VERSION 5.8 ;
BUSBITCHARS "[]" ;
DIVIDERCHAR "/" ;
UNITS
    DATABASE MICRONS 1000 ;
END UNITS

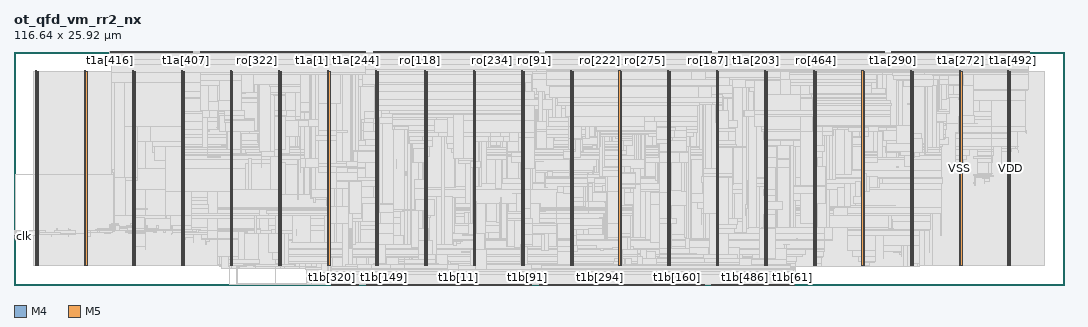
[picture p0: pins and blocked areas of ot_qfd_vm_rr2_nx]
MACRO ot_qfd_vm_rr2_nx
  FOREIGN ot_qfd_vm_rr2_nx 0 0 ;
  CLASS BLOCK ;
  SIZE 116.64 BY 25.92 ;
  PIN clk
    DIRECTION INPUT ;
    USE SIGNAL ;
    PORT
      LAYER M4 ;
        RECT  0 5.424 0.084 5.448 ;
    END
  END clk
  PIN ro[0]
    DIRECTION OUTPUT ;
    USE SIGNAL ;
    PORT
      LAYER M5 ;
        RECT  46.032 25.836 46.056 25.92 ;
    END
  END ro[0]
  PIN ro[100]
    DIRECTION OUTPUT ;
    USE SIGNAL ;
    PORT
      LAYER M5 ;
        RECT  43.344 25.836 43.368 25.92 ;
    END
  END ro[100]
  PIN ro[101]
    DIRECTION OUTPUT ;
    USE SIGNAL ;
    PORT
      LAYER M5 ;
        RECT  43.44 25.836 43.464 25.92 ;
    END
  END ro[101]
  PIN ro[102]
    DIRECTION OUTPUT ;
    USE SIGNAL ;
    PORT
      LAYER M5 ;
        RECT  43.536 25.836 43.56 25.92 ;
    END
  END ro[102]
  PIN ro[103]
    DIRECTION OUTPUT ;
    USE SIGNAL ;
    PORT
      LAYER M5 ;
        RECT  43.632 25.836 43.656 25.92 ;
    END
  END ro[103]
  PIN ro[104]
    DIRECTION OUTPUT ;
    USE SIGNAL ;
    PORT
      LAYER M5 ;
        RECT  43.728 25.836 43.752 25.92 ;
    END
  END ro[104]
  PIN ro[105]
    DIRECTION OUTPUT ;
    USE SIGNAL ;
    PORT
      LAYER M5 ;
        RECT  43.824 25.836 43.848 25.92 ;
    END
  END ro[105]
  PIN ro[106]
    DIRECTION OUTPUT ;
    USE SIGNAL ;
    PORT
      LAYER M5 ;
        RECT  43.92 25.836 43.944 25.92 ;
    END
  END ro[106]
  PIN ro[107]
    DIRECTION OUTPUT ;
    USE SIGNAL ;
    PORT
      LAYER M5 ;
        RECT  44.016 25.836 44.04 25.92 ;
    END
  END ro[107]
  PIN ro[108]
    DIRECTION OUTPUT ;
    USE SIGNAL ;
    PORT
      LAYER M5 ;
        RECT  44.112 25.836 44.136 25.92 ;
    END
  END ro[108]
  PIN ro[109]
    DIRECTION OUTPUT ;
    USE SIGNAL ;
    PORT
      LAYER M5 ;
        RECT  44.208 25.836 44.232 25.92 ;
    END
  END ro[109]
  PIN ro[10]
    DIRECTION OUTPUT ;
    USE SIGNAL ;
    PORT
      LAYER M5 ;
        RECT  46.992 25.836 47.016 25.92 ;
    END
  END ro[10]
  PIN ro[110]
    DIRECTION OUTPUT ;
    USE SIGNAL ;
    PORT
      LAYER M5 ;
        RECT  44.304 25.836 44.328 25.92 ;
    END
  END ro[110]
  PIN ro[111]
    DIRECTION OUTPUT ;
    USE SIGNAL ;
    PORT
      LAYER M5 ;
        RECT  44.4 25.836 44.424 25.92 ;
    END
  END ro[111]
  PIN ro[112]
    DIRECTION OUTPUT ;
    USE SIGNAL ;
    PORT
      LAYER M5 ;
        RECT  44.496 25.836 44.52 25.92 ;
    END
  END ro[112]
  PIN ro[113]
    DIRECTION OUTPUT ;
    USE SIGNAL ;
    PORT
      LAYER M5 ;
        RECT  44.592 25.836 44.616 25.92 ;
    END
  END ro[113]
  PIN ro[114]
    DIRECTION OUTPUT ;
    USE SIGNAL ;
    PORT
      LAYER M5 ;
        RECT  44.688 25.836 44.712 25.92 ;
    END
  END ro[114]
  PIN ro[115]
    DIRECTION OUTPUT ;
    USE SIGNAL ;
    PORT
      LAYER M5 ;
        RECT  44.784 25.836 44.808 25.92 ;
    END
  END ro[115]
  PIN ro[116]
    DIRECTION OUTPUT ;
    USE SIGNAL ;
    PORT
      LAYER M5 ;
        RECT  44.88 25.836 44.904 25.92 ;
    END
  END ro[116]
  PIN ro[117]
    DIRECTION OUTPUT ;
    USE SIGNAL ;
    PORT
      LAYER M5 ;
        RECT  44.976 25.836 45 25.92 ;
    END
  END ro[117]
  PIN ro[118]
    DIRECTION OUTPUT ;
    USE SIGNAL ;
    PORT
      LAYER M5 ;
        RECT  45.072 25.836 45.096 25.92 ;
    END
  END ro[118]
  PIN ro[119]
    DIRECTION OUTPUT ;
    USE SIGNAL ;
    PORT
      LAYER M5 ;
        RECT  45.168 25.836 45.192 25.92 ;
    END
  END ro[119]
  PIN ro[11]
    DIRECTION OUTPUT ;
    USE SIGNAL ;
    PORT
      LAYER M5 ;
        RECT  47.088 25.836 47.112 25.92 ;
    END
  END ro[11]
  PIN ro[120]
    DIRECTION OUTPUT ;
    USE SIGNAL ;
    PORT
      LAYER M5 ;
        RECT  45.264 25.836 45.288 25.92 ;
    END
  END ro[120]
  PIN ro[121]
    DIRECTION OUTPUT ;
    USE SIGNAL ;
    PORT
      LAYER M5 ;
        RECT  45.36 25.836 45.384 25.92 ;
    END
  END ro[121]
  PIN ro[122]
    DIRECTION OUTPUT ;
    USE SIGNAL ;
    PORT
      LAYER M5 ;
        RECT  45.456 25.836 45.48 25.92 ;
    END
  END ro[122]
  PIN ro[123]
    DIRECTION OUTPUT ;
    USE SIGNAL ;
    PORT
      LAYER M5 ;
        RECT  45.552 25.836 45.576 25.92 ;
    END
  END ro[123]
  PIN ro[124]
    DIRECTION OUTPUT ;
    USE SIGNAL ;
    PORT
      LAYER M5 ;
        RECT  45.648 25.836 45.672 25.92 ;
    END
  END ro[124]
  PIN ro[125]
    DIRECTION OUTPUT ;
    USE SIGNAL ;
    PORT
      LAYER M5 ;
        RECT  45.744 25.836 45.768 25.92 ;
    END
  END ro[125]
  PIN ro[126]
    DIRECTION OUTPUT ;
    USE SIGNAL ;
    PORT
      LAYER M5 ;
        RECT  45.84 25.836 45.864 25.92 ;
    END
  END ro[126]
  PIN ro[127]
    DIRECTION OUTPUT ;
    USE SIGNAL ;
    PORT
      LAYER M5 ;
        RECT  45.936 25.836 45.96 25.92 ;
    END
  END ro[127]
  PIN ro[128]
    DIRECTION OUTPUT ;
    USE SIGNAL ;
    PORT
      LAYER M5 ;
        RECT  39.888 25.836 39.912 25.92 ;
    END
  END ro[128]
  PIN ro[129]
    DIRECTION OUTPUT ;
    USE SIGNAL ;
    PORT
      LAYER M5 ;
        RECT  39.984 25.836 40.008 25.92 ;
    END
  END ro[129]
  PIN ro[12]
    DIRECTION OUTPUT ;
    USE SIGNAL ;
    PORT
      LAYER M5 ;
        RECT  47.184 25.836 47.208 25.92 ;
    END
  END ro[12]
  PIN ro[130]
    DIRECTION OUTPUT ;
    USE SIGNAL ;
    PORT
      LAYER M5 ;
        RECT  40.08 25.836 40.104 25.92 ;
    END
  END ro[130]
  PIN ro[131]
    DIRECTION OUTPUT ;
    USE SIGNAL ;
    PORT
      LAYER M5 ;
        RECT  40.176 25.836 40.2 25.92 ;
    END
  END ro[131]
  PIN ro[132]
    DIRECTION OUTPUT ;
    USE SIGNAL ;
    PORT
      LAYER M5 ;
        RECT  40.272 25.836 40.296 25.92 ;
    END
  END ro[132]
  PIN ro[133]
    DIRECTION OUTPUT ;
    USE SIGNAL ;
    PORT
      LAYER M5 ;
        RECT  40.368 25.836 40.392 25.92 ;
    END
  END ro[133]
  PIN ro[134]
    DIRECTION OUTPUT ;
    USE SIGNAL ;
    PORT
      LAYER M5 ;
        RECT  40.464 25.836 40.488 25.92 ;
    END
  END ro[134]
  PIN ro[135]
    DIRECTION OUTPUT ;
    USE SIGNAL ;
    PORT
      LAYER M5 ;
        RECT  40.56 25.836 40.584 25.92 ;
    END
  END ro[135]
  PIN ro[136]
    DIRECTION OUTPUT ;
    USE SIGNAL ;
    PORT
      LAYER M5 ;
        RECT  40.656 25.836 40.68 25.92 ;
    END
  END ro[136]
  PIN ro[137]
    DIRECTION OUTPUT ;
    USE SIGNAL ;
    PORT
      LAYER M5 ;
        RECT  40.752 25.836 40.776 25.92 ;
    END
  END ro[137]
  PIN ro[138]
    DIRECTION OUTPUT ;
    USE SIGNAL ;
    PORT
      LAYER M5 ;
        RECT  40.848 25.836 40.872 25.92 ;
    END
  END ro[138]
  PIN ro[139]
    DIRECTION OUTPUT ;
    USE SIGNAL ;
    PORT
      LAYER M5 ;
        RECT  40.944 25.836 40.968 25.92 ;
    END
  END ro[139]
  PIN ro[13]
    DIRECTION OUTPUT ;
    USE SIGNAL ;
    PORT
      LAYER M5 ;
        RECT  47.28 25.836 47.304 25.92 ;
    END
  END ro[13]
  PIN ro[140]
    DIRECTION OUTPUT ;
    USE SIGNAL ;
    PORT
      LAYER M5 ;
        RECT  41.04 25.836 41.064 25.92 ;
    END
  END ro[140]
  PIN ro[141]
    DIRECTION OUTPUT ;
    USE SIGNAL ;
    PORT
      LAYER M5 ;
        RECT  41.136 25.836 41.16 25.92 ;
    END
  END ro[141]
  PIN ro[142]
    DIRECTION OUTPUT ;
    USE SIGNAL ;
    PORT
      LAYER M5 ;
        RECT  41.232 25.836 41.256 25.92 ;
    END
  END ro[142]
  PIN ro[143]
    DIRECTION OUTPUT ;
    USE SIGNAL ;
    PORT
      LAYER M5 ;
        RECT  41.328 25.836 41.352 25.92 ;
    END
  END ro[143]
  PIN ro[144]
    DIRECTION OUTPUT ;
    USE SIGNAL ;
    PORT
      LAYER M5 ;
        RECT  41.424 25.836 41.448 25.92 ;
    END
  END ro[144]
  PIN ro[145]
    DIRECTION OUTPUT ;
    USE SIGNAL ;
    PORT
      LAYER M5 ;
        RECT  41.52 25.836 41.544 25.92 ;
    END
  END ro[145]
  PIN ro[146]
    DIRECTION OUTPUT ;
    USE SIGNAL ;
    PORT
      LAYER M5 ;
        RECT  41.616 25.836 41.64 25.92 ;
    END
  END ro[146]
  PIN ro[147]
    DIRECTION OUTPUT ;
    USE SIGNAL ;
    PORT
      LAYER M5 ;
        RECT  41.712 25.836 41.736 25.92 ;
    END
  END ro[147]
  PIN ro[148]
    DIRECTION OUTPUT ;
    USE SIGNAL ;
    PORT
      LAYER M5 ;
        RECT  41.808 25.836 41.832 25.92 ;
    END
  END ro[148]
  PIN ro[149]
    DIRECTION OUTPUT ;
    USE SIGNAL ;
    PORT
      LAYER M5 ;
        RECT  41.904 25.836 41.928 25.92 ;
    END
  END ro[149]
  PIN ro[14]
    DIRECTION OUTPUT ;
    USE SIGNAL ;
    PORT
      LAYER M5 ;
        RECT  47.376 25.836 47.4 25.92 ;
    END
  END ro[14]
  PIN ro[150]
    DIRECTION OUTPUT ;
    USE SIGNAL ;
    PORT
      LAYER M5 ;
        RECT  42 25.836 42.024 25.92 ;
    END
  END ro[150]
  PIN ro[151]
    DIRECTION OUTPUT ;
    USE SIGNAL ;
    PORT
      LAYER M5 ;
        RECT  42.096 25.836 42.12 25.92 ;
    END
  END ro[151]
  PIN ro[152]
    DIRECTION OUTPUT ;
    USE SIGNAL ;
    PORT
      LAYER M5 ;
        RECT  42.192 25.836 42.216 25.92 ;
    END
  END ro[152]
  PIN ro[153]
    DIRECTION OUTPUT ;
    USE SIGNAL ;
    PORT
      LAYER M5 ;
        RECT  42.288 25.836 42.312 25.92 ;
    END
  END ro[153]
  PIN ro[154]
    DIRECTION OUTPUT ;
    USE SIGNAL ;
    PORT
      LAYER M5 ;
        RECT  42.384 25.836 42.408 25.92 ;
    END
  END ro[154]
  PIN ro[155]
    DIRECTION OUTPUT ;
    USE SIGNAL ;
    PORT
      LAYER M5 ;
        RECT  42.48 25.836 42.504 25.92 ;
    END
  END ro[155]
  PIN ro[156]
    DIRECTION OUTPUT ;
    USE SIGNAL ;
    PORT
      LAYER M5 ;
        RECT  42.576 25.836 42.6 25.92 ;
    END
  END ro[156]
  PIN ro[157]
    DIRECTION OUTPUT ;
    USE SIGNAL ;
    PORT
      LAYER M5 ;
        RECT  42.672 25.836 42.696 25.92 ;
    END
  END ro[157]
  PIN ro[158]
    DIRECTION OUTPUT ;
    USE SIGNAL ;
    PORT
      LAYER M5 ;
        RECT  42.768 25.836 42.792 25.92 ;
    END
  END ro[158]
  PIN ro[159]
    DIRECTION OUTPUT ;
    USE SIGNAL ;
    PORT
      LAYER M5 ;
        RECT  42.864 25.836 42.888 25.92 ;
    END
  END ro[159]
  PIN ro[15]
    DIRECTION OUTPUT ;
    USE SIGNAL ;
    PORT
      LAYER M5 ;
        RECT  47.472 25.836 47.496 25.92 ;
    END
  END ro[15]
  PIN ro[160]
    DIRECTION OUTPUT ;
    USE SIGNAL ;
    PORT
      LAYER M5 ;
        RECT  74.448 25.836 74.472 25.92 ;
    END
  END ro[160]
  PIN ro[161]
    DIRECTION OUTPUT ;
    USE SIGNAL ;
    PORT
      LAYER M5 ;
        RECT  74.544 25.836 74.568 25.92 ;
    END
  END ro[161]
  PIN ro[162]
    DIRECTION OUTPUT ;
    USE SIGNAL ;
    PORT
      LAYER M5 ;
        RECT  74.64 25.836 74.664 25.92 ;
    END
  END ro[162]
  PIN ro[163]
    DIRECTION OUTPUT ;
    USE SIGNAL ;
    PORT
      LAYER M5 ;
        RECT  74.736 25.836 74.76 25.92 ;
    END
  END ro[163]
  PIN ro[164]
    DIRECTION OUTPUT ;
    USE SIGNAL ;
    PORT
      LAYER M5 ;
        RECT  74.832 25.836 74.856 25.92 ;
    END
  END ro[164]
  PIN ro[165]
    DIRECTION OUTPUT ;
    USE SIGNAL ;
    PORT
      LAYER M5 ;
        RECT  74.928 25.836 74.952 25.92 ;
    END
  END ro[165]
  PIN ro[166]
    DIRECTION OUTPUT ;
    USE SIGNAL ;
    PORT
      LAYER M5 ;
        RECT  75.024 25.836 75.048 25.92 ;
    END
  END ro[166]
  PIN ro[167]
    DIRECTION OUTPUT ;
    USE SIGNAL ;
    PORT
      LAYER M5 ;
        RECT  75.12 25.836 75.144 25.92 ;
    END
  END ro[167]
  PIN ro[168]
    DIRECTION OUTPUT ;
    USE SIGNAL ;
    PORT
      LAYER M5 ;
        RECT  75.216 25.836 75.24 25.92 ;
    END
  END ro[168]
  PIN ro[169]
    DIRECTION OUTPUT ;
    USE SIGNAL ;
    PORT
      LAYER M5 ;
        RECT  75.312 25.836 75.336 25.92 ;
    END
  END ro[169]
  PIN ro[16]
    DIRECTION OUTPUT ;
    USE SIGNAL ;
    PORT
      LAYER M5 ;
        RECT  47.568 25.836 47.592 25.92 ;
    END
  END ro[16]
  PIN ro[170]
    DIRECTION OUTPUT ;
    USE SIGNAL ;
    PORT
      LAYER M5 ;
        RECT  75.408 25.836 75.432 25.92 ;
    END
  END ro[170]
  PIN ro[171]
    DIRECTION OUTPUT ;
    USE SIGNAL ;
    PORT
      LAYER M5 ;
        RECT  75.504 25.836 75.528 25.92 ;
    END
  END ro[171]
  PIN ro[172]
    DIRECTION OUTPUT ;
    USE SIGNAL ;
    PORT
      LAYER M5 ;
        RECT  75.6 25.836 75.624 25.92 ;
    END
  END ro[172]
  PIN ro[173]
    DIRECTION OUTPUT ;
    USE SIGNAL ;
    PORT
      LAYER M5 ;
        RECT  75.696 25.836 75.72 25.92 ;
    END
  END ro[173]
  PIN ro[174]
    DIRECTION OUTPUT ;
    USE SIGNAL ;
    PORT
      LAYER M5 ;
        RECT  75.792 25.836 75.816 25.92 ;
    END
  END ro[174]
  PIN ro[175]
    DIRECTION OUTPUT ;
    USE SIGNAL ;
    PORT
      LAYER M5 ;
        RECT  75.888 25.836 75.912 25.92 ;
    END
  END ro[175]
  PIN ro[176]
    DIRECTION OUTPUT ;
    USE SIGNAL ;
    PORT
      LAYER M5 ;
        RECT  75.984 25.836 76.008 25.92 ;
    END
  END ro[176]
  PIN ro[177]
    DIRECTION OUTPUT ;
    USE SIGNAL ;
    PORT
      LAYER M5 ;
        RECT  76.08 25.836 76.104 25.92 ;
    END
  END ro[177]
  PIN ro[178]
    DIRECTION OUTPUT ;
    USE SIGNAL ;
    PORT
      LAYER M5 ;
        RECT  76.176 25.836 76.2 25.92 ;
    END
  END ro[178]
  PIN ro[179]
    DIRECTION OUTPUT ;
    USE SIGNAL ;
    PORT
      LAYER M5 ;
        RECT  76.272 25.836 76.296 25.92 ;
    END
  END ro[179]
  PIN ro[17]
    DIRECTION OUTPUT ;
    USE SIGNAL ;
    PORT
      LAYER M5 ;
        RECT  47.664 25.836 47.688 25.92 ;
    END
  END ro[17]
  PIN ro[180]
    DIRECTION OUTPUT ;
    USE SIGNAL ;
    PORT
      LAYER M5 ;
        RECT  76.368 25.836 76.392 25.92 ;
    END
  END ro[180]
  PIN ro[181]
    DIRECTION OUTPUT ;
    USE SIGNAL ;
    PORT
      LAYER M5 ;
        RECT  76.464 25.836 76.488 25.92 ;
    END
  END ro[181]
  PIN ro[182]
    DIRECTION OUTPUT ;
    USE SIGNAL ;
    PORT
      LAYER M5 ;
        RECT  76.56 25.836 76.584 25.92 ;
    END
  END ro[182]
  PIN ro[183]
    DIRECTION OUTPUT ;
    USE SIGNAL ;
    PORT
      LAYER M5 ;
        RECT  76.656 25.836 76.68 25.92 ;
    END
  END ro[183]
  PIN ro[184]
    DIRECTION OUTPUT ;
    USE SIGNAL ;
    PORT
      LAYER M5 ;
        RECT  76.752 25.836 76.776 25.92 ;
    END
  END ro[184]
  PIN ro[185]
    DIRECTION OUTPUT ;
    USE SIGNAL ;
    PORT
      LAYER M5 ;
        RECT  76.848 25.836 76.872 25.92 ;
    END
  END ro[185]
  PIN ro[186]
    DIRECTION OUTPUT ;
    USE SIGNAL ;
    PORT
      LAYER M5 ;
        RECT  76.944 25.836 76.968 25.92 ;
    END
  END ro[186]
  PIN ro[187]
    DIRECTION OUTPUT ;
    USE SIGNAL ;
    PORT
      LAYER M5 ;
        RECT  77.04 25.836 77.064 25.92 ;
    END
  END ro[187]
  PIN ro[188]
    DIRECTION OUTPUT ;
    USE SIGNAL ;
    PORT
      LAYER M5 ;
        RECT  77.136 25.836 77.16 25.92 ;
    END
  END ro[188]
  PIN ro[189]
    DIRECTION OUTPUT ;
    USE SIGNAL ;
    PORT
      LAYER M5 ;
        RECT  77.232 25.836 77.256 25.92 ;
    END
  END ro[189]
  PIN ro[18]
    DIRECTION OUTPUT ;
    USE SIGNAL ;
    PORT
      LAYER M5 ;
        RECT  47.76 25.836 47.784 25.92 ;
    END
  END ro[18]
  PIN ro[190]
    DIRECTION OUTPUT ;
    USE SIGNAL ;
    PORT
      LAYER M5 ;
        RECT  77.328 25.836 77.352 25.92 ;
    END
  END ro[190]
  PIN ro[191]
    DIRECTION OUTPUT ;
    USE SIGNAL ;
    PORT
      LAYER M5 ;
        RECT  77.424 25.836 77.448 25.92 ;
    END
  END ro[191]
  PIN ro[192]
    DIRECTION OUTPUT ;
    USE SIGNAL ;
    PORT
      LAYER M5 ;
        RECT  62.16 25.836 62.184 25.92 ;
    END
  END ro[192]
  PIN ro[193]
    DIRECTION OUTPUT ;
    USE SIGNAL ;
    PORT
      LAYER M5 ;
        RECT  62.256 25.836 62.28 25.92 ;
    END
  END ro[193]
  PIN ro[194]
    DIRECTION OUTPUT ;
    USE SIGNAL ;
    PORT
      LAYER M5 ;
        RECT  62.352 25.836 62.376 25.92 ;
    END
  END ro[194]
  PIN ro[195]
    DIRECTION OUTPUT ;
    USE SIGNAL ;
    PORT
      LAYER M5 ;
        RECT  62.448 25.836 62.472 25.92 ;
    END
  END ro[195]
  PIN ro[196]
    DIRECTION OUTPUT ;
    USE SIGNAL ;
    PORT
      LAYER M5 ;
        RECT  62.544 25.836 62.568 25.92 ;
    END
  END ro[196]
  PIN ro[197]
    DIRECTION OUTPUT ;
    USE SIGNAL ;
    PORT
      LAYER M5 ;
        RECT  62.64 25.836 62.664 25.92 ;
    END
  END ro[197]
  PIN ro[198]
    DIRECTION OUTPUT ;
    USE SIGNAL ;
    PORT
      LAYER M5 ;
        RECT  62.736 25.836 62.76 25.92 ;
    END
  END ro[198]
  PIN ro[199]
    DIRECTION OUTPUT ;
    USE SIGNAL ;
    PORT
      LAYER M5 ;
        RECT  62.832 25.836 62.856 25.92 ;
    END
  END ro[199]
  PIN ro[19]
    DIRECTION OUTPUT ;
    USE SIGNAL ;
    PORT
      LAYER M5 ;
        RECT  47.856 25.836 47.88 25.92 ;
    END
  END ro[19]
  PIN ro[1]
    DIRECTION OUTPUT ;
    USE SIGNAL ;
    PORT
      LAYER M5 ;
        RECT  46.128 25.836 46.152 25.92 ;
    END
  END ro[1]
  PIN ro[200]
    DIRECTION OUTPUT ;
    USE SIGNAL ;
    PORT
      LAYER M5 ;
        RECT  62.928 25.836 62.952 25.92 ;
    END
  END ro[200]
  PIN ro[201]
    DIRECTION OUTPUT ;
    USE SIGNAL ;
    PORT
      LAYER M5 ;
        RECT  63.024 25.836 63.048 25.92 ;
    END
  END ro[201]
  PIN ro[202]
    DIRECTION OUTPUT ;
    USE SIGNAL ;
    PORT
      LAYER M5 ;
        RECT  63.12 25.836 63.144 25.92 ;
    END
  END ro[202]
  PIN ro[203]
    DIRECTION OUTPUT ;
    USE SIGNAL ;
    PORT
      LAYER M5 ;
        RECT  63.216 25.836 63.24 25.92 ;
    END
  END ro[203]
  PIN ro[204]
    DIRECTION OUTPUT ;
    USE SIGNAL ;
    PORT
      LAYER M5 ;
        RECT  63.312 25.836 63.336 25.92 ;
    END
  END ro[204]
  PIN ro[205]
    DIRECTION OUTPUT ;
    USE SIGNAL ;
    PORT
      LAYER M5 ;
        RECT  63.408 25.836 63.432 25.92 ;
    END
  END ro[205]
  PIN ro[206]
    DIRECTION OUTPUT ;
    USE SIGNAL ;
    PORT
      LAYER M5 ;
        RECT  63.504 25.836 63.528 25.92 ;
    END
  END ro[206]
  PIN ro[207]
    DIRECTION OUTPUT ;
    USE SIGNAL ;
    PORT
      LAYER M5 ;
        RECT  63.6 25.836 63.624 25.92 ;
    END
  END ro[207]
  PIN ro[208]
    DIRECTION OUTPUT ;
    USE SIGNAL ;
    PORT
      LAYER M5 ;
        RECT  63.696 25.836 63.72 25.92 ;
    END
  END ro[208]
  PIN ro[209]
    DIRECTION OUTPUT ;
    USE SIGNAL ;
    PORT
      LAYER M5 ;
        RECT  63.792 25.836 63.816 25.92 ;
    END
  END ro[209]
  PIN ro[20]
    DIRECTION OUTPUT ;
    USE SIGNAL ;
    PORT
      LAYER M5 ;
        RECT  47.952 25.836 47.976 25.92 ;
    END
  END ro[20]
  PIN ro[210]
    DIRECTION OUTPUT ;
    USE SIGNAL ;
    PORT
      LAYER M5 ;
        RECT  63.888 25.836 63.912 25.92 ;
    END
  END ro[210]
  PIN ro[211]
    DIRECTION OUTPUT ;
    USE SIGNAL ;
    PORT
      LAYER M5 ;
        RECT  63.984 25.836 64.008 25.92 ;
    END
  END ro[211]
  PIN ro[212]
    DIRECTION OUTPUT ;
    USE SIGNAL ;
    PORT
      LAYER M5 ;
        RECT  64.08 25.836 64.104 25.92 ;
    END
  END ro[212]
  PIN ro[213]
    DIRECTION OUTPUT ;
    USE SIGNAL ;
    PORT
      LAYER M5 ;
        RECT  64.176 25.836 64.2 25.92 ;
    END
  END ro[213]
  PIN ro[214]
    DIRECTION OUTPUT ;
    USE SIGNAL ;
    PORT
      LAYER M5 ;
        RECT  64.272 25.836 64.296 25.92 ;
    END
  END ro[214]
  PIN ro[215]
    DIRECTION OUTPUT ;
    USE SIGNAL ;
    PORT
      LAYER M5 ;
        RECT  64.368 25.836 64.392 25.92 ;
    END
  END ro[215]
  PIN ro[216]
    DIRECTION OUTPUT ;
    USE SIGNAL ;
    PORT
      LAYER M5 ;
        RECT  64.464 25.836 64.488 25.92 ;
    END
  END ro[216]
  PIN ro[217]
    DIRECTION OUTPUT ;
    USE SIGNAL ;
    PORT
      LAYER M5 ;
        RECT  64.56 25.836 64.584 25.92 ;
    END
  END ro[217]
  PIN ro[218]
    DIRECTION OUTPUT ;
    USE SIGNAL ;
    PORT
      LAYER M5 ;
        RECT  64.656 25.836 64.68 25.92 ;
    END
  END ro[218]
  PIN ro[219]
    DIRECTION OUTPUT ;
    USE SIGNAL ;
    PORT
      LAYER M5 ;
        RECT  64.752 25.836 64.776 25.92 ;
    END
  END ro[219]
  PIN ro[21]
    DIRECTION OUTPUT ;
    USE SIGNAL ;
    PORT
      LAYER M5 ;
        RECT  48.048 25.836 48.072 25.92 ;
    END
  END ro[21]
  PIN ro[220]
    DIRECTION OUTPUT ;
    USE SIGNAL ;
    PORT
      LAYER M5 ;
        RECT  64.848 25.836 64.872 25.92 ;
    END
  END ro[220]
  PIN ro[221]
    DIRECTION OUTPUT ;
    USE SIGNAL ;
    PORT
      LAYER M5 ;
        RECT  64.944 25.836 64.968 25.92 ;
    END
  END ro[221]
  PIN ro[222]
    DIRECTION OUTPUT ;
    USE SIGNAL ;
    PORT
      LAYER M5 ;
        RECT  65.04 25.836 65.064 25.92 ;
    END
  END ro[222]
  PIN ro[223]
    DIRECTION OUTPUT ;
    USE SIGNAL ;
    PORT
      LAYER M5 ;
        RECT  65.136 25.836 65.16 25.92 ;
    END
  END ro[223]
  PIN ro[224]
    DIRECTION OUTPUT ;
    USE SIGNAL ;
    PORT
      LAYER M5 ;
        RECT  52.176 25.836 52.2 25.92 ;
    END
  END ro[224]
  PIN ro[225]
    DIRECTION OUTPUT ;
    USE SIGNAL ;
    PORT
      LAYER M5 ;
        RECT  52.272 25.836 52.296 25.92 ;
    END
  END ro[225]
  PIN ro[226]
    DIRECTION OUTPUT ;
    USE SIGNAL ;
    PORT
      LAYER M5 ;
        RECT  52.368 25.836 52.392 25.92 ;
    END
  END ro[226]
  PIN ro[227]
    DIRECTION OUTPUT ;
    USE SIGNAL ;
    PORT
      LAYER M5 ;
        RECT  52.464 25.836 52.488 25.92 ;
    END
  END ro[227]
  PIN ro[228]
    DIRECTION OUTPUT ;
    USE SIGNAL ;
    PORT
      LAYER M5 ;
        RECT  52.56 25.836 52.584 25.92 ;
    END
  END ro[228]
  PIN ro[229]
    DIRECTION OUTPUT ;
    USE SIGNAL ;
    PORT
      LAYER M5 ;
        RECT  52.656 25.836 52.68 25.92 ;
    END
  END ro[229]
  PIN ro[22]
    DIRECTION OUTPUT ;
    USE SIGNAL ;
    PORT
      LAYER M5 ;
        RECT  48.144 25.836 48.168 25.92 ;
    END
  END ro[22]
  PIN ro[230]
    DIRECTION OUTPUT ;
    USE SIGNAL ;
    PORT
      LAYER M5 ;
        RECT  52.752 25.836 52.776 25.92 ;
    END
  END ro[230]
  PIN ro[231]
    DIRECTION OUTPUT ;
    USE SIGNAL ;
    PORT
      LAYER M5 ;
        RECT  52.848 25.836 52.872 25.92 ;
    END
  END ro[231]
  PIN ro[232]
    DIRECTION OUTPUT ;
    USE SIGNAL ;
    PORT
      LAYER M5 ;
        RECT  52.944 25.836 52.968 25.92 ;
    END
  END ro[232]
  PIN ro[233]
    DIRECTION OUTPUT ;
    USE SIGNAL ;
    PORT
      LAYER M5 ;
        RECT  53.04 25.836 53.064 25.92 ;
    END
  END ro[233]
  PIN ro[234]
    DIRECTION OUTPUT ;
    USE SIGNAL ;
    PORT
      LAYER M5 ;
        RECT  53.136 25.836 53.16 25.92 ;
    END
  END ro[234]
  PIN ro[235]
    DIRECTION OUTPUT ;
    USE SIGNAL ;
    PORT
      LAYER M5 ;
        RECT  53.232 25.836 53.256 25.92 ;
    END
  END ro[235]
  PIN ro[236]
    DIRECTION OUTPUT ;
    USE SIGNAL ;
    PORT
      LAYER M5 ;
        RECT  53.328 25.836 53.352 25.92 ;
    END
  END ro[236]
  PIN ro[237]
    DIRECTION OUTPUT ;
    USE SIGNAL ;
    PORT
      LAYER M5 ;
        RECT  53.424 25.836 53.448 25.92 ;
    END
  END ro[237]
  PIN ro[238]
    DIRECTION OUTPUT ;
    USE SIGNAL ;
    PORT
      LAYER M5 ;
        RECT  53.52 25.836 53.544 25.92 ;
    END
  END ro[238]
  PIN ro[239]
    DIRECTION OUTPUT ;
    USE SIGNAL ;
    PORT
      LAYER M5 ;
        RECT  53.616 25.836 53.64 25.92 ;
    END
  END ro[239]
  PIN ro[23]
    DIRECTION OUTPUT ;
    USE SIGNAL ;
    PORT
      LAYER M5 ;
        RECT  48.24 25.836 48.264 25.92 ;
    END
  END ro[23]
  PIN ro[240]
    DIRECTION OUTPUT ;
    USE SIGNAL ;
    PORT
      LAYER M5 ;
        RECT  53.712 25.836 53.736 25.92 ;
    END
  END ro[240]
  PIN ro[241]
    DIRECTION OUTPUT ;
    USE SIGNAL ;
    PORT
      LAYER M5 ;
        RECT  53.808 25.836 53.832 25.92 ;
    END
  END ro[241]
  PIN ro[242]
    DIRECTION OUTPUT ;
    USE SIGNAL ;
    PORT
      LAYER M5 ;
        RECT  53.904 25.836 53.928 25.92 ;
    END
  END ro[242]
  PIN ro[243]
    DIRECTION OUTPUT ;
    USE SIGNAL ;
    PORT
      LAYER M5 ;
        RECT  54 25.836 54.024 25.92 ;
    END
  END ro[243]
  PIN ro[244]
    DIRECTION OUTPUT ;
    USE SIGNAL ;
    PORT
      LAYER M5 ;
        RECT  54.096 25.836 54.12 25.92 ;
    END
  END ro[244]
  PIN ro[245]
    DIRECTION OUTPUT ;
    USE SIGNAL ;
    PORT
      LAYER M5 ;
        RECT  54.192 25.836 54.216 25.92 ;
    END
  END ro[245]
  PIN ro[246]
    DIRECTION OUTPUT ;
    USE SIGNAL ;
    PORT
      LAYER M5 ;
        RECT  54.288 25.836 54.312 25.92 ;
    END
  END ro[246]
  PIN ro[247]
    DIRECTION OUTPUT ;
    USE SIGNAL ;
    PORT
      LAYER M5 ;
        RECT  54.384 25.836 54.408 25.92 ;
    END
  END ro[247]
  PIN ro[248]
    DIRECTION OUTPUT ;
    USE SIGNAL ;
    PORT
      LAYER M5 ;
        RECT  54.48 25.836 54.504 25.92 ;
    END
  END ro[248]
  PIN ro[249]
    DIRECTION OUTPUT ;
    USE SIGNAL ;
    PORT
      LAYER M5 ;
        RECT  54.576 25.836 54.6 25.92 ;
    END
  END ro[249]
  PIN ro[24]
    DIRECTION OUTPUT ;
    USE SIGNAL ;
    PORT
      LAYER M5 ;
        RECT  48.336 25.836 48.36 25.92 ;
    END
  END ro[24]
  PIN ro[250]
    DIRECTION OUTPUT ;
    USE SIGNAL ;
    PORT
      LAYER M5 ;
        RECT  54.672 25.836 54.696 25.92 ;
    END
  END ro[250]
  PIN ro[251]
    DIRECTION OUTPUT ;
    USE SIGNAL ;
    PORT
      LAYER M5 ;
        RECT  54.768 25.836 54.792 25.92 ;
    END
  END ro[251]
  PIN ro[252]
    DIRECTION OUTPUT ;
    USE SIGNAL ;
    PORT
      LAYER M5 ;
        RECT  54.864 25.836 54.888 25.92 ;
    END
  END ro[252]
  PIN ro[253]
    DIRECTION OUTPUT ;
    USE SIGNAL ;
    PORT
      LAYER M5 ;
        RECT  54.96 25.836 54.984 25.92 ;
    END
  END ro[253]
  PIN ro[254]
    DIRECTION OUTPUT ;
    USE SIGNAL ;
    PORT
      LAYER M5 ;
        RECT  55.056 25.836 55.08 25.92 ;
    END
  END ro[254]
  PIN ro[255]
    DIRECTION OUTPUT ;
    USE SIGNAL ;
    PORT
      LAYER M5 ;
        RECT  55.152 25.836 55.176 25.92 ;
    END
  END ro[255]
  PIN ro[256]
    DIRECTION OUTPUT ;
    USE SIGNAL ;
    PORT
      LAYER M5 ;
        RECT  68.304 25.836 68.328 25.92 ;
    END
  END ro[256]
  PIN ro[257]
    DIRECTION OUTPUT ;
    USE SIGNAL ;
    PORT
      LAYER M5 ;
        RECT  68.4 25.836 68.424 25.92 ;
    END
  END ro[257]
  PIN ro[258]
    DIRECTION OUTPUT ;
    USE SIGNAL ;
    PORT
      LAYER M5 ;
        RECT  68.496 25.836 68.52 25.92 ;
    END
  END ro[258]
  PIN ro[259]
    DIRECTION OUTPUT ;
    USE SIGNAL ;
    PORT
      LAYER M5 ;
        RECT  68.592 25.836 68.616 25.92 ;
    END
  END ro[259]
  PIN ro[25]
    DIRECTION OUTPUT ;
    USE SIGNAL ;
    PORT
      LAYER M5 ;
        RECT  48.432 25.836 48.456 25.92 ;
    END
  END ro[25]
  PIN ro[260]
    DIRECTION OUTPUT ;
    USE SIGNAL ;
    PORT
      LAYER M5 ;
        RECT  68.688 25.836 68.712 25.92 ;
    END
  END ro[260]
  PIN ro[261]
    DIRECTION OUTPUT ;
    USE SIGNAL ;
    PORT
      LAYER M5 ;
        RECT  68.784 25.836 68.808 25.92 ;
    END
  END ro[261]
  PIN ro[262]
    DIRECTION OUTPUT ;
    USE SIGNAL ;
    PORT
      LAYER M5 ;
        RECT  68.88 25.836 68.904 25.92 ;
    END
  END ro[262]
  PIN ro[263]
    DIRECTION OUTPUT ;
    USE SIGNAL ;
    PORT
      LAYER M5 ;
        RECT  68.976 25.836 69 25.92 ;
    END
  END ro[263]
  PIN ro[264]
    DIRECTION OUTPUT ;
    USE SIGNAL ;
    PORT
      LAYER M5 ;
        RECT  69.072 25.836 69.096 25.92 ;
    END
  END ro[264]
  PIN ro[265]
    DIRECTION OUTPUT ;
    USE SIGNAL ;
    PORT
      LAYER M5 ;
        RECT  69.168 25.836 69.192 25.92 ;
    END
  END ro[265]
  PIN ro[266]
    DIRECTION OUTPUT ;
    USE SIGNAL ;
    PORT
      LAYER M5 ;
        RECT  69.264 25.836 69.288 25.92 ;
    END
  END ro[266]
  PIN ro[267]
    DIRECTION OUTPUT ;
    USE SIGNAL ;
    PORT
      LAYER M5 ;
        RECT  69.36 25.836 69.384 25.92 ;
    END
  END ro[267]
  PIN ro[268]
    DIRECTION OUTPUT ;
    USE SIGNAL ;
    PORT
      LAYER M5 ;
        RECT  69.456 25.836 69.48 25.92 ;
    END
  END ro[268]
  PIN ro[269]
    DIRECTION OUTPUT ;
    USE SIGNAL ;
    PORT
      LAYER M5 ;
        RECT  69.552 25.836 69.576 25.92 ;
    END
  END ro[269]
  PIN ro[26]
    DIRECTION OUTPUT ;
    USE SIGNAL ;
    PORT
      LAYER M5 ;
        RECT  48.528 25.836 48.552 25.92 ;
    END
  END ro[26]
  PIN ro[270]
    DIRECTION OUTPUT ;
    USE SIGNAL ;
    PORT
      LAYER M5 ;
        RECT  69.648 25.836 69.672 25.92 ;
    END
  END ro[270]
  PIN ro[271]
    DIRECTION OUTPUT ;
    USE SIGNAL ;
    PORT
      LAYER M5 ;
        RECT  69.744 25.836 69.768 25.92 ;
    END
  END ro[271]
  PIN ro[272]
    DIRECTION OUTPUT ;
    USE SIGNAL ;
    PORT
      LAYER M5 ;
        RECT  69.84 25.836 69.864 25.92 ;
    END
  END ro[272]
  PIN ro[273]
    DIRECTION OUTPUT ;
    USE SIGNAL ;
    PORT
      LAYER M5 ;
        RECT  69.936 25.836 69.96 25.92 ;
    END
  END ro[273]
  PIN ro[274]
    DIRECTION OUTPUT ;
    USE SIGNAL ;
    PORT
      LAYER M5 ;
        RECT  70.032 25.836 70.056 25.92 ;
    END
  END ro[274]
  PIN ro[275]
    DIRECTION OUTPUT ;
    USE SIGNAL ;
    PORT
      LAYER M5 ;
        RECT  70.128 25.836 70.152 25.92 ;
    END
  END ro[275]
  PIN ro[276]
    DIRECTION OUTPUT ;
    USE SIGNAL ;
    PORT
      LAYER M5 ;
        RECT  70.224 25.836 70.248 25.92 ;
    END
  END ro[276]
  PIN ro[277]
    DIRECTION OUTPUT ;
    USE SIGNAL ;
    PORT
      LAYER M5 ;
        RECT  70.32 25.836 70.344 25.92 ;
    END
  END ro[277]
  PIN ro[278]
    DIRECTION OUTPUT ;
    USE SIGNAL ;
    PORT
      LAYER M5 ;
        RECT  70.416 25.836 70.44 25.92 ;
    END
  END ro[278]
  PIN ro[279]
    DIRECTION OUTPUT ;
    USE SIGNAL ;
    PORT
      LAYER M5 ;
        RECT  70.512 25.836 70.536 25.92 ;
    END
  END ro[279]
  PIN ro[27]
    DIRECTION OUTPUT ;
    USE SIGNAL ;
    PORT
      LAYER M5 ;
        RECT  48.624 25.836 48.648 25.92 ;
    END
  END ro[27]
  PIN ro[280]
    DIRECTION OUTPUT ;
    USE SIGNAL ;
    PORT
      LAYER M5 ;
        RECT  70.608 25.836 70.632 25.92 ;
    END
  END ro[280]
  PIN ro[281]
    DIRECTION OUTPUT ;
    USE SIGNAL ;
    PORT
      LAYER M5 ;
        RECT  70.704 25.836 70.728 25.92 ;
    END
  END ro[281]
  PIN ro[282]
    DIRECTION OUTPUT ;
    USE SIGNAL ;
    PORT
      LAYER M5 ;
        RECT  70.8 25.836 70.824 25.92 ;
    END
  END ro[282]
  PIN ro[283]
    DIRECTION OUTPUT ;
    USE SIGNAL ;
    PORT
      LAYER M5 ;
        RECT  70.896 25.836 70.92 25.92 ;
    END
  END ro[283]
  PIN ro[284]
    DIRECTION OUTPUT ;
    USE SIGNAL ;
    PORT
      LAYER M5 ;
        RECT  70.992 25.836 71.016 25.92 ;
    END
  END ro[284]
  PIN ro[285]
    DIRECTION OUTPUT ;
    USE SIGNAL ;
    PORT
      LAYER M5 ;
        RECT  71.088 25.836 71.112 25.92 ;
    END
  END ro[285]
  PIN ro[286]
    DIRECTION OUTPUT ;
    USE SIGNAL ;
    PORT
      LAYER M5 ;
        RECT  71.184 25.836 71.208 25.92 ;
    END
  END ro[286]
  PIN ro[287]
    DIRECTION OUTPUT ;
    USE SIGNAL ;
    PORT
      LAYER M5 ;
        RECT  71.28 25.836 71.304 25.92 ;
    END
  END ro[287]
  PIN ro[288]
    DIRECTION OUTPUT ;
    USE SIGNAL ;
    PORT
      LAYER M5 ;
        RECT  65.232 25.836 65.256 25.92 ;
    END
  END ro[288]
  PIN ro[289]
    DIRECTION OUTPUT ;
    USE SIGNAL ;
    PORT
      LAYER M5 ;
        RECT  65.328 25.836 65.352 25.92 ;
    END
  END ro[289]
  PIN ro[28]
    DIRECTION OUTPUT ;
    USE SIGNAL ;
    PORT
      LAYER M5 ;
        RECT  48.72 25.836 48.744 25.92 ;
    END
  END ro[28]
  PIN ro[290]
    DIRECTION OUTPUT ;
    USE SIGNAL ;
    PORT
      LAYER M5 ;
        RECT  65.424 25.836 65.448 25.92 ;
    END
  END ro[290]
  PIN ro[291]
    DIRECTION OUTPUT ;
    USE SIGNAL ;
    PORT
      LAYER M5 ;
        RECT  65.52 25.836 65.544 25.92 ;
    END
  END ro[291]
  PIN ro[292]
    DIRECTION OUTPUT ;
    USE SIGNAL ;
    PORT
      LAYER M5 ;
        RECT  65.616 25.836 65.64 25.92 ;
    END
  END ro[292]
  PIN ro[293]
    DIRECTION OUTPUT ;
    USE SIGNAL ;
    PORT
      LAYER M5 ;
        RECT  65.712 25.836 65.736 25.92 ;
    END
  END ro[293]
  PIN ro[294]
    DIRECTION OUTPUT ;
    USE SIGNAL ;
    PORT
      LAYER M5 ;
        RECT  65.808 25.836 65.832 25.92 ;
    END
  END ro[294]
  PIN ro[295]
    DIRECTION OUTPUT ;
    USE SIGNAL ;
    PORT
      LAYER M5 ;
        RECT  65.904 25.836 65.928 25.92 ;
    END
  END ro[295]
  PIN ro[296]
    DIRECTION OUTPUT ;
    USE SIGNAL ;
    PORT
      LAYER M5 ;
        RECT  66 25.836 66.024 25.92 ;
    END
  END ro[296]
  PIN ro[297]
    DIRECTION OUTPUT ;
    USE SIGNAL ;
    PORT
      LAYER M5 ;
        RECT  66.096 25.836 66.12 25.92 ;
    END
  END ro[297]
  PIN ro[298]
    DIRECTION OUTPUT ;
    USE SIGNAL ;
    PORT
      LAYER M5 ;
        RECT  66.192 25.836 66.216 25.92 ;
    END
  END ro[298]
  PIN ro[299]
    DIRECTION OUTPUT ;
    USE SIGNAL ;
    PORT
      LAYER M5 ;
        RECT  66.288 25.836 66.312 25.92 ;
    END
  END ro[299]
  PIN ro[29]
    DIRECTION OUTPUT ;
    USE SIGNAL ;
    PORT
      LAYER M5 ;
        RECT  48.816 25.836 48.84 25.92 ;
    END
  END ro[29]
  PIN ro[2]
    DIRECTION OUTPUT ;
    USE SIGNAL ;
    PORT
      LAYER M5 ;
        RECT  46.224 25.836 46.248 25.92 ;
    END
  END ro[2]
  PIN ro[300]
    DIRECTION OUTPUT ;
    USE SIGNAL ;
    PORT
      LAYER M5 ;
        RECT  66.384 25.836 66.408 25.92 ;
    END
  END ro[300]
  PIN ro[301]
    DIRECTION OUTPUT ;
    USE SIGNAL ;
    PORT
      LAYER M5 ;
        RECT  66.48 25.836 66.504 25.92 ;
    END
  END ro[301]
  PIN ro[302]
    DIRECTION OUTPUT ;
    USE SIGNAL ;
    PORT
      LAYER M5 ;
        RECT  66.576 25.836 66.6 25.92 ;
    END
  END ro[302]
  PIN ro[303]
    DIRECTION OUTPUT ;
    USE SIGNAL ;
    PORT
      LAYER M5 ;
        RECT  66.672 25.836 66.696 25.92 ;
    END
  END ro[303]
  PIN ro[304]
    DIRECTION OUTPUT ;
    USE SIGNAL ;
    PORT
      LAYER M5 ;
        RECT  66.768 25.836 66.792 25.92 ;
    END
  END ro[304]
  PIN ro[305]
    DIRECTION OUTPUT ;
    USE SIGNAL ;
    PORT
      LAYER M5 ;
        RECT  66.864 25.836 66.888 25.92 ;
    END
  END ro[305]
  PIN ro[306]
    DIRECTION OUTPUT ;
    USE SIGNAL ;
    PORT
      LAYER M5 ;
        RECT  66.96 25.836 66.984 25.92 ;
    END
  END ro[306]
  PIN ro[307]
    DIRECTION OUTPUT ;
    USE SIGNAL ;
    PORT
      LAYER M5 ;
        RECT  67.056 25.836 67.08 25.92 ;
    END
  END ro[307]
  PIN ro[308]
    DIRECTION OUTPUT ;
    USE SIGNAL ;
    PORT
      LAYER M5 ;
        RECT  67.152 25.836 67.176 25.92 ;
    END
  END ro[308]
  PIN ro[309]
    DIRECTION OUTPUT ;
    USE SIGNAL ;
    PORT
      LAYER M5 ;
        RECT  67.248 25.836 67.272 25.92 ;
    END
  END ro[309]
  PIN ro[30]
    DIRECTION OUTPUT ;
    USE SIGNAL ;
    PORT
      LAYER M5 ;
        RECT  48.912 25.836 48.936 25.92 ;
    END
  END ro[30]
  PIN ro[310]
    DIRECTION OUTPUT ;
    USE SIGNAL ;
    PORT
      LAYER M5 ;
        RECT  67.344 25.836 67.368 25.92 ;
    END
  END ro[310]
  PIN ro[311]
    DIRECTION OUTPUT ;
    USE SIGNAL ;
    PORT
      LAYER M5 ;
        RECT  67.44 25.836 67.464 25.92 ;
    END
  END ro[311]
  PIN ro[312]
    DIRECTION OUTPUT ;
    USE SIGNAL ;
    PORT
      LAYER M5 ;
        RECT  67.536 25.836 67.56 25.92 ;
    END
  END ro[312]
  PIN ro[313]
    DIRECTION OUTPUT ;
    USE SIGNAL ;
    PORT
      LAYER M5 ;
        RECT  67.632 25.836 67.656 25.92 ;
    END
  END ro[313]
  PIN ro[314]
    DIRECTION OUTPUT ;
    USE SIGNAL ;
    PORT
      LAYER M5 ;
        RECT  67.728 25.836 67.752 25.92 ;
    END
  END ro[314]
  PIN ro[315]
    DIRECTION OUTPUT ;
    USE SIGNAL ;
    PORT
      LAYER M5 ;
        RECT  67.824 25.836 67.848 25.92 ;
    END
  END ro[315]
  PIN ro[316]
    DIRECTION OUTPUT ;
    USE SIGNAL ;
    PORT
      LAYER M5 ;
        RECT  67.92 25.836 67.944 25.92 ;
    END
  END ro[316]
  PIN ro[317]
    DIRECTION OUTPUT ;
    USE SIGNAL ;
    PORT
      LAYER M5 ;
        RECT  68.016 25.836 68.04 25.92 ;
    END
  END ro[317]
  PIN ro[318]
    DIRECTION OUTPUT ;
    USE SIGNAL ;
    PORT
      LAYER M5 ;
        RECT  68.112 25.836 68.136 25.92 ;
    END
  END ro[318]
  PIN ro[319]
    DIRECTION OUTPUT ;
    USE SIGNAL ;
    PORT
      LAYER M5 ;
        RECT  68.208 25.836 68.232 25.92 ;
    END
  END ro[319]
  PIN ro[31]
    DIRECTION OUTPUT ;
    USE SIGNAL ;
    PORT
      LAYER M5 ;
        RECT  49.008 25.836 49.032 25.92 ;
    END
  END ro[31]
  PIN ro[320]
    DIRECTION OUTPUT ;
    USE SIGNAL ;
    PORT
      LAYER M5 ;
        RECT  26.832 25.836 26.856 25.92 ;
    END
  END ro[320]
  PIN ro[321]
    DIRECTION OUTPUT ;
    USE SIGNAL ;
    PORT
      LAYER M5 ;
        RECT  26.928 25.836 26.952 25.92 ;
    END
  END ro[321]
  PIN ro[322]
    DIRECTION OUTPUT ;
    USE SIGNAL ;
    PORT
      LAYER M5 ;
        RECT  27.024 25.836 27.048 25.92 ;
    END
  END ro[322]
  PIN ro[323]
    DIRECTION OUTPUT ;
    USE SIGNAL ;
    PORT
      LAYER M5 ;
        RECT  27.12 25.836 27.144 25.92 ;
    END
  END ro[323]
  PIN ro[324]
    DIRECTION OUTPUT ;
    USE SIGNAL ;
    PORT
      LAYER M5 ;
        RECT  27.216 25.836 27.24 25.92 ;
    END
  END ro[324]
  PIN ro[325]
    DIRECTION OUTPUT ;
    USE SIGNAL ;
    PORT
      LAYER M5 ;
        RECT  27.312 25.836 27.336 25.92 ;
    END
  END ro[325]
  PIN ro[326]
    DIRECTION OUTPUT ;
    USE SIGNAL ;
    PORT
      LAYER M5 ;
        RECT  27.408 25.836 27.432 25.92 ;
    END
  END ro[326]
  PIN ro[327]
    DIRECTION OUTPUT ;
    USE SIGNAL ;
    PORT
      LAYER M5 ;
        RECT  27.504 25.836 27.528 25.92 ;
    END
  END ro[327]
  PIN ro[328]
    DIRECTION OUTPUT ;
    USE SIGNAL ;
    PORT
      LAYER M5 ;
        RECT  27.6 25.836 27.624 25.92 ;
    END
  END ro[328]
  PIN ro[329]
    DIRECTION OUTPUT ;
    USE SIGNAL ;
    PORT
      LAYER M5 ;
        RECT  27.696 25.836 27.72 25.92 ;
    END
  END ro[329]
  PIN ro[32]
    DIRECTION OUTPUT ;
    USE SIGNAL ;
    PORT
      LAYER M5 ;
        RECT  90.576 25.836 90.6 25.92 ;
    END
  END ro[32]
  PIN ro[330]
    DIRECTION OUTPUT ;
    USE SIGNAL ;
    PORT
      LAYER M5 ;
        RECT  27.792 25.836 27.816 25.92 ;
    END
  END ro[330]
  PIN ro[331]
    DIRECTION OUTPUT ;
    USE SIGNAL ;
    PORT
      LAYER M5 ;
        RECT  27.888 25.836 27.912 25.92 ;
    END
  END ro[331]
  PIN ro[332]
    DIRECTION OUTPUT ;
    USE SIGNAL ;
    PORT
      LAYER M5 ;
        RECT  27.984 25.836 28.008 25.92 ;
    END
  END ro[332]
  PIN ro[333]
    DIRECTION OUTPUT ;
    USE SIGNAL ;
    PORT
      LAYER M5 ;
        RECT  28.08 25.836 28.104 25.92 ;
    END
  END ro[333]
  PIN ro[334]
    DIRECTION OUTPUT ;
    USE SIGNAL ;
    PORT
      LAYER M5 ;
        RECT  28.176 25.836 28.2 25.92 ;
    END
  END ro[334]
  PIN ro[335]
    DIRECTION OUTPUT ;
    USE SIGNAL ;
    PORT
      LAYER M5 ;
        RECT  28.272 25.836 28.296 25.92 ;
    END
  END ro[335]
  PIN ro[336]
    DIRECTION OUTPUT ;
    USE SIGNAL ;
    PORT
      LAYER M5 ;
        RECT  28.368 25.836 28.392 25.92 ;
    END
  END ro[336]
  PIN ro[337]
    DIRECTION OUTPUT ;
    USE SIGNAL ;
    PORT
      LAYER M5 ;
        RECT  28.464 25.836 28.488 25.92 ;
    END
  END ro[337]
  PIN ro[338]
    DIRECTION OUTPUT ;
    USE SIGNAL ;
    PORT
      LAYER M5 ;
        RECT  28.56 25.836 28.584 25.92 ;
    END
  END ro[338]
  PIN ro[339]
    DIRECTION OUTPUT ;
    USE SIGNAL ;
    PORT
      LAYER M5 ;
        RECT  28.656 25.836 28.68 25.92 ;
    END
  END ro[339]
  PIN ro[33]
    DIRECTION OUTPUT ;
    USE SIGNAL ;
    PORT
      LAYER M5 ;
        RECT  90.672 25.836 90.696 25.92 ;
    END
  END ro[33]
  PIN ro[340]
    DIRECTION OUTPUT ;
    USE SIGNAL ;
    PORT
      LAYER M5 ;
        RECT  28.752 25.836 28.776 25.92 ;
    END
  END ro[340]
  PIN ro[341]
    DIRECTION OUTPUT ;
    USE SIGNAL ;
    PORT
      LAYER M5 ;
        RECT  28.848 25.836 28.872 25.92 ;
    END
  END ro[341]
  PIN ro[342]
    DIRECTION OUTPUT ;
    USE SIGNAL ;
    PORT
      LAYER M5 ;
        RECT  28.944 25.836 28.968 25.92 ;
    END
  END ro[342]
  PIN ro[343]
    DIRECTION OUTPUT ;
    USE SIGNAL ;
    PORT
      LAYER M5 ;
        RECT  29.04 25.836 29.064 25.92 ;
    END
  END ro[343]
  PIN ro[344]
    DIRECTION OUTPUT ;
    USE SIGNAL ;
    PORT
      LAYER M5 ;
        RECT  29.136 25.836 29.16 25.92 ;
    END
  END ro[344]
  PIN ro[345]
    DIRECTION OUTPUT ;
    USE SIGNAL ;
    PORT
      LAYER M5 ;
        RECT  29.232 25.836 29.256 25.92 ;
    END
  END ro[345]
  PIN ro[346]
    DIRECTION OUTPUT ;
    USE SIGNAL ;
    PORT
      LAYER M5 ;
        RECT  29.328 25.836 29.352 25.92 ;
    END
  END ro[346]
  PIN ro[347]
    DIRECTION OUTPUT ;
    USE SIGNAL ;
    PORT
      LAYER M5 ;
        RECT  29.424 25.836 29.448 25.92 ;
    END
  END ro[347]
  PIN ro[348]
    DIRECTION OUTPUT ;
    USE SIGNAL ;
    PORT
      LAYER M5 ;
        RECT  29.52 25.836 29.544 25.92 ;
    END
  END ro[348]
  PIN ro[349]
    DIRECTION OUTPUT ;
    USE SIGNAL ;
    PORT
      LAYER M5 ;
        RECT  29.616 25.836 29.64 25.92 ;
    END
  END ro[349]
  PIN ro[34]
    DIRECTION OUTPUT ;
    USE SIGNAL ;
    PORT
      LAYER M5 ;
        RECT  90.768 25.836 90.792 25.92 ;
    END
  END ro[34]
  PIN ro[350]
    DIRECTION OUTPUT ;
    USE SIGNAL ;
    PORT
      LAYER M5 ;
        RECT  29.712 25.836 29.736 25.92 ;
    END
  END ro[350]
  PIN ro[351]
    DIRECTION OUTPUT ;
    USE SIGNAL ;
    PORT
      LAYER M5 ;
        RECT  29.808 25.836 29.832 25.92 ;
    END
  END ro[351]
  PIN ro[352]
    DIRECTION OUTPUT ;
    USE SIGNAL ;
    PORT
      LAYER M5 ;
        RECT  71.376 25.836 71.4 25.92 ;
    END
  END ro[352]
  PIN ro[353]
    DIRECTION OUTPUT ;
    USE SIGNAL ;
    PORT
      LAYER M5 ;
        RECT  71.472 25.836 71.496 25.92 ;
    END
  END ro[353]
  PIN ro[354]
    DIRECTION OUTPUT ;
    USE SIGNAL ;
    PORT
      LAYER M5 ;
        RECT  71.568 25.836 71.592 25.92 ;
    END
  END ro[354]
  PIN ro[355]
    DIRECTION OUTPUT ;
    USE SIGNAL ;
    PORT
      LAYER M5 ;
        RECT  71.664 25.836 71.688 25.92 ;
    END
  END ro[355]
  PIN ro[356]
    DIRECTION OUTPUT ;
    USE SIGNAL ;
    PORT
      LAYER M5 ;
        RECT  71.76 25.836 71.784 25.92 ;
    END
  END ro[356]
  PIN ro[357]
    DIRECTION OUTPUT ;
    USE SIGNAL ;
    PORT
      LAYER M5 ;
        RECT  71.856 25.836 71.88 25.92 ;
    END
  END ro[357]
  PIN ro[358]
    DIRECTION OUTPUT ;
    USE SIGNAL ;
    PORT
      LAYER M5 ;
        RECT  71.952 25.836 71.976 25.92 ;
    END
  END ro[358]
  PIN ro[359]
    DIRECTION OUTPUT ;
    USE SIGNAL ;
    PORT
      LAYER M5 ;
        RECT  72.048 25.836 72.072 25.92 ;
    END
  END ro[359]
  PIN ro[35]
    DIRECTION OUTPUT ;
    USE SIGNAL ;
    PORT
      LAYER M5 ;
        RECT  90.864 25.836 90.888 25.92 ;
    END
  END ro[35]
  PIN ro[360]
    DIRECTION OUTPUT ;
    USE SIGNAL ;
    PORT
      LAYER M5 ;
        RECT  72.144 25.836 72.168 25.92 ;
    END
  END ro[360]
  PIN ro[361]
    DIRECTION OUTPUT ;
    USE SIGNAL ;
    PORT
      LAYER M5 ;
        RECT  72.24 25.836 72.264 25.92 ;
    END
  END ro[361]
  PIN ro[362]
    DIRECTION OUTPUT ;
    USE SIGNAL ;
    PORT
      LAYER M5 ;
        RECT  72.336 25.836 72.36 25.92 ;
    END
  END ro[362]
  PIN ro[363]
    DIRECTION OUTPUT ;
    USE SIGNAL ;
    PORT
      LAYER M5 ;
        RECT  72.432 25.836 72.456 25.92 ;
    END
  END ro[363]
  PIN ro[364]
    DIRECTION OUTPUT ;
    USE SIGNAL ;
    PORT
      LAYER M5 ;
        RECT  72.528 25.836 72.552 25.92 ;
    END
  END ro[364]
  PIN ro[365]
    DIRECTION OUTPUT ;
    USE SIGNAL ;
    PORT
      LAYER M5 ;
        RECT  72.624 25.836 72.648 25.92 ;
    END
  END ro[365]
  PIN ro[366]
    DIRECTION OUTPUT ;
    USE SIGNAL ;
    PORT
      LAYER M5 ;
        RECT  72.72 25.836 72.744 25.92 ;
    END
  END ro[366]
  PIN ro[367]
    DIRECTION OUTPUT ;
    USE SIGNAL ;
    PORT
      LAYER M5 ;
        RECT  72.816 25.836 72.84 25.92 ;
    END
  END ro[367]
  PIN ro[368]
    DIRECTION OUTPUT ;
    USE SIGNAL ;
    PORT
      LAYER M5 ;
        RECT  72.912 25.836 72.936 25.92 ;
    END
  END ro[368]
  PIN ro[369]
    DIRECTION OUTPUT ;
    USE SIGNAL ;
    PORT
      LAYER M5 ;
        RECT  73.008 25.836 73.032 25.92 ;
    END
  END ro[369]
  PIN ro[36]
    DIRECTION OUTPUT ;
    USE SIGNAL ;
    PORT
      LAYER M5 ;
        RECT  90.96 25.836 90.984 25.92 ;
    END
  END ro[36]
  PIN ro[370]
    DIRECTION OUTPUT ;
    USE SIGNAL ;
    PORT
      LAYER M5 ;
        RECT  73.104 25.836 73.128 25.92 ;
    END
  END ro[370]
  PIN ro[371]
    DIRECTION OUTPUT ;
    USE SIGNAL ;
    PORT
      LAYER M5 ;
        RECT  73.2 25.836 73.224 25.92 ;
    END
  END ro[371]
  PIN ro[372]
    DIRECTION OUTPUT ;
    USE SIGNAL ;
    PORT
      LAYER M5 ;
        RECT  73.296 25.836 73.32 25.92 ;
    END
  END ro[372]
  PIN ro[373]
    DIRECTION OUTPUT ;
    USE SIGNAL ;
    PORT
      LAYER M5 ;
        RECT  73.392 25.836 73.416 25.92 ;
    END
  END ro[373]
  PIN ro[374]
    DIRECTION OUTPUT ;
    USE SIGNAL ;
    PORT
      LAYER M5 ;
        RECT  73.488 25.836 73.512 25.92 ;
    END
  END ro[374]
  PIN ro[375]
    DIRECTION OUTPUT ;
    USE SIGNAL ;
    PORT
      LAYER M5 ;
        RECT  73.584 25.836 73.608 25.92 ;
    END
  END ro[375]
  PIN ro[376]
    DIRECTION OUTPUT ;
    USE SIGNAL ;
    PORT
      LAYER M5 ;
        RECT  73.68 25.836 73.704 25.92 ;
    END
  END ro[376]
  PIN ro[377]
    DIRECTION OUTPUT ;
    USE SIGNAL ;
    PORT
      LAYER M5 ;
        RECT  73.776 25.836 73.8 25.92 ;
    END
  END ro[377]
  PIN ro[378]
    DIRECTION OUTPUT ;
    USE SIGNAL ;
    PORT
      LAYER M5 ;
        RECT  73.872 25.836 73.896 25.92 ;
    END
  END ro[378]
  PIN ro[379]
    DIRECTION OUTPUT ;
    USE SIGNAL ;
    PORT
      LAYER M5 ;
        RECT  73.968 25.836 73.992 25.92 ;
    END
  END ro[379]
  PIN ro[37]
    DIRECTION OUTPUT ;
    USE SIGNAL ;
    PORT
      LAYER M5 ;
        RECT  91.056 25.836 91.08 25.92 ;
    END
  END ro[37]
  PIN ro[380]
    DIRECTION OUTPUT ;
    USE SIGNAL ;
    PORT
      LAYER M5 ;
        RECT  74.064 25.836 74.088 25.92 ;
    END
  END ro[380]
  PIN ro[381]
    DIRECTION OUTPUT ;
    USE SIGNAL ;
    PORT
      LAYER M5 ;
        RECT  74.16 25.836 74.184 25.92 ;
    END
  END ro[381]
  PIN ro[382]
    DIRECTION OUTPUT ;
    USE SIGNAL ;
    PORT
      LAYER M5 ;
        RECT  74.256 25.836 74.28 25.92 ;
    END
  END ro[382]
  PIN ro[383]
    DIRECTION OUTPUT ;
    USE SIGNAL ;
    PORT
      LAYER M5 ;
        RECT  74.352 25.836 74.376 25.92 ;
    END
  END ro[383]
  PIN ro[384]
    DIRECTION OUTPUT ;
    USE SIGNAL ;
    PORT
      LAYER M5 ;
        RECT  49.104 25.836 49.128 25.92 ;
    END
  END ro[384]
  PIN ro[385]
    DIRECTION OUTPUT ;
    USE SIGNAL ;
    PORT
      LAYER M5 ;
        RECT  49.2 25.836 49.224 25.92 ;
    END
  END ro[385]
  PIN ro[386]
    DIRECTION OUTPUT ;
    USE SIGNAL ;
    PORT
      LAYER M5 ;
        RECT  49.296 25.836 49.32 25.92 ;
    END
  END ro[386]
  PIN ro[387]
    DIRECTION OUTPUT ;
    USE SIGNAL ;
    PORT
      LAYER M5 ;
        RECT  49.392 25.836 49.416 25.92 ;
    END
  END ro[387]
  PIN ro[388]
    DIRECTION OUTPUT ;
    USE SIGNAL ;
    PORT
      LAYER M5 ;
        RECT  49.488 25.836 49.512 25.92 ;
    END
  END ro[388]
  PIN ro[389]
    DIRECTION OUTPUT ;
    USE SIGNAL ;
    PORT
      LAYER M5 ;
        RECT  49.584 25.836 49.608 25.92 ;
    END
  END ro[389]
  PIN ro[38]
    DIRECTION OUTPUT ;
    USE SIGNAL ;
    PORT
      LAYER M5 ;
        RECT  91.152 25.836 91.176 25.92 ;
    END
  END ro[38]
  PIN ro[390]
    DIRECTION OUTPUT ;
    USE SIGNAL ;
    PORT
      LAYER M5 ;
        RECT  49.68 25.836 49.704 25.92 ;
    END
  END ro[390]
  PIN ro[391]
    DIRECTION OUTPUT ;
    USE SIGNAL ;
    PORT
      LAYER M5 ;
        RECT  49.776 25.836 49.8 25.92 ;
    END
  END ro[391]
  PIN ro[392]
    DIRECTION OUTPUT ;
    USE SIGNAL ;
    PORT
      LAYER M5 ;
        RECT  49.872 25.836 49.896 25.92 ;
    END
  END ro[392]
  PIN ro[393]
    DIRECTION OUTPUT ;
    USE SIGNAL ;
    PORT
      LAYER M5 ;
        RECT  49.968 25.836 49.992 25.92 ;
    END
  END ro[393]
  PIN ro[394]
    DIRECTION OUTPUT ;
    USE SIGNAL ;
    PORT
      LAYER M5 ;
        RECT  50.064 25.836 50.088 25.92 ;
    END
  END ro[394]
  PIN ro[395]
    DIRECTION OUTPUT ;
    USE SIGNAL ;
    PORT
      LAYER M5 ;
        RECT  50.16 25.836 50.184 25.92 ;
    END
  END ro[395]
  PIN ro[396]
    DIRECTION OUTPUT ;
    USE SIGNAL ;
    PORT
      LAYER M5 ;
        RECT  50.256 25.836 50.28 25.92 ;
    END
  END ro[396]
  PIN ro[397]
    DIRECTION OUTPUT ;
    USE SIGNAL ;
    PORT
      LAYER M5 ;
        RECT  50.352 25.836 50.376 25.92 ;
    END
  END ro[397]
  PIN ro[398]
    DIRECTION OUTPUT ;
    USE SIGNAL ;
    PORT
      LAYER M5 ;
        RECT  50.448 25.836 50.472 25.92 ;
    END
  END ro[398]
  PIN ro[399]
    DIRECTION OUTPUT ;
    USE SIGNAL ;
    PORT
      LAYER M5 ;
        RECT  50.544 25.836 50.568 25.92 ;
    END
  END ro[399]
  PIN ro[39]
    DIRECTION OUTPUT ;
    USE SIGNAL ;
    PORT
      LAYER M5 ;
        RECT  91.248 25.836 91.272 25.92 ;
    END
  END ro[39]
  PIN ro[3]
    DIRECTION OUTPUT ;
    USE SIGNAL ;
    PORT
      LAYER M5 ;
        RECT  46.32 25.836 46.344 25.92 ;
    END
  END ro[3]
  PIN ro[400]
    DIRECTION OUTPUT ;
    USE SIGNAL ;
    PORT
      LAYER M5 ;
        RECT  50.64 25.836 50.664 25.92 ;
    END
  END ro[400]
  PIN ro[401]
    DIRECTION OUTPUT ;
    USE SIGNAL ;
    PORT
      LAYER M5 ;
        RECT  50.736 25.836 50.76 25.92 ;
    END
  END ro[401]
  PIN ro[402]
    DIRECTION OUTPUT ;
    USE SIGNAL ;
    PORT
      LAYER M5 ;
        RECT  50.832 25.836 50.856 25.92 ;
    END
  END ro[402]
  PIN ro[403]
    DIRECTION OUTPUT ;
    USE SIGNAL ;
    PORT
      LAYER M5 ;
        RECT  50.928 25.836 50.952 25.92 ;
    END
  END ro[403]
  PIN ro[404]
    DIRECTION OUTPUT ;
    USE SIGNAL ;
    PORT
      LAYER M5 ;
        RECT  51.024 25.836 51.048 25.92 ;
    END
  END ro[404]
  PIN ro[405]
    DIRECTION OUTPUT ;
    USE SIGNAL ;
    PORT
      LAYER M5 ;
        RECT  51.12 25.836 51.144 25.92 ;
    END
  END ro[405]
  PIN ro[406]
    DIRECTION OUTPUT ;
    USE SIGNAL ;
    PORT
      LAYER M5 ;
        RECT  51.216 25.836 51.24 25.92 ;
    END
  END ro[406]
  PIN ro[407]
    DIRECTION OUTPUT ;
    USE SIGNAL ;
    PORT
      LAYER M5 ;
        RECT  51.312 25.836 51.336 25.92 ;
    END
  END ro[407]
  PIN ro[408]
    DIRECTION OUTPUT ;
    USE SIGNAL ;
    PORT
      LAYER M5 ;
        RECT  51.408 25.836 51.432 25.92 ;
    END
  END ro[408]
  PIN ro[409]
    DIRECTION OUTPUT ;
    USE SIGNAL ;
    PORT
      LAYER M5 ;
        RECT  51.504 25.836 51.528 25.92 ;
    END
  END ro[409]
  PIN ro[40]
    DIRECTION OUTPUT ;
    USE SIGNAL ;
    PORT
      LAYER M5 ;
        RECT  91.344 25.836 91.368 25.92 ;
    END
  END ro[40]
  PIN ro[410]
    DIRECTION OUTPUT ;
    USE SIGNAL ;
    PORT
      LAYER M5 ;
        RECT  51.6 25.836 51.624 25.92 ;
    END
  END ro[410]
  PIN ro[411]
    DIRECTION OUTPUT ;
    USE SIGNAL ;
    PORT
      LAYER M5 ;
        RECT  51.696 25.836 51.72 25.92 ;
    END
  END ro[411]
  PIN ro[412]
    DIRECTION OUTPUT ;
    USE SIGNAL ;
    PORT
      LAYER M5 ;
        RECT  51.792 25.836 51.816 25.92 ;
    END
  END ro[412]
  PIN ro[413]
    DIRECTION OUTPUT ;
    USE SIGNAL ;
    PORT
      LAYER M5 ;
        RECT  51.888 25.836 51.912 25.92 ;
    END
  END ro[413]
  PIN ro[414]
    DIRECTION OUTPUT ;
    USE SIGNAL ;
    PORT
      LAYER M5 ;
        RECT  51.984 25.836 52.008 25.92 ;
    END
  END ro[414]
  PIN ro[415]
    DIRECTION OUTPUT ;
    USE SIGNAL ;
    PORT
      LAYER M5 ;
        RECT  52.08 25.836 52.104 25.92 ;
    END
  END ro[415]
  PIN ro[416]
    DIRECTION OUTPUT ;
    USE SIGNAL ;
    PORT
      LAYER M5 ;
        RECT  59.088 25.836 59.112 25.92 ;
    END
  END ro[416]
  PIN ro[417]
    DIRECTION OUTPUT ;
    USE SIGNAL ;
    PORT
      LAYER M5 ;
        RECT  59.184 25.836 59.208 25.92 ;
    END
  END ro[417]
  PIN ro[418]
    DIRECTION OUTPUT ;
    USE SIGNAL ;
    PORT
      LAYER M5 ;
        RECT  59.28 25.836 59.304 25.92 ;
    END
  END ro[418]
  PIN ro[419]
    DIRECTION OUTPUT ;
    USE SIGNAL ;
    PORT
      LAYER M5 ;
        RECT  59.376 25.836 59.4 25.92 ;
    END
  END ro[419]
  PIN ro[41]
    DIRECTION OUTPUT ;
    USE SIGNAL ;
    PORT
      LAYER M5 ;
        RECT  91.44 25.836 91.464 25.92 ;
    END
  END ro[41]
  PIN ro[420]
    DIRECTION OUTPUT ;
    USE SIGNAL ;
    PORT
      LAYER M5 ;
        RECT  59.472 25.836 59.496 25.92 ;
    END
  END ro[420]
  PIN ro[421]
    DIRECTION OUTPUT ;
    USE SIGNAL ;
    PORT
      LAYER M5 ;
        RECT  59.568 25.836 59.592 25.92 ;
    END
  END ro[421]
  PIN ro[422]
    DIRECTION OUTPUT ;
    USE SIGNAL ;
    PORT
      LAYER M5 ;
        RECT  59.664 25.836 59.688 25.92 ;
    END
  END ro[422]
  PIN ro[423]
    DIRECTION OUTPUT ;
    USE SIGNAL ;
    PORT
      LAYER M5 ;
        RECT  59.76 25.836 59.784 25.92 ;
    END
  END ro[423]
  PIN ro[424]
    DIRECTION OUTPUT ;
    USE SIGNAL ;
    PORT
      LAYER M5 ;
        RECT  59.856 25.836 59.88 25.92 ;
    END
  END ro[424]
  PIN ro[425]
    DIRECTION OUTPUT ;
    USE SIGNAL ;
    PORT
      LAYER M5 ;
        RECT  59.952 25.836 59.976 25.92 ;
    END
  END ro[425]
  PIN ro[426]
    DIRECTION OUTPUT ;
    USE SIGNAL ;
    PORT
      LAYER M5 ;
        RECT  60.048 25.836 60.072 25.92 ;
    END
  END ro[426]
  PIN ro[427]
    DIRECTION OUTPUT ;
    USE SIGNAL ;
    PORT
      LAYER M5 ;
        RECT  60.144 25.836 60.168 25.92 ;
    END
  END ro[427]
  PIN ro[428]
    DIRECTION OUTPUT ;
    USE SIGNAL ;
    PORT
      LAYER M5 ;
        RECT  60.24 25.836 60.264 25.92 ;
    END
  END ro[428]
  PIN ro[429]
    DIRECTION OUTPUT ;
    USE SIGNAL ;
    PORT
      LAYER M5 ;
        RECT  60.336 25.836 60.36 25.92 ;
    END
  END ro[429]
  PIN ro[42]
    DIRECTION OUTPUT ;
    USE SIGNAL ;
    PORT
      LAYER M5 ;
        RECT  91.536 25.836 91.56 25.92 ;
    END
  END ro[42]
  PIN ro[430]
    DIRECTION OUTPUT ;
    USE SIGNAL ;
    PORT
      LAYER M5 ;
        RECT  60.432 25.836 60.456 25.92 ;
    END
  END ro[430]
  PIN ro[431]
    DIRECTION OUTPUT ;
    USE SIGNAL ;
    PORT
      LAYER M5 ;
        RECT  60.528 25.836 60.552 25.92 ;
    END
  END ro[431]
  PIN ro[432]
    DIRECTION OUTPUT ;
    USE SIGNAL ;
    PORT
      LAYER M5 ;
        RECT  60.624 25.836 60.648 25.92 ;
    END
  END ro[432]
  PIN ro[433]
    DIRECTION OUTPUT ;
    USE SIGNAL ;
    PORT
      LAYER M5 ;
        RECT  60.72 25.836 60.744 25.92 ;
    END
  END ro[433]
  PIN ro[434]
    DIRECTION OUTPUT ;
    USE SIGNAL ;
    PORT
      LAYER M5 ;
        RECT  60.816 25.836 60.84 25.92 ;
    END
  END ro[434]
  PIN ro[435]
    DIRECTION OUTPUT ;
    USE SIGNAL ;
    PORT
      LAYER M5 ;
        RECT  60.912 25.836 60.936 25.92 ;
    END
  END ro[435]
  PIN ro[436]
    DIRECTION OUTPUT ;
    USE SIGNAL ;
    PORT
      LAYER M5 ;
        RECT  61.008 25.836 61.032 25.92 ;
    END
  END ro[436]
  PIN ro[437]
    DIRECTION OUTPUT ;
    USE SIGNAL ;
    PORT
      LAYER M5 ;
        RECT  61.104 25.836 61.128 25.92 ;
    END
  END ro[437]
  PIN ro[438]
    DIRECTION OUTPUT ;
    USE SIGNAL ;
    PORT
      LAYER M5 ;
        RECT  61.2 25.836 61.224 25.92 ;
    END
  END ro[438]
  PIN ro[439]
    DIRECTION OUTPUT ;
    USE SIGNAL ;
    PORT
      LAYER M5 ;
        RECT  61.296 25.836 61.32 25.92 ;
    END
  END ro[439]
  PIN ro[43]
    DIRECTION OUTPUT ;
    USE SIGNAL ;
    PORT
      LAYER M5 ;
        RECT  91.632 25.836 91.656 25.92 ;
    END
  END ro[43]
  PIN ro[440]
    DIRECTION OUTPUT ;
    USE SIGNAL ;
    PORT
      LAYER M5 ;
        RECT  61.392 25.836 61.416 25.92 ;
    END
  END ro[440]
  PIN ro[441]
    DIRECTION OUTPUT ;
    USE SIGNAL ;
    PORT
      LAYER M5 ;
        RECT  61.488 25.836 61.512 25.92 ;
    END
  END ro[441]
  PIN ro[442]
    DIRECTION OUTPUT ;
    USE SIGNAL ;
    PORT
      LAYER M5 ;
        RECT  61.584 25.836 61.608 25.92 ;
    END
  END ro[442]
  PIN ro[443]
    DIRECTION OUTPUT ;
    USE SIGNAL ;
    PORT
      LAYER M5 ;
        RECT  61.68 25.836 61.704 25.92 ;
    END
  END ro[443]
  PIN ro[444]
    DIRECTION OUTPUT ;
    USE SIGNAL ;
    PORT
      LAYER M5 ;
        RECT  61.776 25.836 61.8 25.92 ;
    END
  END ro[444]
  PIN ro[445]
    DIRECTION OUTPUT ;
    USE SIGNAL ;
    PORT
      LAYER M5 ;
        RECT  61.872 25.836 61.896 25.92 ;
    END
  END ro[445]
  PIN ro[446]
    DIRECTION OUTPUT ;
    USE SIGNAL ;
    PORT
      LAYER M5 ;
        RECT  61.968 25.836 61.992 25.92 ;
    END
  END ro[446]
  PIN ro[447]
    DIRECTION OUTPUT ;
    USE SIGNAL ;
    PORT
      LAYER M5 ;
        RECT  62.064 25.836 62.088 25.92 ;
    END
  END ro[447]
  PIN ro[448]
    DIRECTION OUTPUT ;
    USE SIGNAL ;
    PORT
      LAYER M5 ;
        RECT  87.504 25.836 87.528 25.92 ;
    END
  END ro[448]
  PIN ro[449]
    DIRECTION OUTPUT ;
    USE SIGNAL ;
    PORT
      LAYER M5 ;
        RECT  87.6 25.836 87.624 25.92 ;
    END
  END ro[449]
  PIN ro[44]
    DIRECTION OUTPUT ;
    USE SIGNAL ;
    PORT
      LAYER M5 ;
        RECT  91.728 25.836 91.752 25.92 ;
    END
  END ro[44]
  PIN ro[450]
    DIRECTION OUTPUT ;
    USE SIGNAL ;
    PORT
      LAYER M5 ;
        RECT  87.696 25.836 87.72 25.92 ;
    END
  END ro[450]
  PIN ro[451]
    DIRECTION OUTPUT ;
    USE SIGNAL ;
    PORT
      LAYER M5 ;
        RECT  87.792 25.836 87.816 25.92 ;
    END
  END ro[451]
  PIN ro[452]
    DIRECTION OUTPUT ;
    USE SIGNAL ;
    PORT
      LAYER M5 ;
        RECT  87.888 25.836 87.912 25.92 ;
    END
  END ro[452]
  PIN ro[453]
    DIRECTION OUTPUT ;
    USE SIGNAL ;
    PORT
      LAYER M5 ;
        RECT  87.984 25.836 88.008 25.92 ;
    END
  END ro[453]
  PIN ro[454]
    DIRECTION OUTPUT ;
    USE SIGNAL ;
    PORT
      LAYER M5 ;
        RECT  88.08 25.836 88.104 25.92 ;
    END
  END ro[454]
  PIN ro[455]
    DIRECTION OUTPUT ;
    USE SIGNAL ;
    PORT
      LAYER M5 ;
        RECT  88.176 25.836 88.2 25.92 ;
    END
  END ro[455]
  PIN ro[456]
    DIRECTION OUTPUT ;
    USE SIGNAL ;
    PORT
      LAYER M5 ;
        RECT  88.272 25.836 88.296 25.92 ;
    END
  END ro[456]
  PIN ro[457]
    DIRECTION OUTPUT ;
    USE SIGNAL ;
    PORT
      LAYER M5 ;
        RECT  88.368 25.836 88.392 25.92 ;
    END
  END ro[457]
  PIN ro[458]
    DIRECTION OUTPUT ;
    USE SIGNAL ;
    PORT
      LAYER M5 ;
        RECT  88.464 25.836 88.488 25.92 ;
    END
  END ro[458]
  PIN ro[459]
    DIRECTION OUTPUT ;
    USE SIGNAL ;
    PORT
      LAYER M5 ;
        RECT  88.56 25.836 88.584 25.92 ;
    END
  END ro[459]
  PIN ro[45]
    DIRECTION OUTPUT ;
    USE SIGNAL ;
    PORT
      LAYER M5 ;
        RECT  91.824 25.836 91.848 25.92 ;
    END
  END ro[45]
  PIN ro[460]
    DIRECTION OUTPUT ;
    USE SIGNAL ;
    PORT
      LAYER M5 ;
        RECT  88.656 25.836 88.68 25.92 ;
    END
  END ro[460]
  PIN ro[461]
    DIRECTION OUTPUT ;
    USE SIGNAL ;
    PORT
      LAYER M5 ;
        RECT  88.752 25.836 88.776 25.92 ;
    END
  END ro[461]
  PIN ro[462]
    DIRECTION OUTPUT ;
    USE SIGNAL ;
    PORT
      LAYER M5 ;
        RECT  88.848 25.836 88.872 25.92 ;
    END
  END ro[462]
  PIN ro[463]
    DIRECTION OUTPUT ;
    USE SIGNAL ;
    PORT
      LAYER M5 ;
        RECT  88.944 25.836 88.968 25.92 ;
    END
  END ro[463]
  PIN ro[464]
    DIRECTION OUTPUT ;
    USE SIGNAL ;
    PORT
      LAYER M5 ;
        RECT  89.04 25.836 89.064 25.92 ;
    END
  END ro[464]
  PIN ro[465]
    DIRECTION OUTPUT ;
    USE SIGNAL ;
    PORT
      LAYER M5 ;
        RECT  89.136 25.836 89.16 25.92 ;
    END
  END ro[465]
  PIN ro[466]
    DIRECTION OUTPUT ;
    USE SIGNAL ;
    PORT
      LAYER M5 ;
        RECT  89.232 25.836 89.256 25.92 ;
    END
  END ro[466]
  PIN ro[467]
    DIRECTION OUTPUT ;
    USE SIGNAL ;
    PORT
      LAYER M5 ;
        RECT  89.328 25.836 89.352 25.92 ;
    END
  END ro[467]
  PIN ro[468]
    DIRECTION OUTPUT ;
    USE SIGNAL ;
    PORT
      LAYER M5 ;
        RECT  89.424 25.836 89.448 25.92 ;
    END
  END ro[468]
  PIN ro[469]
    DIRECTION OUTPUT ;
    USE SIGNAL ;
    PORT
      LAYER M5 ;
        RECT  89.52 25.836 89.544 25.92 ;
    END
  END ro[469]
  PIN ro[46]
    DIRECTION OUTPUT ;
    USE SIGNAL ;
    PORT
      LAYER M5 ;
        RECT  91.92 25.836 91.944 25.92 ;
    END
  END ro[46]
  PIN ro[470]
    DIRECTION OUTPUT ;
    USE SIGNAL ;
    PORT
      LAYER M5 ;
        RECT  89.616 25.836 89.64 25.92 ;
    END
  END ro[470]
  PIN ro[471]
    DIRECTION OUTPUT ;
    USE SIGNAL ;
    PORT
      LAYER M5 ;
        RECT  89.712 25.836 89.736 25.92 ;
    END
  END ro[471]
  PIN ro[472]
    DIRECTION OUTPUT ;
    USE SIGNAL ;
    PORT
      LAYER M5 ;
        RECT  89.808 25.836 89.832 25.92 ;
    END
  END ro[472]
  PIN ro[473]
    DIRECTION OUTPUT ;
    USE SIGNAL ;
    PORT
      LAYER M5 ;
        RECT  89.904 25.836 89.928 25.92 ;
    END
  END ro[473]
  PIN ro[474]
    DIRECTION OUTPUT ;
    USE SIGNAL ;
    PORT
      LAYER M5 ;
        RECT  90 25.836 90.024 25.92 ;
    END
  END ro[474]
  PIN ro[475]
    DIRECTION OUTPUT ;
    USE SIGNAL ;
    PORT
      LAYER M5 ;
        RECT  90.096 25.836 90.12 25.92 ;
    END
  END ro[475]
  PIN ro[476]
    DIRECTION OUTPUT ;
    USE SIGNAL ;
    PORT
      LAYER M5 ;
        RECT  90.192 25.836 90.216 25.92 ;
    END
  END ro[476]
  PIN ro[477]
    DIRECTION OUTPUT ;
    USE SIGNAL ;
    PORT
      LAYER M5 ;
        RECT  90.288 25.836 90.312 25.92 ;
    END
  END ro[477]
  PIN ro[478]
    DIRECTION OUTPUT ;
    USE SIGNAL ;
    PORT
      LAYER M5 ;
        RECT  90.384 25.836 90.408 25.92 ;
    END
  END ro[478]
  PIN ro[479]
    DIRECTION OUTPUT ;
    USE SIGNAL ;
    PORT
      LAYER M5 ;
        RECT  90.48 25.836 90.504 25.92 ;
    END
  END ro[479]
  PIN ro[47]
    DIRECTION OUTPUT ;
    USE SIGNAL ;
    PORT
      LAYER M5 ;
        RECT  92.016 25.836 92.04 25.92 ;
    END
  END ro[47]
  PIN ro[480]
    DIRECTION OUTPUT ;
    USE SIGNAL ;
    PORT
      LAYER M5 ;
        RECT  93.648 25.836 93.672 25.92 ;
    END
  END ro[480]
  PIN ro[481]
    DIRECTION OUTPUT ;
    USE SIGNAL ;
    PORT
      LAYER M5 ;
        RECT  93.744 25.836 93.768 25.92 ;
    END
  END ro[481]
  PIN ro[482]
    DIRECTION OUTPUT ;
    USE SIGNAL ;
    PORT
      LAYER M5 ;
        RECT  93.84 25.836 93.864 25.92 ;
    END
  END ro[482]
  PIN ro[483]
    DIRECTION OUTPUT ;
    USE SIGNAL ;
    PORT
      LAYER M5 ;
        RECT  93.936 25.836 93.96 25.92 ;
    END
  END ro[483]
  PIN ro[484]
    DIRECTION OUTPUT ;
    USE SIGNAL ;
    PORT
      LAYER M5 ;
        RECT  94.032 25.836 94.056 25.92 ;
    END
  END ro[484]
  PIN ro[485]
    DIRECTION OUTPUT ;
    USE SIGNAL ;
    PORT
      LAYER M5 ;
        RECT  94.128 25.836 94.152 25.92 ;
    END
  END ro[485]
  PIN ro[486]
    DIRECTION OUTPUT ;
    USE SIGNAL ;
    PORT
      LAYER M5 ;
        RECT  94.224 25.836 94.248 25.92 ;
    END
  END ro[486]
  PIN ro[487]
    DIRECTION OUTPUT ;
    USE SIGNAL ;
    PORT
      LAYER M5 ;
        RECT  94.32 25.836 94.344 25.92 ;
    END
  END ro[487]
  PIN ro[488]
    DIRECTION OUTPUT ;
    USE SIGNAL ;
    PORT
      LAYER M5 ;
        RECT  94.416 25.836 94.44 25.92 ;
    END
  END ro[488]
  PIN ro[489]
    DIRECTION OUTPUT ;
    USE SIGNAL ;
    PORT
      LAYER M5 ;
        RECT  94.512 25.836 94.536 25.92 ;
    END
  END ro[489]
  PIN ro[48]
    DIRECTION OUTPUT ;
    USE SIGNAL ;
    PORT
      LAYER M5 ;
        RECT  92.112 25.836 92.136 25.92 ;
    END
  END ro[48]
  PIN ro[490]
    DIRECTION OUTPUT ;
    USE SIGNAL ;
    PORT
      LAYER M5 ;
        RECT  94.608 25.836 94.632 25.92 ;
    END
  END ro[490]
  PIN ro[491]
    DIRECTION OUTPUT ;
    USE SIGNAL ;
    PORT
      LAYER M5 ;
        RECT  94.704 25.836 94.728 25.92 ;
    END
  END ro[491]
  PIN ro[492]
    DIRECTION OUTPUT ;
    USE SIGNAL ;
    PORT
      LAYER M5 ;
        RECT  94.8 25.836 94.824 25.92 ;
    END
  END ro[492]
  PIN ro[493]
    DIRECTION OUTPUT ;
    USE SIGNAL ;
    PORT
      LAYER M5 ;
        RECT  94.896 25.836 94.92 25.92 ;
    END
  END ro[493]
  PIN ro[494]
    DIRECTION OUTPUT ;
    USE SIGNAL ;
    PORT
      LAYER M5 ;
        RECT  94.992 25.836 95.016 25.92 ;
    END
  END ro[494]
  PIN ro[495]
    DIRECTION OUTPUT ;
    USE SIGNAL ;
    PORT
      LAYER M5 ;
        RECT  95.088 25.836 95.112 25.92 ;
    END
  END ro[495]
  PIN ro[496]
    DIRECTION OUTPUT ;
    USE SIGNAL ;
    PORT
      LAYER M5 ;
        RECT  95.184 25.836 95.208 25.92 ;
    END
  END ro[496]
  PIN ro[497]
    DIRECTION OUTPUT ;
    USE SIGNAL ;
    PORT
      LAYER M5 ;
        RECT  95.28 25.836 95.304 25.92 ;
    END
  END ro[497]
  PIN ro[498]
    DIRECTION OUTPUT ;
    USE SIGNAL ;
    PORT
      LAYER M5 ;
        RECT  95.376 25.836 95.4 25.92 ;
    END
  END ro[498]
  PIN ro[499]
    DIRECTION OUTPUT ;
    USE SIGNAL ;
    PORT
      LAYER M5 ;
        RECT  95.472 25.836 95.496 25.92 ;
    END
  END ro[499]
  PIN ro[49]
    DIRECTION OUTPUT ;
    USE SIGNAL ;
    PORT
      LAYER M5 ;
        RECT  92.208 25.836 92.232 25.92 ;
    END
  END ro[49]
  PIN ro[4]
    DIRECTION OUTPUT ;
    USE SIGNAL ;
    PORT
      LAYER M5 ;
        RECT  46.416 25.836 46.44 25.92 ;
    END
  END ro[4]
  PIN ro[500]
    DIRECTION OUTPUT ;
    USE SIGNAL ;
    PORT
      LAYER M5 ;
        RECT  95.568 25.836 95.592 25.92 ;
    END
  END ro[500]
  PIN ro[501]
    DIRECTION OUTPUT ;
    USE SIGNAL ;
    PORT
      LAYER M5 ;
        RECT  95.664 25.836 95.688 25.92 ;
    END
  END ro[501]
  PIN ro[502]
    DIRECTION OUTPUT ;
    USE SIGNAL ;
    PORT
      LAYER M5 ;
        RECT  95.76 25.836 95.784 25.92 ;
    END
  END ro[502]
  PIN ro[503]
    DIRECTION OUTPUT ;
    USE SIGNAL ;
    PORT
      LAYER M5 ;
        RECT  95.856 25.836 95.88 25.92 ;
    END
  END ro[503]
  PIN ro[504]
    DIRECTION OUTPUT ;
    USE SIGNAL ;
    PORT
      LAYER M5 ;
        RECT  95.952 25.836 95.976 25.92 ;
    END
  END ro[504]
  PIN ro[505]
    DIRECTION OUTPUT ;
    USE SIGNAL ;
    PORT
      LAYER M5 ;
        RECT  96.048 25.836 96.072 25.92 ;
    END
  END ro[505]
  PIN ro[506]
    DIRECTION OUTPUT ;
    USE SIGNAL ;
    PORT
      LAYER M5 ;
        RECT  96.144 25.836 96.168 25.92 ;
    END
  END ro[506]
  PIN ro[507]
    DIRECTION OUTPUT ;
    USE SIGNAL ;
    PORT
      LAYER M5 ;
        RECT  96.24 25.836 96.264 25.92 ;
    END
  END ro[507]
  PIN ro[508]
    DIRECTION OUTPUT ;
    USE SIGNAL ;
    PORT
      LAYER M5 ;
        RECT  96.336 25.836 96.36 25.92 ;
    END
  END ro[508]
  PIN ro[509]
    DIRECTION OUTPUT ;
    USE SIGNAL ;
    PORT
      LAYER M5 ;
        RECT  96.432 25.836 96.456 25.92 ;
    END
  END ro[509]
  PIN ro[50]
    DIRECTION OUTPUT ;
    USE SIGNAL ;
    PORT
      LAYER M5 ;
        RECT  92.304 25.836 92.328 25.92 ;
    END
  END ro[50]
  PIN ro[510]
    DIRECTION OUTPUT ;
    USE SIGNAL ;
    PORT
      LAYER M5 ;
        RECT  96.528 25.836 96.552 25.92 ;
    END
  END ro[510]
  PIN ro[511]
    DIRECTION OUTPUT ;
    USE SIGNAL ;
    PORT
      LAYER M5 ;
        RECT  96.624 25.836 96.648 25.92 ;
    END
  END ro[511]
  PIN ro[51]
    DIRECTION OUTPUT ;
    USE SIGNAL ;
    PORT
      LAYER M5 ;
        RECT  92.4 25.836 92.424 25.92 ;
    END
  END ro[51]
  PIN ro[52]
    DIRECTION OUTPUT ;
    USE SIGNAL ;
    PORT
      LAYER M5 ;
        RECT  92.496 25.836 92.52 25.92 ;
    END
  END ro[52]
  PIN ro[53]
    DIRECTION OUTPUT ;
    USE SIGNAL ;
    PORT
      LAYER M5 ;
        RECT  92.592 25.836 92.616 25.92 ;
    END
  END ro[53]
  PIN ro[54]
    DIRECTION OUTPUT ;
    USE SIGNAL ;
    PORT
      LAYER M5 ;
        RECT  92.688 25.836 92.712 25.92 ;
    END
  END ro[54]
  PIN ro[55]
    DIRECTION OUTPUT ;
    USE SIGNAL ;
    PORT
      LAYER M5 ;
        RECT  92.784 25.836 92.808 25.92 ;
    END
  END ro[55]
  PIN ro[56]
    DIRECTION OUTPUT ;
    USE SIGNAL ;
    PORT
      LAYER M5 ;
        RECT  92.88 25.836 92.904 25.92 ;
    END
  END ro[56]
  PIN ro[57]
    DIRECTION OUTPUT ;
    USE SIGNAL ;
    PORT
      LAYER M5 ;
        RECT  92.976 25.836 93 25.92 ;
    END
  END ro[57]
  PIN ro[58]
    DIRECTION OUTPUT ;
    USE SIGNAL ;
    PORT
      LAYER M5 ;
        RECT  93.072 25.836 93.096 25.92 ;
    END
  END ro[58]
  PIN ro[59]
    DIRECTION OUTPUT ;
    USE SIGNAL ;
    PORT
      LAYER M5 ;
        RECT  93.168 25.836 93.192 25.92 ;
    END
  END ro[59]
  PIN ro[5]
    DIRECTION OUTPUT ;
    USE SIGNAL ;
    PORT
      LAYER M5 ;
        RECT  46.512 25.836 46.536 25.92 ;
    END
  END ro[5]
  PIN ro[60]
    DIRECTION OUTPUT ;
    USE SIGNAL ;
    PORT
      LAYER M5 ;
        RECT  93.264 25.836 93.288 25.92 ;
    END
  END ro[60]
  PIN ro[61]
    DIRECTION OUTPUT ;
    USE SIGNAL ;
    PORT
      LAYER M5 ;
        RECT  93.36 25.836 93.384 25.92 ;
    END
  END ro[61]
  PIN ro[62]
    DIRECTION OUTPUT ;
    USE SIGNAL ;
    PORT
      LAYER M5 ;
        RECT  93.456 25.836 93.48 25.92 ;
    END
  END ro[62]
  PIN ro[63]
    DIRECTION OUTPUT ;
    USE SIGNAL ;
    PORT
      LAYER M5 ;
        RECT  93.552 25.836 93.576 25.92 ;
    END
  END ro[63]
  PIN ro[64]
    DIRECTION OUTPUT ;
    USE SIGNAL ;
    PORT
      LAYER M5 ;
        RECT  55.248 25.836 55.272 25.92 ;
    END
  END ro[64]
  PIN ro[65]
    DIRECTION OUTPUT ;
    USE SIGNAL ;
    PORT
      LAYER M5 ;
        RECT  55.344 25.836 55.368 25.92 ;
    END
  END ro[65]
  PIN ro[66]
    DIRECTION OUTPUT ;
    USE SIGNAL ;
    PORT
      LAYER M5 ;
        RECT  55.44 25.836 55.464 25.92 ;
    END
  END ro[66]
  PIN ro[67]
    DIRECTION OUTPUT ;
    USE SIGNAL ;
    PORT
      LAYER M5 ;
        RECT  55.536 25.836 55.56 25.92 ;
    END
  END ro[67]
  PIN ro[68]
    DIRECTION OUTPUT ;
    USE SIGNAL ;
    PORT
      LAYER M5 ;
        RECT  55.632 25.836 55.656 25.92 ;
    END
  END ro[68]
  PIN ro[69]
    DIRECTION OUTPUT ;
    USE SIGNAL ;
    PORT
      LAYER M5 ;
        RECT  55.728 25.836 55.752 25.92 ;
    END
  END ro[69]
  PIN ro[6]
    DIRECTION OUTPUT ;
    USE SIGNAL ;
    PORT
      LAYER M5 ;
        RECT  46.608 25.836 46.632 25.92 ;
    END
  END ro[6]
  PIN ro[70]
    DIRECTION OUTPUT ;
    USE SIGNAL ;
    PORT
      LAYER M5 ;
        RECT  55.824 25.836 55.848 25.92 ;
    END
  END ro[70]
  PIN ro[71]
    DIRECTION OUTPUT ;
    USE SIGNAL ;
    PORT
      LAYER M5 ;
        RECT  55.92 25.836 55.944 25.92 ;
    END
  END ro[71]
  PIN ro[72]
    DIRECTION OUTPUT ;
    USE SIGNAL ;
    PORT
      LAYER M5 ;
        RECT  56.016 25.836 56.04 25.92 ;
    END
  END ro[72]
  PIN ro[73]
    DIRECTION OUTPUT ;
    USE SIGNAL ;
    PORT
      LAYER M5 ;
        RECT  56.112 25.836 56.136 25.92 ;
    END
  END ro[73]
  PIN ro[74]
    DIRECTION OUTPUT ;
    USE SIGNAL ;
    PORT
      LAYER M5 ;
        RECT  56.208 25.836 56.232 25.92 ;
    END
  END ro[74]
  PIN ro[75]
    DIRECTION OUTPUT ;
    USE SIGNAL ;
    PORT
      LAYER M5 ;
        RECT  56.304 25.836 56.328 25.92 ;
    END
  END ro[75]
  PIN ro[76]
    DIRECTION OUTPUT ;
    USE SIGNAL ;
    PORT
      LAYER M5 ;
        RECT  56.4 25.836 56.424 25.92 ;
    END
  END ro[76]
  PIN ro[77]
    DIRECTION OUTPUT ;
    USE SIGNAL ;
    PORT
      LAYER M5 ;
        RECT  56.496 25.836 56.52 25.92 ;
    END
  END ro[77]
  PIN ro[78]
    DIRECTION OUTPUT ;
    USE SIGNAL ;
    PORT
      LAYER M5 ;
        RECT  56.592 25.836 56.616 25.92 ;
    END
  END ro[78]
  PIN ro[79]
    DIRECTION OUTPUT ;
    USE SIGNAL ;
    PORT
      LAYER M5 ;
        RECT  56.688 25.836 56.712 25.92 ;
    END
  END ro[79]
  PIN ro[7]
    DIRECTION OUTPUT ;
    USE SIGNAL ;
    PORT
      LAYER M5 ;
        RECT  46.704 25.836 46.728 25.92 ;
    END
  END ro[7]
  PIN ro[80]
    DIRECTION OUTPUT ;
    USE SIGNAL ;
    PORT
      LAYER M5 ;
        RECT  56.784 25.836 56.808 25.92 ;
    END
  END ro[80]
  PIN ro[81]
    DIRECTION OUTPUT ;
    USE SIGNAL ;
    PORT
      LAYER M5 ;
        RECT  56.88 25.836 56.904 25.92 ;
    END
  END ro[81]
  PIN ro[82]
    DIRECTION OUTPUT ;
    USE SIGNAL ;
    PORT
      LAYER M5 ;
        RECT  56.976 25.836 57 25.92 ;
    END
  END ro[82]
  PIN ro[83]
    DIRECTION OUTPUT ;
    USE SIGNAL ;
    PORT
      LAYER M5 ;
        RECT  57.072 25.836 57.096 25.92 ;
    END
  END ro[83]
  PIN ro[84]
    DIRECTION OUTPUT ;
    USE SIGNAL ;
    PORT
      LAYER M5 ;
        RECT  57.168 25.836 57.192 25.92 ;
    END
  END ro[84]
  PIN ro[85]
    DIRECTION OUTPUT ;
    USE SIGNAL ;
    PORT
      LAYER M5 ;
        RECT  57.264 25.836 57.288 25.92 ;
    END
  END ro[85]
  PIN ro[86]
    DIRECTION OUTPUT ;
    USE SIGNAL ;
    PORT
      LAYER M5 ;
        RECT  57.36 25.836 57.384 25.92 ;
    END
  END ro[86]
  PIN ro[87]
    DIRECTION OUTPUT ;
    USE SIGNAL ;
    PORT
      LAYER M5 ;
        RECT  57.456 25.836 57.48 25.92 ;
    END
  END ro[87]
  PIN ro[88]
    DIRECTION OUTPUT ;
    USE SIGNAL ;
    PORT
      LAYER M5 ;
        RECT  57.552 25.836 57.576 25.92 ;
    END
  END ro[88]
  PIN ro[89]
    DIRECTION OUTPUT ;
    USE SIGNAL ;
    PORT
      LAYER M5 ;
        RECT  57.648 25.836 57.672 25.92 ;
    END
  END ro[89]
  PIN ro[8]
    DIRECTION OUTPUT ;
    USE SIGNAL ;
    PORT
      LAYER M5 ;
        RECT  46.8 25.836 46.824 25.92 ;
    END
  END ro[8]
  PIN ro[90]
    DIRECTION OUTPUT ;
    USE SIGNAL ;
    PORT
      LAYER M5 ;
        RECT  57.744 25.836 57.768 25.92 ;
    END
  END ro[90]
  PIN ro[91]
    DIRECTION OUTPUT ;
    USE SIGNAL ;
    PORT
      LAYER M5 ;
        RECT  57.84 25.836 57.864 25.92 ;
    END
  END ro[91]
  PIN ro[92]
    DIRECTION OUTPUT ;
    USE SIGNAL ;
    PORT
      LAYER M5 ;
        RECT  57.936 25.836 57.96 25.92 ;
    END
  END ro[92]
  PIN ro[93]
    DIRECTION OUTPUT ;
    USE SIGNAL ;
    PORT
      LAYER M5 ;
        RECT  58.032 25.836 58.056 25.92 ;
    END
  END ro[93]
  PIN ro[94]
    DIRECTION OUTPUT ;
    USE SIGNAL ;
    PORT
      LAYER M5 ;
        RECT  58.128 25.836 58.152 25.92 ;
    END
  END ro[94]
  PIN ro[95]
    DIRECTION OUTPUT ;
    USE SIGNAL ;
    PORT
      LAYER M5 ;
        RECT  58.224 25.836 58.248 25.92 ;
    END
  END ro[95]
  PIN ro[96]
    DIRECTION OUTPUT ;
    USE SIGNAL ;
    PORT
      LAYER M5 ;
        RECT  42.96 25.836 42.984 25.92 ;
    END
  END ro[96]
  PIN ro[97]
    DIRECTION OUTPUT ;
    USE SIGNAL ;
    PORT
      LAYER M5 ;
        RECT  43.056 25.836 43.08 25.92 ;
    END
  END ro[97]
  PIN ro[98]
    DIRECTION OUTPUT ;
    USE SIGNAL ;
    PORT
      LAYER M5 ;
        RECT  43.152 25.836 43.176 25.92 ;
    END
  END ro[98]
  PIN ro[99]
    DIRECTION OUTPUT ;
    USE SIGNAL ;
    PORT
      LAYER M5 ;
        RECT  43.248 25.836 43.272 25.92 ;
    END
  END ro[99]
  PIN ro[9]
    DIRECTION OUTPUT ;
    USE SIGNAL ;
    PORT
      LAYER M5 ;
        RECT  46.896 25.836 46.92 25.92 ;
    END
  END ro[9]
  PIN rq
    DIRECTION INPUT ;
    USE SIGNAL ;
    PORT
      LAYER M4 ;
        RECT  0 5.52 0.084 5.544 ;
    END
  END rq
  PIN rqb[0]
    DIRECTION INPUT ;
    USE SIGNAL ;
    PORT
      LAYER M4 ;
        RECT  0 5.616 0.084 5.64 ;
    END
  END rqb[0]
  PIN rqb[1]
    DIRECTION INPUT ;
    USE SIGNAL ;
    PORT
      LAYER M4 ;
        RECT  0 5.712 0.084 5.736 ;
    END
  END rqb[1]
  PIN rqb[2]
    DIRECTION INPUT ;
    USE SIGNAL ;
    PORT
      LAYER M4 ;
        RECT  0 5.808 0.084 5.832 ;
    END
  END rqb[2]
  PIN rst_n
    DIRECTION INPUT ;
    USE SIGNAL ;
    PORT
      LAYER M4 ;
        RECT  0 5.904 0.084 5.928 ;
    END
  END rst_n
  PIN t1a[0]
    DIRECTION INPUT ;
    USE SIGNAL ;
    PORT
      LAYER M5 ;
        RECT  32.976 25.836 33 25.92 ;
    END
  END t1a[0]
  PIN t1a[100]
    DIRECTION INPUT ;
    USE SIGNAL ;
    PORT
      LAYER M5 ;
        RECT  21.072 25.836 21.096 25.92 ;
    END
  END t1a[100]
  PIN t1a[101]
    DIRECTION INPUT ;
    USE SIGNAL ;
    PORT
      LAYER M5 ;
        RECT  21.168 25.836 21.192 25.92 ;
    END
  END t1a[101]
  PIN t1a[102]
    DIRECTION INPUT ;
    USE SIGNAL ;
    PORT
      LAYER M5 ;
        RECT  21.264 25.836 21.288 25.92 ;
    END
  END t1a[102]
  PIN t1a[103]
    DIRECTION INPUT ;
    USE SIGNAL ;
    PORT
      LAYER M5 ;
        RECT  21.36 25.836 21.384 25.92 ;
    END
  END t1a[103]
  PIN t1a[104]
    DIRECTION INPUT ;
    USE SIGNAL ;
    PORT
      LAYER M5 ;
        RECT  21.456 25.836 21.48 25.92 ;
    END
  END t1a[104]
  PIN t1a[105]
    DIRECTION INPUT ;
    USE SIGNAL ;
    PORT
      LAYER M5 ;
        RECT  21.552 25.836 21.576 25.92 ;
    END
  END t1a[105]
  PIN t1a[106]
    DIRECTION INPUT ;
    USE SIGNAL ;
    PORT
      LAYER M5 ;
        RECT  21.648 25.836 21.672 25.92 ;
    END
  END t1a[106]
  PIN t1a[107]
    DIRECTION INPUT ;
    USE SIGNAL ;
    PORT
      LAYER M5 ;
        RECT  21.744 25.836 21.768 25.92 ;
    END
  END t1a[107]
  PIN t1a[108]
    DIRECTION INPUT ;
    USE SIGNAL ;
    PORT
      LAYER M5 ;
        RECT  21.84 25.836 21.864 25.92 ;
    END
  END t1a[108]
  PIN t1a[109]
    DIRECTION INPUT ;
    USE SIGNAL ;
    PORT
      LAYER M5 ;
        RECT  21.936 25.836 21.96 25.92 ;
    END
  END t1a[109]
  PIN t1a[10]
    DIRECTION INPUT ;
    USE SIGNAL ;
    PORT
      LAYER M5 ;
        RECT  33.936 25.836 33.96 25.92 ;
    END
  END t1a[10]
  PIN t1a[110]
    DIRECTION INPUT ;
    USE SIGNAL ;
    PORT
      LAYER M5 ;
        RECT  22.032 25.836 22.056 25.92 ;
    END
  END t1a[110]
  PIN t1a[111]
    DIRECTION INPUT ;
    USE SIGNAL ;
    PORT
      LAYER M5 ;
        RECT  22.128 25.836 22.152 25.92 ;
    END
  END t1a[111]
  PIN t1a[112]
    DIRECTION INPUT ;
    USE SIGNAL ;
    PORT
      LAYER M5 ;
        RECT  22.224 25.836 22.248 25.92 ;
    END
  END t1a[112]
  PIN t1a[113]
    DIRECTION INPUT ;
    USE SIGNAL ;
    PORT
      LAYER M5 ;
        RECT  22.32 25.836 22.344 25.92 ;
    END
  END t1a[113]
  PIN t1a[114]
    DIRECTION INPUT ;
    USE SIGNAL ;
    PORT
      LAYER M5 ;
        RECT  22.416 25.836 22.44 25.92 ;
    END
  END t1a[114]
  PIN t1a[115]
    DIRECTION INPUT ;
    USE SIGNAL ;
    PORT
      LAYER M5 ;
        RECT  22.512 25.836 22.536 25.92 ;
    END
  END t1a[115]
  PIN t1a[116]
    DIRECTION INPUT ;
    USE SIGNAL ;
    PORT
      LAYER M5 ;
        RECT  22.608 25.836 22.632 25.92 ;
    END
  END t1a[116]
  PIN t1a[117]
    DIRECTION INPUT ;
    USE SIGNAL ;
    PORT
      LAYER M5 ;
        RECT  22.704 25.836 22.728 25.92 ;
    END
  END t1a[117]
  PIN t1a[118]
    DIRECTION INPUT ;
    USE SIGNAL ;
    PORT
      LAYER M5 ;
        RECT  22.8 25.836 22.824 25.92 ;
    END
  END t1a[118]
  PIN t1a[119]
    DIRECTION INPUT ;
    USE SIGNAL ;
    PORT
      LAYER M5 ;
        RECT  22.896 25.836 22.92 25.92 ;
    END
  END t1a[119]
  PIN t1a[11]
    DIRECTION INPUT ;
    USE SIGNAL ;
    PORT
      LAYER M5 ;
        RECT  34.032 25.836 34.056 25.92 ;
    END
  END t1a[11]
  PIN t1a[120]
    DIRECTION INPUT ;
    USE SIGNAL ;
    PORT
      LAYER M5 ;
        RECT  22.992 25.836 23.016 25.92 ;
    END
  END t1a[120]
  PIN t1a[121]
    DIRECTION INPUT ;
    USE SIGNAL ;
    PORT
      LAYER M5 ;
        RECT  23.088 25.836 23.112 25.92 ;
    END
  END t1a[121]
  PIN t1a[122]
    DIRECTION INPUT ;
    USE SIGNAL ;
    PORT
      LAYER M5 ;
        RECT  23.184 25.836 23.208 25.92 ;
    END
  END t1a[122]
  PIN t1a[123]
    DIRECTION INPUT ;
    USE SIGNAL ;
    PORT
      LAYER M5 ;
        RECT  23.28 25.836 23.304 25.92 ;
    END
  END t1a[123]
  PIN t1a[124]
    DIRECTION INPUT ;
    USE SIGNAL ;
    PORT
      LAYER M5 ;
        RECT  23.376 25.836 23.4 25.92 ;
    END
  END t1a[124]
  PIN t1a[125]
    DIRECTION INPUT ;
    USE SIGNAL ;
    PORT
      LAYER M5 ;
        RECT  23.472 25.836 23.496 25.92 ;
    END
  END t1a[125]
  PIN t1a[126]
    DIRECTION INPUT ;
    USE SIGNAL ;
    PORT
      LAYER M5 ;
        RECT  23.568 25.836 23.592 25.92 ;
    END
  END t1a[126]
  PIN t1a[127]
    DIRECTION INPUT ;
    USE SIGNAL ;
    PORT
      LAYER M5 ;
        RECT  23.664 25.836 23.688 25.92 ;
    END
  END t1a[127]
  PIN t1a[128]
    DIRECTION INPUT ;
    USE SIGNAL ;
    PORT
      LAYER M5 ;
        RECT  29.904 25.836 29.928 25.92 ;
    END
  END t1a[128]
  PIN t1a[129]
    DIRECTION INPUT ;
    USE SIGNAL ;
    PORT
      LAYER M5 ;
        RECT  30 25.836 30.024 25.92 ;
    END
  END t1a[129]
  PIN t1a[12]
    DIRECTION INPUT ;
    USE SIGNAL ;
    PORT
      LAYER M5 ;
        RECT  34.128 25.836 34.152 25.92 ;
    END
  END t1a[12]
  PIN t1a[130]
    DIRECTION INPUT ;
    USE SIGNAL ;
    PORT
      LAYER M5 ;
        RECT  30.096 25.836 30.12 25.92 ;
    END
  END t1a[130]
  PIN t1a[131]
    DIRECTION INPUT ;
    USE SIGNAL ;
    PORT
      LAYER M5 ;
        RECT  30.192 25.836 30.216 25.92 ;
    END
  END t1a[131]
  PIN t1a[132]
    DIRECTION INPUT ;
    USE SIGNAL ;
    PORT
      LAYER M5 ;
        RECT  30.288 25.836 30.312 25.92 ;
    END
  END t1a[132]
  PIN t1a[133]
    DIRECTION INPUT ;
    USE SIGNAL ;
    PORT
      LAYER M5 ;
        RECT  30.384 25.836 30.408 25.92 ;
    END
  END t1a[133]
  PIN t1a[134]
    DIRECTION INPUT ;
    USE SIGNAL ;
    PORT
      LAYER M5 ;
        RECT  30.48 25.836 30.504 25.92 ;
    END
  END t1a[134]
  PIN t1a[135]
    DIRECTION INPUT ;
    USE SIGNAL ;
    PORT
      LAYER M5 ;
        RECT  30.576 25.836 30.6 25.92 ;
    END
  END t1a[135]
  PIN t1a[136]
    DIRECTION INPUT ;
    USE SIGNAL ;
    PORT
      LAYER M5 ;
        RECT  30.672 25.836 30.696 25.92 ;
    END
  END t1a[136]
  PIN t1a[137]
    DIRECTION INPUT ;
    USE SIGNAL ;
    PORT
      LAYER M5 ;
        RECT  30.768 25.836 30.792 25.92 ;
    END
  END t1a[137]
  PIN t1a[138]
    DIRECTION INPUT ;
    USE SIGNAL ;
    PORT
      LAYER M5 ;
        RECT  30.864 25.836 30.888 25.92 ;
    END
  END t1a[138]
  PIN t1a[139]
    DIRECTION INPUT ;
    USE SIGNAL ;
    PORT
      LAYER M5 ;
        RECT  30.96 25.836 30.984 25.92 ;
    END
  END t1a[139]
  PIN t1a[13]
    DIRECTION INPUT ;
    USE SIGNAL ;
    PORT
      LAYER M5 ;
        RECT  34.224 25.836 34.248 25.92 ;
    END
  END t1a[13]
  PIN t1a[140]
    DIRECTION INPUT ;
    USE SIGNAL ;
    PORT
      LAYER M5 ;
        RECT  31.056 25.836 31.08 25.92 ;
    END
  END t1a[140]
  PIN t1a[141]
    DIRECTION INPUT ;
    USE SIGNAL ;
    PORT
      LAYER M5 ;
        RECT  31.152 25.836 31.176 25.92 ;
    END
  END t1a[141]
  PIN t1a[142]
    DIRECTION INPUT ;
    USE SIGNAL ;
    PORT
      LAYER M5 ;
        RECT  31.248 25.836 31.272 25.92 ;
    END
  END t1a[142]
  PIN t1a[143]
    DIRECTION INPUT ;
    USE SIGNAL ;
    PORT
      LAYER M5 ;
        RECT  31.344 25.836 31.368 25.92 ;
    END
  END t1a[143]
  PIN t1a[144]
    DIRECTION INPUT ;
    USE SIGNAL ;
    PORT
      LAYER M5 ;
        RECT  31.44 25.836 31.464 25.92 ;
    END
  END t1a[144]
  PIN t1a[145]
    DIRECTION INPUT ;
    USE SIGNAL ;
    PORT
      LAYER M5 ;
        RECT  31.536 25.836 31.56 25.92 ;
    END
  END t1a[145]
  PIN t1a[146]
    DIRECTION INPUT ;
    USE SIGNAL ;
    PORT
      LAYER M5 ;
        RECT  31.632 25.836 31.656 25.92 ;
    END
  END t1a[146]
  PIN t1a[147]
    DIRECTION INPUT ;
    USE SIGNAL ;
    PORT
      LAYER M5 ;
        RECT  31.728 25.836 31.752 25.92 ;
    END
  END t1a[147]
  PIN t1a[148]
    DIRECTION INPUT ;
    USE SIGNAL ;
    PORT
      LAYER M5 ;
        RECT  31.824 25.836 31.848 25.92 ;
    END
  END t1a[148]
  PIN t1a[149]
    DIRECTION INPUT ;
    USE SIGNAL ;
    PORT
      LAYER M5 ;
        RECT  31.92 25.836 31.944 25.92 ;
    END
  END t1a[149]
  PIN t1a[14]
    DIRECTION INPUT ;
    USE SIGNAL ;
    PORT
      LAYER M5 ;
        RECT  34.32 25.836 34.344 25.92 ;
    END
  END t1a[14]
  PIN t1a[150]
    DIRECTION INPUT ;
    USE SIGNAL ;
    PORT
      LAYER M5 ;
        RECT  32.016 25.836 32.04 25.92 ;
    END
  END t1a[150]
  PIN t1a[151]
    DIRECTION INPUT ;
    USE SIGNAL ;
    PORT
      LAYER M5 ;
        RECT  32.112 25.836 32.136 25.92 ;
    END
  END t1a[151]
  PIN t1a[152]
    DIRECTION INPUT ;
    USE SIGNAL ;
    PORT
      LAYER M5 ;
        RECT  32.208 25.836 32.232 25.92 ;
    END
  END t1a[152]
  PIN t1a[153]
    DIRECTION INPUT ;
    USE SIGNAL ;
    PORT
      LAYER M5 ;
        RECT  32.304 25.836 32.328 25.92 ;
    END
  END t1a[153]
  PIN t1a[154]
    DIRECTION INPUT ;
    USE SIGNAL ;
    PORT
      LAYER M5 ;
        RECT  32.4 25.836 32.424 25.92 ;
    END
  END t1a[154]
  PIN t1a[155]
    DIRECTION INPUT ;
    USE SIGNAL ;
    PORT
      LAYER M5 ;
        RECT  32.496 25.836 32.52 25.92 ;
    END
  END t1a[155]
  PIN t1a[156]
    DIRECTION INPUT ;
    USE SIGNAL ;
    PORT
      LAYER M5 ;
        RECT  32.592 25.836 32.616 25.92 ;
    END
  END t1a[156]
  PIN t1a[157]
    DIRECTION INPUT ;
    USE SIGNAL ;
    PORT
      LAYER M5 ;
        RECT  32.688 25.836 32.712 25.92 ;
    END
  END t1a[157]
  PIN t1a[158]
    DIRECTION INPUT ;
    USE SIGNAL ;
    PORT
      LAYER M5 ;
        RECT  32.784 25.836 32.808 25.92 ;
    END
  END t1a[158]
  PIN t1a[159]
    DIRECTION INPUT ;
    USE SIGNAL ;
    PORT
      LAYER M5 ;
        RECT  32.88 25.836 32.904 25.92 ;
    END
  END t1a[159]
  PIN t1a[15]
    DIRECTION INPUT ;
    USE SIGNAL ;
    PORT
      LAYER M5 ;
        RECT  34.416 25.836 34.44 25.92 ;
    END
  END t1a[15]
  PIN t1a[160]
    DIRECTION INPUT ;
    USE SIGNAL ;
    PORT
      LAYER M5 ;
        RECT  84.432 25.836 84.456 25.92 ;
    END
  END t1a[160]
  PIN t1a[161]
    DIRECTION INPUT ;
    USE SIGNAL ;
    PORT
      LAYER M5 ;
        RECT  84.528 25.836 84.552 25.92 ;
    END
  END t1a[161]
  PIN t1a[162]
    DIRECTION INPUT ;
    USE SIGNAL ;
    PORT
      LAYER M5 ;
        RECT  84.624 25.836 84.648 25.92 ;
    END
  END t1a[162]
  PIN t1a[163]
    DIRECTION INPUT ;
    USE SIGNAL ;
    PORT
      LAYER M5 ;
        RECT  84.72 25.836 84.744 25.92 ;
    END
  END t1a[163]
  PIN t1a[164]
    DIRECTION INPUT ;
    USE SIGNAL ;
    PORT
      LAYER M5 ;
        RECT  84.816 25.836 84.84 25.92 ;
    END
  END t1a[164]
  PIN t1a[165]
    DIRECTION INPUT ;
    USE SIGNAL ;
    PORT
      LAYER M5 ;
        RECT  84.912 25.836 84.936 25.92 ;
    END
  END t1a[165]
  PIN t1a[166]
    DIRECTION INPUT ;
    USE SIGNAL ;
    PORT
      LAYER M5 ;
        RECT  85.008 25.836 85.032 25.92 ;
    END
  END t1a[166]
  PIN t1a[167]
    DIRECTION INPUT ;
    USE SIGNAL ;
    PORT
      LAYER M5 ;
        RECT  85.104 25.836 85.128 25.92 ;
    END
  END t1a[167]
  PIN t1a[168]
    DIRECTION INPUT ;
    USE SIGNAL ;
    PORT
      LAYER M5 ;
        RECT  85.2 25.836 85.224 25.92 ;
    END
  END t1a[168]
  PIN t1a[169]
    DIRECTION INPUT ;
    USE SIGNAL ;
    PORT
      LAYER M5 ;
        RECT  85.296 25.836 85.32 25.92 ;
    END
  END t1a[169]
  PIN t1a[16]
    DIRECTION INPUT ;
    USE SIGNAL ;
    PORT
      LAYER M5 ;
        RECT  34.512 25.836 34.536 25.92 ;
    END
  END t1a[16]
  PIN t1a[170]
    DIRECTION INPUT ;
    USE SIGNAL ;
    PORT
      LAYER M5 ;
        RECT  85.392 25.836 85.416 25.92 ;
    END
  END t1a[170]
  PIN t1a[171]
    DIRECTION INPUT ;
    USE SIGNAL ;
    PORT
      LAYER M5 ;
        RECT  85.488 25.836 85.512 25.92 ;
    END
  END t1a[171]
  PIN t1a[172]
    DIRECTION INPUT ;
    USE SIGNAL ;
    PORT
      LAYER M5 ;
        RECT  85.584 25.836 85.608 25.92 ;
    END
  END t1a[172]
  PIN t1a[173]
    DIRECTION INPUT ;
    USE SIGNAL ;
    PORT
      LAYER M5 ;
        RECT  85.68 25.836 85.704 25.92 ;
    END
  END t1a[173]
  PIN t1a[174]
    DIRECTION INPUT ;
    USE SIGNAL ;
    PORT
      LAYER M5 ;
        RECT  85.776 25.836 85.8 25.92 ;
    END
  END t1a[174]
  PIN t1a[175]
    DIRECTION INPUT ;
    USE SIGNAL ;
    PORT
      LAYER M5 ;
        RECT  85.872 25.836 85.896 25.92 ;
    END
  END t1a[175]
  PIN t1a[176]
    DIRECTION INPUT ;
    USE SIGNAL ;
    PORT
      LAYER M5 ;
        RECT  85.968 25.836 85.992 25.92 ;
    END
  END t1a[176]
  PIN t1a[177]
    DIRECTION INPUT ;
    USE SIGNAL ;
    PORT
      LAYER M5 ;
        RECT  86.064 25.836 86.088 25.92 ;
    END
  END t1a[177]
  PIN t1a[178]
    DIRECTION INPUT ;
    USE SIGNAL ;
    PORT
      LAYER M5 ;
        RECT  86.16 25.836 86.184 25.92 ;
    END
  END t1a[178]
  PIN t1a[179]
    DIRECTION INPUT ;
    USE SIGNAL ;
    PORT
      LAYER M5 ;
        RECT  86.256 25.836 86.28 25.92 ;
    END
  END t1a[179]
  PIN t1a[17]
    DIRECTION INPUT ;
    USE SIGNAL ;
    PORT
      LAYER M5 ;
        RECT  34.608 25.836 34.632 25.92 ;
    END
  END t1a[17]
  PIN t1a[180]
    DIRECTION INPUT ;
    USE SIGNAL ;
    PORT
      LAYER M5 ;
        RECT  86.352 25.836 86.376 25.92 ;
    END
  END t1a[180]
  PIN t1a[181]
    DIRECTION INPUT ;
    USE SIGNAL ;
    PORT
      LAYER M5 ;
        RECT  86.448 25.836 86.472 25.92 ;
    END
  END t1a[181]
  PIN t1a[182]
    DIRECTION INPUT ;
    USE SIGNAL ;
    PORT
      LAYER M5 ;
        RECT  86.544 25.836 86.568 25.92 ;
    END
  END t1a[182]
  PIN t1a[183]
    DIRECTION INPUT ;
    USE SIGNAL ;
    PORT
      LAYER M5 ;
        RECT  86.64 25.836 86.664 25.92 ;
    END
  END t1a[183]
  PIN t1a[184]
    DIRECTION INPUT ;
    USE SIGNAL ;
    PORT
      LAYER M5 ;
        RECT  86.736 25.836 86.76 25.92 ;
    END
  END t1a[184]
  PIN t1a[185]
    DIRECTION INPUT ;
    USE SIGNAL ;
    PORT
      LAYER M5 ;
        RECT  86.832 25.836 86.856 25.92 ;
    END
  END t1a[185]
  PIN t1a[186]
    DIRECTION INPUT ;
    USE SIGNAL ;
    PORT
      LAYER M5 ;
        RECT  86.928 25.836 86.952 25.92 ;
    END
  END t1a[186]
  PIN t1a[187]
    DIRECTION INPUT ;
    USE SIGNAL ;
    PORT
      LAYER M5 ;
        RECT  87.024 25.836 87.048 25.92 ;
    END
  END t1a[187]
  PIN t1a[188]
    DIRECTION INPUT ;
    USE SIGNAL ;
    PORT
      LAYER M5 ;
        RECT  87.12 25.836 87.144 25.92 ;
    END
  END t1a[188]
  PIN t1a[189]
    DIRECTION INPUT ;
    USE SIGNAL ;
    PORT
      LAYER M5 ;
        RECT  87.216 25.836 87.24 25.92 ;
    END
  END t1a[189]
  PIN t1a[18]
    DIRECTION INPUT ;
    USE SIGNAL ;
    PORT
      LAYER M5 ;
        RECT  34.704 25.836 34.728 25.92 ;
    END
  END t1a[18]
  PIN t1a[190]
    DIRECTION INPUT ;
    USE SIGNAL ;
    PORT
      LAYER M5 ;
        RECT  87.312 25.836 87.336 25.92 ;
    END
  END t1a[190]
  PIN t1a[191]
    DIRECTION INPUT ;
    USE SIGNAL ;
    PORT
      LAYER M5 ;
        RECT  87.408 25.836 87.432 25.92 ;
    END
  END t1a[191]
  PIN t1a[192]
    DIRECTION INPUT ;
    USE SIGNAL ;
    PORT
      LAYER M5 ;
        RECT  81.36 25.836 81.384 25.92 ;
    END
  END t1a[192]
  PIN t1a[193]
    DIRECTION INPUT ;
    USE SIGNAL ;
    PORT
      LAYER M5 ;
        RECT  81.456 25.836 81.48 25.92 ;
    END
  END t1a[193]
  PIN t1a[194]
    DIRECTION INPUT ;
    USE SIGNAL ;
    PORT
      LAYER M5 ;
        RECT  81.552 25.836 81.576 25.92 ;
    END
  END t1a[194]
  PIN t1a[195]
    DIRECTION INPUT ;
    USE SIGNAL ;
    PORT
      LAYER M5 ;
        RECT  81.648 25.836 81.672 25.92 ;
    END
  END t1a[195]
  PIN t1a[196]
    DIRECTION INPUT ;
    USE SIGNAL ;
    PORT
      LAYER M5 ;
        RECT  81.744 25.836 81.768 25.92 ;
    END
  END t1a[196]
  PIN t1a[197]
    DIRECTION INPUT ;
    USE SIGNAL ;
    PORT
      LAYER M5 ;
        RECT  81.84 25.836 81.864 25.92 ;
    END
  END t1a[197]
  PIN t1a[198]
    DIRECTION INPUT ;
    USE SIGNAL ;
    PORT
      LAYER M5 ;
        RECT  81.936 25.836 81.96 25.92 ;
    END
  END t1a[198]
  PIN t1a[199]
    DIRECTION INPUT ;
    USE SIGNAL ;
    PORT
      LAYER M5 ;
        RECT  82.032 25.836 82.056 25.92 ;
    END
  END t1a[199]
  PIN t1a[19]
    DIRECTION INPUT ;
    USE SIGNAL ;
    PORT
      LAYER M5 ;
        RECT  34.8 25.836 34.824 25.92 ;
    END
  END t1a[19]
  PIN t1a[1]
    DIRECTION INPUT ;
    USE SIGNAL ;
    PORT
      LAYER M5 ;
        RECT  33.072 25.836 33.096 25.92 ;
    END
  END t1a[1]
  PIN t1a[200]
    DIRECTION INPUT ;
    USE SIGNAL ;
    PORT
      LAYER M5 ;
        RECT  82.128 25.836 82.152 25.92 ;
    END
  END t1a[200]
  PIN t1a[201]
    DIRECTION INPUT ;
    USE SIGNAL ;
    PORT
      LAYER M5 ;
        RECT  82.224 25.836 82.248 25.92 ;
    END
  END t1a[201]
  PIN t1a[202]
    DIRECTION INPUT ;
    USE SIGNAL ;
    PORT
      LAYER M5 ;
        RECT  82.32 25.836 82.344 25.92 ;
    END
  END t1a[202]
  PIN t1a[203]
    DIRECTION INPUT ;
    USE SIGNAL ;
    PORT
      LAYER M5 ;
        RECT  82.416 25.836 82.44 25.92 ;
    END
  END t1a[203]
  PIN t1a[204]
    DIRECTION INPUT ;
    USE SIGNAL ;
    PORT
      LAYER M5 ;
        RECT  82.512 25.836 82.536 25.92 ;
    END
  END t1a[204]
  PIN t1a[205]
    DIRECTION INPUT ;
    USE SIGNAL ;
    PORT
      LAYER M5 ;
        RECT  82.608 25.836 82.632 25.92 ;
    END
  END t1a[205]
  PIN t1a[206]
    DIRECTION INPUT ;
    USE SIGNAL ;
    PORT
      LAYER M5 ;
        RECT  82.704 25.836 82.728 25.92 ;
    END
  END t1a[206]
  PIN t1a[207]
    DIRECTION INPUT ;
    USE SIGNAL ;
    PORT
      LAYER M5 ;
        RECT  82.8 25.836 82.824 25.92 ;
    END
  END t1a[207]
  PIN t1a[208]
    DIRECTION INPUT ;
    USE SIGNAL ;
    PORT
      LAYER M5 ;
        RECT  82.896 25.836 82.92 25.92 ;
    END
  END t1a[208]
  PIN t1a[209]
    DIRECTION INPUT ;
    USE SIGNAL ;
    PORT
      LAYER M5 ;
        RECT  82.992 25.836 83.016 25.92 ;
    END
  END t1a[209]
  PIN t1a[20]
    DIRECTION INPUT ;
    USE SIGNAL ;
    PORT
      LAYER M5 ;
        RECT  34.896 25.836 34.92 25.92 ;
    END
  END t1a[20]
  PIN t1a[210]
    DIRECTION INPUT ;
    USE SIGNAL ;
    PORT
      LAYER M5 ;
        RECT  83.088 25.836 83.112 25.92 ;
    END
  END t1a[210]
  PIN t1a[211]
    DIRECTION INPUT ;
    USE SIGNAL ;
    PORT
      LAYER M5 ;
        RECT  83.184 25.836 83.208 25.92 ;
    END
  END t1a[211]
  PIN t1a[212]
    DIRECTION INPUT ;
    USE SIGNAL ;
    PORT
      LAYER M5 ;
        RECT  83.28 25.836 83.304 25.92 ;
    END
  END t1a[212]
  PIN t1a[213]
    DIRECTION INPUT ;
    USE SIGNAL ;
    PORT
      LAYER M5 ;
        RECT  83.376 25.836 83.4 25.92 ;
    END
  END t1a[213]
  PIN t1a[214]
    DIRECTION INPUT ;
    USE SIGNAL ;
    PORT
      LAYER M5 ;
        RECT  83.472 25.836 83.496 25.92 ;
    END
  END t1a[214]
  PIN t1a[215]
    DIRECTION INPUT ;
    USE SIGNAL ;
    PORT
      LAYER M5 ;
        RECT  83.568 25.836 83.592 25.92 ;
    END
  END t1a[215]
  PIN t1a[216]
    DIRECTION INPUT ;
    USE SIGNAL ;
    PORT
      LAYER M5 ;
        RECT  83.664 25.836 83.688 25.92 ;
    END
  END t1a[216]
  PIN t1a[217]
    DIRECTION INPUT ;
    USE SIGNAL ;
    PORT
      LAYER M5 ;
        RECT  83.76 25.836 83.784 25.92 ;
    END
  END t1a[217]
  PIN t1a[218]
    DIRECTION INPUT ;
    USE SIGNAL ;
    PORT
      LAYER M5 ;
        RECT  83.856 25.836 83.88 25.92 ;
    END
  END t1a[218]
  PIN t1a[219]
    DIRECTION INPUT ;
    USE SIGNAL ;
    PORT
      LAYER M5 ;
        RECT  83.952 25.836 83.976 25.92 ;
    END
  END t1a[219]
  PIN t1a[21]
    DIRECTION INPUT ;
    USE SIGNAL ;
    PORT
      LAYER M5 ;
        RECT  34.992 25.836 35.016 25.92 ;
    END
  END t1a[21]
  PIN t1a[220]
    DIRECTION INPUT ;
    USE SIGNAL ;
    PORT
      LAYER M5 ;
        RECT  84.048 25.836 84.072 25.92 ;
    END
  END t1a[220]
  PIN t1a[221]
    DIRECTION INPUT ;
    USE SIGNAL ;
    PORT
      LAYER M5 ;
        RECT  84.144 25.836 84.168 25.92 ;
    END
  END t1a[221]
  PIN t1a[222]
    DIRECTION INPUT ;
    USE SIGNAL ;
    PORT
      LAYER M5 ;
        RECT  84.24 25.836 84.264 25.92 ;
    END
  END t1a[222]
  PIN t1a[223]
    DIRECTION INPUT ;
    USE SIGNAL ;
    PORT
      LAYER M5 ;
        RECT  84.336 25.836 84.36 25.92 ;
    END
  END t1a[223]
  PIN t1a[224]
    DIRECTION INPUT ;
    USE SIGNAL ;
    PORT
      LAYER M5 ;
        RECT  36.048 25.836 36.072 25.92 ;
    END
  END t1a[224]
  PIN t1a[225]
    DIRECTION INPUT ;
    USE SIGNAL ;
    PORT
      LAYER M5 ;
        RECT  36.144 25.836 36.168 25.92 ;
    END
  END t1a[225]
  PIN t1a[226]
    DIRECTION INPUT ;
    USE SIGNAL ;
    PORT
      LAYER M5 ;
        RECT  36.24 25.836 36.264 25.92 ;
    END
  END t1a[226]
  PIN t1a[227]
    DIRECTION INPUT ;
    USE SIGNAL ;
    PORT
      LAYER M5 ;
        RECT  36.336 25.836 36.36 25.92 ;
    END
  END t1a[227]
  PIN t1a[228]
    DIRECTION INPUT ;
    USE SIGNAL ;
    PORT
      LAYER M5 ;
        RECT  36.432 25.836 36.456 25.92 ;
    END
  END t1a[228]
  PIN t1a[229]
    DIRECTION INPUT ;
    USE SIGNAL ;
    PORT
      LAYER M5 ;
        RECT  36.528 25.836 36.552 25.92 ;
    END
  END t1a[229]
  PIN t1a[22]
    DIRECTION INPUT ;
    USE SIGNAL ;
    PORT
      LAYER M5 ;
        RECT  35.088 25.836 35.112 25.92 ;
    END
  END t1a[22]
  PIN t1a[230]
    DIRECTION INPUT ;
    USE SIGNAL ;
    PORT
      LAYER M5 ;
        RECT  36.624 25.836 36.648 25.92 ;
    END
  END t1a[230]
  PIN t1a[231]
    DIRECTION INPUT ;
    USE SIGNAL ;
    PORT
      LAYER M5 ;
        RECT  36.72 25.836 36.744 25.92 ;
    END
  END t1a[231]
  PIN t1a[232]
    DIRECTION INPUT ;
    USE SIGNAL ;
    PORT
      LAYER M5 ;
        RECT  36.816 25.836 36.84 25.92 ;
    END
  END t1a[232]
  PIN t1a[233]
    DIRECTION INPUT ;
    USE SIGNAL ;
    PORT
      LAYER M5 ;
        RECT  36.912 25.836 36.936 25.92 ;
    END
  END t1a[233]
  PIN t1a[234]
    DIRECTION INPUT ;
    USE SIGNAL ;
    PORT
      LAYER M5 ;
        RECT  37.008 25.836 37.032 25.92 ;
    END
  END t1a[234]
  PIN t1a[235]
    DIRECTION INPUT ;
    USE SIGNAL ;
    PORT
      LAYER M5 ;
        RECT  37.104 25.836 37.128 25.92 ;
    END
  END t1a[235]
  PIN t1a[236]
    DIRECTION INPUT ;
    USE SIGNAL ;
    PORT
      LAYER M5 ;
        RECT  37.2 25.836 37.224 25.92 ;
    END
  END t1a[236]
  PIN t1a[237]
    DIRECTION INPUT ;
    USE SIGNAL ;
    PORT
      LAYER M5 ;
        RECT  37.296 25.836 37.32 25.92 ;
    END
  END t1a[237]
  PIN t1a[238]
    DIRECTION INPUT ;
    USE SIGNAL ;
    PORT
      LAYER M5 ;
        RECT  37.392 25.836 37.416 25.92 ;
    END
  END t1a[238]
  PIN t1a[239]
    DIRECTION INPUT ;
    USE SIGNAL ;
    PORT
      LAYER M5 ;
        RECT  37.488 25.836 37.512 25.92 ;
    END
  END t1a[239]
  PIN t1a[23]
    DIRECTION INPUT ;
    USE SIGNAL ;
    PORT
      LAYER M5 ;
        RECT  35.184 25.836 35.208 25.92 ;
    END
  END t1a[23]
  PIN t1a[240]
    DIRECTION INPUT ;
    USE SIGNAL ;
    PORT
      LAYER M5 ;
        RECT  37.584 25.836 37.608 25.92 ;
    END
  END t1a[240]
  PIN t1a[241]
    DIRECTION INPUT ;
    USE SIGNAL ;
    PORT
      LAYER M5 ;
        RECT  37.68 25.836 37.704 25.92 ;
    END
  END t1a[241]
  PIN t1a[242]
    DIRECTION INPUT ;
    USE SIGNAL ;
    PORT
      LAYER M5 ;
        RECT  37.776 25.836 37.8 25.92 ;
    END
  END t1a[242]
  PIN t1a[243]
    DIRECTION INPUT ;
    USE SIGNAL ;
    PORT
      LAYER M5 ;
        RECT  37.872 25.836 37.896 25.92 ;
    END
  END t1a[243]
  PIN t1a[244]
    DIRECTION INPUT ;
    USE SIGNAL ;
    PORT
      LAYER M5 ;
        RECT  37.968 25.836 37.992 25.92 ;
    END
  END t1a[244]
  PIN t1a[245]
    DIRECTION INPUT ;
    USE SIGNAL ;
    PORT
      LAYER M5 ;
        RECT  38.064 25.836 38.088 25.92 ;
    END
  END t1a[245]
  PIN t1a[246]
    DIRECTION INPUT ;
    USE SIGNAL ;
    PORT
      LAYER M5 ;
        RECT  38.16 25.836 38.184 25.92 ;
    END
  END t1a[246]
  PIN t1a[247]
    DIRECTION INPUT ;
    USE SIGNAL ;
    PORT
      LAYER M5 ;
        RECT  38.256 25.836 38.28 25.92 ;
    END
  END t1a[247]
  PIN t1a[248]
    DIRECTION INPUT ;
    USE SIGNAL ;
    PORT
      LAYER M5 ;
        RECT  38.352 25.836 38.376 25.92 ;
    END
  END t1a[248]
  PIN t1a[249]
    DIRECTION INPUT ;
    USE SIGNAL ;
    PORT
      LAYER M5 ;
        RECT  38.448 25.836 38.472 25.92 ;
    END
  END t1a[249]
  PIN t1a[24]
    DIRECTION INPUT ;
    USE SIGNAL ;
    PORT
      LAYER M5 ;
        RECT  35.28 25.836 35.304 25.92 ;
    END
  END t1a[24]
  PIN t1a[250]
    DIRECTION INPUT ;
    USE SIGNAL ;
    PORT
      LAYER M5 ;
        RECT  38.544 25.836 38.568 25.92 ;
    END
  END t1a[250]
  PIN t1a[251]
    DIRECTION INPUT ;
    USE SIGNAL ;
    PORT
      LAYER M5 ;
        RECT  38.64 25.836 38.664 25.92 ;
    END
  END t1a[251]
  PIN t1a[252]
    DIRECTION INPUT ;
    USE SIGNAL ;
    PORT
      LAYER M5 ;
        RECT  38.736 25.836 38.76 25.92 ;
    END
  END t1a[252]
  PIN t1a[253]
    DIRECTION INPUT ;
    USE SIGNAL ;
    PORT
      LAYER M5 ;
        RECT  38.832 25.836 38.856 25.92 ;
    END
  END t1a[253]
  PIN t1a[254]
    DIRECTION INPUT ;
    USE SIGNAL ;
    PORT
      LAYER M5 ;
        RECT  38.928 25.836 38.952 25.92 ;
    END
  END t1a[254]
  PIN t1a[255]
    DIRECTION INPUT ;
    USE SIGNAL ;
    PORT
      LAYER M5 ;
        RECT  39.024 25.836 39.048 25.92 ;
    END
  END t1a[255]
  PIN t1a[256]
    DIRECTION INPUT ;
    USE SIGNAL ;
    PORT
      LAYER M5 ;
        RECT  103.632 25.836 103.656 25.92 ;
    END
  END t1a[256]
  PIN t1a[257]
    DIRECTION INPUT ;
    USE SIGNAL ;
    PORT
      LAYER M5 ;
        RECT  103.728 25.836 103.752 25.92 ;
    END
  END t1a[257]
  PIN t1a[258]
    DIRECTION INPUT ;
    USE SIGNAL ;
    PORT
      LAYER M5 ;
        RECT  103.824 25.836 103.848 25.92 ;
    END
  END t1a[258]
  PIN t1a[259]
    DIRECTION INPUT ;
    USE SIGNAL ;
    PORT
      LAYER M5 ;
        RECT  103.92 25.836 103.944 25.92 ;
    END
  END t1a[259]
  PIN t1a[25]
    DIRECTION INPUT ;
    USE SIGNAL ;
    PORT
      LAYER M5 ;
        RECT  35.376 25.836 35.4 25.92 ;
    END
  END t1a[25]
  PIN t1a[260]
    DIRECTION INPUT ;
    USE SIGNAL ;
    PORT
      LAYER M5 ;
        RECT  104.016 25.836 104.04 25.92 ;
    END
  END t1a[260]
  PIN t1a[261]
    DIRECTION INPUT ;
    USE SIGNAL ;
    PORT
      LAYER M5 ;
        RECT  104.112 25.836 104.136 25.92 ;
    END
  END t1a[261]
  PIN t1a[262]
    DIRECTION INPUT ;
    USE SIGNAL ;
    PORT
      LAYER M5 ;
        RECT  104.208 25.836 104.232 25.92 ;
    END
  END t1a[262]
  PIN t1a[263]
    DIRECTION INPUT ;
    USE SIGNAL ;
    PORT
      LAYER M5 ;
        RECT  104.304 25.836 104.328 25.92 ;
    END
  END t1a[263]
  PIN t1a[264]
    DIRECTION INPUT ;
    USE SIGNAL ;
    PORT
      LAYER M5 ;
        RECT  104.4 25.836 104.424 25.92 ;
    END
  END t1a[264]
  PIN t1a[265]
    DIRECTION INPUT ;
    USE SIGNAL ;
    PORT
      LAYER M5 ;
        RECT  104.496 25.836 104.52 25.92 ;
    END
  END t1a[265]
  PIN t1a[266]
    DIRECTION INPUT ;
    USE SIGNAL ;
    PORT
      LAYER M5 ;
        RECT  104.592 25.836 104.616 25.92 ;
    END
  END t1a[266]
  PIN t1a[267]
    DIRECTION INPUT ;
    USE SIGNAL ;
    PORT
      LAYER M5 ;
        RECT  104.688 25.836 104.712 25.92 ;
    END
  END t1a[267]
  PIN t1a[268]
    DIRECTION INPUT ;
    USE SIGNAL ;
    PORT
      LAYER M5 ;
        RECT  104.784 25.836 104.808 25.92 ;
    END
  END t1a[268]
  PIN t1a[269]
    DIRECTION INPUT ;
    USE SIGNAL ;
    PORT
      LAYER M5 ;
        RECT  104.88 25.836 104.904 25.92 ;
    END
  END t1a[269]
  PIN t1a[26]
    DIRECTION INPUT ;
    USE SIGNAL ;
    PORT
      LAYER M5 ;
        RECT  35.472 25.836 35.496 25.92 ;
    END
  END t1a[26]
  PIN t1a[270]
    DIRECTION INPUT ;
    USE SIGNAL ;
    PORT
      LAYER M5 ;
        RECT  104.976 25.836 105 25.92 ;
    END
  END t1a[270]
  PIN t1a[271]
    DIRECTION INPUT ;
    USE SIGNAL ;
    PORT
      LAYER M5 ;
        RECT  105.072 25.836 105.096 25.92 ;
    END
  END t1a[271]
  PIN t1a[272]
    DIRECTION INPUT ;
    USE SIGNAL ;
    PORT
      LAYER M5 ;
        RECT  105.168 25.836 105.192 25.92 ;
    END
  END t1a[272]
  PIN t1a[273]
    DIRECTION INPUT ;
    USE SIGNAL ;
    PORT
      LAYER M5 ;
        RECT  105.264 25.836 105.288 25.92 ;
    END
  END t1a[273]
  PIN t1a[274]
    DIRECTION INPUT ;
    USE SIGNAL ;
    PORT
      LAYER M5 ;
        RECT  105.36 25.836 105.384 25.92 ;
    END
  END t1a[274]
  PIN t1a[275]
    DIRECTION INPUT ;
    USE SIGNAL ;
    PORT
      LAYER M5 ;
        RECT  105.456 25.836 105.48 25.92 ;
    END
  END t1a[275]
  PIN t1a[276]
    DIRECTION INPUT ;
    USE SIGNAL ;
    PORT
      LAYER M5 ;
        RECT  105.552 25.836 105.576 25.92 ;
    END
  END t1a[276]
  PIN t1a[277]
    DIRECTION INPUT ;
    USE SIGNAL ;
    PORT
      LAYER M5 ;
        RECT  105.648 25.836 105.672 25.92 ;
    END
  END t1a[277]
  PIN t1a[278]
    DIRECTION INPUT ;
    USE SIGNAL ;
    PORT
      LAYER M5 ;
        RECT  105.744 25.836 105.768 25.92 ;
    END
  END t1a[278]
  PIN t1a[279]
    DIRECTION INPUT ;
    USE SIGNAL ;
    PORT
      LAYER M5 ;
        RECT  105.84 25.836 105.864 25.92 ;
    END
  END t1a[279]
  PIN t1a[27]
    DIRECTION INPUT ;
    USE SIGNAL ;
    PORT
      LAYER M5 ;
        RECT  35.568 25.836 35.592 25.92 ;
    END
  END t1a[27]
  PIN t1a[280]
    DIRECTION INPUT ;
    USE SIGNAL ;
    PORT
      LAYER M5 ;
        RECT  105.936 25.836 105.96 25.92 ;
    END
  END t1a[280]
  PIN t1a[281]
    DIRECTION INPUT ;
    USE SIGNAL ;
    PORT
      LAYER M5 ;
        RECT  106.032 25.836 106.056 25.92 ;
    END
  END t1a[281]
  PIN t1a[282]
    DIRECTION INPUT ;
    USE SIGNAL ;
    PORT
      LAYER M5 ;
        RECT  106.128 25.836 106.152 25.92 ;
    END
  END t1a[282]
  PIN t1a[283]
    DIRECTION INPUT ;
    USE SIGNAL ;
    PORT
      LAYER M5 ;
        RECT  106.224 25.836 106.248 25.92 ;
    END
  END t1a[283]
  PIN t1a[284]
    DIRECTION INPUT ;
    USE SIGNAL ;
    PORT
      LAYER M5 ;
        RECT  106.32 25.836 106.344 25.92 ;
    END
  END t1a[284]
  PIN t1a[285]
    DIRECTION INPUT ;
    USE SIGNAL ;
    PORT
      LAYER M5 ;
        RECT  106.416 25.836 106.44 25.92 ;
    END
  END t1a[285]
  PIN t1a[286]
    DIRECTION INPUT ;
    USE SIGNAL ;
    PORT
      LAYER M5 ;
        RECT  106.512 25.836 106.536 25.92 ;
    END
  END t1a[286]
  PIN t1a[287]
    DIRECTION INPUT ;
    USE SIGNAL ;
    PORT
      LAYER M5 ;
        RECT  106.608 25.836 106.632 25.92 ;
    END
  END t1a[287]
  PIN t1a[288]
    DIRECTION INPUT ;
    USE SIGNAL ;
    PORT
      LAYER M5 ;
        RECT  97.488 25.836 97.512 25.92 ;
    END
  END t1a[288]
  PIN t1a[289]
    DIRECTION INPUT ;
    USE SIGNAL ;
    PORT
      LAYER M5 ;
        RECT  97.584 25.836 97.608 25.92 ;
    END
  END t1a[289]
  PIN t1a[28]
    DIRECTION INPUT ;
    USE SIGNAL ;
    PORT
      LAYER M5 ;
        RECT  35.664 25.836 35.688 25.92 ;
    END
  END t1a[28]
  PIN t1a[290]
    DIRECTION INPUT ;
    USE SIGNAL ;
    PORT
      LAYER M5 ;
        RECT  97.68 25.836 97.704 25.92 ;
    END
  END t1a[290]
  PIN t1a[291]
    DIRECTION INPUT ;
    USE SIGNAL ;
    PORT
      LAYER M5 ;
        RECT  97.776 25.836 97.8 25.92 ;
    END
  END t1a[291]
  PIN t1a[292]
    DIRECTION INPUT ;
    USE SIGNAL ;
    PORT
      LAYER M5 ;
        RECT  97.872 25.836 97.896 25.92 ;
    END
  END t1a[292]
  PIN t1a[293]
    DIRECTION INPUT ;
    USE SIGNAL ;
    PORT
      LAYER M5 ;
        RECT  97.968 25.836 97.992 25.92 ;
    END
  END t1a[293]
  PIN t1a[294]
    DIRECTION INPUT ;
    USE SIGNAL ;
    PORT
      LAYER M5 ;
        RECT  98.064 25.836 98.088 25.92 ;
    END
  END t1a[294]
  PIN t1a[295]
    DIRECTION INPUT ;
    USE SIGNAL ;
    PORT
      LAYER M5 ;
        RECT  98.16 25.836 98.184 25.92 ;
    END
  END t1a[295]
  PIN t1a[296]
    DIRECTION INPUT ;
    USE SIGNAL ;
    PORT
      LAYER M5 ;
        RECT  98.256 25.836 98.28 25.92 ;
    END
  END t1a[296]
  PIN t1a[297]
    DIRECTION INPUT ;
    USE SIGNAL ;
    PORT
      LAYER M5 ;
        RECT  98.352 25.836 98.376 25.92 ;
    END
  END t1a[297]
  PIN t1a[298]
    DIRECTION INPUT ;
    USE SIGNAL ;
    PORT
      LAYER M5 ;
        RECT  98.448 25.836 98.472 25.92 ;
    END
  END t1a[298]
  PIN t1a[299]
    DIRECTION INPUT ;
    USE SIGNAL ;
    PORT
      LAYER M5 ;
        RECT  98.544 25.836 98.568 25.92 ;
    END
  END t1a[299]
  PIN t1a[29]
    DIRECTION INPUT ;
    USE SIGNAL ;
    PORT
      LAYER M5 ;
        RECT  35.76 25.836 35.784 25.92 ;
    END
  END t1a[29]
  PIN t1a[2]
    DIRECTION INPUT ;
    USE SIGNAL ;
    PORT
      LAYER M5 ;
        RECT  33.168 25.836 33.192 25.92 ;
    END
  END t1a[2]
  PIN t1a[300]
    DIRECTION INPUT ;
    USE SIGNAL ;
    PORT
      LAYER M5 ;
        RECT  98.64 25.836 98.664 25.92 ;
    END
  END t1a[300]
  PIN t1a[301]
    DIRECTION INPUT ;
    USE SIGNAL ;
    PORT
      LAYER M5 ;
        RECT  98.736 25.836 98.76 25.92 ;
    END
  END t1a[301]
  PIN t1a[302]
    DIRECTION INPUT ;
    USE SIGNAL ;
    PORT
      LAYER M5 ;
        RECT  98.832 25.836 98.856 25.92 ;
    END
  END t1a[302]
  PIN t1a[303]
    DIRECTION INPUT ;
    USE SIGNAL ;
    PORT
      LAYER M5 ;
        RECT  98.928 25.836 98.952 25.92 ;
    END
  END t1a[303]
  PIN t1a[304]
    DIRECTION INPUT ;
    USE SIGNAL ;
    PORT
      LAYER M5 ;
        RECT  99.024 25.836 99.048 25.92 ;
    END
  END t1a[304]
  PIN t1a[305]
    DIRECTION INPUT ;
    USE SIGNAL ;
    PORT
      LAYER M5 ;
        RECT  99.12 25.836 99.144 25.92 ;
    END
  END t1a[305]
  PIN t1a[306]
    DIRECTION INPUT ;
    USE SIGNAL ;
    PORT
      LAYER M5 ;
        RECT  99.216 25.836 99.24 25.92 ;
    END
  END t1a[306]
  PIN t1a[307]
    DIRECTION INPUT ;
    USE SIGNAL ;
    PORT
      LAYER M5 ;
        RECT  99.312 25.836 99.336 25.92 ;
    END
  END t1a[307]
  PIN t1a[308]
    DIRECTION INPUT ;
    USE SIGNAL ;
    PORT
      LAYER M5 ;
        RECT  99.408 25.836 99.432 25.92 ;
    END
  END t1a[308]
  PIN t1a[309]
    DIRECTION INPUT ;
    USE SIGNAL ;
    PORT
      LAYER M5 ;
        RECT  99.504 25.836 99.528 25.92 ;
    END
  END t1a[309]
  PIN t1a[30]
    DIRECTION INPUT ;
    USE SIGNAL ;
    PORT
      LAYER M5 ;
        RECT  35.856 25.836 35.88 25.92 ;
    END
  END t1a[30]
  PIN t1a[310]
    DIRECTION INPUT ;
    USE SIGNAL ;
    PORT
      LAYER M5 ;
        RECT  99.6 25.836 99.624 25.92 ;
    END
  END t1a[310]
  PIN t1a[311]
    DIRECTION INPUT ;
    USE SIGNAL ;
    PORT
      LAYER M5 ;
        RECT  99.696 25.836 99.72 25.92 ;
    END
  END t1a[311]
  PIN t1a[312]
    DIRECTION INPUT ;
    USE SIGNAL ;
    PORT
      LAYER M5 ;
        RECT  99.792 25.836 99.816 25.92 ;
    END
  END t1a[312]
  PIN t1a[313]
    DIRECTION INPUT ;
    USE SIGNAL ;
    PORT
      LAYER M5 ;
        RECT  99.888 25.836 99.912 25.92 ;
    END
  END t1a[313]
  PIN t1a[314]
    DIRECTION INPUT ;
    USE SIGNAL ;
    PORT
      LAYER M5 ;
        RECT  99.984 25.836 100.008 25.92 ;
    END
  END t1a[314]
  PIN t1a[315]
    DIRECTION INPUT ;
    USE SIGNAL ;
    PORT
      LAYER M5 ;
        RECT  100.08 25.836 100.104 25.92 ;
    END
  END t1a[315]
  PIN t1a[316]
    DIRECTION INPUT ;
    USE SIGNAL ;
    PORT
      LAYER M5 ;
        RECT  100.176 25.836 100.2 25.92 ;
    END
  END t1a[316]
  PIN t1a[317]
    DIRECTION INPUT ;
    USE SIGNAL ;
    PORT
      LAYER M5 ;
        RECT  100.272 25.836 100.296 25.92 ;
    END
  END t1a[317]
  PIN t1a[318]
    DIRECTION INPUT ;
    USE SIGNAL ;
    PORT
      LAYER M5 ;
        RECT  100.368 25.836 100.392 25.92 ;
    END
  END t1a[318]
  PIN t1a[319]
    DIRECTION INPUT ;
    USE SIGNAL ;
    PORT
      LAYER M5 ;
        RECT  100.464 25.836 100.488 25.92 ;
    END
  END t1a[319]
  PIN t1a[31]
    DIRECTION INPUT ;
    USE SIGNAL ;
    PORT
      LAYER M5 ;
        RECT  35.952 25.836 35.976 25.92 ;
    END
  END t1a[31]
  PIN t1a[320]
    DIRECTION INPUT ;
    USE SIGNAL ;
    PORT
      LAYER M5 ;
        RECT  13.776 25.836 13.8 25.92 ;
    END
  END t1a[320]
  PIN t1a[321]
    DIRECTION INPUT ;
    USE SIGNAL ;
    PORT
      LAYER M5 ;
        RECT  13.872 25.836 13.896 25.92 ;
    END
  END t1a[321]
  PIN t1a[322]
    DIRECTION INPUT ;
    USE SIGNAL ;
    PORT
      LAYER M5 ;
        RECT  13.968 25.836 13.992 25.92 ;
    END
  END t1a[322]
  PIN t1a[323]
    DIRECTION INPUT ;
    USE SIGNAL ;
    PORT
      LAYER M5 ;
        RECT  14.064 25.836 14.088 25.92 ;
    END
  END t1a[323]
  PIN t1a[324]
    DIRECTION INPUT ;
    USE SIGNAL ;
    PORT
      LAYER M5 ;
        RECT  14.16 25.836 14.184 25.92 ;
    END
  END t1a[324]
  PIN t1a[325]
    DIRECTION INPUT ;
    USE SIGNAL ;
    PORT
      LAYER M5 ;
        RECT  14.256 25.836 14.28 25.92 ;
    END
  END t1a[325]
  PIN t1a[326]
    DIRECTION INPUT ;
    USE SIGNAL ;
    PORT
      LAYER M5 ;
        RECT  14.352 25.836 14.376 25.92 ;
    END
  END t1a[326]
  PIN t1a[327]
    DIRECTION INPUT ;
    USE SIGNAL ;
    PORT
      LAYER M5 ;
        RECT  14.448 25.836 14.472 25.92 ;
    END
  END t1a[327]
  PIN t1a[328]
    DIRECTION INPUT ;
    USE SIGNAL ;
    PORT
      LAYER M5 ;
        RECT  14.544 25.836 14.568 25.92 ;
    END
  END t1a[328]
  PIN t1a[329]
    DIRECTION INPUT ;
    USE SIGNAL ;
    PORT
      LAYER M5 ;
        RECT  14.64 25.836 14.664 25.92 ;
    END
  END t1a[329]
  PIN t1a[32]
    DIRECTION INPUT ;
    USE SIGNAL ;
    PORT
      LAYER M5 ;
        RECT  78.288 25.836 78.312 25.92 ;
    END
  END t1a[32]
  PIN t1a[330]
    DIRECTION INPUT ;
    USE SIGNAL ;
    PORT
      LAYER M5 ;
        RECT  14.736 25.836 14.76 25.92 ;
    END
  END t1a[330]
  PIN t1a[331]
    DIRECTION INPUT ;
    USE SIGNAL ;
    PORT
      LAYER M5 ;
        RECT  14.832 25.836 14.856 25.92 ;
    END
  END t1a[331]
  PIN t1a[332]
    DIRECTION INPUT ;
    USE SIGNAL ;
    PORT
      LAYER M5 ;
        RECT  14.928 25.836 14.952 25.92 ;
    END
  END t1a[332]
  PIN t1a[333]
    DIRECTION INPUT ;
    USE SIGNAL ;
    PORT
      LAYER M5 ;
        RECT  15.024 25.836 15.048 25.92 ;
    END
  END t1a[333]
  PIN t1a[334]
    DIRECTION INPUT ;
    USE SIGNAL ;
    PORT
      LAYER M5 ;
        RECT  15.12 25.836 15.144 25.92 ;
    END
  END t1a[334]
  PIN t1a[335]
    DIRECTION INPUT ;
    USE SIGNAL ;
    PORT
      LAYER M5 ;
        RECT  15.216 25.836 15.24 25.92 ;
    END
  END t1a[335]
  PIN t1a[336]
    DIRECTION INPUT ;
    USE SIGNAL ;
    PORT
      LAYER M5 ;
        RECT  15.312 25.836 15.336 25.92 ;
    END
  END t1a[336]
  PIN t1a[337]
    DIRECTION INPUT ;
    USE SIGNAL ;
    PORT
      LAYER M5 ;
        RECT  15.408 25.836 15.432 25.92 ;
    END
  END t1a[337]
  PIN t1a[338]
    DIRECTION INPUT ;
    USE SIGNAL ;
    PORT
      LAYER M5 ;
        RECT  15.504 25.836 15.528 25.92 ;
    END
  END t1a[338]
  PIN t1a[339]
    DIRECTION INPUT ;
    USE SIGNAL ;
    PORT
      LAYER M5 ;
        RECT  15.6 25.836 15.624 25.92 ;
    END
  END t1a[339]
  PIN t1a[33]
    DIRECTION INPUT ;
    USE SIGNAL ;
    PORT
      LAYER M5 ;
        RECT  78.384 25.836 78.408 25.92 ;
    END
  END t1a[33]
  PIN t1a[340]
    DIRECTION INPUT ;
    USE SIGNAL ;
    PORT
      LAYER M5 ;
        RECT  15.696 25.836 15.72 25.92 ;
    END
  END t1a[340]
  PIN t1a[341]
    DIRECTION INPUT ;
    USE SIGNAL ;
    PORT
      LAYER M5 ;
        RECT  15.792 25.836 15.816 25.92 ;
    END
  END t1a[341]
  PIN t1a[342]
    DIRECTION INPUT ;
    USE SIGNAL ;
    PORT
      LAYER M5 ;
        RECT  15.888 25.836 15.912 25.92 ;
    END
  END t1a[342]
  PIN t1a[343]
    DIRECTION INPUT ;
    USE SIGNAL ;
    PORT
      LAYER M5 ;
        RECT  15.984 25.836 16.008 25.92 ;
    END
  END t1a[343]
  PIN t1a[344]
    DIRECTION INPUT ;
    USE SIGNAL ;
    PORT
      LAYER M5 ;
        RECT  16.08 25.836 16.104 25.92 ;
    END
  END t1a[344]
  PIN t1a[345]
    DIRECTION INPUT ;
    USE SIGNAL ;
    PORT
      LAYER M5 ;
        RECT  16.176 25.836 16.2 25.92 ;
    END
  END t1a[345]
  PIN t1a[346]
    DIRECTION INPUT ;
    USE SIGNAL ;
    PORT
      LAYER M5 ;
        RECT  16.272 25.836 16.296 25.92 ;
    END
  END t1a[346]
  PIN t1a[347]
    DIRECTION INPUT ;
    USE SIGNAL ;
    PORT
      LAYER M5 ;
        RECT  16.368 25.836 16.392 25.92 ;
    END
  END t1a[347]
  PIN t1a[348]
    DIRECTION INPUT ;
    USE SIGNAL ;
    PORT
      LAYER M5 ;
        RECT  16.464 25.836 16.488 25.92 ;
    END
  END t1a[348]
  PIN t1a[349]
    DIRECTION INPUT ;
    USE SIGNAL ;
    PORT
      LAYER M5 ;
        RECT  16.56 25.836 16.584 25.92 ;
    END
  END t1a[349]
  PIN t1a[34]
    DIRECTION INPUT ;
    USE SIGNAL ;
    PORT
      LAYER M5 ;
        RECT  78.48 25.836 78.504 25.92 ;
    END
  END t1a[34]
  PIN t1a[350]
    DIRECTION INPUT ;
    USE SIGNAL ;
    PORT
      LAYER M5 ;
        RECT  16.656 25.836 16.68 25.92 ;
    END
  END t1a[350]
  PIN t1a[351]
    DIRECTION INPUT ;
    USE SIGNAL ;
    PORT
      LAYER M5 ;
        RECT  16.752 25.836 16.776 25.92 ;
    END
  END t1a[351]
  PIN t1a[352]
    DIRECTION INPUT ;
    USE SIGNAL ;
    PORT
      LAYER M5 ;
        RECT  100.56 25.836 100.584 25.92 ;
    END
  END t1a[352]
  PIN t1a[353]
    DIRECTION INPUT ;
    USE SIGNAL ;
    PORT
      LAYER M5 ;
        RECT  100.656 25.836 100.68 25.92 ;
    END
  END t1a[353]
  PIN t1a[354]
    DIRECTION INPUT ;
    USE SIGNAL ;
    PORT
      LAYER M5 ;
        RECT  100.752 25.836 100.776 25.92 ;
    END
  END t1a[354]
  PIN t1a[355]
    DIRECTION INPUT ;
    USE SIGNAL ;
    PORT
      LAYER M5 ;
        RECT  100.848 25.836 100.872 25.92 ;
    END
  END t1a[355]
  PIN t1a[356]
    DIRECTION INPUT ;
    USE SIGNAL ;
    PORT
      LAYER M5 ;
        RECT  100.944 25.836 100.968 25.92 ;
    END
  END t1a[356]
  PIN t1a[357]
    DIRECTION INPUT ;
    USE SIGNAL ;
    PORT
      LAYER M5 ;
        RECT  101.04 25.836 101.064 25.92 ;
    END
  END t1a[357]
  PIN t1a[358]
    DIRECTION INPUT ;
    USE SIGNAL ;
    PORT
      LAYER M5 ;
        RECT  101.136 25.836 101.16 25.92 ;
    END
  END t1a[358]
  PIN t1a[359]
    DIRECTION INPUT ;
    USE SIGNAL ;
    PORT
      LAYER M5 ;
        RECT  101.232 25.836 101.256 25.92 ;
    END
  END t1a[359]
  PIN t1a[35]
    DIRECTION INPUT ;
    USE SIGNAL ;
    PORT
      LAYER M5 ;
        RECT  78.576 25.836 78.6 25.92 ;
    END
  END t1a[35]
  PIN t1a[360]
    DIRECTION INPUT ;
    USE SIGNAL ;
    PORT
      LAYER M5 ;
        RECT  101.328 25.836 101.352 25.92 ;
    END
  END t1a[360]
  PIN t1a[361]
    DIRECTION INPUT ;
    USE SIGNAL ;
    PORT
      LAYER M5 ;
        RECT  101.424 25.836 101.448 25.92 ;
    END
  END t1a[361]
  PIN t1a[362]
    DIRECTION INPUT ;
    USE SIGNAL ;
    PORT
      LAYER M5 ;
        RECT  101.52 25.836 101.544 25.92 ;
    END
  END t1a[362]
  PIN t1a[363]
    DIRECTION INPUT ;
    USE SIGNAL ;
    PORT
      LAYER M5 ;
        RECT  101.616 25.836 101.64 25.92 ;
    END
  END t1a[363]
  PIN t1a[364]
    DIRECTION INPUT ;
    USE SIGNAL ;
    PORT
      LAYER M5 ;
        RECT  101.712 25.836 101.736 25.92 ;
    END
  END t1a[364]
  PIN t1a[365]
    DIRECTION INPUT ;
    USE SIGNAL ;
    PORT
      LAYER M5 ;
        RECT  101.808 25.836 101.832 25.92 ;
    END
  END t1a[365]
  PIN t1a[366]
    DIRECTION INPUT ;
    USE SIGNAL ;
    PORT
      LAYER M5 ;
        RECT  101.904 25.836 101.928 25.92 ;
    END
  END t1a[366]
  PIN t1a[367]
    DIRECTION INPUT ;
    USE SIGNAL ;
    PORT
      LAYER M5 ;
        RECT  102 25.836 102.024 25.92 ;
    END
  END t1a[367]
  PIN t1a[368]
    DIRECTION INPUT ;
    USE SIGNAL ;
    PORT
      LAYER M5 ;
        RECT  102.096 25.836 102.12 25.92 ;
    END
  END t1a[368]
  PIN t1a[369]
    DIRECTION INPUT ;
    USE SIGNAL ;
    PORT
      LAYER M5 ;
        RECT  102.192 25.836 102.216 25.92 ;
    END
  END t1a[369]
  PIN t1a[36]
    DIRECTION INPUT ;
    USE SIGNAL ;
    PORT
      LAYER M5 ;
        RECT  78.672 25.836 78.696 25.92 ;
    END
  END t1a[36]
  PIN t1a[370]
    DIRECTION INPUT ;
    USE SIGNAL ;
    PORT
      LAYER M5 ;
        RECT  102.288 25.836 102.312 25.92 ;
    END
  END t1a[370]
  PIN t1a[371]
    DIRECTION INPUT ;
    USE SIGNAL ;
    PORT
      LAYER M5 ;
        RECT  102.384 25.836 102.408 25.92 ;
    END
  END t1a[371]
  PIN t1a[372]
    DIRECTION INPUT ;
    USE SIGNAL ;
    PORT
      LAYER M5 ;
        RECT  102.48 25.836 102.504 25.92 ;
    END
  END t1a[372]
  PIN t1a[373]
    DIRECTION INPUT ;
    USE SIGNAL ;
    PORT
      LAYER M5 ;
        RECT  102.576 25.836 102.6 25.92 ;
    END
  END t1a[373]
  PIN t1a[374]
    DIRECTION INPUT ;
    USE SIGNAL ;
    PORT
      LAYER M5 ;
        RECT  102.672 25.836 102.696 25.92 ;
    END
  END t1a[374]
  PIN t1a[375]
    DIRECTION INPUT ;
    USE SIGNAL ;
    PORT
      LAYER M5 ;
        RECT  102.768 25.836 102.792 25.92 ;
    END
  END t1a[375]
  PIN t1a[376]
    DIRECTION INPUT ;
    USE SIGNAL ;
    PORT
      LAYER M5 ;
        RECT  102.864 25.836 102.888 25.92 ;
    END
  END t1a[376]
  PIN t1a[377]
    DIRECTION INPUT ;
    USE SIGNAL ;
    PORT
      LAYER M5 ;
        RECT  102.96 25.836 102.984 25.92 ;
    END
  END t1a[377]
  PIN t1a[378]
    DIRECTION INPUT ;
    USE SIGNAL ;
    PORT
      LAYER M5 ;
        RECT  103.056 25.836 103.08 25.92 ;
    END
  END t1a[378]
  PIN t1a[379]
    DIRECTION INPUT ;
    USE SIGNAL ;
    PORT
      LAYER M5 ;
        RECT  103.152 25.836 103.176 25.92 ;
    END
  END t1a[379]
  PIN t1a[37]
    DIRECTION INPUT ;
    USE SIGNAL ;
    PORT
      LAYER M5 ;
        RECT  78.768 25.836 78.792 25.92 ;
    END
  END t1a[37]
  PIN t1a[380]
    DIRECTION INPUT ;
    USE SIGNAL ;
    PORT
      LAYER M5 ;
        RECT  103.248 25.836 103.272 25.92 ;
    END
  END t1a[380]
  PIN t1a[381]
    DIRECTION INPUT ;
    USE SIGNAL ;
    PORT
      LAYER M5 ;
        RECT  103.344 25.836 103.368 25.92 ;
    END
  END t1a[381]
  PIN t1a[382]
    DIRECTION INPUT ;
    USE SIGNAL ;
    PORT
      LAYER M5 ;
        RECT  103.44 25.836 103.464 25.92 ;
    END
  END t1a[382]
  PIN t1a[383]
    DIRECTION INPUT ;
    USE SIGNAL ;
    PORT
      LAYER M5 ;
        RECT  103.536 25.836 103.56 25.92 ;
    END
  END t1a[383]
  PIN t1a[384]
    DIRECTION INPUT ;
    USE SIGNAL ;
    PORT
      LAYER M5 ;
        RECT  16.848 25.836 16.872 25.92 ;
    END
  END t1a[384]
  PIN t1a[385]
    DIRECTION INPUT ;
    USE SIGNAL ;
    PORT
      LAYER M5 ;
        RECT  16.944 25.836 16.968 25.92 ;
    END
  END t1a[385]
  PIN t1a[386]
    DIRECTION INPUT ;
    USE SIGNAL ;
    PORT
      LAYER M5 ;
        RECT  17.04 25.836 17.064 25.92 ;
    END
  END t1a[386]
  PIN t1a[387]
    DIRECTION INPUT ;
    USE SIGNAL ;
    PORT
      LAYER M5 ;
        RECT  17.136 25.836 17.16 25.92 ;
    END
  END t1a[387]
  PIN t1a[388]
    DIRECTION INPUT ;
    USE SIGNAL ;
    PORT
      LAYER M5 ;
        RECT  17.232 25.836 17.256 25.92 ;
    END
  END t1a[388]
  PIN t1a[389]
    DIRECTION INPUT ;
    USE SIGNAL ;
    PORT
      LAYER M5 ;
        RECT  17.328 25.836 17.352 25.92 ;
    END
  END t1a[389]
  PIN t1a[38]
    DIRECTION INPUT ;
    USE SIGNAL ;
    PORT
      LAYER M5 ;
        RECT  78.864 25.836 78.888 25.92 ;
    END
  END t1a[38]
  PIN t1a[390]
    DIRECTION INPUT ;
    USE SIGNAL ;
    PORT
      LAYER M5 ;
        RECT  17.424 25.836 17.448 25.92 ;
    END
  END t1a[390]
  PIN t1a[391]
    DIRECTION INPUT ;
    USE SIGNAL ;
    PORT
      LAYER M5 ;
        RECT  17.52 25.836 17.544 25.92 ;
    END
  END t1a[391]
  PIN t1a[392]
    DIRECTION INPUT ;
    USE SIGNAL ;
    PORT
      LAYER M5 ;
        RECT  17.616 25.836 17.64 25.92 ;
    END
  END t1a[392]
  PIN t1a[393]
    DIRECTION INPUT ;
    USE SIGNAL ;
    PORT
      LAYER M5 ;
        RECT  17.712 25.836 17.736 25.92 ;
    END
  END t1a[393]
  PIN t1a[394]
    DIRECTION INPUT ;
    USE SIGNAL ;
    PORT
      LAYER M5 ;
        RECT  17.808 25.836 17.832 25.92 ;
    END
  END t1a[394]
  PIN t1a[395]
    DIRECTION INPUT ;
    USE SIGNAL ;
    PORT
      LAYER M5 ;
        RECT  17.904 25.836 17.928 25.92 ;
    END
  END t1a[395]
  PIN t1a[396]
    DIRECTION INPUT ;
    USE SIGNAL ;
    PORT
      LAYER M5 ;
        RECT  18 25.836 18.024 25.92 ;
    END
  END t1a[396]
  PIN t1a[397]
    DIRECTION INPUT ;
    USE SIGNAL ;
    PORT
      LAYER M5 ;
        RECT  18.096 25.836 18.12 25.92 ;
    END
  END t1a[397]
  PIN t1a[398]
    DIRECTION INPUT ;
    USE SIGNAL ;
    PORT
      LAYER M5 ;
        RECT  18.192 25.836 18.216 25.92 ;
    END
  END t1a[398]
  PIN t1a[399]
    DIRECTION INPUT ;
    USE SIGNAL ;
    PORT
      LAYER M5 ;
        RECT  18.288 25.836 18.312 25.92 ;
    END
  END t1a[399]
  PIN t1a[39]
    DIRECTION INPUT ;
    USE SIGNAL ;
    PORT
      LAYER M5 ;
        RECT  78.96 25.836 78.984 25.92 ;
    END
  END t1a[39]
  PIN t1a[3]
    DIRECTION INPUT ;
    USE SIGNAL ;
    PORT
      LAYER M5 ;
        RECT  33.264 25.836 33.288 25.92 ;
    END
  END t1a[3]
  PIN t1a[400]
    DIRECTION INPUT ;
    USE SIGNAL ;
    PORT
      LAYER M5 ;
        RECT  18.384 25.836 18.408 25.92 ;
    END
  END t1a[400]
  PIN t1a[401]
    DIRECTION INPUT ;
    USE SIGNAL ;
    PORT
      LAYER M5 ;
        RECT  18.48 25.836 18.504 25.92 ;
    END
  END t1a[401]
  PIN t1a[402]
    DIRECTION INPUT ;
    USE SIGNAL ;
    PORT
      LAYER M5 ;
        RECT  18.576 25.836 18.6 25.92 ;
    END
  END t1a[402]
  PIN t1a[403]
    DIRECTION INPUT ;
    USE SIGNAL ;
    PORT
      LAYER M5 ;
        RECT  18.672 25.836 18.696 25.92 ;
    END
  END t1a[403]
  PIN t1a[404]
    DIRECTION INPUT ;
    USE SIGNAL ;
    PORT
      LAYER M5 ;
        RECT  18.768 25.836 18.792 25.92 ;
    END
  END t1a[404]
  PIN t1a[405]
    DIRECTION INPUT ;
    USE SIGNAL ;
    PORT
      LAYER M5 ;
        RECT  18.864 25.836 18.888 25.92 ;
    END
  END t1a[405]
  PIN t1a[406]
    DIRECTION INPUT ;
    USE SIGNAL ;
    PORT
      LAYER M5 ;
        RECT  18.96 25.836 18.984 25.92 ;
    END
  END t1a[406]
  PIN t1a[407]
    DIRECTION INPUT ;
    USE SIGNAL ;
    PORT
      LAYER M5 ;
        RECT  19.056 25.836 19.08 25.92 ;
    END
  END t1a[407]
  PIN t1a[408]
    DIRECTION INPUT ;
    USE SIGNAL ;
    PORT
      LAYER M5 ;
        RECT  19.152 25.836 19.176 25.92 ;
    END
  END t1a[408]
  PIN t1a[409]
    DIRECTION INPUT ;
    USE SIGNAL ;
    PORT
      LAYER M5 ;
        RECT  19.248 25.836 19.272 25.92 ;
    END
  END t1a[409]
  PIN t1a[40]
    DIRECTION INPUT ;
    USE SIGNAL ;
    PORT
      LAYER M5 ;
        RECT  79.056 25.836 79.08 25.92 ;
    END
  END t1a[40]
  PIN t1a[410]
    DIRECTION INPUT ;
    USE SIGNAL ;
    PORT
      LAYER M5 ;
        RECT  19.344 25.836 19.368 25.92 ;
    END
  END t1a[410]
  PIN t1a[411]
    DIRECTION INPUT ;
    USE SIGNAL ;
    PORT
      LAYER M5 ;
        RECT  19.44 25.836 19.464 25.92 ;
    END
  END t1a[411]
  PIN t1a[412]
    DIRECTION INPUT ;
    USE SIGNAL ;
    PORT
      LAYER M5 ;
        RECT  19.536 25.836 19.56 25.92 ;
    END
  END t1a[412]
  PIN t1a[413]
    DIRECTION INPUT ;
    USE SIGNAL ;
    PORT
      LAYER M5 ;
        RECT  19.632 25.836 19.656 25.92 ;
    END
  END t1a[413]
  PIN t1a[414]
    DIRECTION INPUT ;
    USE SIGNAL ;
    PORT
      LAYER M5 ;
        RECT  19.728 25.836 19.752 25.92 ;
    END
  END t1a[414]
  PIN t1a[415]
    DIRECTION INPUT ;
    USE SIGNAL ;
    PORT
      LAYER M5 ;
        RECT  19.824 25.836 19.848 25.92 ;
    END
  END t1a[415]
  PIN t1a[416]
    DIRECTION INPUT ;
    USE SIGNAL ;
    PORT
      LAYER M5 ;
        RECT  10.704 25.836 10.728 25.92 ;
    END
  END t1a[416]
  PIN t1a[417]
    DIRECTION INPUT ;
    USE SIGNAL ;
    PORT
      LAYER M5 ;
        RECT  10.8 25.836 10.824 25.92 ;
    END
  END t1a[417]
  PIN t1a[418]
    DIRECTION INPUT ;
    USE SIGNAL ;
    PORT
      LAYER M5 ;
        RECT  10.896 25.836 10.92 25.92 ;
    END
  END t1a[418]
  PIN t1a[419]
    DIRECTION INPUT ;
    USE SIGNAL ;
    PORT
      LAYER M5 ;
        RECT  10.992 25.836 11.016 25.92 ;
    END
  END t1a[419]
  PIN t1a[41]
    DIRECTION INPUT ;
    USE SIGNAL ;
    PORT
      LAYER M5 ;
        RECT  79.152 25.836 79.176 25.92 ;
    END
  END t1a[41]
  PIN t1a[420]
    DIRECTION INPUT ;
    USE SIGNAL ;
    PORT
      LAYER M5 ;
        RECT  11.088 25.836 11.112 25.92 ;
    END
  END t1a[420]
  PIN t1a[421]
    DIRECTION INPUT ;
    USE SIGNAL ;
    PORT
      LAYER M5 ;
        RECT  11.184 25.836 11.208 25.92 ;
    END
  END t1a[421]
  PIN t1a[422]
    DIRECTION INPUT ;
    USE SIGNAL ;
    PORT
      LAYER M5 ;
        RECT  11.28 25.836 11.304 25.92 ;
    END
  END t1a[422]
  PIN t1a[423]
    DIRECTION INPUT ;
    USE SIGNAL ;
    PORT
      LAYER M5 ;
        RECT  11.376 25.836 11.4 25.92 ;
    END
  END t1a[423]
  PIN t1a[424]
    DIRECTION INPUT ;
    USE SIGNAL ;
    PORT
      LAYER M5 ;
        RECT  11.472 25.836 11.496 25.92 ;
    END
  END t1a[424]
  PIN t1a[425]
    DIRECTION INPUT ;
    USE SIGNAL ;
    PORT
      LAYER M5 ;
        RECT  11.568 25.836 11.592 25.92 ;
    END
  END t1a[425]
  PIN t1a[426]
    DIRECTION INPUT ;
    USE SIGNAL ;
    PORT
      LAYER M5 ;
        RECT  11.664 25.836 11.688 25.92 ;
    END
  END t1a[426]
  PIN t1a[427]
    DIRECTION INPUT ;
    USE SIGNAL ;
    PORT
      LAYER M5 ;
        RECT  11.76 25.836 11.784 25.92 ;
    END
  END t1a[427]
  PIN t1a[428]
    DIRECTION INPUT ;
    USE SIGNAL ;
    PORT
      LAYER M5 ;
        RECT  11.856 25.836 11.88 25.92 ;
    END
  END t1a[428]
  PIN t1a[429]
    DIRECTION INPUT ;
    USE SIGNAL ;
    PORT
      LAYER M5 ;
        RECT  11.952 25.836 11.976 25.92 ;
    END
  END t1a[429]
  PIN t1a[42]
    DIRECTION INPUT ;
    USE SIGNAL ;
    PORT
      LAYER M5 ;
        RECT  79.248 25.836 79.272 25.92 ;
    END
  END t1a[42]
  PIN t1a[430]
    DIRECTION INPUT ;
    USE SIGNAL ;
    PORT
      LAYER M5 ;
        RECT  12.048 25.836 12.072 25.92 ;
    END
  END t1a[430]
  PIN t1a[431]
    DIRECTION INPUT ;
    USE SIGNAL ;
    PORT
      LAYER M5 ;
        RECT  12.144 25.836 12.168 25.92 ;
    END
  END t1a[431]
  PIN t1a[432]
    DIRECTION INPUT ;
    USE SIGNAL ;
    PORT
      LAYER M5 ;
        RECT  12.24 25.836 12.264 25.92 ;
    END
  END t1a[432]
  PIN t1a[433]
    DIRECTION INPUT ;
    USE SIGNAL ;
    PORT
      LAYER M5 ;
        RECT  12.336 25.836 12.36 25.92 ;
    END
  END t1a[433]
  PIN t1a[434]
    DIRECTION INPUT ;
    USE SIGNAL ;
    PORT
      LAYER M5 ;
        RECT  12.432 25.836 12.456 25.92 ;
    END
  END t1a[434]
  PIN t1a[435]
    DIRECTION INPUT ;
    USE SIGNAL ;
    PORT
      LAYER M5 ;
        RECT  12.528 25.836 12.552 25.92 ;
    END
  END t1a[435]
  PIN t1a[436]
    DIRECTION INPUT ;
    USE SIGNAL ;
    PORT
      LAYER M5 ;
        RECT  12.624 25.836 12.648 25.92 ;
    END
  END t1a[436]
  PIN t1a[437]
    DIRECTION INPUT ;
    USE SIGNAL ;
    PORT
      LAYER M5 ;
        RECT  12.72 25.836 12.744 25.92 ;
    END
  END t1a[437]
  PIN t1a[438]
    DIRECTION INPUT ;
    USE SIGNAL ;
    PORT
      LAYER M5 ;
        RECT  12.816 25.836 12.84 25.92 ;
    END
  END t1a[438]
  PIN t1a[439]
    DIRECTION INPUT ;
    USE SIGNAL ;
    PORT
      LAYER M5 ;
        RECT  12.912 25.836 12.936 25.92 ;
    END
  END t1a[439]
  PIN t1a[43]
    DIRECTION INPUT ;
    USE SIGNAL ;
    PORT
      LAYER M5 ;
        RECT  79.344 25.836 79.368 25.92 ;
    END
  END t1a[43]
  PIN t1a[440]
    DIRECTION INPUT ;
    USE SIGNAL ;
    PORT
      LAYER M5 ;
        RECT  13.008 25.836 13.032 25.92 ;
    END
  END t1a[440]
  PIN t1a[441]
    DIRECTION INPUT ;
    USE SIGNAL ;
    PORT
      LAYER M5 ;
        RECT  13.104 25.836 13.128 25.92 ;
    END
  END t1a[441]
  PIN t1a[442]
    DIRECTION INPUT ;
    USE SIGNAL ;
    PORT
      LAYER M5 ;
        RECT  13.2 25.836 13.224 25.92 ;
    END
  END t1a[442]
  PIN t1a[443]
    DIRECTION INPUT ;
    USE SIGNAL ;
    PORT
      LAYER M5 ;
        RECT  13.296 25.836 13.32 25.92 ;
    END
  END t1a[443]
  PIN t1a[444]
    DIRECTION INPUT ;
    USE SIGNAL ;
    PORT
      LAYER M5 ;
        RECT  13.392 25.836 13.416 25.92 ;
    END
  END t1a[444]
  PIN t1a[445]
    DIRECTION INPUT ;
    USE SIGNAL ;
    PORT
      LAYER M5 ;
        RECT  13.488 25.836 13.512 25.92 ;
    END
  END t1a[445]
  PIN t1a[446]
    DIRECTION INPUT ;
    USE SIGNAL ;
    PORT
      LAYER M5 ;
        RECT  13.584 25.836 13.608 25.92 ;
    END
  END t1a[446]
  PIN t1a[447]
    DIRECTION INPUT ;
    USE SIGNAL ;
    PORT
      LAYER M5 ;
        RECT  13.68 25.836 13.704 25.92 ;
    END
  END t1a[447]
  PIN t1a[448]
    DIRECTION INPUT ;
    USE SIGNAL ;
    PORT
      LAYER M5 ;
        RECT  106.704 25.836 106.728 25.92 ;
    END
  END t1a[448]
  PIN t1a[449]
    DIRECTION INPUT ;
    USE SIGNAL ;
    PORT
      LAYER M5 ;
        RECT  106.8 25.836 106.824 25.92 ;
    END
  END t1a[449]
  PIN t1a[44]
    DIRECTION INPUT ;
    USE SIGNAL ;
    PORT
      LAYER M5 ;
        RECT  79.44 25.836 79.464 25.92 ;
    END
  END t1a[44]
  PIN t1a[450]
    DIRECTION INPUT ;
    USE SIGNAL ;
    PORT
      LAYER M5 ;
        RECT  106.896 25.836 106.92 25.92 ;
    END
  END t1a[450]
  PIN t1a[451]
    DIRECTION INPUT ;
    USE SIGNAL ;
    PORT
      LAYER M5 ;
        RECT  106.992 25.836 107.016 25.92 ;
    END
  END t1a[451]
  PIN t1a[452]
    DIRECTION INPUT ;
    USE SIGNAL ;
    PORT
      LAYER M5 ;
        RECT  107.088 25.836 107.112 25.92 ;
    END
  END t1a[452]
  PIN t1a[453]
    DIRECTION INPUT ;
    USE SIGNAL ;
    PORT
      LAYER M5 ;
        RECT  107.184 25.836 107.208 25.92 ;
    END
  END t1a[453]
  PIN t1a[454]
    DIRECTION INPUT ;
    USE SIGNAL ;
    PORT
      LAYER M5 ;
        RECT  107.28 25.836 107.304 25.92 ;
    END
  END t1a[454]
  PIN t1a[455]
    DIRECTION INPUT ;
    USE SIGNAL ;
    PORT
      LAYER M5 ;
        RECT  107.376 25.836 107.4 25.92 ;
    END
  END t1a[455]
  PIN t1a[456]
    DIRECTION INPUT ;
    USE SIGNAL ;
    PORT
      LAYER M5 ;
        RECT  107.472 25.836 107.496 25.92 ;
    END
  END t1a[456]
  PIN t1a[457]
    DIRECTION INPUT ;
    USE SIGNAL ;
    PORT
      LAYER M5 ;
        RECT  107.568 25.836 107.592 25.92 ;
    END
  END t1a[457]
  PIN t1a[458]
    DIRECTION INPUT ;
    USE SIGNAL ;
    PORT
      LAYER M5 ;
        RECT  107.664 25.836 107.688 25.92 ;
    END
  END t1a[458]
  PIN t1a[459]
    DIRECTION INPUT ;
    USE SIGNAL ;
    PORT
      LAYER M5 ;
        RECT  107.76 25.836 107.784 25.92 ;
    END
  END t1a[459]
  PIN t1a[45]
    DIRECTION INPUT ;
    USE SIGNAL ;
    PORT
      LAYER M5 ;
        RECT  79.536 25.836 79.56 25.92 ;
    END
  END t1a[45]
  PIN t1a[460]
    DIRECTION INPUT ;
    USE SIGNAL ;
    PORT
      LAYER M5 ;
        RECT  107.856 25.836 107.88 25.92 ;
    END
  END t1a[460]
  PIN t1a[461]
    DIRECTION INPUT ;
    USE SIGNAL ;
    PORT
      LAYER M5 ;
        RECT  107.952 25.836 107.976 25.92 ;
    END
  END t1a[461]
  PIN t1a[462]
    DIRECTION INPUT ;
    USE SIGNAL ;
    PORT
      LAYER M5 ;
        RECT  108.048 25.836 108.072 25.92 ;
    END
  END t1a[462]
  PIN t1a[463]
    DIRECTION INPUT ;
    USE SIGNAL ;
    PORT
      LAYER M5 ;
        RECT  108.144 25.836 108.168 25.92 ;
    END
  END t1a[463]
  PIN t1a[464]
    DIRECTION INPUT ;
    USE SIGNAL ;
    PORT
      LAYER M5 ;
        RECT  108.24 25.836 108.264 25.92 ;
    END
  END t1a[464]
  PIN t1a[465]
    DIRECTION INPUT ;
    USE SIGNAL ;
    PORT
      LAYER M5 ;
        RECT  108.336 25.836 108.36 25.92 ;
    END
  END t1a[465]
  PIN t1a[466]
    DIRECTION INPUT ;
    USE SIGNAL ;
    PORT
      LAYER M5 ;
        RECT  108.432 25.836 108.456 25.92 ;
    END
  END t1a[466]
  PIN t1a[467]
    DIRECTION INPUT ;
    USE SIGNAL ;
    PORT
      LAYER M5 ;
        RECT  108.528 25.836 108.552 25.92 ;
    END
  END t1a[467]
  PIN t1a[468]
    DIRECTION INPUT ;
    USE SIGNAL ;
    PORT
      LAYER M5 ;
        RECT  108.624 25.836 108.648 25.92 ;
    END
  END t1a[468]
  PIN t1a[469]
    DIRECTION INPUT ;
    USE SIGNAL ;
    PORT
      LAYER M5 ;
        RECT  108.72 25.836 108.744 25.92 ;
    END
  END t1a[469]
  PIN t1a[46]
    DIRECTION INPUT ;
    USE SIGNAL ;
    PORT
      LAYER M5 ;
        RECT  79.632 25.836 79.656 25.92 ;
    END
  END t1a[46]
  PIN t1a[470]
    DIRECTION INPUT ;
    USE SIGNAL ;
    PORT
      LAYER M5 ;
        RECT  108.816 25.836 108.84 25.92 ;
    END
  END t1a[470]
  PIN t1a[471]
    DIRECTION INPUT ;
    USE SIGNAL ;
    PORT
      LAYER M5 ;
        RECT  108.912 25.836 108.936 25.92 ;
    END
  END t1a[471]
  PIN t1a[472]
    DIRECTION INPUT ;
    USE SIGNAL ;
    PORT
      LAYER M5 ;
        RECT  109.008 25.836 109.032 25.92 ;
    END
  END t1a[472]
  PIN t1a[473]
    DIRECTION INPUT ;
    USE SIGNAL ;
    PORT
      LAYER M5 ;
        RECT  109.104 25.836 109.128 25.92 ;
    END
  END t1a[473]
  PIN t1a[474]
    DIRECTION INPUT ;
    USE SIGNAL ;
    PORT
      LAYER M5 ;
        RECT  109.2 25.836 109.224 25.92 ;
    END
  END t1a[474]
  PIN t1a[475]
    DIRECTION INPUT ;
    USE SIGNAL ;
    PORT
      LAYER M5 ;
        RECT  109.296 25.836 109.32 25.92 ;
    END
  END t1a[475]
  PIN t1a[476]
    DIRECTION INPUT ;
    USE SIGNAL ;
    PORT
      LAYER M5 ;
        RECT  109.392 25.836 109.416 25.92 ;
    END
  END t1a[476]
  PIN t1a[477]
    DIRECTION INPUT ;
    USE SIGNAL ;
    PORT
      LAYER M5 ;
        RECT  109.488 25.836 109.512 25.92 ;
    END
  END t1a[477]
  PIN t1a[478]
    DIRECTION INPUT ;
    USE SIGNAL ;
    PORT
      LAYER M5 ;
        RECT  109.584 25.836 109.608 25.92 ;
    END
  END t1a[478]
  PIN t1a[479]
    DIRECTION INPUT ;
    USE SIGNAL ;
    PORT
      LAYER M5 ;
        RECT  109.68 25.836 109.704 25.92 ;
    END
  END t1a[479]
  PIN t1a[47]
    DIRECTION INPUT ;
    USE SIGNAL ;
    PORT
      LAYER M5 ;
        RECT  79.728 25.836 79.752 25.92 ;
    END
  END t1a[47]
  PIN t1a[480]
    DIRECTION INPUT ;
    USE SIGNAL ;
    PORT
      LAYER M5 ;
        RECT  109.776 25.836 109.8 25.92 ;
    END
  END t1a[480]
  PIN t1a[481]
    DIRECTION INPUT ;
    USE SIGNAL ;
    PORT
      LAYER M5 ;
        RECT  109.872 25.836 109.896 25.92 ;
    END
  END t1a[481]
  PIN t1a[482]
    DIRECTION INPUT ;
    USE SIGNAL ;
    PORT
      LAYER M5 ;
        RECT  109.968 25.836 109.992 25.92 ;
    END
  END t1a[482]
  PIN t1a[483]
    DIRECTION INPUT ;
    USE SIGNAL ;
    PORT
      LAYER M5 ;
        RECT  110.064 25.836 110.088 25.92 ;
    END
  END t1a[483]
  PIN t1a[484]
    DIRECTION INPUT ;
    USE SIGNAL ;
    PORT
      LAYER M5 ;
        RECT  110.16 25.836 110.184 25.92 ;
    END
  END t1a[484]
  PIN t1a[485]
    DIRECTION INPUT ;
    USE SIGNAL ;
    PORT
      LAYER M5 ;
        RECT  110.256 25.836 110.28 25.92 ;
    END
  END t1a[485]
  PIN t1a[486]
    DIRECTION INPUT ;
    USE SIGNAL ;
    PORT
      LAYER M5 ;
        RECT  110.352 25.836 110.376 25.92 ;
    END
  END t1a[486]
  PIN t1a[487]
    DIRECTION INPUT ;
    USE SIGNAL ;
    PORT
      LAYER M5 ;
        RECT  110.448 25.836 110.472 25.92 ;
    END
  END t1a[487]
  PIN t1a[488]
    DIRECTION INPUT ;
    USE SIGNAL ;
    PORT
      LAYER M5 ;
        RECT  110.544 25.836 110.568 25.92 ;
    END
  END t1a[488]
  PIN t1a[489]
    DIRECTION INPUT ;
    USE SIGNAL ;
    PORT
      LAYER M5 ;
        RECT  110.64 25.836 110.664 25.92 ;
    END
  END t1a[489]
  PIN t1a[48]
    DIRECTION INPUT ;
    USE SIGNAL ;
    PORT
      LAYER M5 ;
        RECT  79.824 25.836 79.848 25.92 ;
    END
  END t1a[48]
  PIN t1a[490]
    DIRECTION INPUT ;
    USE SIGNAL ;
    PORT
      LAYER M5 ;
        RECT  110.736 25.836 110.76 25.92 ;
    END
  END t1a[490]
  PIN t1a[491]
    DIRECTION INPUT ;
    USE SIGNAL ;
    PORT
      LAYER M5 ;
        RECT  110.832 25.836 110.856 25.92 ;
    END
  END t1a[491]
  PIN t1a[492]
    DIRECTION INPUT ;
    USE SIGNAL ;
    PORT
      LAYER M5 ;
        RECT  110.928 25.836 110.952 25.92 ;
    END
  END t1a[492]
  PIN t1a[493]
    DIRECTION INPUT ;
    USE SIGNAL ;
    PORT
      LAYER M5 ;
        RECT  111.024 25.836 111.048 25.92 ;
    END
  END t1a[493]
  PIN t1a[494]
    DIRECTION INPUT ;
    USE SIGNAL ;
    PORT
      LAYER M5 ;
        RECT  111.12 25.836 111.144 25.92 ;
    END
  END t1a[494]
  PIN t1a[495]
    DIRECTION INPUT ;
    USE SIGNAL ;
    PORT
      LAYER M5 ;
        RECT  111.216 25.836 111.24 25.92 ;
    END
  END t1a[495]
  PIN t1a[496]
    DIRECTION INPUT ;
    USE SIGNAL ;
    PORT
      LAYER M5 ;
        RECT  111.312 25.836 111.336 25.92 ;
    END
  END t1a[496]
  PIN t1a[497]
    DIRECTION INPUT ;
    USE SIGNAL ;
    PORT
      LAYER M5 ;
        RECT  111.408 25.836 111.432 25.92 ;
    END
  END t1a[497]
  PIN t1a[498]
    DIRECTION INPUT ;
    USE SIGNAL ;
    PORT
      LAYER M5 ;
        RECT  111.504 25.836 111.528 25.92 ;
    END
  END t1a[498]
  PIN t1a[499]
    DIRECTION INPUT ;
    USE SIGNAL ;
    PORT
      LAYER M5 ;
        RECT  111.6 25.836 111.624 25.92 ;
    END
  END t1a[499]
  PIN t1a[49]
    DIRECTION INPUT ;
    USE SIGNAL ;
    PORT
      LAYER M5 ;
        RECT  79.92 25.836 79.944 25.92 ;
    END
  END t1a[49]
  PIN t1a[4]
    DIRECTION INPUT ;
    USE SIGNAL ;
    PORT
      LAYER M5 ;
        RECT  33.36 25.836 33.384 25.92 ;
    END
  END t1a[4]
  PIN t1a[500]
    DIRECTION INPUT ;
    USE SIGNAL ;
    PORT
      LAYER M5 ;
        RECT  111.696 25.836 111.72 25.92 ;
    END
  END t1a[500]
  PIN t1a[501]
    DIRECTION INPUT ;
    USE SIGNAL ;
    PORT
      LAYER M5 ;
        RECT  111.792 25.836 111.816 25.92 ;
    END
  END t1a[501]
  PIN t1a[502]
    DIRECTION INPUT ;
    USE SIGNAL ;
    PORT
      LAYER M5 ;
        RECT  111.888 25.836 111.912 25.92 ;
    END
  END t1a[502]
  PIN t1a[503]
    DIRECTION INPUT ;
    USE SIGNAL ;
    PORT
      LAYER M5 ;
        RECT  111.984 25.836 112.008 25.92 ;
    END
  END t1a[503]
  PIN t1a[504]
    DIRECTION INPUT ;
    USE SIGNAL ;
    PORT
      LAYER M5 ;
        RECT  112.08 25.836 112.104 25.92 ;
    END
  END t1a[504]
  PIN t1a[505]
    DIRECTION INPUT ;
    USE SIGNAL ;
    PORT
      LAYER M5 ;
        RECT  112.176 25.836 112.2 25.92 ;
    END
  END t1a[505]
  PIN t1a[506]
    DIRECTION INPUT ;
    USE SIGNAL ;
    PORT
      LAYER M5 ;
        RECT  112.272 25.836 112.296 25.92 ;
    END
  END t1a[506]
  PIN t1a[507]
    DIRECTION INPUT ;
    USE SIGNAL ;
    PORT
      LAYER M5 ;
        RECT  112.368 25.836 112.392 25.92 ;
    END
  END t1a[507]
  PIN t1a[508]
    DIRECTION INPUT ;
    USE SIGNAL ;
    PORT
      LAYER M5 ;
        RECT  112.464 25.836 112.488 25.92 ;
    END
  END t1a[508]
  PIN t1a[509]
    DIRECTION INPUT ;
    USE SIGNAL ;
    PORT
      LAYER M5 ;
        RECT  112.56 25.836 112.584 25.92 ;
    END
  END t1a[509]
  PIN t1a[50]
    DIRECTION INPUT ;
    USE SIGNAL ;
    PORT
      LAYER M5 ;
        RECT  80.016 25.836 80.04 25.92 ;
    END
  END t1a[50]
  PIN t1a[510]
    DIRECTION INPUT ;
    USE SIGNAL ;
    PORT
      LAYER M5 ;
        RECT  112.656 25.836 112.68 25.92 ;
    END
  END t1a[510]
  PIN t1a[511]
    DIRECTION INPUT ;
    USE SIGNAL ;
    PORT
      LAYER M5 ;
        RECT  112.752 25.836 112.776 25.92 ;
    END
  END t1a[511]
  PIN t1a[51]
    DIRECTION INPUT ;
    USE SIGNAL ;
    PORT
      LAYER M5 ;
        RECT  80.112 25.836 80.136 25.92 ;
    END
  END t1a[51]
  PIN t1a[52]
    DIRECTION INPUT ;
    USE SIGNAL ;
    PORT
      LAYER M5 ;
        RECT  80.208 25.836 80.232 25.92 ;
    END
  END t1a[52]
  PIN t1a[53]
    DIRECTION INPUT ;
    USE SIGNAL ;
    PORT
      LAYER M5 ;
        RECT  80.304 25.836 80.328 25.92 ;
    END
  END t1a[53]
  PIN t1a[54]
    DIRECTION INPUT ;
    USE SIGNAL ;
    PORT
      LAYER M5 ;
        RECT  80.4 25.836 80.424 25.92 ;
    END
  END t1a[54]
  PIN t1a[55]
    DIRECTION INPUT ;
    USE SIGNAL ;
    PORT
      LAYER M5 ;
        RECT  80.496 25.836 80.52 25.92 ;
    END
  END t1a[55]
  PIN t1a[56]
    DIRECTION INPUT ;
    USE SIGNAL ;
    PORT
      LAYER M5 ;
        RECT  80.592 25.836 80.616 25.92 ;
    END
  END t1a[56]
  PIN t1a[57]
    DIRECTION INPUT ;
    USE SIGNAL ;
    PORT
      LAYER M5 ;
        RECT  80.688 25.836 80.712 25.92 ;
    END
  END t1a[57]
  PIN t1a[58]
    DIRECTION INPUT ;
    USE SIGNAL ;
    PORT
      LAYER M5 ;
        RECT  80.784 25.836 80.808 25.92 ;
    END
  END t1a[58]
  PIN t1a[59]
    DIRECTION INPUT ;
    USE SIGNAL ;
    PORT
      LAYER M5 ;
        RECT  80.88 25.836 80.904 25.92 ;
    END
  END t1a[59]
  PIN t1a[5]
    DIRECTION INPUT ;
    USE SIGNAL ;
    PORT
      LAYER M5 ;
        RECT  33.456 25.836 33.48 25.92 ;
    END
  END t1a[5]
  PIN t1a[60]
    DIRECTION INPUT ;
    USE SIGNAL ;
    PORT
      LAYER M5 ;
        RECT  80.976 25.836 81 25.92 ;
    END
  END t1a[60]
  PIN t1a[61]
    DIRECTION INPUT ;
    USE SIGNAL ;
    PORT
      LAYER M5 ;
        RECT  81.072 25.836 81.096 25.92 ;
    END
  END t1a[61]
  PIN t1a[62]
    DIRECTION INPUT ;
    USE SIGNAL ;
    PORT
      LAYER M5 ;
        RECT  81.168 25.836 81.192 25.92 ;
    END
  END t1a[62]
  PIN t1a[63]
    DIRECTION INPUT ;
    USE SIGNAL ;
    PORT
      LAYER M5 ;
        RECT  81.264 25.836 81.288 25.92 ;
    END
  END t1a[63]
  PIN t1a[64]
    DIRECTION INPUT ;
    USE SIGNAL ;
    PORT
      LAYER M5 ;
        RECT  23.76 25.836 23.784 25.92 ;
    END
  END t1a[64]
  PIN t1a[65]
    DIRECTION INPUT ;
    USE SIGNAL ;
    PORT
      LAYER M5 ;
        RECT  23.856 25.836 23.88 25.92 ;
    END
  END t1a[65]
  PIN t1a[66]
    DIRECTION INPUT ;
    USE SIGNAL ;
    PORT
      LAYER M5 ;
        RECT  23.952 25.836 23.976 25.92 ;
    END
  END t1a[66]
  PIN t1a[67]
    DIRECTION INPUT ;
    USE SIGNAL ;
    PORT
      LAYER M5 ;
        RECT  24.048 25.836 24.072 25.92 ;
    END
  END t1a[67]
  PIN t1a[68]
    DIRECTION INPUT ;
    USE SIGNAL ;
    PORT
      LAYER M5 ;
        RECT  24.144 25.836 24.168 25.92 ;
    END
  END t1a[68]
  PIN t1a[69]
    DIRECTION INPUT ;
    USE SIGNAL ;
    PORT
      LAYER M5 ;
        RECT  24.24 25.836 24.264 25.92 ;
    END
  END t1a[69]
  PIN t1a[6]
    DIRECTION INPUT ;
    USE SIGNAL ;
    PORT
      LAYER M5 ;
        RECT  33.552 25.836 33.576 25.92 ;
    END
  END t1a[6]
  PIN t1a[70]
    DIRECTION INPUT ;
    USE SIGNAL ;
    PORT
      LAYER M5 ;
        RECT  24.336 25.836 24.36 25.92 ;
    END
  END t1a[70]
  PIN t1a[71]
    DIRECTION INPUT ;
    USE SIGNAL ;
    PORT
      LAYER M5 ;
        RECT  24.432 25.836 24.456 25.92 ;
    END
  END t1a[71]
  PIN t1a[72]
    DIRECTION INPUT ;
    USE SIGNAL ;
    PORT
      LAYER M5 ;
        RECT  24.528 25.836 24.552 25.92 ;
    END
  END t1a[72]
  PIN t1a[73]
    DIRECTION INPUT ;
    USE SIGNAL ;
    PORT
      LAYER M5 ;
        RECT  24.624 25.836 24.648 25.92 ;
    END
  END t1a[73]
  PIN t1a[74]
    DIRECTION INPUT ;
    USE SIGNAL ;
    PORT
      LAYER M5 ;
        RECT  24.72 25.836 24.744 25.92 ;
    END
  END t1a[74]
  PIN t1a[75]
    DIRECTION INPUT ;
    USE SIGNAL ;
    PORT
      LAYER M5 ;
        RECT  24.816 25.836 24.84 25.92 ;
    END
  END t1a[75]
  PIN t1a[76]
    DIRECTION INPUT ;
    USE SIGNAL ;
    PORT
      LAYER M5 ;
        RECT  24.912 25.836 24.936 25.92 ;
    END
  END t1a[76]
  PIN t1a[77]
    DIRECTION INPUT ;
    USE SIGNAL ;
    PORT
      LAYER M5 ;
        RECT  25.008 25.836 25.032 25.92 ;
    END
  END t1a[77]
  PIN t1a[78]
    DIRECTION INPUT ;
    USE SIGNAL ;
    PORT
      LAYER M5 ;
        RECT  25.104 25.836 25.128 25.92 ;
    END
  END t1a[78]
  PIN t1a[79]
    DIRECTION INPUT ;
    USE SIGNAL ;
    PORT
      LAYER M5 ;
        RECT  25.2 25.836 25.224 25.92 ;
    END
  END t1a[79]
  PIN t1a[7]
    DIRECTION INPUT ;
    USE SIGNAL ;
    PORT
      LAYER M5 ;
        RECT  33.648 25.836 33.672 25.92 ;
    END
  END t1a[7]
  PIN t1a[80]
    DIRECTION INPUT ;
    USE SIGNAL ;
    PORT
      LAYER M5 ;
        RECT  25.296 25.836 25.32 25.92 ;
    END
  END t1a[80]
  PIN t1a[81]
    DIRECTION INPUT ;
    USE SIGNAL ;
    PORT
      LAYER M5 ;
        RECT  25.392 25.836 25.416 25.92 ;
    END
  END t1a[81]
  PIN t1a[82]
    DIRECTION INPUT ;
    USE SIGNAL ;
    PORT
      LAYER M5 ;
        RECT  25.488 25.836 25.512 25.92 ;
    END
  END t1a[82]
  PIN t1a[83]
    DIRECTION INPUT ;
    USE SIGNAL ;
    PORT
      LAYER M5 ;
        RECT  25.584 25.836 25.608 25.92 ;
    END
  END t1a[83]
  PIN t1a[84]
    DIRECTION INPUT ;
    USE SIGNAL ;
    PORT
      LAYER M5 ;
        RECT  25.68 25.836 25.704 25.92 ;
    END
  END t1a[84]
  PIN t1a[85]
    DIRECTION INPUT ;
    USE SIGNAL ;
    PORT
      LAYER M5 ;
        RECT  25.776 25.836 25.8 25.92 ;
    END
  END t1a[85]
  PIN t1a[86]
    DIRECTION INPUT ;
    USE SIGNAL ;
    PORT
      LAYER M5 ;
        RECT  25.872 25.836 25.896 25.92 ;
    END
  END t1a[86]
  PIN t1a[87]
    DIRECTION INPUT ;
    USE SIGNAL ;
    PORT
      LAYER M5 ;
        RECT  25.968 25.836 25.992 25.92 ;
    END
  END t1a[87]
  PIN t1a[88]
    DIRECTION INPUT ;
    USE SIGNAL ;
    PORT
      LAYER M5 ;
        RECT  26.064 25.836 26.088 25.92 ;
    END
  END t1a[88]
  PIN t1a[89]
    DIRECTION INPUT ;
    USE SIGNAL ;
    PORT
      LAYER M5 ;
        RECT  26.16 25.836 26.184 25.92 ;
    END
  END t1a[89]
  PIN t1a[8]
    DIRECTION INPUT ;
    USE SIGNAL ;
    PORT
      LAYER M5 ;
        RECT  33.744 25.836 33.768 25.92 ;
    END
  END t1a[8]
  PIN t1a[90]
    DIRECTION INPUT ;
    USE SIGNAL ;
    PORT
      LAYER M5 ;
        RECT  26.256 25.836 26.28 25.92 ;
    END
  END t1a[90]
  PIN t1a[91]
    DIRECTION INPUT ;
    USE SIGNAL ;
    PORT
      LAYER M5 ;
        RECT  26.352 25.836 26.376 25.92 ;
    END
  END t1a[91]
  PIN t1a[92]
    DIRECTION INPUT ;
    USE SIGNAL ;
    PORT
      LAYER M5 ;
        RECT  26.448 25.836 26.472 25.92 ;
    END
  END t1a[92]
  PIN t1a[93]
    DIRECTION INPUT ;
    USE SIGNAL ;
    PORT
      LAYER M5 ;
        RECT  26.544 25.836 26.568 25.92 ;
    END
  END t1a[93]
  PIN t1a[94]
    DIRECTION INPUT ;
    USE SIGNAL ;
    PORT
      LAYER M5 ;
        RECT  26.64 25.836 26.664 25.92 ;
    END
  END t1a[94]
  PIN t1a[95]
    DIRECTION INPUT ;
    USE SIGNAL ;
    PORT
      LAYER M5 ;
        RECT  26.736 25.836 26.76 25.92 ;
    END
  END t1a[95]
  PIN t1a[96]
    DIRECTION INPUT ;
    USE SIGNAL ;
    PORT
      LAYER M5 ;
        RECT  20.688 25.836 20.712 25.92 ;
    END
  END t1a[96]
  PIN t1a[97]
    DIRECTION INPUT ;
    USE SIGNAL ;
    PORT
      LAYER M5 ;
        RECT  20.784 25.836 20.808 25.92 ;
    END
  END t1a[97]
  PIN t1a[98]
    DIRECTION INPUT ;
    USE SIGNAL ;
    PORT
      LAYER M5 ;
        RECT  20.88 25.836 20.904 25.92 ;
    END
  END t1a[98]
  PIN t1a[99]
    DIRECTION INPUT ;
    USE SIGNAL ;
    PORT
      LAYER M5 ;
        RECT  20.976 25.836 21 25.92 ;
    END
  END t1a[99]
  PIN t1a[9]
    DIRECTION INPUT ;
    USE SIGNAL ;
    PORT
      LAYER M5 ;
        RECT  33.84 25.836 33.864 25.92 ;
    END
  END t1a[9]
  PIN t1b[0]
    DIRECTION INPUT ;
    USE SIGNAL ;
    PORT
      LAYER M5 ;
        RECT  48.336 0 48.36 0.084 ;
    END
  END t1b[0]
  PIN t1b[100]
    DIRECTION INPUT ;
    USE SIGNAL ;
    PORT
      LAYER M5 ;
        RECT  42.576 0 42.6 0.084 ;
    END
  END t1b[100]
  PIN t1b[101]
    DIRECTION INPUT ;
    USE SIGNAL ;
    PORT
      LAYER M5 ;
        RECT  42.672 0 42.696 0.084 ;
    END
  END t1b[101]
  PIN t1b[102]
    DIRECTION INPUT ;
    USE SIGNAL ;
    PORT
      LAYER M5 ;
        RECT  42.768 0 42.792 0.084 ;
    END
  END t1b[102]
  PIN t1b[103]
    DIRECTION INPUT ;
    USE SIGNAL ;
    PORT
      LAYER M5 ;
        RECT  42.864 0 42.888 0.084 ;
    END
  END t1b[103]
  PIN t1b[104]
    DIRECTION INPUT ;
    USE SIGNAL ;
    PORT
      LAYER M5 ;
        RECT  42.96 0 42.984 0.084 ;
    END
  END t1b[104]
  PIN t1b[105]
    DIRECTION INPUT ;
    USE SIGNAL ;
    PORT
      LAYER M5 ;
        RECT  43.056 0 43.08 0.084 ;
    END
  END t1b[105]
  PIN t1b[106]
    DIRECTION INPUT ;
    USE SIGNAL ;
    PORT
      LAYER M5 ;
        RECT  43.152 0 43.176 0.084 ;
    END
  END t1b[106]
  PIN t1b[107]
    DIRECTION INPUT ;
    USE SIGNAL ;
    PORT
      LAYER M5 ;
        RECT  43.248 0 43.272 0.084 ;
    END
  END t1b[107]
  PIN t1b[108]
    DIRECTION INPUT ;
    USE SIGNAL ;
    PORT
      LAYER M5 ;
        RECT  43.344 0 43.368 0.084 ;
    END
  END t1b[108]
  PIN t1b[109]
    DIRECTION INPUT ;
    USE SIGNAL ;
    PORT
      LAYER M5 ;
        RECT  43.44 0 43.464 0.084 ;
    END
  END t1b[109]
  PIN t1b[10]
    DIRECTION INPUT ;
    USE SIGNAL ;
    PORT
      LAYER M5 ;
        RECT  49.296 0 49.32 0.084 ;
    END
  END t1b[10]
  PIN t1b[110]
    DIRECTION INPUT ;
    USE SIGNAL ;
    PORT
      LAYER M5 ;
        RECT  43.536 0 43.56 0.084 ;
    END
  END t1b[110]
  PIN t1b[111]
    DIRECTION INPUT ;
    USE SIGNAL ;
    PORT
      LAYER M5 ;
        RECT  43.632 0 43.656 0.084 ;
    END
  END t1b[111]
  PIN t1b[112]
    DIRECTION INPUT ;
    USE SIGNAL ;
    PORT
      LAYER M5 ;
        RECT  43.728 0 43.752 0.084 ;
    END
  END t1b[112]
  PIN t1b[113]
    DIRECTION INPUT ;
    USE SIGNAL ;
    PORT
      LAYER M5 ;
        RECT  43.824 0 43.848 0.084 ;
    END
  END t1b[113]
  PIN t1b[114]
    DIRECTION INPUT ;
    USE SIGNAL ;
    PORT
      LAYER M5 ;
        RECT  43.92 0 43.944 0.084 ;
    END
  END t1b[114]
  PIN t1b[115]
    DIRECTION INPUT ;
    USE SIGNAL ;
    PORT
      LAYER M5 ;
        RECT  44.016 0 44.04 0.084 ;
    END
  END t1b[115]
  PIN t1b[116]
    DIRECTION INPUT ;
    USE SIGNAL ;
    PORT
      LAYER M5 ;
        RECT  44.112 0 44.136 0.084 ;
    END
  END t1b[116]
  PIN t1b[117]
    DIRECTION INPUT ;
    USE SIGNAL ;
    PORT
      LAYER M5 ;
        RECT  44.208 0 44.232 0.084 ;
    END
  END t1b[117]
  PIN t1b[118]
    DIRECTION INPUT ;
    USE SIGNAL ;
    PORT
      LAYER M5 ;
        RECT  44.304 0 44.328 0.084 ;
    END
  END t1b[118]
  PIN t1b[119]
    DIRECTION INPUT ;
    USE SIGNAL ;
    PORT
      LAYER M5 ;
        RECT  44.4 0 44.424 0.084 ;
    END
  END t1b[119]
  PIN t1b[11]
    DIRECTION INPUT ;
    USE SIGNAL ;
    PORT
      LAYER M5 ;
        RECT  49.392 0 49.416 0.084 ;
    END
  END t1b[11]
  PIN t1b[120]
    DIRECTION INPUT ;
    USE SIGNAL ;
    PORT
      LAYER M5 ;
        RECT  44.496 0 44.52 0.084 ;
    END
  END t1b[120]
  PIN t1b[121]
    DIRECTION INPUT ;
    USE SIGNAL ;
    PORT
      LAYER M5 ;
        RECT  44.592 0 44.616 0.084 ;
    END
  END t1b[121]
  PIN t1b[122]
    DIRECTION INPUT ;
    USE SIGNAL ;
    PORT
      LAYER M5 ;
        RECT  44.688 0 44.712 0.084 ;
    END
  END t1b[122]
  PIN t1b[123]
    DIRECTION INPUT ;
    USE SIGNAL ;
    PORT
      LAYER M5 ;
        RECT  44.784 0 44.808 0.084 ;
    END
  END t1b[123]
  PIN t1b[124]
    DIRECTION INPUT ;
    USE SIGNAL ;
    PORT
      LAYER M5 ;
        RECT  44.88 0 44.904 0.084 ;
    END
  END t1b[124]
  PIN t1b[125]
    DIRECTION INPUT ;
    USE SIGNAL ;
    PORT
      LAYER M5 ;
        RECT  44.976 0 45 0.084 ;
    END
  END t1b[125]
  PIN t1b[126]
    DIRECTION INPUT ;
    USE SIGNAL ;
    PORT
      LAYER M5 ;
        RECT  45.072 0 45.096 0.084 ;
    END
  END t1b[126]
  PIN t1b[127]
    DIRECTION INPUT ;
    USE SIGNAL ;
    PORT
      LAYER M5 ;
        RECT  45.168 0 45.192 0.084 ;
    END
  END t1b[127]
  PIN t1b[128]
    DIRECTION INPUT ;
    USE SIGNAL ;
    PORT
      LAYER M5 ;
        RECT  39.12 0 39.144 0.084 ;
    END
  END t1b[128]
  PIN t1b[129]
    DIRECTION INPUT ;
    USE SIGNAL ;
    PORT
      LAYER M5 ;
        RECT  39.216 0 39.24 0.084 ;
    END
  END t1b[129]
  PIN t1b[12]
    DIRECTION INPUT ;
    USE SIGNAL ;
    PORT
      LAYER M5 ;
        RECT  49.488 0 49.512 0.084 ;
    END
  END t1b[12]
  PIN t1b[130]
    DIRECTION INPUT ;
    USE SIGNAL ;
    PORT
      LAYER M5 ;
        RECT  39.312 0 39.336 0.084 ;
    END
  END t1b[130]
  PIN t1b[131]
    DIRECTION INPUT ;
    USE SIGNAL ;
    PORT
      LAYER M5 ;
        RECT  39.408 0 39.432 0.084 ;
    END
  END t1b[131]
  PIN t1b[132]
    DIRECTION INPUT ;
    USE SIGNAL ;
    PORT
      LAYER M5 ;
        RECT  39.504 0 39.528 0.084 ;
    END
  END t1b[132]
  PIN t1b[133]
    DIRECTION INPUT ;
    USE SIGNAL ;
    PORT
      LAYER M5 ;
        RECT  39.6 0 39.624 0.084 ;
    END
  END t1b[133]
  PIN t1b[134]
    DIRECTION INPUT ;
    USE SIGNAL ;
    PORT
      LAYER M5 ;
        RECT  39.696 0 39.72 0.084 ;
    END
  END t1b[134]
  PIN t1b[135]
    DIRECTION INPUT ;
    USE SIGNAL ;
    PORT
      LAYER M5 ;
        RECT  39.792 0 39.816 0.084 ;
    END
  END t1b[135]
  PIN t1b[136]
    DIRECTION INPUT ;
    USE SIGNAL ;
    PORT
      LAYER M5 ;
        RECT  39.888 0 39.912 0.084 ;
    END
  END t1b[136]
  PIN t1b[137]
    DIRECTION INPUT ;
    USE SIGNAL ;
    PORT
      LAYER M5 ;
        RECT  39.984 0 40.008 0.084 ;
    END
  END t1b[137]
  PIN t1b[138]
    DIRECTION INPUT ;
    USE SIGNAL ;
    PORT
      LAYER M5 ;
        RECT  40.08 0 40.104 0.084 ;
    END
  END t1b[138]
  PIN t1b[139]
    DIRECTION INPUT ;
    USE SIGNAL ;
    PORT
      LAYER M5 ;
        RECT  40.176 0 40.2 0.084 ;
    END
  END t1b[139]
  PIN t1b[13]
    DIRECTION INPUT ;
    USE SIGNAL ;
    PORT
      LAYER M5 ;
        RECT  49.584 0 49.608 0.084 ;
    END
  END t1b[13]
  PIN t1b[140]
    DIRECTION INPUT ;
    USE SIGNAL ;
    PORT
      LAYER M5 ;
        RECT  40.272 0 40.296 0.084 ;
    END
  END t1b[140]
  PIN t1b[141]
    DIRECTION INPUT ;
    USE SIGNAL ;
    PORT
      LAYER M5 ;
        RECT  40.368 0 40.392 0.084 ;
    END
  END t1b[141]
  PIN t1b[142]
    DIRECTION INPUT ;
    USE SIGNAL ;
    PORT
      LAYER M5 ;
        RECT  40.464 0 40.488 0.084 ;
    END
  END t1b[142]
  PIN t1b[143]
    DIRECTION INPUT ;
    USE SIGNAL ;
    PORT
      LAYER M5 ;
        RECT  40.56 0 40.584 0.084 ;
    END
  END t1b[143]
  PIN t1b[144]
    DIRECTION INPUT ;
    USE SIGNAL ;
    PORT
      LAYER M5 ;
        RECT  40.656 0 40.68 0.084 ;
    END
  END t1b[144]
  PIN t1b[145]
    DIRECTION INPUT ;
    USE SIGNAL ;
    PORT
      LAYER M5 ;
        RECT  40.752 0 40.776 0.084 ;
    END
  END t1b[145]
  PIN t1b[146]
    DIRECTION INPUT ;
    USE SIGNAL ;
    PORT
      LAYER M5 ;
        RECT  40.848 0 40.872 0.084 ;
    END
  END t1b[146]
  PIN t1b[147]
    DIRECTION INPUT ;
    USE SIGNAL ;
    PORT
      LAYER M5 ;
        RECT  40.944 0 40.968 0.084 ;
    END
  END t1b[147]
  PIN t1b[148]
    DIRECTION INPUT ;
    USE SIGNAL ;
    PORT
      LAYER M5 ;
        RECT  41.04 0 41.064 0.084 ;
    END
  END t1b[148]
  PIN t1b[149]
    DIRECTION INPUT ;
    USE SIGNAL ;
    PORT
      LAYER M5 ;
        RECT  41.136 0 41.16 0.084 ;
    END
  END t1b[149]
  PIN t1b[14]
    DIRECTION INPUT ;
    USE SIGNAL ;
    PORT
      LAYER M5 ;
        RECT  49.68 0 49.704 0.084 ;
    END
  END t1b[14]
  PIN t1b[150]
    DIRECTION INPUT ;
    USE SIGNAL ;
    PORT
      LAYER M5 ;
        RECT  41.232 0 41.256 0.084 ;
    END
  END t1b[150]
  PIN t1b[151]
    DIRECTION INPUT ;
    USE SIGNAL ;
    PORT
      LAYER M5 ;
        RECT  41.328 0 41.352 0.084 ;
    END
  END t1b[151]
  PIN t1b[152]
    DIRECTION INPUT ;
    USE SIGNAL ;
    PORT
      LAYER M5 ;
        RECT  41.424 0 41.448 0.084 ;
    END
  END t1b[152]
  PIN t1b[153]
    DIRECTION INPUT ;
    USE SIGNAL ;
    PORT
      LAYER M5 ;
        RECT  41.52 0 41.544 0.084 ;
    END
  END t1b[153]
  PIN t1b[154]
    DIRECTION INPUT ;
    USE SIGNAL ;
    PORT
      LAYER M5 ;
        RECT  41.616 0 41.64 0.084 ;
    END
  END t1b[154]
  PIN t1b[155]
    DIRECTION INPUT ;
    USE SIGNAL ;
    PORT
      LAYER M5 ;
        RECT  41.712 0 41.736 0.084 ;
    END
  END t1b[155]
  PIN t1b[156]
    DIRECTION INPUT ;
    USE SIGNAL ;
    PORT
      LAYER M5 ;
        RECT  41.808 0 41.832 0.084 ;
    END
  END t1b[156]
  PIN t1b[157]
    DIRECTION INPUT ;
    USE SIGNAL ;
    PORT
      LAYER M5 ;
        RECT  41.904 0 41.928 0.084 ;
    END
  END t1b[157]
  PIN t1b[158]
    DIRECTION INPUT ;
    USE SIGNAL ;
    PORT
      LAYER M5 ;
        RECT  42 0 42.024 0.084 ;
    END
  END t1b[158]
  PIN t1b[159]
    DIRECTION INPUT ;
    USE SIGNAL ;
    PORT
      LAYER M5 ;
        RECT  42.096 0 42.12 0.084 ;
    END
  END t1b[159]
  PIN t1b[15]
    DIRECTION INPUT ;
    USE SIGNAL ;
    PORT
      LAYER M5 ;
        RECT  49.776 0 49.8 0.084 ;
    END
  END t1b[15]
  PIN t1b[160]
    DIRECTION INPUT ;
    USE SIGNAL ;
    PORT
      LAYER M5 ;
        RECT  73.68 0 73.704 0.084 ;
    END
  END t1b[160]
  PIN t1b[161]
    DIRECTION INPUT ;
    USE SIGNAL ;
    PORT
      LAYER M5 ;
        RECT  73.776 0 73.8 0.084 ;
    END
  END t1b[161]
  PIN t1b[162]
    DIRECTION INPUT ;
    USE SIGNAL ;
    PORT
      LAYER M5 ;
        RECT  73.872 0 73.896 0.084 ;
    END
  END t1b[162]
  PIN t1b[163]
    DIRECTION INPUT ;
    USE SIGNAL ;
    PORT
      LAYER M5 ;
        RECT  73.968 0 73.992 0.084 ;
    END
  END t1b[163]
  PIN t1b[164]
    DIRECTION INPUT ;
    USE SIGNAL ;
    PORT
      LAYER M5 ;
        RECT  74.064 0 74.088 0.084 ;
    END
  END t1b[164]
  PIN t1b[165]
    DIRECTION INPUT ;
    USE SIGNAL ;
    PORT
      LAYER M5 ;
        RECT  74.16 0 74.184 0.084 ;
    END
  END t1b[165]
  PIN t1b[166]
    DIRECTION INPUT ;
    USE SIGNAL ;
    PORT
      LAYER M5 ;
        RECT  74.256 0 74.28 0.084 ;
    END
  END t1b[166]
  PIN t1b[167]
    DIRECTION INPUT ;
    USE SIGNAL ;
    PORT
      LAYER M5 ;
        RECT  74.352 0 74.376 0.084 ;
    END
  END t1b[167]
  PIN t1b[168]
    DIRECTION INPUT ;
    USE SIGNAL ;
    PORT
      LAYER M5 ;
        RECT  74.448 0 74.472 0.084 ;
    END
  END t1b[168]
  PIN t1b[169]
    DIRECTION INPUT ;
    USE SIGNAL ;
    PORT
      LAYER M5 ;
        RECT  74.544 0 74.568 0.084 ;
    END
  END t1b[169]
  PIN t1b[16]
    DIRECTION INPUT ;
    USE SIGNAL ;
    PORT
      LAYER M5 ;
        RECT  49.872 0 49.896 0.084 ;
    END
  END t1b[16]
  PIN t1b[170]
    DIRECTION INPUT ;
    USE SIGNAL ;
    PORT
      LAYER M5 ;
        RECT  74.64 0 74.664 0.084 ;
    END
  END t1b[170]
  PIN t1b[171]
    DIRECTION INPUT ;
    USE SIGNAL ;
    PORT
      LAYER M5 ;
        RECT  74.736 0 74.76 0.084 ;
    END
  END t1b[171]
  PIN t1b[172]
    DIRECTION INPUT ;
    USE SIGNAL ;
    PORT
      LAYER M5 ;
        RECT  74.832 0 74.856 0.084 ;
    END
  END t1b[172]
  PIN t1b[173]
    DIRECTION INPUT ;
    USE SIGNAL ;
    PORT
      LAYER M5 ;
        RECT  74.928 0 74.952 0.084 ;
    END
  END t1b[173]
  PIN t1b[174]
    DIRECTION INPUT ;
    USE SIGNAL ;
    PORT
      LAYER M5 ;
        RECT  75.024 0 75.048 0.084 ;
    END
  END t1b[174]
  PIN t1b[175]
    DIRECTION INPUT ;
    USE SIGNAL ;
    PORT
      LAYER M5 ;
        RECT  75.12 0 75.144 0.084 ;
    END
  END t1b[175]
  PIN t1b[176]
    DIRECTION INPUT ;
    USE SIGNAL ;
    PORT
      LAYER M5 ;
        RECT  75.216 0 75.24 0.084 ;
    END
  END t1b[176]
  PIN t1b[177]
    DIRECTION INPUT ;
    USE SIGNAL ;
    PORT
      LAYER M5 ;
        RECT  75.312 0 75.336 0.084 ;
    END
  END t1b[177]
  PIN t1b[178]
    DIRECTION INPUT ;
    USE SIGNAL ;
    PORT
      LAYER M5 ;
        RECT  75.408 0 75.432 0.084 ;
    END
  END t1b[178]
  PIN t1b[179]
    DIRECTION INPUT ;
    USE SIGNAL ;
    PORT
      LAYER M5 ;
        RECT  75.504 0 75.528 0.084 ;
    END
  END t1b[179]
  PIN t1b[17]
    DIRECTION INPUT ;
    USE SIGNAL ;
    PORT
      LAYER M5 ;
        RECT  49.968 0 49.992 0.084 ;
    END
  END t1b[17]
  PIN t1b[180]
    DIRECTION INPUT ;
    USE SIGNAL ;
    PORT
      LAYER M5 ;
        RECT  75.6 0 75.624 0.084 ;
    END
  END t1b[180]
  PIN t1b[181]
    DIRECTION INPUT ;
    USE SIGNAL ;
    PORT
      LAYER M5 ;
        RECT  75.696 0 75.72 0.084 ;
    END
  END t1b[181]
  PIN t1b[182]
    DIRECTION INPUT ;
    USE SIGNAL ;
    PORT
      LAYER M5 ;
        RECT  75.792 0 75.816 0.084 ;
    END
  END t1b[182]
  PIN t1b[183]
    DIRECTION INPUT ;
    USE SIGNAL ;
    PORT
      LAYER M5 ;
        RECT  75.888 0 75.912 0.084 ;
    END
  END t1b[183]
  PIN t1b[184]
    DIRECTION INPUT ;
    USE SIGNAL ;
    PORT
      LAYER M5 ;
        RECT  75.984 0 76.008 0.084 ;
    END
  END t1b[184]
  PIN t1b[185]
    DIRECTION INPUT ;
    USE SIGNAL ;
    PORT
      LAYER M5 ;
        RECT  76.08 0 76.104 0.084 ;
    END
  END t1b[185]
  PIN t1b[186]
    DIRECTION INPUT ;
    USE SIGNAL ;
    PORT
      LAYER M5 ;
        RECT  76.176 0 76.2 0.084 ;
    END
  END t1b[186]
  PIN t1b[187]
    DIRECTION INPUT ;
    USE SIGNAL ;
    PORT
      LAYER M5 ;
        RECT  76.272 0 76.296 0.084 ;
    END
  END t1b[187]
  PIN t1b[188]
    DIRECTION INPUT ;
    USE SIGNAL ;
    PORT
      LAYER M5 ;
        RECT  76.368 0 76.392 0.084 ;
    END
  END t1b[188]
  PIN t1b[189]
    DIRECTION INPUT ;
    USE SIGNAL ;
    PORT
      LAYER M5 ;
        RECT  76.464 0 76.488 0.084 ;
    END
  END t1b[189]
  PIN t1b[18]
    DIRECTION INPUT ;
    USE SIGNAL ;
    PORT
      LAYER M5 ;
        RECT  50.064 0 50.088 0.084 ;
    END
  END t1b[18]
  PIN t1b[190]
    DIRECTION INPUT ;
    USE SIGNAL ;
    PORT
      LAYER M5 ;
        RECT  76.56 0 76.584 0.084 ;
    END
  END t1b[190]
  PIN t1b[191]
    DIRECTION INPUT ;
    USE SIGNAL ;
    PORT
      LAYER M5 ;
        RECT  76.656 0 76.68 0.084 ;
    END
  END t1b[191]
  PIN t1b[192]
    DIRECTION INPUT ;
    USE SIGNAL ;
    PORT
      LAYER M5 ;
        RECT  61.392 0 61.416 0.084 ;
    END
  END t1b[192]
  PIN t1b[193]
    DIRECTION INPUT ;
    USE SIGNAL ;
    PORT
      LAYER M5 ;
        RECT  61.488 0 61.512 0.084 ;
    END
  END t1b[193]
  PIN t1b[194]
    DIRECTION INPUT ;
    USE SIGNAL ;
    PORT
      LAYER M5 ;
        RECT  61.584 0 61.608 0.084 ;
    END
  END t1b[194]
  PIN t1b[195]
    DIRECTION INPUT ;
    USE SIGNAL ;
    PORT
      LAYER M5 ;
        RECT  61.68 0 61.704 0.084 ;
    END
  END t1b[195]
  PIN t1b[196]
    DIRECTION INPUT ;
    USE SIGNAL ;
    PORT
      LAYER M5 ;
        RECT  61.776 0 61.8 0.084 ;
    END
  END t1b[196]
  PIN t1b[197]
    DIRECTION INPUT ;
    USE SIGNAL ;
    PORT
      LAYER M5 ;
        RECT  61.872 0 61.896 0.084 ;
    END
  END t1b[197]
  PIN t1b[198]
    DIRECTION INPUT ;
    USE SIGNAL ;
    PORT
      LAYER M5 ;
        RECT  61.968 0 61.992 0.084 ;
    END
  END t1b[198]
  PIN t1b[199]
    DIRECTION INPUT ;
    USE SIGNAL ;
    PORT
      LAYER M5 ;
        RECT  62.064 0 62.088 0.084 ;
    END
  END t1b[199]
  PIN t1b[19]
    DIRECTION INPUT ;
    USE SIGNAL ;
    PORT
      LAYER M5 ;
        RECT  50.16 0 50.184 0.084 ;
    END
  END t1b[19]
  PIN t1b[1]
    DIRECTION INPUT ;
    USE SIGNAL ;
    PORT
      LAYER M5 ;
        RECT  48.432 0 48.456 0.084 ;
    END
  END t1b[1]
  PIN t1b[200]
    DIRECTION INPUT ;
    USE SIGNAL ;
    PORT
      LAYER M5 ;
        RECT  62.16 0 62.184 0.084 ;
    END
  END t1b[200]
  PIN t1b[201]
    DIRECTION INPUT ;
    USE SIGNAL ;
    PORT
      LAYER M5 ;
        RECT  62.256 0 62.28 0.084 ;
    END
  END t1b[201]
  PIN t1b[202]
    DIRECTION INPUT ;
    USE SIGNAL ;
    PORT
      LAYER M5 ;
        RECT  62.352 0 62.376 0.084 ;
    END
  END t1b[202]
  PIN t1b[203]
    DIRECTION INPUT ;
    USE SIGNAL ;
    PORT
      LAYER M5 ;
        RECT  62.448 0 62.472 0.084 ;
    END
  END t1b[203]
  PIN t1b[204]
    DIRECTION INPUT ;
    USE SIGNAL ;
    PORT
      LAYER M5 ;
        RECT  62.544 0 62.568 0.084 ;
    END
  END t1b[204]
  PIN t1b[205]
    DIRECTION INPUT ;
    USE SIGNAL ;
    PORT
      LAYER M5 ;
        RECT  62.64 0 62.664 0.084 ;
    END
  END t1b[205]
  PIN t1b[206]
    DIRECTION INPUT ;
    USE SIGNAL ;
    PORT
      LAYER M5 ;
        RECT  62.736 0 62.76 0.084 ;
    END
  END t1b[206]
  PIN t1b[207]
    DIRECTION INPUT ;
    USE SIGNAL ;
    PORT
      LAYER M5 ;
        RECT  62.832 0 62.856 0.084 ;
    END
  END t1b[207]
  PIN t1b[208]
    DIRECTION INPUT ;
    USE SIGNAL ;
    PORT
      LAYER M5 ;
        RECT  62.928 0 62.952 0.084 ;
    END
  END t1b[208]
  PIN t1b[209]
    DIRECTION INPUT ;
    USE SIGNAL ;
    PORT
      LAYER M5 ;
        RECT  63.024 0 63.048 0.084 ;
    END
  END t1b[209]
  PIN t1b[20]
    DIRECTION INPUT ;
    USE SIGNAL ;
    PORT
      LAYER M5 ;
        RECT  50.256 0 50.28 0.084 ;
    END
  END t1b[20]
  PIN t1b[210]
    DIRECTION INPUT ;
    USE SIGNAL ;
    PORT
      LAYER M5 ;
        RECT  63.12 0 63.144 0.084 ;
    END
  END t1b[210]
  PIN t1b[211]
    DIRECTION INPUT ;
    USE SIGNAL ;
    PORT
      LAYER M5 ;
        RECT  63.216 0 63.24 0.084 ;
    END
  END t1b[211]
  PIN t1b[212]
    DIRECTION INPUT ;
    USE SIGNAL ;
    PORT
      LAYER M5 ;
        RECT  63.312 0 63.336 0.084 ;
    END
  END t1b[212]
  PIN t1b[213]
    DIRECTION INPUT ;
    USE SIGNAL ;
    PORT
      LAYER M5 ;
        RECT  63.408 0 63.432 0.084 ;
    END
  END t1b[213]
  PIN t1b[214]
    DIRECTION INPUT ;
    USE SIGNAL ;
    PORT
      LAYER M5 ;
        RECT  63.504 0 63.528 0.084 ;
    END
  END t1b[214]
  PIN t1b[215]
    DIRECTION INPUT ;
    USE SIGNAL ;
    PORT
      LAYER M5 ;
        RECT  63.6 0 63.624 0.084 ;
    END
  END t1b[215]
  PIN t1b[216]
    DIRECTION INPUT ;
    USE SIGNAL ;
    PORT
      LAYER M5 ;
        RECT  63.696 0 63.72 0.084 ;
    END
  END t1b[216]
  PIN t1b[217]
    DIRECTION INPUT ;
    USE SIGNAL ;
    PORT
      LAYER M5 ;
        RECT  63.792 0 63.816 0.084 ;
    END
  END t1b[217]
  PIN t1b[218]
    DIRECTION INPUT ;
    USE SIGNAL ;
    PORT
      LAYER M5 ;
        RECT  63.888 0 63.912 0.084 ;
    END
  END t1b[218]
  PIN t1b[219]
    DIRECTION INPUT ;
    USE SIGNAL ;
    PORT
      LAYER M5 ;
        RECT  63.984 0 64.008 0.084 ;
    END
  END t1b[219]
  PIN t1b[21]
    DIRECTION INPUT ;
    USE SIGNAL ;
    PORT
      LAYER M5 ;
        RECT  50.352 0 50.376 0.084 ;
    END
  END t1b[21]
  PIN t1b[220]
    DIRECTION INPUT ;
    USE SIGNAL ;
    PORT
      LAYER M5 ;
        RECT  64.08 0 64.104 0.084 ;
    END
  END t1b[220]
  PIN t1b[221]
    DIRECTION INPUT ;
    USE SIGNAL ;
    PORT
      LAYER M5 ;
        RECT  64.176 0 64.2 0.084 ;
    END
  END t1b[221]
  PIN t1b[222]
    DIRECTION INPUT ;
    USE SIGNAL ;
    PORT
      LAYER M5 ;
        RECT  64.272 0 64.296 0.084 ;
    END
  END t1b[222]
  PIN t1b[223]
    DIRECTION INPUT ;
    USE SIGNAL ;
    PORT
      LAYER M5 ;
        RECT  64.368 0 64.392 0.084 ;
    END
  END t1b[223]
  PIN t1b[224]
    DIRECTION INPUT ;
    USE SIGNAL ;
    PORT
      LAYER M5 ;
        RECT  51.408 0 51.432 0.084 ;
    END
  END t1b[224]
  PIN t1b[225]
    DIRECTION INPUT ;
    USE SIGNAL ;
    PORT
      LAYER M5 ;
        RECT  51.504 0 51.528 0.084 ;
    END
  END t1b[225]
  PIN t1b[226]
    DIRECTION INPUT ;
    USE SIGNAL ;
    PORT
      LAYER M5 ;
        RECT  51.6 0 51.624 0.084 ;
    END
  END t1b[226]
  PIN t1b[227]
    DIRECTION INPUT ;
    USE SIGNAL ;
    PORT
      LAYER M5 ;
        RECT  51.696 0 51.72 0.084 ;
    END
  END t1b[227]
  PIN t1b[228]
    DIRECTION INPUT ;
    USE SIGNAL ;
    PORT
      LAYER M5 ;
        RECT  51.792 0 51.816 0.084 ;
    END
  END t1b[228]
  PIN t1b[229]
    DIRECTION INPUT ;
    USE SIGNAL ;
    PORT
      LAYER M5 ;
        RECT  51.888 0 51.912 0.084 ;
    END
  END t1b[229]
  PIN t1b[22]
    DIRECTION INPUT ;
    USE SIGNAL ;
    PORT
      LAYER M5 ;
        RECT  50.448 0 50.472 0.084 ;
    END
  END t1b[22]
  PIN t1b[230]
    DIRECTION INPUT ;
    USE SIGNAL ;
    PORT
      LAYER M5 ;
        RECT  51.984 0 52.008 0.084 ;
    END
  END t1b[230]
  PIN t1b[231]
    DIRECTION INPUT ;
    USE SIGNAL ;
    PORT
      LAYER M5 ;
        RECT  52.08 0 52.104 0.084 ;
    END
  END t1b[231]
  PIN t1b[232]
    DIRECTION INPUT ;
    USE SIGNAL ;
    PORT
      LAYER M5 ;
        RECT  52.176 0 52.2 0.084 ;
    END
  END t1b[232]
  PIN t1b[233]
    DIRECTION INPUT ;
    USE SIGNAL ;
    PORT
      LAYER M5 ;
        RECT  52.272 0 52.296 0.084 ;
    END
  END t1b[233]
  PIN t1b[234]
    DIRECTION INPUT ;
    USE SIGNAL ;
    PORT
      LAYER M5 ;
        RECT  52.368 0 52.392 0.084 ;
    END
  END t1b[234]
  PIN t1b[235]
    DIRECTION INPUT ;
    USE SIGNAL ;
    PORT
      LAYER M5 ;
        RECT  52.464 0 52.488 0.084 ;
    END
  END t1b[235]
  PIN t1b[236]
    DIRECTION INPUT ;
    USE SIGNAL ;
    PORT
      LAYER M5 ;
        RECT  52.56 0 52.584 0.084 ;
    END
  END t1b[236]
  PIN t1b[237]
    DIRECTION INPUT ;
    USE SIGNAL ;
    PORT
      LAYER M5 ;
        RECT  52.656 0 52.68 0.084 ;
    END
  END t1b[237]
  PIN t1b[238]
    DIRECTION INPUT ;
    USE SIGNAL ;
    PORT
      LAYER M5 ;
        RECT  52.752 0 52.776 0.084 ;
    END
  END t1b[238]
  PIN t1b[239]
    DIRECTION INPUT ;
    USE SIGNAL ;
    PORT
      LAYER M5 ;
        RECT  52.848 0 52.872 0.084 ;
    END
  END t1b[239]
  PIN t1b[23]
    DIRECTION INPUT ;
    USE SIGNAL ;
    PORT
      LAYER M5 ;
        RECT  50.544 0 50.568 0.084 ;
    END
  END t1b[23]
  PIN t1b[240]
    DIRECTION INPUT ;
    USE SIGNAL ;
    PORT
      LAYER M5 ;
        RECT  52.944 0 52.968 0.084 ;
    END
  END t1b[240]
  PIN t1b[241]
    DIRECTION INPUT ;
    USE SIGNAL ;
    PORT
      LAYER M5 ;
        RECT  53.04 0 53.064 0.084 ;
    END
  END t1b[241]
  PIN t1b[242]
    DIRECTION INPUT ;
    USE SIGNAL ;
    PORT
      LAYER M5 ;
        RECT  53.136 0 53.16 0.084 ;
    END
  END t1b[242]
  PIN t1b[243]
    DIRECTION INPUT ;
    USE SIGNAL ;
    PORT
      LAYER M5 ;
        RECT  53.232 0 53.256 0.084 ;
    END
  END t1b[243]
  PIN t1b[244]
    DIRECTION INPUT ;
    USE SIGNAL ;
    PORT
      LAYER M5 ;
        RECT  53.328 0 53.352 0.084 ;
    END
  END t1b[244]
  PIN t1b[245]
    DIRECTION INPUT ;
    USE SIGNAL ;
    PORT
      LAYER M5 ;
        RECT  53.424 0 53.448 0.084 ;
    END
  END t1b[245]
  PIN t1b[246]
    DIRECTION INPUT ;
    USE SIGNAL ;
    PORT
      LAYER M5 ;
        RECT  53.52 0 53.544 0.084 ;
    END
  END t1b[246]
  PIN t1b[247]
    DIRECTION INPUT ;
    USE SIGNAL ;
    PORT
      LAYER M5 ;
        RECT  53.616 0 53.64 0.084 ;
    END
  END t1b[247]
  PIN t1b[248]
    DIRECTION INPUT ;
    USE SIGNAL ;
    PORT
      LAYER M5 ;
        RECT  53.712 0 53.736 0.084 ;
    END
  END t1b[248]
  PIN t1b[249]
    DIRECTION INPUT ;
    USE SIGNAL ;
    PORT
      LAYER M5 ;
        RECT  53.808 0 53.832 0.084 ;
    END
  END t1b[249]
  PIN t1b[24]
    DIRECTION INPUT ;
    USE SIGNAL ;
    PORT
      LAYER M5 ;
        RECT  50.64 0 50.664 0.084 ;
    END
  END t1b[24]
  PIN t1b[250]
    DIRECTION INPUT ;
    USE SIGNAL ;
    PORT
      LAYER M5 ;
        RECT  53.904 0 53.928 0.084 ;
    END
  END t1b[250]
  PIN t1b[251]
    DIRECTION INPUT ;
    USE SIGNAL ;
    PORT
      LAYER M5 ;
        RECT  54 0 54.024 0.084 ;
    END
  END t1b[251]
  PIN t1b[252]
    DIRECTION INPUT ;
    USE SIGNAL ;
    PORT
      LAYER M5 ;
        RECT  54.096 0 54.12 0.084 ;
    END
  END t1b[252]
  PIN t1b[253]
    DIRECTION INPUT ;
    USE SIGNAL ;
    PORT
      LAYER M5 ;
        RECT  54.192 0 54.216 0.084 ;
    END
  END t1b[253]
  PIN t1b[254]
    DIRECTION INPUT ;
    USE SIGNAL ;
    PORT
      LAYER M5 ;
        RECT  54.288 0 54.312 0.084 ;
    END
  END t1b[254]
  PIN t1b[255]
    DIRECTION INPUT ;
    USE SIGNAL ;
    PORT
      LAYER M5 ;
        RECT  54.384 0 54.408 0.084 ;
    END
  END t1b[255]
  PIN t1b[256]
    DIRECTION INPUT ;
    USE SIGNAL ;
    PORT
      LAYER M5 ;
        RECT  67.536 0 67.56 0.084 ;
    END
  END t1b[256]
  PIN t1b[257]
    DIRECTION INPUT ;
    USE SIGNAL ;
    PORT
      LAYER M5 ;
        RECT  67.632 0 67.656 0.084 ;
    END
  END t1b[257]
  PIN t1b[258]
    DIRECTION INPUT ;
    USE SIGNAL ;
    PORT
      LAYER M5 ;
        RECT  67.728 0 67.752 0.084 ;
    END
  END t1b[258]
  PIN t1b[259]
    DIRECTION INPUT ;
    USE SIGNAL ;
    PORT
      LAYER M5 ;
        RECT  67.824 0 67.848 0.084 ;
    END
  END t1b[259]
  PIN t1b[25]
    DIRECTION INPUT ;
    USE SIGNAL ;
    PORT
      LAYER M5 ;
        RECT  50.736 0 50.76 0.084 ;
    END
  END t1b[25]
  PIN t1b[260]
    DIRECTION INPUT ;
    USE SIGNAL ;
    PORT
      LAYER M5 ;
        RECT  67.92 0 67.944 0.084 ;
    END
  END t1b[260]
  PIN t1b[261]
    DIRECTION INPUT ;
    USE SIGNAL ;
    PORT
      LAYER M5 ;
        RECT  68.016 0 68.04 0.084 ;
    END
  END t1b[261]
  PIN t1b[262]
    DIRECTION INPUT ;
    USE SIGNAL ;
    PORT
      LAYER M5 ;
        RECT  68.112 0 68.136 0.084 ;
    END
  END t1b[262]
  PIN t1b[263]
    DIRECTION INPUT ;
    USE SIGNAL ;
    PORT
      LAYER M5 ;
        RECT  68.208 0 68.232 0.084 ;
    END
  END t1b[263]
  PIN t1b[264]
    DIRECTION INPUT ;
    USE SIGNAL ;
    PORT
      LAYER M5 ;
        RECT  68.304 0 68.328 0.084 ;
    END
  END t1b[264]
  PIN t1b[265]
    DIRECTION INPUT ;
    USE SIGNAL ;
    PORT
      LAYER M5 ;
        RECT  68.4 0 68.424 0.084 ;
    END
  END t1b[265]
  PIN t1b[266]
    DIRECTION INPUT ;
    USE SIGNAL ;
    PORT
      LAYER M5 ;
        RECT  68.496 0 68.52 0.084 ;
    END
  END t1b[266]
  PIN t1b[267]
    DIRECTION INPUT ;
    USE SIGNAL ;
    PORT
      LAYER M5 ;
        RECT  68.592 0 68.616 0.084 ;
    END
  END t1b[267]
  PIN t1b[268]
    DIRECTION INPUT ;
    USE SIGNAL ;
    PORT
      LAYER M5 ;
        RECT  68.688 0 68.712 0.084 ;
    END
  END t1b[268]
  PIN t1b[269]
    DIRECTION INPUT ;
    USE SIGNAL ;
    PORT
      LAYER M5 ;
        RECT  68.784 0 68.808 0.084 ;
    END
  END t1b[269]
  PIN t1b[26]
    DIRECTION INPUT ;
    USE SIGNAL ;
    PORT
      LAYER M5 ;
        RECT  50.832 0 50.856 0.084 ;
    END
  END t1b[26]
  PIN t1b[270]
    DIRECTION INPUT ;
    USE SIGNAL ;
    PORT
      LAYER M5 ;
        RECT  68.88 0 68.904 0.084 ;
    END
  END t1b[270]
  PIN t1b[271]
    DIRECTION INPUT ;
    USE SIGNAL ;
    PORT
      LAYER M5 ;
        RECT  68.976 0 69 0.084 ;
    END
  END t1b[271]
  PIN t1b[272]
    DIRECTION INPUT ;
    USE SIGNAL ;
    PORT
      LAYER M5 ;
        RECT  69.072 0 69.096 0.084 ;
    END
  END t1b[272]
  PIN t1b[273]
    DIRECTION INPUT ;
    USE SIGNAL ;
    PORT
      LAYER M5 ;
        RECT  69.168 0 69.192 0.084 ;
    END
  END t1b[273]
  PIN t1b[274]
    DIRECTION INPUT ;
    USE SIGNAL ;
    PORT
      LAYER M5 ;
        RECT  69.264 0 69.288 0.084 ;
    END
  END t1b[274]
  PIN t1b[275]
    DIRECTION INPUT ;
    USE SIGNAL ;
    PORT
      LAYER M5 ;
        RECT  69.36 0 69.384 0.084 ;
    END
  END t1b[275]
  PIN t1b[276]
    DIRECTION INPUT ;
    USE SIGNAL ;
    PORT
      LAYER M5 ;
        RECT  69.456 0 69.48 0.084 ;
    END
  END t1b[276]
  PIN t1b[277]
    DIRECTION INPUT ;
    USE SIGNAL ;
    PORT
      LAYER M5 ;
        RECT  69.552 0 69.576 0.084 ;
    END
  END t1b[277]
  PIN t1b[278]
    DIRECTION INPUT ;
    USE SIGNAL ;
    PORT
      LAYER M5 ;
        RECT  69.648 0 69.672 0.084 ;
    END
  END t1b[278]
  PIN t1b[279]
    DIRECTION INPUT ;
    USE SIGNAL ;
    PORT
      LAYER M5 ;
        RECT  69.744 0 69.768 0.084 ;
    END
  END t1b[279]
  PIN t1b[27]
    DIRECTION INPUT ;
    USE SIGNAL ;
    PORT
      LAYER M5 ;
        RECT  50.928 0 50.952 0.084 ;
    END
  END t1b[27]
  PIN t1b[280]
    DIRECTION INPUT ;
    USE SIGNAL ;
    PORT
      LAYER M5 ;
        RECT  69.84 0 69.864 0.084 ;
    END
  END t1b[280]
  PIN t1b[281]
    DIRECTION INPUT ;
    USE SIGNAL ;
    PORT
      LAYER M5 ;
        RECT  69.936 0 69.96 0.084 ;
    END
  END t1b[281]
  PIN t1b[282]
    DIRECTION INPUT ;
    USE SIGNAL ;
    PORT
      LAYER M5 ;
        RECT  70.032 0 70.056 0.084 ;
    END
  END t1b[282]
  PIN t1b[283]
    DIRECTION INPUT ;
    USE SIGNAL ;
    PORT
      LAYER M5 ;
        RECT  70.128 0 70.152 0.084 ;
    END
  END t1b[283]
  PIN t1b[284]
    DIRECTION INPUT ;
    USE SIGNAL ;
    PORT
      LAYER M5 ;
        RECT  70.224 0 70.248 0.084 ;
    END
  END t1b[284]
  PIN t1b[285]
    DIRECTION INPUT ;
    USE SIGNAL ;
    PORT
      LAYER M5 ;
        RECT  70.32 0 70.344 0.084 ;
    END
  END t1b[285]
  PIN t1b[286]
    DIRECTION INPUT ;
    USE SIGNAL ;
    PORT
      LAYER M5 ;
        RECT  70.416 0 70.44 0.084 ;
    END
  END t1b[286]
  PIN t1b[287]
    DIRECTION INPUT ;
    USE SIGNAL ;
    PORT
      LAYER M5 ;
        RECT  70.512 0 70.536 0.084 ;
    END
  END t1b[287]
  PIN t1b[288]
    DIRECTION INPUT ;
    USE SIGNAL ;
    PORT
      LAYER M5 ;
        RECT  64.464 0 64.488 0.084 ;
    END
  END t1b[288]
  PIN t1b[289]
    DIRECTION INPUT ;
    USE SIGNAL ;
    PORT
      LAYER M5 ;
        RECT  64.56 0 64.584 0.084 ;
    END
  END t1b[289]
  PIN t1b[28]
    DIRECTION INPUT ;
    USE SIGNAL ;
    PORT
      LAYER M5 ;
        RECT  51.024 0 51.048 0.084 ;
    END
  END t1b[28]
  PIN t1b[290]
    DIRECTION INPUT ;
    USE SIGNAL ;
    PORT
      LAYER M5 ;
        RECT  64.656 0 64.68 0.084 ;
    END
  END t1b[290]
  PIN t1b[291]
    DIRECTION INPUT ;
    USE SIGNAL ;
    PORT
      LAYER M5 ;
        RECT  64.752 0 64.776 0.084 ;
    END
  END t1b[291]
  PIN t1b[292]
    DIRECTION INPUT ;
    USE SIGNAL ;
    PORT
      LAYER M5 ;
        RECT  64.848 0 64.872 0.084 ;
    END
  END t1b[292]
  PIN t1b[293]
    DIRECTION INPUT ;
    USE SIGNAL ;
    PORT
      LAYER M5 ;
        RECT  64.944 0 64.968 0.084 ;
    END
  END t1b[293]
  PIN t1b[294]
    DIRECTION INPUT ;
    USE SIGNAL ;
    PORT
      LAYER M5 ;
        RECT  65.04 0 65.064 0.084 ;
    END
  END t1b[294]
  PIN t1b[295]
    DIRECTION INPUT ;
    USE SIGNAL ;
    PORT
      LAYER M5 ;
        RECT  65.136 0 65.16 0.084 ;
    END
  END t1b[295]
  PIN t1b[296]
    DIRECTION INPUT ;
    USE SIGNAL ;
    PORT
      LAYER M5 ;
        RECT  65.232 0 65.256 0.084 ;
    END
  END t1b[296]
  PIN t1b[297]
    DIRECTION INPUT ;
    USE SIGNAL ;
    PORT
      LAYER M5 ;
        RECT  65.328 0 65.352 0.084 ;
    END
  END t1b[297]
  PIN t1b[298]
    DIRECTION INPUT ;
    USE SIGNAL ;
    PORT
      LAYER M5 ;
        RECT  65.424 0 65.448 0.084 ;
    END
  END t1b[298]
  PIN t1b[299]
    DIRECTION INPUT ;
    USE SIGNAL ;
    PORT
      LAYER M5 ;
        RECT  65.52 0 65.544 0.084 ;
    END
  END t1b[299]
  PIN t1b[29]
    DIRECTION INPUT ;
    USE SIGNAL ;
    PORT
      LAYER M5 ;
        RECT  51.12 0 51.144 0.084 ;
    END
  END t1b[29]
  PIN t1b[2]
    DIRECTION INPUT ;
    USE SIGNAL ;
    PORT
      LAYER M5 ;
        RECT  48.528 0 48.552 0.084 ;
    END
  END t1b[2]
  PIN t1b[300]
    DIRECTION INPUT ;
    USE SIGNAL ;
    PORT
      LAYER M5 ;
        RECT  65.616 0 65.64 0.084 ;
    END
  END t1b[300]
  PIN t1b[301]
    DIRECTION INPUT ;
    USE SIGNAL ;
    PORT
      LAYER M5 ;
        RECT  65.712 0 65.736 0.084 ;
    END
  END t1b[301]
  PIN t1b[302]
    DIRECTION INPUT ;
    USE SIGNAL ;
    PORT
      LAYER M5 ;
        RECT  65.808 0 65.832 0.084 ;
    END
  END t1b[302]
  PIN t1b[303]
    DIRECTION INPUT ;
    USE SIGNAL ;
    PORT
      LAYER M5 ;
        RECT  65.904 0 65.928 0.084 ;
    END
  END t1b[303]
  PIN t1b[304]
    DIRECTION INPUT ;
    USE SIGNAL ;
    PORT
      LAYER M5 ;
        RECT  66 0 66.024 0.084 ;
    END
  END t1b[304]
  PIN t1b[305]
    DIRECTION INPUT ;
    USE SIGNAL ;
    PORT
      LAYER M5 ;
        RECT  66.096 0 66.12 0.084 ;
    END
  END t1b[305]
  PIN t1b[306]
    DIRECTION INPUT ;
    USE SIGNAL ;
    PORT
      LAYER M5 ;
        RECT  66.192 0 66.216 0.084 ;
    END
  END t1b[306]
  PIN t1b[307]
    DIRECTION INPUT ;
    USE SIGNAL ;
    PORT
      LAYER M5 ;
        RECT  66.288 0 66.312 0.084 ;
    END
  END t1b[307]
  PIN t1b[308]
    DIRECTION INPUT ;
    USE SIGNAL ;
    PORT
      LAYER M5 ;
        RECT  66.384 0 66.408 0.084 ;
    END
  END t1b[308]
  PIN t1b[309]
    DIRECTION INPUT ;
    USE SIGNAL ;
    PORT
      LAYER M5 ;
        RECT  66.48 0 66.504 0.084 ;
    END
  END t1b[309]
  PIN t1b[30]
    DIRECTION INPUT ;
    USE SIGNAL ;
    PORT
      LAYER M5 ;
        RECT  51.216 0 51.24 0.084 ;
    END
  END t1b[30]
  PIN t1b[310]
    DIRECTION INPUT ;
    USE SIGNAL ;
    PORT
      LAYER M5 ;
        RECT  66.576 0 66.6 0.084 ;
    END
  END t1b[310]
  PIN t1b[311]
    DIRECTION INPUT ;
    USE SIGNAL ;
    PORT
      LAYER M5 ;
        RECT  66.672 0 66.696 0.084 ;
    END
  END t1b[311]
  PIN t1b[312]
    DIRECTION INPUT ;
    USE SIGNAL ;
    PORT
      LAYER M5 ;
        RECT  66.768 0 66.792 0.084 ;
    END
  END t1b[312]
  PIN t1b[313]
    DIRECTION INPUT ;
    USE SIGNAL ;
    PORT
      LAYER M5 ;
        RECT  66.864 0 66.888 0.084 ;
    END
  END t1b[313]
  PIN t1b[314]
    DIRECTION INPUT ;
    USE SIGNAL ;
    PORT
      LAYER M5 ;
        RECT  66.96 0 66.984 0.084 ;
    END
  END t1b[314]
  PIN t1b[315]
    DIRECTION INPUT ;
    USE SIGNAL ;
    PORT
      LAYER M5 ;
        RECT  67.056 0 67.08 0.084 ;
    END
  END t1b[315]
  PIN t1b[316]
    DIRECTION INPUT ;
    USE SIGNAL ;
    PORT
      LAYER M5 ;
        RECT  67.152 0 67.176 0.084 ;
    END
  END t1b[316]
  PIN t1b[317]
    DIRECTION INPUT ;
    USE SIGNAL ;
    PORT
      LAYER M5 ;
        RECT  67.248 0 67.272 0.084 ;
    END
  END t1b[317]
  PIN t1b[318]
    DIRECTION INPUT ;
    USE SIGNAL ;
    PORT
      LAYER M5 ;
        RECT  67.344 0 67.368 0.084 ;
    END
  END t1b[318]
  PIN t1b[319]
    DIRECTION INPUT ;
    USE SIGNAL ;
    PORT
      LAYER M5 ;
        RECT  67.44 0 67.464 0.084 ;
    END
  END t1b[319]
  PIN t1b[31]
    DIRECTION INPUT ;
    USE SIGNAL ;
    PORT
      LAYER M5 ;
        RECT  51.312 0 51.336 0.084 ;
    END
  END t1b[31]
  PIN t1b[320]
    DIRECTION INPUT ;
    USE SIGNAL ;
    PORT
      LAYER M5 ;
        RECT  35.28 0 35.304 0.084 ;
    END
  END t1b[320]
  PIN t1b[321]
    DIRECTION INPUT ;
    USE SIGNAL ;
    PORT
      LAYER M5 ;
        RECT  35.376 0 35.4 0.084 ;
    END
  END t1b[321]
  PIN t1b[322]
    DIRECTION INPUT ;
    USE SIGNAL ;
    PORT
      LAYER M5 ;
        RECT  35.472 0 35.496 0.084 ;
    END
  END t1b[322]
  PIN t1b[323]
    DIRECTION INPUT ;
    USE SIGNAL ;
    PORT
      LAYER M5 ;
        RECT  35.568 0 35.592 0.084 ;
    END
  END t1b[323]
  PIN t1b[324]
    DIRECTION INPUT ;
    USE SIGNAL ;
    PORT
      LAYER M5 ;
        RECT  35.664 0 35.688 0.084 ;
    END
  END t1b[324]
  PIN t1b[325]
    DIRECTION INPUT ;
    USE SIGNAL ;
    PORT
      LAYER M5 ;
        RECT  35.76 0 35.784 0.084 ;
    END
  END t1b[325]
  PIN t1b[326]
    DIRECTION INPUT ;
    USE SIGNAL ;
    PORT
      LAYER M5 ;
        RECT  35.856 0 35.88 0.084 ;
    END
  END t1b[326]
  PIN t1b[327]
    DIRECTION INPUT ;
    USE SIGNAL ;
    PORT
      LAYER M5 ;
        RECT  35.952 0 35.976 0.084 ;
    END
  END t1b[327]
  PIN t1b[328]
    DIRECTION INPUT ;
    USE SIGNAL ;
    PORT
      LAYER M5 ;
        RECT  36.048 0 36.072 0.084 ;
    END
  END t1b[328]
  PIN t1b[329]
    DIRECTION INPUT ;
    USE SIGNAL ;
    PORT
      LAYER M5 ;
        RECT  36.144 0 36.168 0.084 ;
    END
  END t1b[329]
  PIN t1b[32]
    DIRECTION INPUT ;
    USE SIGNAL ;
    PORT
      LAYER M5 ;
        RECT  83.664 0 83.688 0.084 ;
    END
  END t1b[32]
  PIN t1b[330]
    DIRECTION INPUT ;
    USE SIGNAL ;
    PORT
      LAYER M5 ;
        RECT  36.24 0 36.264 0.084 ;
    END
  END t1b[330]
  PIN t1b[331]
    DIRECTION INPUT ;
    USE SIGNAL ;
    PORT
      LAYER M5 ;
        RECT  36.336 0 36.36 0.084 ;
    END
  END t1b[331]
  PIN t1b[332]
    DIRECTION INPUT ;
    USE SIGNAL ;
    PORT
      LAYER M5 ;
        RECT  36.432 0 36.456 0.084 ;
    END
  END t1b[332]
  PIN t1b[333]
    DIRECTION INPUT ;
    USE SIGNAL ;
    PORT
      LAYER M5 ;
        RECT  36.528 0 36.552 0.084 ;
    END
  END t1b[333]
  PIN t1b[334]
    DIRECTION INPUT ;
    USE SIGNAL ;
    PORT
      LAYER M5 ;
        RECT  36.624 0 36.648 0.084 ;
    END
  END t1b[334]
  PIN t1b[335]
    DIRECTION INPUT ;
    USE SIGNAL ;
    PORT
      LAYER M5 ;
        RECT  36.72 0 36.744 0.084 ;
    END
  END t1b[335]
  PIN t1b[336]
    DIRECTION INPUT ;
    USE SIGNAL ;
    PORT
      LAYER M5 ;
        RECT  36.816 0 36.84 0.084 ;
    END
  END t1b[336]
  PIN t1b[337]
    DIRECTION INPUT ;
    USE SIGNAL ;
    PORT
      LAYER M5 ;
        RECT  36.912 0 36.936 0.084 ;
    END
  END t1b[337]
  PIN t1b[338]
    DIRECTION INPUT ;
    USE SIGNAL ;
    PORT
      LAYER M5 ;
        RECT  37.008 0 37.032 0.084 ;
    END
  END t1b[338]
  PIN t1b[339]
    DIRECTION INPUT ;
    USE SIGNAL ;
    PORT
      LAYER M5 ;
        RECT  37.104 0 37.128 0.084 ;
    END
  END t1b[339]
  PIN t1b[33]
    DIRECTION INPUT ;
    USE SIGNAL ;
    PORT
      LAYER M5 ;
        RECT  83.76 0 83.784 0.084 ;
    END
  END t1b[33]
  PIN t1b[340]
    DIRECTION INPUT ;
    USE SIGNAL ;
    PORT
      LAYER M5 ;
        RECT  37.2 0 37.224 0.084 ;
    END
  END t1b[340]
  PIN t1b[341]
    DIRECTION INPUT ;
    USE SIGNAL ;
    PORT
      LAYER M5 ;
        RECT  37.296 0 37.32 0.084 ;
    END
  END t1b[341]
  PIN t1b[342]
    DIRECTION INPUT ;
    USE SIGNAL ;
    PORT
      LAYER M5 ;
        RECT  37.392 0 37.416 0.084 ;
    END
  END t1b[342]
  PIN t1b[343]
    DIRECTION INPUT ;
    USE SIGNAL ;
    PORT
      LAYER M5 ;
        RECT  37.488 0 37.512 0.084 ;
    END
  END t1b[343]
  PIN t1b[344]
    DIRECTION INPUT ;
    USE SIGNAL ;
    PORT
      LAYER M5 ;
        RECT  37.584 0 37.608 0.084 ;
    END
  END t1b[344]
  PIN t1b[345]
    DIRECTION INPUT ;
    USE SIGNAL ;
    PORT
      LAYER M5 ;
        RECT  37.68 0 37.704 0.084 ;
    END
  END t1b[345]
  PIN t1b[346]
    DIRECTION INPUT ;
    USE SIGNAL ;
    PORT
      LAYER M5 ;
        RECT  37.776 0 37.8 0.084 ;
    END
  END t1b[346]
  PIN t1b[347]
    DIRECTION INPUT ;
    USE SIGNAL ;
    PORT
      LAYER M5 ;
        RECT  37.872 0 37.896 0.084 ;
    END
  END t1b[347]
  PIN t1b[348]
    DIRECTION INPUT ;
    USE SIGNAL ;
    PORT
      LAYER M5 ;
        RECT  37.968 0 37.992 0.084 ;
    END
  END t1b[348]
  PIN t1b[349]
    DIRECTION INPUT ;
    USE SIGNAL ;
    PORT
      LAYER M5 ;
        RECT  38.064 0 38.088 0.084 ;
    END
  END t1b[349]
  PIN t1b[34]
    DIRECTION INPUT ;
    USE SIGNAL ;
    PORT
      LAYER M5 ;
        RECT  83.856 0 83.88 0.084 ;
    END
  END t1b[34]
  PIN t1b[350]
    DIRECTION INPUT ;
    USE SIGNAL ;
    PORT
      LAYER M5 ;
        RECT  38.16 0 38.184 0.084 ;
    END
  END t1b[350]
  PIN t1b[351]
    DIRECTION INPUT ;
    USE SIGNAL ;
    PORT
      LAYER M5 ;
        RECT  38.256 0 38.28 0.084 ;
    END
  END t1b[351]
  PIN t1b[352]
    DIRECTION INPUT ;
    USE SIGNAL ;
    PORT
      LAYER M5 ;
        RECT  70.608 0 70.632 0.084 ;
    END
  END t1b[352]
  PIN t1b[353]
    DIRECTION INPUT ;
    USE SIGNAL ;
    PORT
      LAYER M5 ;
        RECT  70.704 0 70.728 0.084 ;
    END
  END t1b[353]
  PIN t1b[354]
    DIRECTION INPUT ;
    USE SIGNAL ;
    PORT
      LAYER M5 ;
        RECT  70.8 0 70.824 0.084 ;
    END
  END t1b[354]
  PIN t1b[355]
    DIRECTION INPUT ;
    USE SIGNAL ;
    PORT
      LAYER M5 ;
        RECT  70.896 0 70.92 0.084 ;
    END
  END t1b[355]
  PIN t1b[356]
    DIRECTION INPUT ;
    USE SIGNAL ;
    PORT
      LAYER M5 ;
        RECT  70.992 0 71.016 0.084 ;
    END
  END t1b[356]
  PIN t1b[357]
    DIRECTION INPUT ;
    USE SIGNAL ;
    PORT
      LAYER M5 ;
        RECT  71.088 0 71.112 0.084 ;
    END
  END t1b[357]
  PIN t1b[358]
    DIRECTION INPUT ;
    USE SIGNAL ;
    PORT
      LAYER M5 ;
        RECT  71.184 0 71.208 0.084 ;
    END
  END t1b[358]
  PIN t1b[359]
    DIRECTION INPUT ;
    USE SIGNAL ;
    PORT
      LAYER M5 ;
        RECT  71.28 0 71.304 0.084 ;
    END
  END t1b[359]
  PIN t1b[35]
    DIRECTION INPUT ;
    USE SIGNAL ;
    PORT
      LAYER M5 ;
        RECT  83.952 0 83.976 0.084 ;
    END
  END t1b[35]
  PIN t1b[360]
    DIRECTION INPUT ;
    USE SIGNAL ;
    PORT
      LAYER M5 ;
        RECT  71.376 0 71.4 0.084 ;
    END
  END t1b[360]
  PIN t1b[361]
    DIRECTION INPUT ;
    USE SIGNAL ;
    PORT
      LAYER M5 ;
        RECT  71.472 0 71.496 0.084 ;
    END
  END t1b[361]
  PIN t1b[362]
    DIRECTION INPUT ;
    USE SIGNAL ;
    PORT
      LAYER M5 ;
        RECT  71.568 0 71.592 0.084 ;
    END
  END t1b[362]
  PIN t1b[363]
    DIRECTION INPUT ;
    USE SIGNAL ;
    PORT
      LAYER M5 ;
        RECT  71.664 0 71.688 0.084 ;
    END
  END t1b[363]
  PIN t1b[364]
    DIRECTION INPUT ;
    USE SIGNAL ;
    PORT
      LAYER M5 ;
        RECT  71.76 0 71.784 0.084 ;
    END
  END t1b[364]
  PIN t1b[365]
    DIRECTION INPUT ;
    USE SIGNAL ;
    PORT
      LAYER M5 ;
        RECT  71.856 0 71.88 0.084 ;
    END
  END t1b[365]
  PIN t1b[366]
    DIRECTION INPUT ;
    USE SIGNAL ;
    PORT
      LAYER M5 ;
        RECT  71.952 0 71.976 0.084 ;
    END
  END t1b[366]
  PIN t1b[367]
    DIRECTION INPUT ;
    USE SIGNAL ;
    PORT
      LAYER M5 ;
        RECT  72.048 0 72.072 0.084 ;
    END
  END t1b[367]
  PIN t1b[368]
    DIRECTION INPUT ;
    USE SIGNAL ;
    PORT
      LAYER M5 ;
        RECT  72.144 0 72.168 0.084 ;
    END
  END t1b[368]
  PIN t1b[369]
    DIRECTION INPUT ;
    USE SIGNAL ;
    PORT
      LAYER M5 ;
        RECT  72.24 0 72.264 0.084 ;
    END
  END t1b[369]
  PIN t1b[36]
    DIRECTION INPUT ;
    USE SIGNAL ;
    PORT
      LAYER M5 ;
        RECT  84.048 0 84.072 0.084 ;
    END
  END t1b[36]
  PIN t1b[370]
    DIRECTION INPUT ;
    USE SIGNAL ;
    PORT
      LAYER M5 ;
        RECT  72.336 0 72.36 0.084 ;
    END
  END t1b[370]
  PIN t1b[371]
    DIRECTION INPUT ;
    USE SIGNAL ;
    PORT
      LAYER M5 ;
        RECT  72.432 0 72.456 0.084 ;
    END
  END t1b[371]
  PIN t1b[372]
    DIRECTION INPUT ;
    USE SIGNAL ;
    PORT
      LAYER M5 ;
        RECT  72.528 0 72.552 0.084 ;
    END
  END t1b[372]
  PIN t1b[373]
    DIRECTION INPUT ;
    USE SIGNAL ;
    PORT
      LAYER M5 ;
        RECT  72.624 0 72.648 0.084 ;
    END
  END t1b[373]
  PIN t1b[374]
    DIRECTION INPUT ;
    USE SIGNAL ;
    PORT
      LAYER M5 ;
        RECT  72.72 0 72.744 0.084 ;
    END
  END t1b[374]
  PIN t1b[375]
    DIRECTION INPUT ;
    USE SIGNAL ;
    PORT
      LAYER M5 ;
        RECT  72.816 0 72.84 0.084 ;
    END
  END t1b[375]
  PIN t1b[376]
    DIRECTION INPUT ;
    USE SIGNAL ;
    PORT
      LAYER M5 ;
        RECT  72.912 0 72.936 0.084 ;
    END
  END t1b[376]
  PIN t1b[377]
    DIRECTION INPUT ;
    USE SIGNAL ;
    PORT
      LAYER M5 ;
        RECT  73.008 0 73.032 0.084 ;
    END
  END t1b[377]
  PIN t1b[378]
    DIRECTION INPUT ;
    USE SIGNAL ;
    PORT
      LAYER M5 ;
        RECT  73.104 0 73.128 0.084 ;
    END
  END t1b[378]
  PIN t1b[379]
    DIRECTION INPUT ;
    USE SIGNAL ;
    PORT
      LAYER M5 ;
        RECT  73.2 0 73.224 0.084 ;
    END
  END t1b[379]
  PIN t1b[37]
    DIRECTION INPUT ;
    USE SIGNAL ;
    PORT
      LAYER M5 ;
        RECT  84.144 0 84.168 0.084 ;
    END
  END t1b[37]
  PIN t1b[380]
    DIRECTION INPUT ;
    USE SIGNAL ;
    PORT
      LAYER M5 ;
        RECT  73.296 0 73.32 0.084 ;
    END
  END t1b[380]
  PIN t1b[381]
    DIRECTION INPUT ;
    USE SIGNAL ;
    PORT
      LAYER M5 ;
        RECT  73.392 0 73.416 0.084 ;
    END
  END t1b[381]
  PIN t1b[382]
    DIRECTION INPUT ;
    USE SIGNAL ;
    PORT
      LAYER M5 ;
        RECT  73.488 0 73.512 0.084 ;
    END
  END t1b[382]
  PIN t1b[383]
    DIRECTION INPUT ;
    USE SIGNAL ;
    PORT
      LAYER M5 ;
        RECT  73.584 0 73.608 0.084 ;
    END
  END t1b[383]
  PIN t1b[384]
    DIRECTION INPUT ;
    USE SIGNAL ;
    PORT
      LAYER M5 ;
        RECT  45.264 0 45.288 0.084 ;
    END
  END t1b[384]
  PIN t1b[385]
    DIRECTION INPUT ;
    USE SIGNAL ;
    PORT
      LAYER M5 ;
        RECT  45.36 0 45.384 0.084 ;
    END
  END t1b[385]
  PIN t1b[386]
    DIRECTION INPUT ;
    USE SIGNAL ;
    PORT
      LAYER M5 ;
        RECT  45.456 0 45.48 0.084 ;
    END
  END t1b[386]
  PIN t1b[387]
    DIRECTION INPUT ;
    USE SIGNAL ;
    PORT
      LAYER M5 ;
        RECT  45.552 0 45.576 0.084 ;
    END
  END t1b[387]
  PIN t1b[388]
    DIRECTION INPUT ;
    USE SIGNAL ;
    PORT
      LAYER M5 ;
        RECT  45.648 0 45.672 0.084 ;
    END
  END t1b[388]
  PIN t1b[389]
    DIRECTION INPUT ;
    USE SIGNAL ;
    PORT
      LAYER M5 ;
        RECT  45.744 0 45.768 0.084 ;
    END
  END t1b[389]
  PIN t1b[38]
    DIRECTION INPUT ;
    USE SIGNAL ;
    PORT
      LAYER M5 ;
        RECT  84.24 0 84.264 0.084 ;
    END
  END t1b[38]
  PIN t1b[390]
    DIRECTION INPUT ;
    USE SIGNAL ;
    PORT
      LAYER M5 ;
        RECT  45.84 0 45.864 0.084 ;
    END
  END t1b[390]
  PIN t1b[391]
    DIRECTION INPUT ;
    USE SIGNAL ;
    PORT
      LAYER M5 ;
        RECT  45.936 0 45.96 0.084 ;
    END
  END t1b[391]
  PIN t1b[392]
    DIRECTION INPUT ;
    USE SIGNAL ;
    PORT
      LAYER M5 ;
        RECT  46.032 0 46.056 0.084 ;
    END
  END t1b[392]
  PIN t1b[393]
    DIRECTION INPUT ;
    USE SIGNAL ;
    PORT
      LAYER M5 ;
        RECT  46.128 0 46.152 0.084 ;
    END
  END t1b[393]
  PIN t1b[394]
    DIRECTION INPUT ;
    USE SIGNAL ;
    PORT
      LAYER M5 ;
        RECT  46.224 0 46.248 0.084 ;
    END
  END t1b[394]
  PIN t1b[395]
    DIRECTION INPUT ;
    USE SIGNAL ;
    PORT
      LAYER M5 ;
        RECT  46.32 0 46.344 0.084 ;
    END
  END t1b[395]
  PIN t1b[396]
    DIRECTION INPUT ;
    USE SIGNAL ;
    PORT
      LAYER M5 ;
        RECT  46.416 0 46.44 0.084 ;
    END
  END t1b[396]
  PIN t1b[397]
    DIRECTION INPUT ;
    USE SIGNAL ;
    PORT
      LAYER M5 ;
        RECT  46.512 0 46.536 0.084 ;
    END
  END t1b[397]
  PIN t1b[398]
    DIRECTION INPUT ;
    USE SIGNAL ;
    PORT
      LAYER M5 ;
        RECT  46.608 0 46.632 0.084 ;
    END
  END t1b[398]
  PIN t1b[399]
    DIRECTION INPUT ;
    USE SIGNAL ;
    PORT
      LAYER M5 ;
        RECT  46.704 0 46.728 0.084 ;
    END
  END t1b[399]
  PIN t1b[39]
    DIRECTION INPUT ;
    USE SIGNAL ;
    PORT
      LAYER M5 ;
        RECT  84.336 0 84.36 0.084 ;
    END
  END t1b[39]
  PIN t1b[3]
    DIRECTION INPUT ;
    USE SIGNAL ;
    PORT
      LAYER M5 ;
        RECT  48.624 0 48.648 0.084 ;
    END
  END t1b[3]
  PIN t1b[400]
    DIRECTION INPUT ;
    USE SIGNAL ;
    PORT
      LAYER M5 ;
        RECT  46.8 0 46.824 0.084 ;
    END
  END t1b[400]
  PIN t1b[401]
    DIRECTION INPUT ;
    USE SIGNAL ;
    PORT
      LAYER M5 ;
        RECT  46.896 0 46.92 0.084 ;
    END
  END t1b[401]
  PIN t1b[402]
    DIRECTION INPUT ;
    USE SIGNAL ;
    PORT
      LAYER M5 ;
        RECT  46.992 0 47.016 0.084 ;
    END
  END t1b[402]
  PIN t1b[403]
    DIRECTION INPUT ;
    USE SIGNAL ;
    PORT
      LAYER M5 ;
        RECT  47.088 0 47.112 0.084 ;
    END
  END t1b[403]
  PIN t1b[404]
    DIRECTION INPUT ;
    USE SIGNAL ;
    PORT
      LAYER M5 ;
        RECT  47.184 0 47.208 0.084 ;
    END
  END t1b[404]
  PIN t1b[405]
    DIRECTION INPUT ;
    USE SIGNAL ;
    PORT
      LAYER M5 ;
        RECT  47.28 0 47.304 0.084 ;
    END
  END t1b[405]
  PIN t1b[406]
    DIRECTION INPUT ;
    USE SIGNAL ;
    PORT
      LAYER M5 ;
        RECT  47.376 0 47.4 0.084 ;
    END
  END t1b[406]
  PIN t1b[407]
    DIRECTION INPUT ;
    USE SIGNAL ;
    PORT
      LAYER M5 ;
        RECT  47.472 0 47.496 0.084 ;
    END
  END t1b[407]
  PIN t1b[408]
    DIRECTION INPUT ;
    USE SIGNAL ;
    PORT
      LAYER M5 ;
        RECT  47.568 0 47.592 0.084 ;
    END
  END t1b[408]
  PIN t1b[409]
    DIRECTION INPUT ;
    USE SIGNAL ;
    PORT
      LAYER M5 ;
        RECT  47.664 0 47.688 0.084 ;
    END
  END t1b[409]
  PIN t1b[40]
    DIRECTION INPUT ;
    USE SIGNAL ;
    PORT
      LAYER M5 ;
        RECT  84.432 0 84.456 0.084 ;
    END
  END t1b[40]
  PIN t1b[410]
    DIRECTION INPUT ;
    USE SIGNAL ;
    PORT
      LAYER M5 ;
        RECT  47.76 0 47.784 0.084 ;
    END
  END t1b[410]
  PIN t1b[411]
    DIRECTION INPUT ;
    USE SIGNAL ;
    PORT
      LAYER M5 ;
        RECT  47.856 0 47.88 0.084 ;
    END
  END t1b[411]
  PIN t1b[412]
    DIRECTION INPUT ;
    USE SIGNAL ;
    PORT
      LAYER M5 ;
        RECT  47.952 0 47.976 0.084 ;
    END
  END t1b[412]
  PIN t1b[413]
    DIRECTION INPUT ;
    USE SIGNAL ;
    PORT
      LAYER M5 ;
        RECT  48.048 0 48.072 0.084 ;
    END
  END t1b[413]
  PIN t1b[414]
    DIRECTION INPUT ;
    USE SIGNAL ;
    PORT
      LAYER M5 ;
        RECT  48.144 0 48.168 0.084 ;
    END
  END t1b[414]
  PIN t1b[415]
    DIRECTION INPUT ;
    USE SIGNAL ;
    PORT
      LAYER M5 ;
        RECT  48.24 0 48.264 0.084 ;
    END
  END t1b[415]
  PIN t1b[416]
    DIRECTION INPUT ;
    USE SIGNAL ;
    PORT
      LAYER M5 ;
        RECT  58.32 0 58.344 0.084 ;
    END
  END t1b[416]
  PIN t1b[417]
    DIRECTION INPUT ;
    USE SIGNAL ;
    PORT
      LAYER M5 ;
        RECT  58.416 0 58.44 0.084 ;
    END
  END t1b[417]
  PIN t1b[418]
    DIRECTION INPUT ;
    USE SIGNAL ;
    PORT
      LAYER M5 ;
        RECT  58.512 0 58.536 0.084 ;
    END
  END t1b[418]
  PIN t1b[419]
    DIRECTION INPUT ;
    USE SIGNAL ;
    PORT
      LAYER M5 ;
        RECT  58.608 0 58.632 0.084 ;
    END
  END t1b[419]
  PIN t1b[41]
    DIRECTION INPUT ;
    USE SIGNAL ;
    PORT
      LAYER M5 ;
        RECT  84.528 0 84.552 0.084 ;
    END
  END t1b[41]
  PIN t1b[420]
    DIRECTION INPUT ;
    USE SIGNAL ;
    PORT
      LAYER M5 ;
        RECT  58.704 0 58.728 0.084 ;
    END
  END t1b[420]
  PIN t1b[421]
    DIRECTION INPUT ;
    USE SIGNAL ;
    PORT
      LAYER M5 ;
        RECT  58.8 0 58.824 0.084 ;
    END
  END t1b[421]
  PIN t1b[422]
    DIRECTION INPUT ;
    USE SIGNAL ;
    PORT
      LAYER M5 ;
        RECT  58.896 0 58.92 0.084 ;
    END
  END t1b[422]
  PIN t1b[423]
    DIRECTION INPUT ;
    USE SIGNAL ;
    PORT
      LAYER M5 ;
        RECT  58.992 0 59.016 0.084 ;
    END
  END t1b[423]
  PIN t1b[424]
    DIRECTION INPUT ;
    USE SIGNAL ;
    PORT
      LAYER M5 ;
        RECT  59.088 0 59.112 0.084 ;
    END
  END t1b[424]
  PIN t1b[425]
    DIRECTION INPUT ;
    USE SIGNAL ;
    PORT
      LAYER M5 ;
        RECT  59.184 0 59.208 0.084 ;
    END
  END t1b[425]
  PIN t1b[426]
    DIRECTION INPUT ;
    USE SIGNAL ;
    PORT
      LAYER M5 ;
        RECT  59.28 0 59.304 0.084 ;
    END
  END t1b[426]
  PIN t1b[427]
    DIRECTION INPUT ;
    USE SIGNAL ;
    PORT
      LAYER M5 ;
        RECT  59.376 0 59.4 0.084 ;
    END
  END t1b[427]
  PIN t1b[428]
    DIRECTION INPUT ;
    USE SIGNAL ;
    PORT
      LAYER M5 ;
        RECT  59.472 0 59.496 0.084 ;
    END
  END t1b[428]
  PIN t1b[429]
    DIRECTION INPUT ;
    USE SIGNAL ;
    PORT
      LAYER M5 ;
        RECT  59.568 0 59.592 0.084 ;
    END
  END t1b[429]
  PIN t1b[42]
    DIRECTION INPUT ;
    USE SIGNAL ;
    PORT
      LAYER M5 ;
        RECT  84.624 0 84.648 0.084 ;
    END
  END t1b[42]
  PIN t1b[430]
    DIRECTION INPUT ;
    USE SIGNAL ;
    PORT
      LAYER M5 ;
        RECT  59.664 0 59.688 0.084 ;
    END
  END t1b[430]
  PIN t1b[431]
    DIRECTION INPUT ;
    USE SIGNAL ;
    PORT
      LAYER M5 ;
        RECT  59.76 0 59.784 0.084 ;
    END
  END t1b[431]
  PIN t1b[432]
    DIRECTION INPUT ;
    USE SIGNAL ;
    PORT
      LAYER M5 ;
        RECT  59.856 0 59.88 0.084 ;
    END
  END t1b[432]
  PIN t1b[433]
    DIRECTION INPUT ;
    USE SIGNAL ;
    PORT
      LAYER M5 ;
        RECT  59.952 0 59.976 0.084 ;
    END
  END t1b[433]
  PIN t1b[434]
    DIRECTION INPUT ;
    USE SIGNAL ;
    PORT
      LAYER M5 ;
        RECT  60.048 0 60.072 0.084 ;
    END
  END t1b[434]
  PIN t1b[435]
    DIRECTION INPUT ;
    USE SIGNAL ;
    PORT
      LAYER M5 ;
        RECT  60.144 0 60.168 0.084 ;
    END
  END t1b[435]
  PIN t1b[436]
    DIRECTION INPUT ;
    USE SIGNAL ;
    PORT
      LAYER M5 ;
        RECT  60.24 0 60.264 0.084 ;
    END
  END t1b[436]
  PIN t1b[437]
    DIRECTION INPUT ;
    USE SIGNAL ;
    PORT
      LAYER M5 ;
        RECT  60.336 0 60.36 0.084 ;
    END
  END t1b[437]
  PIN t1b[438]
    DIRECTION INPUT ;
    USE SIGNAL ;
    PORT
      LAYER M5 ;
        RECT  60.432 0 60.456 0.084 ;
    END
  END t1b[438]
  PIN t1b[439]
    DIRECTION INPUT ;
    USE SIGNAL ;
    PORT
      LAYER M5 ;
        RECT  60.528 0 60.552 0.084 ;
    END
  END t1b[439]
  PIN t1b[43]
    DIRECTION INPUT ;
    USE SIGNAL ;
    PORT
      LAYER M5 ;
        RECT  84.72 0 84.744 0.084 ;
    END
  END t1b[43]
  PIN t1b[440]
    DIRECTION INPUT ;
    USE SIGNAL ;
    PORT
      LAYER M5 ;
        RECT  60.624 0 60.648 0.084 ;
    END
  END t1b[440]
  PIN t1b[441]
    DIRECTION INPUT ;
    USE SIGNAL ;
    PORT
      LAYER M5 ;
        RECT  60.72 0 60.744 0.084 ;
    END
  END t1b[441]
  PIN t1b[442]
    DIRECTION INPUT ;
    USE SIGNAL ;
    PORT
      LAYER M5 ;
        RECT  60.816 0 60.84 0.084 ;
    END
  END t1b[442]
  PIN t1b[443]
    DIRECTION INPUT ;
    USE SIGNAL ;
    PORT
      LAYER M5 ;
        RECT  60.912 0 60.936 0.084 ;
    END
  END t1b[443]
  PIN t1b[444]
    DIRECTION INPUT ;
    USE SIGNAL ;
    PORT
      LAYER M5 ;
        RECT  61.008 0 61.032 0.084 ;
    END
  END t1b[444]
  PIN t1b[445]
    DIRECTION INPUT ;
    USE SIGNAL ;
    PORT
      LAYER M5 ;
        RECT  61.104 0 61.128 0.084 ;
    END
  END t1b[445]
  PIN t1b[446]
    DIRECTION INPUT ;
    USE SIGNAL ;
    PORT
      LAYER M5 ;
        RECT  61.2 0 61.224 0.084 ;
    END
  END t1b[446]
  PIN t1b[447]
    DIRECTION INPUT ;
    USE SIGNAL ;
    PORT
      LAYER M5 ;
        RECT  61.296 0 61.32 0.084 ;
    END
  END t1b[447]
  PIN t1b[448]
    DIRECTION INPUT ;
    USE SIGNAL ;
    PORT
      LAYER M5 ;
        RECT  77.52 0 77.544 0.084 ;
    END
  END t1b[448]
  PIN t1b[449]
    DIRECTION INPUT ;
    USE SIGNAL ;
    PORT
      LAYER M5 ;
        RECT  77.616 0 77.64 0.084 ;
    END
  END t1b[449]
  PIN t1b[44]
    DIRECTION INPUT ;
    USE SIGNAL ;
    PORT
      LAYER M5 ;
        RECT  84.816 0 84.84 0.084 ;
    END
  END t1b[44]
  PIN t1b[450]
    DIRECTION INPUT ;
    USE SIGNAL ;
    PORT
      LAYER M5 ;
        RECT  77.712 0 77.736 0.084 ;
    END
  END t1b[450]
  PIN t1b[451]
    DIRECTION INPUT ;
    USE SIGNAL ;
    PORT
      LAYER M5 ;
        RECT  77.808 0 77.832 0.084 ;
    END
  END t1b[451]
  PIN t1b[452]
    DIRECTION INPUT ;
    USE SIGNAL ;
    PORT
      LAYER M5 ;
        RECT  77.904 0 77.928 0.084 ;
    END
  END t1b[452]
  PIN t1b[453]
    DIRECTION INPUT ;
    USE SIGNAL ;
    PORT
      LAYER M5 ;
        RECT  78 0 78.024 0.084 ;
    END
  END t1b[453]
  PIN t1b[454]
    DIRECTION INPUT ;
    USE SIGNAL ;
    PORT
      LAYER M5 ;
        RECT  78.096 0 78.12 0.084 ;
    END
  END t1b[454]
  PIN t1b[455]
    DIRECTION INPUT ;
    USE SIGNAL ;
    PORT
      LAYER M5 ;
        RECT  78.192 0 78.216 0.084 ;
    END
  END t1b[455]
  PIN t1b[456]
    DIRECTION INPUT ;
    USE SIGNAL ;
    PORT
      LAYER M5 ;
        RECT  78.288 0 78.312 0.084 ;
    END
  END t1b[456]
  PIN t1b[457]
    DIRECTION INPUT ;
    USE SIGNAL ;
    PORT
      LAYER M5 ;
        RECT  78.384 0 78.408 0.084 ;
    END
  END t1b[457]
  PIN t1b[458]
    DIRECTION INPUT ;
    USE SIGNAL ;
    PORT
      LAYER M5 ;
        RECT  78.48 0 78.504 0.084 ;
    END
  END t1b[458]
  PIN t1b[459]
    DIRECTION INPUT ;
    USE SIGNAL ;
    PORT
      LAYER M5 ;
        RECT  78.576 0 78.6 0.084 ;
    END
  END t1b[459]
  PIN t1b[45]
    DIRECTION INPUT ;
    USE SIGNAL ;
    PORT
      LAYER M5 ;
        RECT  84.912 0 84.936 0.084 ;
    END
  END t1b[45]
  PIN t1b[460]
    DIRECTION INPUT ;
    USE SIGNAL ;
    PORT
      LAYER M5 ;
        RECT  78.672 0 78.696 0.084 ;
    END
  END t1b[460]
  PIN t1b[461]
    DIRECTION INPUT ;
    USE SIGNAL ;
    PORT
      LAYER M5 ;
        RECT  78.768 0 78.792 0.084 ;
    END
  END t1b[461]
  PIN t1b[462]
    DIRECTION INPUT ;
    USE SIGNAL ;
    PORT
      LAYER M5 ;
        RECT  78.864 0 78.888 0.084 ;
    END
  END t1b[462]
  PIN t1b[463]
    DIRECTION INPUT ;
    USE SIGNAL ;
    PORT
      LAYER M5 ;
        RECT  78.96 0 78.984 0.084 ;
    END
  END t1b[463]
  PIN t1b[464]
    DIRECTION INPUT ;
    USE SIGNAL ;
    PORT
      LAYER M5 ;
        RECT  79.056 0 79.08 0.084 ;
    END
  END t1b[464]
  PIN t1b[465]
    DIRECTION INPUT ;
    USE SIGNAL ;
    PORT
      LAYER M5 ;
        RECT  79.152 0 79.176 0.084 ;
    END
  END t1b[465]
  PIN t1b[466]
    DIRECTION INPUT ;
    USE SIGNAL ;
    PORT
      LAYER M5 ;
        RECT  79.248 0 79.272 0.084 ;
    END
  END t1b[466]
  PIN t1b[467]
    DIRECTION INPUT ;
    USE SIGNAL ;
    PORT
      LAYER M5 ;
        RECT  79.344 0 79.368 0.084 ;
    END
  END t1b[467]
  PIN t1b[468]
    DIRECTION INPUT ;
    USE SIGNAL ;
    PORT
      LAYER M5 ;
        RECT  79.44 0 79.464 0.084 ;
    END
  END t1b[468]
  PIN t1b[469]
    DIRECTION INPUT ;
    USE SIGNAL ;
    PORT
      LAYER M5 ;
        RECT  79.536 0 79.56 0.084 ;
    END
  END t1b[469]
  PIN t1b[46]
    DIRECTION INPUT ;
    USE SIGNAL ;
    PORT
      LAYER M5 ;
        RECT  85.008 0 85.032 0.084 ;
    END
  END t1b[46]
  PIN t1b[470]
    DIRECTION INPUT ;
    USE SIGNAL ;
    PORT
      LAYER M5 ;
        RECT  79.632 0 79.656 0.084 ;
    END
  END t1b[470]
  PIN t1b[471]
    DIRECTION INPUT ;
    USE SIGNAL ;
    PORT
      LAYER M5 ;
        RECT  79.728 0 79.752 0.084 ;
    END
  END t1b[471]
  PIN t1b[472]
    DIRECTION INPUT ;
    USE SIGNAL ;
    PORT
      LAYER M5 ;
        RECT  79.824 0 79.848 0.084 ;
    END
  END t1b[472]
  PIN t1b[473]
    DIRECTION INPUT ;
    USE SIGNAL ;
    PORT
      LAYER M5 ;
        RECT  79.92 0 79.944 0.084 ;
    END
  END t1b[473]
  PIN t1b[474]
    DIRECTION INPUT ;
    USE SIGNAL ;
    PORT
      LAYER M5 ;
        RECT  80.016 0 80.04 0.084 ;
    END
  END t1b[474]
  PIN t1b[475]
    DIRECTION INPUT ;
    USE SIGNAL ;
    PORT
      LAYER M5 ;
        RECT  80.112 0 80.136 0.084 ;
    END
  END t1b[475]
  PIN t1b[476]
    DIRECTION INPUT ;
    USE SIGNAL ;
    PORT
      LAYER M5 ;
        RECT  80.208 0 80.232 0.084 ;
    END
  END t1b[476]
  PIN t1b[477]
    DIRECTION INPUT ;
    USE SIGNAL ;
    PORT
      LAYER M5 ;
        RECT  80.304 0 80.328 0.084 ;
    END
  END t1b[477]
  PIN t1b[478]
    DIRECTION INPUT ;
    USE SIGNAL ;
    PORT
      LAYER M5 ;
        RECT  80.4 0 80.424 0.084 ;
    END
  END t1b[478]
  PIN t1b[479]
    DIRECTION INPUT ;
    USE SIGNAL ;
    PORT
      LAYER M5 ;
        RECT  80.496 0 80.52 0.084 ;
    END
  END t1b[479]
  PIN t1b[47]
    DIRECTION INPUT ;
    USE SIGNAL ;
    PORT
      LAYER M5 ;
        RECT  85.104 0 85.128 0.084 ;
    END
  END t1b[47]
  PIN t1b[480]
    DIRECTION INPUT ;
    USE SIGNAL ;
    PORT
      LAYER M5 ;
        RECT  80.592 0 80.616 0.084 ;
    END
  END t1b[480]
  PIN t1b[481]
    DIRECTION INPUT ;
    USE SIGNAL ;
    PORT
      LAYER M5 ;
        RECT  80.688 0 80.712 0.084 ;
    END
  END t1b[481]
  PIN t1b[482]
    DIRECTION INPUT ;
    USE SIGNAL ;
    PORT
      LAYER M5 ;
        RECT  80.784 0 80.808 0.084 ;
    END
  END t1b[482]
  PIN t1b[483]
    DIRECTION INPUT ;
    USE SIGNAL ;
    PORT
      LAYER M5 ;
        RECT  80.88 0 80.904 0.084 ;
    END
  END t1b[483]
  PIN t1b[484]
    DIRECTION INPUT ;
    USE SIGNAL ;
    PORT
      LAYER M5 ;
        RECT  80.976 0 81 0.084 ;
    END
  END t1b[484]
  PIN t1b[485]
    DIRECTION INPUT ;
    USE SIGNAL ;
    PORT
      LAYER M5 ;
        RECT  81.072 0 81.096 0.084 ;
    END
  END t1b[485]
  PIN t1b[486]
    DIRECTION INPUT ;
    USE SIGNAL ;
    PORT
      LAYER M5 ;
        RECT  81.168 0 81.192 0.084 ;
    END
  END t1b[486]
  PIN t1b[487]
    DIRECTION INPUT ;
    USE SIGNAL ;
    PORT
      LAYER M5 ;
        RECT  81.264 0 81.288 0.084 ;
    END
  END t1b[487]
  PIN t1b[488]
    DIRECTION INPUT ;
    USE SIGNAL ;
    PORT
      LAYER M5 ;
        RECT  81.36 0 81.384 0.084 ;
    END
  END t1b[488]
  PIN t1b[489]
    DIRECTION INPUT ;
    USE SIGNAL ;
    PORT
      LAYER M5 ;
        RECT  81.456 0 81.48 0.084 ;
    END
  END t1b[489]
  PIN t1b[48]
    DIRECTION INPUT ;
    USE SIGNAL ;
    PORT
      LAYER M5 ;
        RECT  85.2 0 85.224 0.084 ;
    END
  END t1b[48]
  PIN t1b[490]
    DIRECTION INPUT ;
    USE SIGNAL ;
    PORT
      LAYER M5 ;
        RECT  81.552 0 81.576 0.084 ;
    END
  END t1b[490]
  PIN t1b[491]
    DIRECTION INPUT ;
    USE SIGNAL ;
    PORT
      LAYER M5 ;
        RECT  81.648 0 81.672 0.084 ;
    END
  END t1b[491]
  PIN t1b[492]
    DIRECTION INPUT ;
    USE SIGNAL ;
    PORT
      LAYER M5 ;
        RECT  81.744 0 81.768 0.084 ;
    END
  END t1b[492]
  PIN t1b[493]
    DIRECTION INPUT ;
    USE SIGNAL ;
    PORT
      LAYER M5 ;
        RECT  81.84 0 81.864 0.084 ;
    END
  END t1b[493]
  PIN t1b[494]
    DIRECTION INPUT ;
    USE SIGNAL ;
    PORT
      LAYER M5 ;
        RECT  81.936 0 81.96 0.084 ;
    END
  END t1b[494]
  PIN t1b[495]
    DIRECTION INPUT ;
    USE SIGNAL ;
    PORT
      LAYER M5 ;
        RECT  82.032 0 82.056 0.084 ;
    END
  END t1b[495]
  PIN t1b[496]
    DIRECTION INPUT ;
    USE SIGNAL ;
    PORT
      LAYER M5 ;
        RECT  82.128 0 82.152 0.084 ;
    END
  END t1b[496]
  PIN t1b[497]
    DIRECTION INPUT ;
    USE SIGNAL ;
    PORT
      LAYER M5 ;
        RECT  82.224 0 82.248 0.084 ;
    END
  END t1b[497]
  PIN t1b[498]
    DIRECTION INPUT ;
    USE SIGNAL ;
    PORT
      LAYER M5 ;
        RECT  82.32 0 82.344 0.084 ;
    END
  END t1b[498]
  PIN t1b[499]
    DIRECTION INPUT ;
    USE SIGNAL ;
    PORT
      LAYER M5 ;
        RECT  82.416 0 82.44 0.084 ;
    END
  END t1b[499]
  PIN t1b[49]
    DIRECTION INPUT ;
    USE SIGNAL ;
    PORT
      LAYER M5 ;
        RECT  85.296 0 85.32 0.084 ;
    END
  END t1b[49]
  PIN t1b[4]
    DIRECTION INPUT ;
    USE SIGNAL ;
    PORT
      LAYER M5 ;
        RECT  48.72 0 48.744 0.084 ;
    END
  END t1b[4]
  PIN t1b[500]
    DIRECTION INPUT ;
    USE SIGNAL ;
    PORT
      LAYER M5 ;
        RECT  82.512 0 82.536 0.084 ;
    END
  END t1b[500]
  PIN t1b[501]
    DIRECTION INPUT ;
    USE SIGNAL ;
    PORT
      LAYER M5 ;
        RECT  82.608 0 82.632 0.084 ;
    END
  END t1b[501]
  PIN t1b[502]
    DIRECTION INPUT ;
    USE SIGNAL ;
    PORT
      LAYER M5 ;
        RECT  82.704 0 82.728 0.084 ;
    END
  END t1b[502]
  PIN t1b[503]
    DIRECTION INPUT ;
    USE SIGNAL ;
    PORT
      LAYER M5 ;
        RECT  82.8 0 82.824 0.084 ;
    END
  END t1b[503]
  PIN t1b[504]
    DIRECTION INPUT ;
    USE SIGNAL ;
    PORT
      LAYER M5 ;
        RECT  82.896 0 82.92 0.084 ;
    END
  END t1b[504]
  PIN t1b[505]
    DIRECTION INPUT ;
    USE SIGNAL ;
    PORT
      LAYER M5 ;
        RECT  82.992 0 83.016 0.084 ;
    END
  END t1b[505]
  PIN t1b[506]
    DIRECTION INPUT ;
    USE SIGNAL ;
    PORT
      LAYER M5 ;
        RECT  83.088 0 83.112 0.084 ;
    END
  END t1b[506]
  PIN t1b[507]
    DIRECTION INPUT ;
    USE SIGNAL ;
    PORT
      LAYER M5 ;
        RECT  83.184 0 83.208 0.084 ;
    END
  END t1b[507]
  PIN t1b[508]
    DIRECTION INPUT ;
    USE SIGNAL ;
    PORT
      LAYER M5 ;
        RECT  83.28 0 83.304 0.084 ;
    END
  END t1b[508]
  PIN t1b[509]
    DIRECTION INPUT ;
    USE SIGNAL ;
    PORT
      LAYER M5 ;
        RECT  83.376 0 83.4 0.084 ;
    END
  END t1b[509]
  PIN t1b[50]
    DIRECTION INPUT ;
    USE SIGNAL ;
    PORT
      LAYER M5 ;
        RECT  85.392 0 85.416 0.084 ;
    END
  END t1b[50]
  PIN t1b[510]
    DIRECTION INPUT ;
    USE SIGNAL ;
    PORT
      LAYER M5 ;
        RECT  83.472 0 83.496 0.084 ;
    END
  END t1b[510]
  PIN t1b[511]
    DIRECTION INPUT ;
    USE SIGNAL ;
    PORT
      LAYER M5 ;
        RECT  83.568 0 83.592 0.084 ;
    END
  END t1b[511]
  PIN t1b[51]
    DIRECTION INPUT ;
    USE SIGNAL ;
    PORT
      LAYER M5 ;
        RECT  85.488 0 85.512 0.084 ;
    END
  END t1b[51]
  PIN t1b[52]
    DIRECTION INPUT ;
    USE SIGNAL ;
    PORT
      LAYER M5 ;
        RECT  85.584 0 85.608 0.084 ;
    END
  END t1b[52]
  PIN t1b[53]
    DIRECTION INPUT ;
    USE SIGNAL ;
    PORT
      LAYER M5 ;
        RECT  85.68 0 85.704 0.084 ;
    END
  END t1b[53]
  PIN t1b[54]
    DIRECTION INPUT ;
    USE SIGNAL ;
    PORT
      LAYER M5 ;
        RECT  85.776 0 85.8 0.084 ;
    END
  END t1b[54]
  PIN t1b[55]
    DIRECTION INPUT ;
    USE SIGNAL ;
    PORT
      LAYER M5 ;
        RECT  85.872 0 85.896 0.084 ;
    END
  END t1b[55]
  PIN t1b[56]
    DIRECTION INPUT ;
    USE SIGNAL ;
    PORT
      LAYER M5 ;
        RECT  85.968 0 85.992 0.084 ;
    END
  END t1b[56]
  PIN t1b[57]
    DIRECTION INPUT ;
    USE SIGNAL ;
    PORT
      LAYER M5 ;
        RECT  86.064 0 86.088 0.084 ;
    END
  END t1b[57]
  PIN t1b[58]
    DIRECTION INPUT ;
    USE SIGNAL ;
    PORT
      LAYER M5 ;
        RECT  86.16 0 86.184 0.084 ;
    END
  END t1b[58]
  PIN t1b[59]
    DIRECTION INPUT ;
    USE SIGNAL ;
    PORT
      LAYER M5 ;
        RECT  86.256 0 86.28 0.084 ;
    END
  END t1b[59]
  PIN t1b[5]
    DIRECTION INPUT ;
    USE SIGNAL ;
    PORT
      LAYER M5 ;
        RECT  48.816 0 48.84 0.084 ;
    END
  END t1b[5]
  PIN t1b[60]
    DIRECTION INPUT ;
    USE SIGNAL ;
    PORT
      LAYER M5 ;
        RECT  86.352 0 86.376 0.084 ;
    END
  END t1b[60]
  PIN t1b[61]
    DIRECTION INPUT ;
    USE SIGNAL ;
    PORT
      LAYER M5 ;
        RECT  86.448 0 86.472 0.084 ;
    END
  END t1b[61]
  PIN t1b[62]
    DIRECTION INPUT ;
    USE SIGNAL ;
    PORT
      LAYER M5 ;
        RECT  86.544 0 86.568 0.084 ;
    END
  END t1b[62]
  PIN t1b[63]
    DIRECTION INPUT ;
    USE SIGNAL ;
    PORT
      LAYER M5 ;
        RECT  86.64 0 86.664 0.084 ;
    END
  END t1b[63]
  PIN t1b[64]
    DIRECTION INPUT ;
    USE SIGNAL ;
    PORT
      LAYER M5 ;
        RECT  54.48 0 54.504 0.084 ;
    END
  END t1b[64]
  PIN t1b[65]
    DIRECTION INPUT ;
    USE SIGNAL ;
    PORT
      LAYER M5 ;
        RECT  54.576 0 54.6 0.084 ;
    END
  END t1b[65]
  PIN t1b[66]
    DIRECTION INPUT ;
    USE SIGNAL ;
    PORT
      LAYER M5 ;
        RECT  54.672 0 54.696 0.084 ;
    END
  END t1b[66]
  PIN t1b[67]
    DIRECTION INPUT ;
    USE SIGNAL ;
    PORT
      LAYER M5 ;
        RECT  54.768 0 54.792 0.084 ;
    END
  END t1b[67]
  PIN t1b[68]
    DIRECTION INPUT ;
    USE SIGNAL ;
    PORT
      LAYER M5 ;
        RECT  54.864 0 54.888 0.084 ;
    END
  END t1b[68]
  PIN t1b[69]
    DIRECTION INPUT ;
    USE SIGNAL ;
    PORT
      LAYER M5 ;
        RECT  54.96 0 54.984 0.084 ;
    END
  END t1b[69]
  PIN t1b[6]
    DIRECTION INPUT ;
    USE SIGNAL ;
    PORT
      LAYER M5 ;
        RECT  48.912 0 48.936 0.084 ;
    END
  END t1b[6]
  PIN t1b[70]
    DIRECTION INPUT ;
    USE SIGNAL ;
    PORT
      LAYER M5 ;
        RECT  55.056 0 55.08 0.084 ;
    END
  END t1b[70]
  PIN t1b[71]
    DIRECTION INPUT ;
    USE SIGNAL ;
    PORT
      LAYER M5 ;
        RECT  55.152 0 55.176 0.084 ;
    END
  END t1b[71]
  PIN t1b[72]
    DIRECTION INPUT ;
    USE SIGNAL ;
    PORT
      LAYER M5 ;
        RECT  55.248 0 55.272 0.084 ;
    END
  END t1b[72]
  PIN t1b[73]
    DIRECTION INPUT ;
    USE SIGNAL ;
    PORT
      LAYER M5 ;
        RECT  55.344 0 55.368 0.084 ;
    END
  END t1b[73]
  PIN t1b[74]
    DIRECTION INPUT ;
    USE SIGNAL ;
    PORT
      LAYER M5 ;
        RECT  55.44 0 55.464 0.084 ;
    END
  END t1b[74]
  PIN t1b[75]
    DIRECTION INPUT ;
    USE SIGNAL ;
    PORT
      LAYER M5 ;
        RECT  55.536 0 55.56 0.084 ;
    END
  END t1b[75]
  PIN t1b[76]
    DIRECTION INPUT ;
    USE SIGNAL ;
    PORT
      LAYER M5 ;
        RECT  55.632 0 55.656 0.084 ;
    END
  END t1b[76]
  PIN t1b[77]
    DIRECTION INPUT ;
    USE SIGNAL ;
    PORT
      LAYER M5 ;
        RECT  55.728 0 55.752 0.084 ;
    END
  END t1b[77]
  PIN t1b[78]
    DIRECTION INPUT ;
    USE SIGNAL ;
    PORT
      LAYER M5 ;
        RECT  55.824 0 55.848 0.084 ;
    END
  END t1b[78]
  PIN t1b[79]
    DIRECTION INPUT ;
    USE SIGNAL ;
    PORT
      LAYER M5 ;
        RECT  55.92 0 55.944 0.084 ;
    END
  END t1b[79]
  PIN t1b[7]
    DIRECTION INPUT ;
    USE SIGNAL ;
    PORT
      LAYER M5 ;
        RECT  49.008 0 49.032 0.084 ;
    END
  END t1b[7]
  PIN t1b[80]
    DIRECTION INPUT ;
    USE SIGNAL ;
    PORT
      LAYER M5 ;
        RECT  56.016 0 56.04 0.084 ;
    END
  END t1b[80]
  PIN t1b[81]
    DIRECTION INPUT ;
    USE SIGNAL ;
    PORT
      LAYER M5 ;
        RECT  56.112 0 56.136 0.084 ;
    END
  END t1b[81]
  PIN t1b[82]
    DIRECTION INPUT ;
    USE SIGNAL ;
    PORT
      LAYER M5 ;
        RECT  56.208 0 56.232 0.084 ;
    END
  END t1b[82]
  PIN t1b[83]
    DIRECTION INPUT ;
    USE SIGNAL ;
    PORT
      LAYER M5 ;
        RECT  56.304 0 56.328 0.084 ;
    END
  END t1b[83]
  PIN t1b[84]
    DIRECTION INPUT ;
    USE SIGNAL ;
    PORT
      LAYER M5 ;
        RECT  56.4 0 56.424 0.084 ;
    END
  END t1b[84]
  PIN t1b[85]
    DIRECTION INPUT ;
    USE SIGNAL ;
    PORT
      LAYER M5 ;
        RECT  56.496 0 56.52 0.084 ;
    END
  END t1b[85]
  PIN t1b[86]
    DIRECTION INPUT ;
    USE SIGNAL ;
    PORT
      LAYER M5 ;
        RECT  56.592 0 56.616 0.084 ;
    END
  END t1b[86]
  PIN t1b[87]
    DIRECTION INPUT ;
    USE SIGNAL ;
    PORT
      LAYER M5 ;
        RECT  56.688 0 56.712 0.084 ;
    END
  END t1b[87]
  PIN t1b[88]
    DIRECTION INPUT ;
    USE SIGNAL ;
    PORT
      LAYER M5 ;
        RECT  56.784 0 56.808 0.084 ;
    END
  END t1b[88]
  PIN t1b[89]
    DIRECTION INPUT ;
    USE SIGNAL ;
    PORT
      LAYER M5 ;
        RECT  56.88 0 56.904 0.084 ;
    END
  END t1b[89]
  PIN t1b[8]
    DIRECTION INPUT ;
    USE SIGNAL ;
    PORT
      LAYER M5 ;
        RECT  49.104 0 49.128 0.084 ;
    END
  END t1b[8]
  PIN t1b[90]
    DIRECTION INPUT ;
    USE SIGNAL ;
    PORT
      LAYER M5 ;
        RECT  56.976 0 57 0.084 ;
    END
  END t1b[90]
  PIN t1b[91]
    DIRECTION INPUT ;
    USE SIGNAL ;
    PORT
      LAYER M5 ;
        RECT  57.072 0 57.096 0.084 ;
    END
  END t1b[91]
  PIN t1b[92]
    DIRECTION INPUT ;
    USE SIGNAL ;
    PORT
      LAYER M5 ;
        RECT  57.168 0 57.192 0.084 ;
    END
  END t1b[92]
  PIN t1b[93]
    DIRECTION INPUT ;
    USE SIGNAL ;
    PORT
      LAYER M5 ;
        RECT  57.264 0 57.288 0.084 ;
    END
  END t1b[93]
  PIN t1b[94]
    DIRECTION INPUT ;
    USE SIGNAL ;
    PORT
      LAYER M5 ;
        RECT  57.36 0 57.384 0.084 ;
    END
  END t1b[94]
  PIN t1b[95]
    DIRECTION INPUT ;
    USE SIGNAL ;
    PORT
      LAYER M5 ;
        RECT  57.456 0 57.48 0.084 ;
    END
  END t1b[95]
  PIN t1b[96]
    DIRECTION INPUT ;
    USE SIGNAL ;
    PORT
      LAYER M5 ;
        RECT  42.192 0 42.216 0.084 ;
    END
  END t1b[96]
  PIN t1b[97]
    DIRECTION INPUT ;
    USE SIGNAL ;
    PORT
      LAYER M5 ;
        RECT  42.288 0 42.312 0.084 ;
    END
  END t1b[97]
  PIN t1b[98]
    DIRECTION INPUT ;
    USE SIGNAL ;
    PORT
      LAYER M5 ;
        RECT  42.384 0 42.408 0.084 ;
    END
  END t1b[98]
  PIN t1b[99]
    DIRECTION INPUT ;
    USE SIGNAL ;
    PORT
      LAYER M5 ;
        RECT  42.48 0 42.504 0.084 ;
    END
  END t1b[99]
  PIN t1b[9]
    DIRECTION INPUT ;
    USE SIGNAL ;
    PORT
      LAYER M5 ;
        RECT  49.2 0 49.224 0.084 ;
    END
  END t1b[9]
  PIN VDD
    DIRECTION INOUT ;
    USE POWER ;
    PORT
      LAYER M5 ;
        RECT  110.592 2.151 110.712 23.769 ;
        RECT  105.192 2.151 105.312 23.769 ;
        RECT  99.792 2.151 99.912 23.769 ;
        RECT  94.392 2.151 94.512 23.769 ;
        RECT  88.992 2.151 89.112 23.769 ;
        RECT  83.592 2.151 83.712 23.769 ;
        RECT  78.192 2.151 78.312 23.769 ;
        RECT  72.792 2.151 72.912 23.769 ;
        RECT  67.392 2.151 67.512 23.769 ;
        RECT  61.992 2.151 62.112 23.769 ;
        RECT  56.592 2.151 56.712 23.769 ;
        RECT  51.192 2.151 51.312 23.769 ;
        RECT  45.792 2.151 45.912 23.769 ;
        RECT  40.392 2.151 40.512 23.769 ;
        RECT  34.992 2.151 35.112 23.769 ;
        RECT  29.592 2.151 29.712 23.769 ;
        RECT  24.192 2.151 24.312 23.769 ;
        RECT  18.792 2.151 18.912 23.769 ;
        RECT  13.392 2.151 13.512 23.769 ;
        RECT  7.992 2.151 8.112 23.769 ;
        RECT  2.592 2.151 2.712 23.769 ;
    END
  END VDD
  PIN VSS
    DIRECTION INOUT ;
    USE GROUND ;
    PORT
      LAYER M5 ;
        RECT  110.4 2.137 110.52 23.783 ;
        RECT  105 2.137 105.12 23.783 ;
        RECT  99.6 2.137 99.72 23.783 ;
        RECT  94.2 2.137 94.32 23.783 ;
        RECT  88.8 2.137 88.92 23.783 ;
        RECT  83.4 2.137 83.52 23.783 ;
        RECT  78 2.137 78.12 23.783 ;
        RECT  72.6 2.137 72.72 23.783 ;
        RECT  67.2 2.137 67.32 23.783 ;
        RECT  61.8 2.137 61.92 23.783 ;
        RECT  56.4 2.137 56.52 23.783 ;
        RECT  51 2.137 51.12 23.783 ;
        RECT  45.6 2.137 45.72 23.783 ;
        RECT  40.2 2.137 40.32 23.783 ;
        RECT  34.8 2.137 34.92 23.783 ;
        RECT  29.4 2.137 29.52 23.783 ;
        RECT  24 2.137 24.12 23.783 ;
        RECT  18.6 2.137 18.72 23.783 ;
        RECT  13.2 2.137 13.32 23.783 ;
        RECT  7.8 2.137 7.92 23.783 ;
        RECT  2.4 2.137 2.52 23.783 ;
    END
  END VSS
  # OT_OBS_CLOSED layer=M5 d_um=1.536 added=203
  OBS
    LAYER RVTN ;
     RECT  2.16 2.16 114.48 2.295 ;
     RECT  2.16 2.565 114.48 2.835 ;
     RECT  2.16 3.105 114.48 3.375 ;
     RECT  2.16 3.645 114.48 3.915 ;
     RECT  2.16 4.185 114.48 4.455 ;
     RECT  2.16 4.725 114.48 4.995 ;
     RECT  2.16 5.265 114.48 5.535 ;
     RECT  2.16 5.805 114.48 6.075 ;
     RECT  2.16 6.345 114.48 6.615 ;
     RECT  2.16 6.885 114.48 7.155 ;
     RECT  2.16 7.425 114.48 7.695 ;
     RECT  2.16 7.965 114.48 8.235 ;
     RECT  2.16 8.505 114.48 8.775 ;
     RECT  2.16 9.045 114.48 9.315 ;
     RECT  2.16 9.585 114.48 9.855 ;
     RECT  2.16 10.125 114.48 10.395 ;
     RECT  2.16 10.665 114.48 10.935 ;
     RECT  2.16 11.205 114.48 11.475 ;
     RECT  2.16 11.745 114.48 12.015 ;
     RECT  2.16 12.285 114.48 12.555 ;
     RECT  2.16 12.825 114.48 13.095 ;
     RECT  2.16 13.365 114.48 13.635 ;
     RECT  2.16 13.905 114.48 14.175 ;
     RECT  2.16 14.445 114.48 14.715 ;
     RECT  2.16 14.985 114.48 15.255 ;
     RECT  2.16 15.525 114.48 15.795 ;
     RECT  2.16 16.065 114.48 16.335 ;
     RECT  2.16 16.605 114.48 16.875 ;
     RECT  2.16 17.145 114.48 17.415 ;
     RECT  2.16 17.685 114.48 17.955 ;
     RECT  2.16 18.225 114.48 18.495 ;
     RECT  2.16 18.765 114.48 19.035 ;
     RECT  2.16 19.305 114.48 19.575 ;
     RECT  2.16 19.845 114.48 20.115 ;
     RECT  2.16 20.385 114.48 20.655 ;
     RECT  2.16 20.925 114.48 21.195 ;
     RECT  2.16 21.465 114.48 21.735 ;
     RECT  2.16 22.005 114.48 22.275 ;
     RECT  2.16 22.545 114.48 22.815 ;
     RECT  2.16 23.085 114.48 23.355 ;
     RECT  2.16 23.625 114.48 23.76 ;
    LAYER RVTP ;
     RECT  2.16 2.295 114.48 2.565 ;
     RECT  2.16 2.835 114.48 3.105 ;
     RECT  2.16 3.375 114.48 3.645 ;
     RECT  2.16 3.915 114.48 4.185 ;
     RECT  2.16 4.455 114.48 4.725 ;
     RECT  2.16 4.995 114.48 5.265 ;
     RECT  2.16 5.535 114.48 5.805 ;
     RECT  2.16 6.075 114.48 6.345 ;
     RECT  2.16 6.615 114.48 6.885 ;
     RECT  2.16 7.155 114.48 7.425 ;
     RECT  2.16 7.695 114.48 7.965 ;
     RECT  2.16 8.235 114.48 8.505 ;
     RECT  2.16 8.775 114.48 9.045 ;
     RECT  2.16 9.315 114.48 9.585 ;
     RECT  2.16 9.855 114.48 10.125 ;
     RECT  2.16 10.395 114.48 10.665 ;
     RECT  2.16 10.935 114.48 11.205 ;
     RECT  2.16 11.475 114.48 11.745 ;
     RECT  2.16 12.015 114.48 12.285 ;
     RECT  2.16 12.555 114.48 12.825 ;
     RECT  2.16 13.095 114.48 13.365 ;
     RECT  2.16 13.635 114.48 13.905 ;
     RECT  2.16 14.175 114.48 14.445 ;
     RECT  2.16 14.715 114.48 14.985 ;
     RECT  2.16 15.255 114.48 15.525 ;
     RECT  2.16 15.795 114.48 16.065 ;
     RECT  2.16 16.335 114.48 16.605 ;
     RECT  2.16 16.875 114.48 17.145 ;
     RECT  2.16 17.415 114.48 17.685 ;
     RECT  2.16 17.955 114.48 18.225 ;
     RECT  2.16 18.495 114.48 18.765 ;
     RECT  2.16 19.035 114.48 19.305 ;
     RECT  2.16 19.575 114.48 19.845 ;
     RECT  2.16 20.115 114.48 20.385 ;
     RECT  2.16 20.655 114.48 20.925 ;
     RECT  2.16 21.195 114.48 21.465 ;
     RECT  2.16 21.735 114.48 22.005 ;
     RECT  2.16 22.275 114.48 22.545 ;
     RECT  2.16 22.815 114.48 23.085 ;
     RECT  2.16 23.355 114.48 23.625 ;
    LAYER M1 ;
     RECT  2.16 2.151 114.48 23.769 ;
    LAYER M2 ;
     RECT  2.16 2.151 22.819 23.769 ;
     RECT  22.819 2.106 23.071 23.769 ;
     RECT  23.071 1.881 24.115 23.769 ;
     RECT  24.115 1.881 24.215 23.85 ;
     RECT  24.215 1.881 29.623 23.769 ;
     RECT  29.623 1.881 30.047 23.814 ;
     RECT  30.047 1.881 32.431 23.769 ;
     RECT  32.431 1.728 35.915 23.769 ;
     RECT  35.915 1.764 38.587 23.769 ;
     RECT  38.587 1.728 39.875 23.769 ;
     RECT  39.875 1.764 41.639 23.769 ;
     RECT  41.639 1.8 41.711 23.769 ;
     RECT  41.711 1.836 42.583 23.769 ;
     RECT  42.583 1.8 42.835 23.769 ;
     RECT  45.211 25.056 45.347 25.074 ;
     RECT  42.835 1.764 47.407 23.769 ;
     RECT  47.407 1.764 47.867 23.814 ;
     RECT  47.443 25.056 48.299 25.074 ;
     RECT  47.867 1.764 48.443 23.769 ;
     RECT  48.443 2.034 50.207 23.769 ;
     RECT  50.207 2.07 50.927 23.769 ;
     RECT  50.927 2.106 50.999 23.769 ;
     RECT  53.923 25.056 54.095 25.074 ;
     RECT  50.999 2.151 57.595 23.769 ;
     RECT  57.595 2.106 58.739 23.769 ;
     RECT  58.739 2.151 64.003 23.769 ;
     RECT  64.543 25.056 64.751 25.074 ;
     RECT  64.003 2.106 64.859 23.769 ;
     RECT  64.859 2.151 65.839 23.769 ;
     RECT  65.839 2.106 66.299 23.769 ;
     RECT  66.299 2.151 68.971 23.769 ;
     RECT  68.971 2.106 70.699 23.769 ;
     RECT  72.211 25.056 72.311 25.074 ;
     RECT  70.699 2.07 72.427 23.769 ;
     RECT  72.427 2.034 74.515 23.769 ;
     RECT  74.515 1.998 74.623 23.769 ;
     RECT  74.623 1.998 74.903 23.814 ;
     RECT  74.903 1.998 75.263 23.769 ;
     RECT  75.263 2.034 78.359 23.769 ;
     RECT  78.359 2.07 79.763 23.769 ;
     RECT  79.763 2.106 80.807 23.769 ;
     RECT  80.807 2.151 80.815 23.769 ;
     RECT  80.815 2.151 80.851 23.886 ;
     RECT  80.851 2.151 81.535 23.922 ;
     RECT  81.535 2.034 81.563 23.922 ;
     RECT  81.563 2.034 81.743 23.886 ;
     RECT  81.743 2.034 82.535 23.814 ;
     RECT  82.535 2.034 83.047 23.769 ;
     RECT  83.047 1.926 83.659 23.769 ;
     RECT  83.659 1.926 83.983 23.814 ;
     RECT  83.983 1.926 85.523 23.886 ;
     RECT  85.387 25.056 86.143 25.074 ;
     RECT  86.143 24.984 86.243 25.074 ;
     RECT  85.523 1.926 86.711 23.769 ;
     RECT  86.711 2.034 89.735 23.769 ;
     RECT  90.391 25.056 90.491 25.074 ;
     RECT  92.191 25.056 92.291 25.074 ;
     RECT  89.735 2.07 95.027 23.769 ;
     RECT  95.027 2.106 98.851 23.769 ;
     RECT  98.851 2.106 99.211 23.814 ;
     RECT  99.211 2.106 100.355 23.886 ;
     RECT  100.471 24.606 100.571 24.624 ;
     RECT  100.355 2.106 100.607 23.769 ;
     RECT  100.607 2.151 101.155 23.769 ;
     RECT  101.155 2.151 102.047 23.814 ;
     RECT  102.047 2.151 114.48 23.769 ;
    LAYER M3 ;
     RECT  35.352 0.043 35.478 0.091 ;
     RECT  43.128 0.043 43.146 0.091 ;
     RECT  48.996 0.043 49.014 0.091 ;
     RECT  46.728 0.091 46.746 0.139 ;
     RECT  41.328 0.043 41.346 0.173 ;
     RECT  71.676 0.043 71.694 0.173 ;
     RECT  35.352 0.091 35.91 0.187 ;
     RECT  41.76 0.187 42.066 0.283 ;
     RECT  35.244 0.187 35.91 0.317 ;
     RECT  83.376 0.091 83.394 0.317 ;
     RECT  32.472 0.235 32.49 0.379 ;
     RECT  33.552 0.331 33.57 0.379 ;
     RECT  39.6 0.091 39.618 0.475 ;
     RECT  46.62 0.139 46.746 0.475 ;
     RECT  47.7 0.139 47.718 0.475 ;
     RECT  35.46 0.317 35.91 0.523 ;
     RECT  39.168 0.475 39.618 0.523 ;
     RECT  40.536 0.091 40.554 0.523 ;
     RECT  41.76 0.283 42.138 0.523 ;
     RECT  42.984 0.091 43.866 0.523 ;
     RECT  46.62 0.475 47.718 0.523 ;
     RECT  48.996 0.091 49.59 0.523 ;
     RECT  50.616 0.091 51.318 0.523 ;
     RECT  35.46 0.523 36.594 0.571 ;
     RECT  45.036 0.523 45.054 0.571 ;
     RECT  46.62 0.523 49.59 0.571 ;
     RECT  50.616 0.523 51.642 0.571 ;
     RECT  41.76 0.523 43.866 0.619 ;
     RECT  44.604 0.571 45.414 0.619 ;
     RECT  58.284 0.571 58.734 0.619 ;
     RECT  46.62 0.571 51.642 0.859 ;
     RECT  41.76 0.619 45.414 1.003 ;
     RECT  35.46 0.571 37.17 1.099 ;
     RECT  38.16 0.091 38.178 1.099 ;
     RECT  39.168 0.523 40.554 1.099 ;
     RECT  41.724 1.003 45.414 1.099 ;
     RECT  46.188 0.859 51.642 1.099 ;
     RECT  68.328 0.091 68.346 1.099 ;
     RECT  86.076 0.571 86.094 1.099 ;
     RECT  41.724 1.099 51.642 1.147 ;
     RECT  58.284 0.619 58.806 1.147 ;
     RECT  35.46 1.099 37.206 1.195 ;
     RECT  32.472 0.379 33.57 1.387 ;
     RECT  34.488 0.139 34.506 1.387 ;
     RECT  77.148 1.387 77.166 1.435 ;
     RECT  79.092 0.043 79.11 1.483 ;
     RECT  77.004 1.435 77.166 1.531 ;
     RECT  79.092 1.483 79.218 1.579 ;
     RECT  72.936 1.579 72.954 1.627 ;
     RECT  39.168 1.099 40.95 1.675 ;
     RECT  41.724 1.147 52.146 1.675 ;
     RECT  72.648 1.627 72.954 1.675 ;
     RECT  32.472 1.387 34.506 1.723 ;
     RECT  38.052 1.099 38.178 1.723 ;
     RECT  39.168 1.675 52.146 1.723 ;
     RECT  53.136 0.571 54.306 1.723 ;
     RECT  55.332 1.627 55.35 1.723 ;
     RECT  58.284 1.147 59.886 1.723 ;
     RECT  66.564 1.675 66.582 1.723 ;
     RECT  67.788 1.099 68.346 1.723 ;
     RECT  72.576 1.675 73.026 1.723 ;
     RECT  74.484 0.091 74.502 1.723 ;
     RECT  76.428 1.531 77.166 1.723 ;
     RECT  78.84 1.579 79.218 1.723 ;
     RECT  84.384 0.571 84.402 1.723 ;
     RECT  86.076 1.099 86.778 1.723 ;
     RECT  32.436 1.723 34.506 1.759 ;
     RECT  35.424 1.195 37.206 1.759 ;
     RECT  58.284 1.723 62.946 1.771 ;
     RECT  64.224 1.723 64.242 1.771 ;
     RECT  65.376 1.723 68.346 1.771 ;
     RECT  69.192 1.723 69.21 1.771 ;
     RECT  71.208 1.723 71.226 1.771 ;
     RECT  72.576 1.723 75.582 1.771 ;
     RECT  76.428 1.723 77.634 1.771 ;
     RECT  78.84 1.723 80.118 1.771 ;
     RECT  81.792 1.723 82.278 1.771 ;
     RECT  83.736 1.723 86.778 1.771 ;
     RECT  58.248 1.771 68.346 1.819 ;
     RECT  69.192 1.771 69.534 1.819 ;
     RECT  76.356 1.771 77.85 1.819 ;
     RECT  78.624 1.771 80.118 1.819 ;
     RECT  70.596 1.771 71.226 1.867 ;
     RECT  71.964 1.771 75.582 1.867 ;
     RECT  76.356 1.819 80.19 1.867 ;
     RECT  81.504 1.771 86.778 1.867 ;
     RECT  71.964 1.867 80.19 1.915 ;
     RECT  81.252 1.867 86.778 1.915 ;
     RECT  24.768 0.091 24.786 1.921 ;
     RECT  32.436 1.759 37.206 1.993 ;
     RECT  38.052 1.723 57.33 1.993 ;
     RECT  31.68 1.993 31.698 2.011 ;
     RECT  70.56 1.867 71.226 2.011 ;
     RECT  23.904 0.043 23.922 2.029 ;
     RECT  24.768 1.921 25.038 2.029 ;
     RECT  26.856 1.957 26.874 2.059 ;
     RECT  31.14 2.011 31.698 2.059 ;
     RECT  70.344 2.011 71.226 2.059 ;
     RECT  71.964 1.915 86.778 2.059 ;
     RECT  26.784 2.059 26.874 2.065 ;
     RECT  23.076 1.876 23.094 2.101 ;
     RECT  23.832 2.029 23.922 2.101 ;
     RECT  30.564 2.059 31.698 2.101 ;
     RECT  32.436 1.993 57.33 2.101 ;
     RECT  58.248 1.819 69.534 2.101 ;
     RECT  70.344 2.059 86.778 2.101 ;
     RECT  23.832 2.101 23.994 2.143 ;
     RECT  24.768 2.029 25.794 2.143 ;
     RECT  29.052 0.187 29.07 2.143 ;
     RECT  95.004 2.065 95.022 2.143 ;
     RECT  22.824 2.101 23.094 2.191 ;
     RECT  23.832 2.143 25.794 2.191 ;
     RECT  26.604 2.065 26.874 2.191 ;
     RECT  22.608 2.191 23.094 2.255 ;
     RECT  22.608 2.255 22.842 2.291 ;
     RECT  23.832 2.191 26.874 2.335 ;
     RECT  30.528 2.101 31.698 2.371 ;
     RECT  32.436 2.101 86.778 2.371 ;
     RECT  2.415 2.143 2.505 2.413 ;
     RECT  7.815 2.143 7.905 2.413 ;
     RECT  13.215 2.143 13.305 2.413 ;
     RECT  18.615 2.143 18.705 2.413 ;
     RECT  29.052 2.143 29.505 2.413 ;
     RECT  88.815 2.143 88.905 2.413 ;
     RECT  89.712 2.029 89.73 2.413 ;
     RECT  99.615 2.143 99.705 2.413 ;
     RECT  100.584 2.101 100.602 2.413 ;
     RECT  105.015 2.143 105.105 2.413 ;
     RECT  110.415 2.143 110.505 2.413 ;
     RECT  94.215 2.143 95.022 2.533 ;
     RECT  30.528 2.371 86.778 2.569 ;
     RECT  94.215 2.533 95.562 2.605 ;
     RECT  93.816 2.605 95.562 2.641 ;
     RECT  23.832 2.335 27.234 2.795 ;
     RECT  29.052 2.413 29.697 2.803 ;
     RECT  25.632 2.795 27.234 2.867 ;
     RECT  88.815 2.413 89.73 3.109 ;
     RECT  30.528 2.569 86.886 3.145 ;
     RECT  88.815 3.109 89.838 3.145 ;
     RECT  93.816 2.641 95.706 3.145 ;
     RECT  22.608 2.291 22.806 3.181 ;
     RECT  23.832 2.795 24.894 3.181 ;
     RECT  30.528 3.145 87.57 3.379 ;
     RECT  98.568 3.181 98.586 3.415 ;
     RECT  28.764 2.803 29.697 3.649 ;
     RECT  98.352 3.415 98.586 3.649 ;
     RECT  88.815 3.145 89.91 3.685 ;
     RECT  96.588 2.911 96.606 3.721 ;
     RECT  97.74 3.649 98.586 3.721 ;
     RECT  93.168 3.145 95.706 3.883 ;
     RECT  30.528 3.379 87.894 3.919 ;
     RECT  88.815 3.685 90.09 3.919 ;
     RECT  30.528 3.919 90.09 4.081 ;
     RECT  13.215 2.413 13.497 4.225 ;
     RECT  14.616 3.991 14.634 4.225 ;
     RECT  96.588 3.721 98.586 4.351 ;
     RECT  99.615 2.413 100.602 4.351 ;
     RECT  21.312 4.531 21.33 4.801 ;
     RECT  30.456 4.081 90.09 4.963 ;
     RECT  21.312 4.801 21.69 4.999 ;
     RECT  22.608 3.181 24.894 4.999 ;
     RECT  18.615 2.413 18.897 5.035 ;
     RECT  30.456 4.963 90.954 5.063 ;
     RECT  21.024 4.999 24.894 5.071 ;
     RECT  20.844 5.071 24.894 5.189 ;
     RECT  18.615 5.035 19.026 5.305 ;
     RECT  19.908 4.765 19.926 5.305 ;
     RECT  7.815 2.413 8.097 5.341 ;
     RECT  2.415 2.413 2.697 5.467 ;
     RECT  92.592 3.883 95.706 5.539 ;
     RECT  96.588 4.351 100.602 5.539 ;
     RECT  2.304 5.467 2.697 5.549 ;
     RECT  4.176 5.431 4.194 5.575 ;
     RECT  6.048 5.341 6.066 5.575 ;
     RECT  18.615 5.305 19.926 5.575 ;
     RECT  20.844 5.189 21.546 5.575 ;
     RECT  2.415 5.549 2.697 5.611 ;
     RECT  4.068 5.575 4.194 5.611 ;
     RECT  5.472 5.575 6.354 5.611 ;
     RECT  18.615 5.575 21.546 5.611 ;
     RECT  2.415 5.611 6.858 5.729 ;
     RECT  10.692 5.701 10.71 5.737 ;
     RECT  13.215 4.225 14.634 5.737 ;
     RECT  28.224 3.649 29.697 5.737 ;
     RECT  30.456 5.063 90.09 5.737 ;
     RECT  4.5 5.729 6.858 5.765 ;
     RECT  17.496 5.611 17.514 5.765 ;
     RECT  10.26 5.737 10.71 5.773 ;
     RECT  25.632 2.867 27.162 5.773 ;
     RECT  10.044 5.773 10.71 5.803 ;
     RECT  9.468 5.803 10.71 5.845 ;
     RECT  17.568 5.773 17.586 5.845 ;
     RECT  18.576 5.611 21.546 5.845 ;
     RECT  25.632 5.773 27.27 5.851 ;
     RECT  9.252 5.845 10.71 5.881 ;
     RECT  12.672 5.737 14.634 5.881 ;
     RECT  15.444 5.845 15.462 5.881 ;
     RECT  16.596 5.809 16.614 5.881 ;
     RECT  22.608 5.189 24.894 5.971 ;
     RECT  25.632 5.851 27.306 5.971 ;
     RECT  12.384 5.881 14.634 5.995 ;
     RECT  15.444 5.881 15.858 5.995 ;
     RECT  2.415 5.729 3.51 5.999 ;
     RECT  4.5 5.765 6.822 5.999 ;
     RECT  16.596 5.881 16.794 5.999 ;
     RECT  7.815 5.341 8.514 6.007 ;
     RECT  9.252 5.881 10.926 6.007 ;
     RECT  22.608 5.971 27.306 6.007 ;
     RECT  0.108 5.899 0.126 6.029 ;
     RECT  2.415 5.999 2.79 6.029 ;
     RECT  4.5 5.999 5.274 6.035 ;
     RECT  92.592 5.539 100.602 6.043 ;
     RECT  101.736 3.613 101.754 6.043 ;
     RECT  4.752 6.035 5.166 6.107 ;
     RECT  7.815 6.007 10.926 6.107 ;
     RECT  17.568 5.845 21.546 6.107 ;
     RECT  12.384 5.995 15.858 6.115 ;
     RECT  16.596 5.999 16.614 6.115 ;
     RECT  92.592 6.043 101.754 6.115 ;
     RECT  22.608 6.007 27.342 6.139 ;
     RECT  6.012 5.999 6.246 6.143 ;
     RECT  9.072 6.107 10.926 6.143 ;
     RECT  12.384 6.115 16.614 6.151 ;
     RECT  12.204 6.151 16.614 6.173 ;
     RECT  22.608 6.139 27.378 6.179 ;
     RECT  9.252 6.143 10.926 6.235 ;
     RECT  4.752 6.107 4.842 6.269 ;
     RECT  6.012 6.143 6.102 6.269 ;
     RECT  9.252 6.235 11.466 6.269 ;
     RECT  12.204 6.173 16.038 6.269 ;
     RECT  22.608 6.179 27.342 6.269 ;
     RECT  4.752 6.269 4.77 6.305 ;
     RECT  6.012 6.269 6.03 6.305 ;
     RECT  9.252 6.269 9.27 6.305 ;
     RECT  15.732 6.269 16.038 6.305 ;
     RECT  18 6.107 21.546 6.341 ;
     RECT  10.62 6.269 11.466 6.421 ;
     RECT  12.204 6.269 14.85 6.421 ;
     RECT  10.62 6.421 14.85 6.539 ;
     RECT  12.456 6.539 14.85 6.575 ;
     RECT  15.804 6.305 16.038 6.575 ;
     RECT  90.936 5.063 90.954 6.619 ;
     RECT  12.456 6.575 14.634 6.647 ;
     RECT  16.02 6.575 16.038 6.647 ;
     RECT  28.224 5.737 90.09 6.655 ;
     RECT  90.936 6.619 90.99 6.655 ;
     RECT  10.62 6.539 11.682 6.656 ;
     RECT  10.62 6.656 11.574 6.683 ;
     RECT  10.872 6.683 11.574 6.809 ;
     RECT  10.872 6.809 11.142 6.845 ;
     RECT  12.924 6.647 14.634 6.845 ;
     RECT  92.592 6.115 101.79 7.051 ;
     RECT  28.224 6.655 90.99 7.421 ;
     RECT  18.216 6.341 21.546 7.735 ;
     RECT  92.592 7.051 101.826 7.735 ;
     RECT  18.18 7.735 21.546 7.771 ;
     RECT  22.608 6.269 27.306 7.771 ;
     RECT  17.928 7.771 27.306 7.897 ;
     RECT  92.592 7.735 101.862 7.933 ;
     RECT  102.96 5.503 102.978 7.933 ;
     RECT  17.748 7.897 27.306 7.949 ;
     RECT  28.224 7.421 71.334 7.969 ;
     RECT  72.18 7.421 90.99 7.969 ;
     RECT  17.928 7.949 27.306 7.997 ;
     RECT  28.044 7.969 71.334 8.239 ;
     RECT  72.18 7.969 91.026 8.239 ;
     RECT  13.215 6.845 14.634 8.401 ;
     RECT  22.608 7.997 27.306 8.401 ;
     RECT  28.044 8.239 91.026 8.401 ;
     RECT  17.928 7.997 21.654 8.501 ;
     RECT  13.215 8.401 14.85 8.537 ;
     RECT  22.608 8.401 91.026 8.545 ;
     RECT  22.608 8.545 91.098 8.581 ;
     RECT  92.592 7.933 102.978 8.581 ;
     RECT  17.928 8.501 21.618 8.969 ;
     RECT  17.928 8.969 21.546 9.355 ;
     RECT  17.316 9.355 21.546 9.677 ;
     RECT  22.608 8.581 102.978 10.589 ;
     RECT  30.456 10.589 102.978 11.281 ;
     RECT  106.74 11.011 106.758 11.281 ;
     RECT  106.596 11.281 106.758 11.399 ;
     RECT  106.74 11.399 106.758 11.443 ;
     RECT  107.82 11.281 107.838 11.551 ;
     RECT  107.82 11.551 108.378 11.785 ;
     RECT  22.608 10.589 29.697 11.821 ;
     RECT  30.456 11.281 103.194 11.821 ;
     RECT  106.74 11.443 106.83 11.947 ;
     RECT  107.64 11.785 108.378 11.947 ;
     RECT  22.608 11.821 103.194 11.975 ;
     RECT  106.74 11.947 108.378 12.091 ;
     RECT  106.74 12.091 108.774 12.209 ;
     RECT  106.74 12.209 108.63 12.217 ;
     RECT  106.596 12.217 108.63 12.317 ;
     RECT  106.992 12.317 108.63 12.365 ;
     RECT  105.015 2.413 105.297 12.595 ;
     RECT  17.856 9.677 21.546 12.757 ;
     RECT  22.608 11.975 102.978 12.757 ;
     RECT  109.512 12.901 109.53 13.019 ;
     RECT  110.415 2.413 110.697 13.063 ;
     RECT  104.58 12.595 105.297 13.603 ;
     RECT  106.992 12.365 108.27 13.639 ;
     RECT  17.856 12.757 102.978 13.909 ;
     RECT  104.58 13.603 105.462 13.909 ;
     RECT  16.884 13.837 16.902 13.945 ;
     RECT  106.992 13.639 108.666 14.107 ;
     RECT  106.596 14.107 108.666 14.243 ;
     RECT  16.596 13.945 16.902 14.251 ;
     RECT  104.58 13.909 105.858 14.377 ;
     RECT  17.64 13.909 102.978 14.413 ;
     RECT  106.992 14.243 108.666 14.413 ;
     RECT  16.272 14.251 16.902 14.485 ;
     RECT  17.64 14.413 103.014 14.485 ;
     RECT  16.272 14.485 103.014 14.549 ;
     RECT  16.272 14.549 102.978 14.755 ;
     RECT  109.692 13.063 110.697 14.791 ;
     RECT  106.992 14.413 108.774 14.881 ;
     RECT  111.6 14.719 111.618 14.909 ;
     RECT  16.056 14.755 102.978 15.025 ;
     RECT  104.58 14.377 106.146 15.025 ;
     RECT  106.992 14.881 108.846 15.025 ;
     RECT  109.692 14.791 110.754 15.187 ;
     RECT  111.492 15.025 111.51 15.187 ;
     RECT  15.948 15.025 102.978 15.251 ;
     RECT  109.692 15.187 111.51 15.389 ;
     RECT  17.82 15.251 102.978 15.421 ;
     RECT  104.58 15.025 108.846 15.421 ;
     RECT  109.692 15.389 111.294 15.421 ;
     RECT  15.948 15.251 17.082 15.437 ;
     RECT  17.82 15.421 103.122 15.601 ;
     RECT  15.948 15.437 17.01 15.835 ;
     RECT  104.58 15.421 111.294 16.231 ;
     RECT  15.624 15.835 17.01 16.375 ;
     RECT  15.624 16.375 17.082 16.411 ;
     RECT  17.82 15.601 103.77 16.439 ;
     RECT  13.215 8.537 14.634 16.537 ;
     RECT  15.552 16.411 17.082 16.537 ;
     RECT  13.215 16.537 17.082 16.541 ;
     RECT  16.164 16.541 17.082 16.681 ;
     RECT  17.82 16.439 103.446 16.681 ;
     RECT  104.58 16.231 111.51 16.799 ;
     RECT  112.464 16.879 112.482 16.915 ;
     RECT  104.58 16.799 111.402 16.979 ;
     RECT  112.356 16.915 112.482 16.979 ;
     RECT  112.356 16.979 112.374 17.117 ;
     RECT  16.164 16.681 103.446 17.221 ;
     RECT  112.14 17.491 112.158 17.609 ;
     RECT  13.215 16.541 15.354 17.617 ;
     RECT  104.976 16.979 111.402 17.617 ;
     RECT  13.215 17.617 15.39 17.741 ;
     RECT  16.164 17.221 103.554 18.193 ;
     RECT  104.976 17.617 112.05 18.427 ;
     RECT  104.868 18.427 112.05 18.689 ;
     RECT  16.092 18.193 103.554 19.039 ;
     RECT  16.092 19.039 103.95 19.229 ;
     RECT  105.015 18.689 112.05 20.623 ;
     RECT  13.215 17.741 15.354 20.695 ;
     RECT  16.092 19.229 103.914 20.695 ;
     RECT  13.215 20.695 103.914 20.821 ;
     RECT  104.904 20.623 112.05 20.821 ;
     RECT  13.215 20.821 112.05 22.829 ;
     RECT  13.215 22.829 111.726 23.501 ;
     RECT  2.415 6.029 2.697 23.507 ;
     RECT  7.815 6.107 8.097 23.507 ;
     RECT  13.215 23.501 22.23 23.549 ;
     RECT  23.04 23.501 111.726 23.549 ;
     RECT  13.215 23.549 22.158 23.597 ;
     RECT  23.04 23.549 38.754 23.645 ;
     RECT  23.832 23.645 38.754 23.741 ;
     RECT  2.415 23.507 2.505 23.777 ;
     RECT  7.815 23.507 7.905 23.777 ;
     RECT  13.215 23.597 22.014 23.777 ;
     RECT  24.015 23.741 24.966 23.777 ;
     RECT  39.564 23.549 78.105 23.777 ;
     RECT  13.392 23.777 22.014 23.789 ;
     RECT  25.74 23.741 38.754 23.789 ;
     RECT  13.392 23.789 19.926 23.837 ;
     RECT  23.04 23.645 23.094 23.837 ;
     RECT  13.932 23.837 19.926 23.885 ;
     RECT  20.664 23.789 22.014 23.885 ;
     RECT  24.12 23.777 24.966 23.885 ;
     RECT  13.932 23.885 15.966 23.933 ;
     RECT  17.1 23.885 19.926 23.933 ;
     RECT  21.78 23.885 22.014 23.933 ;
     RECT  23.076 23.837 23.094 23.933 ;
     RECT  25.74 23.789 38.61 23.933 ;
     RECT  39.564 23.777 77.31 23.933 ;
     RECT  79.164 23.549 111.726 23.933 ;
     RECT  17.1 23.933 19.746 24.077 ;
     RECT  24.372 23.885 24.966 24.077 ;
     RECT  79.164 23.933 109.71 24.077 ;
     RECT  39.564 23.933 43.11 24.317 ;
     RECT  35.316 23.933 36.162 24.365 ;
     RECT  59.652 23.933 77.274 24.461 ;
     RECT  19.728 24.077 19.746 24.509 ;
     RECT  59.652 24.461 66.366 24.509 ;
     RECT  67.104 24.461 77.274 24.509 ;
     RECT  79.164 24.077 90.846 24.509 ;
     RECT  26.316 23.933 30.546 24.557 ;
     RECT  43.92 23.933 58.662 24.557 ;
     RECT  59.652 24.509 66.294 24.557 ;
     RECT  74.736 24.509 77.274 24.557 ;
     RECT  79.884 24.509 86.958 24.557 ;
     RECT  87.768 24.509 89.37 24.557 ;
     RECT  90.144 24.509 90.846 24.557 ;
     RECT  92.016 24.077 109.71 24.557 ;
     RECT  90.144 24.557 90.738 24.605 ;
     RECT  26.316 24.557 28.314 24.653 ;
     RECT  97.416 24.557 104.67 24.653 ;
     RECT  49.068 24.557 58.662 24.797 ;
     RECT  39.78 24.317 43.11 24.845 ;
     RECT  37.512 23.933 37.53 24.893 ;
     RECT  87.768 24.557 89.118 24.941 ;
     RECT  17.1 24.077 18.09 24.989 ;
     RECT  87.768 24.941 88.794 24.989 ;
     RECT  17.1 24.989 17.946 25.037 ;
     RECT  26.316 24.653 26.91 25.037 ;
     RECT  59.652 24.557 62.046 25.037 ;
     RECT  110.628 23.933 111.726 25.037 ;
     RECT  85.392 24.557 86.958 25.079 ;
     RECT  26.892 25.037 26.91 25.085 ;
     RECT  27.684 24.653 28.314 25.085 ;
     RECT  35.316 24.365 35.838 25.085 ;
     RECT  39.888 24.845 43.11 25.085 ;
     RECT  43.92 24.557 46.53 25.085 ;
     RECT  49.068 24.797 58.374 25.085 ;
     RECT  59.832 25.037 62.046 25.085 ;
     RECT  62.892 24.557 66.114 25.085 ;
     RECT  67.104 24.509 70.47 25.085 ;
     RECT  71.568 24.509 73.818 25.085 ;
     RECT  74.772 24.557 77.274 25.085 ;
     RECT  79.884 24.557 84.618 25.085 ;
     RECT  87.768 24.989 88.29 25.085 ;
     RECT  92.016 24.557 96.498 25.085 ;
     RECT  97.416 24.653 100.566 25.085 ;
     RECT  110.916 25.037 111.726 25.085 ;
     RECT  29.16 24.557 30.546 25.133 ;
     RECT  39.996 25.085 40.014 25.133 ;
     RECT  43.92 25.085 44.118 25.133 ;
     RECT  47.448 24.557 48.294 25.133 ;
     RECT  61.236 25.085 61.686 25.133 ;
     RECT  62.892 25.085 64.962 25.133 ;
     RECT  65.772 25.085 66.114 25.133 ;
     RECT  74.772 25.085 75.726 25.133 ;
     RECT  80.208 25.085 84.618 25.133 ;
     RECT  85.464 25.079 86.958 25.133 ;
     RECT  88.272 25.085 88.29 25.133 ;
     RECT  90.144 24.605 90.486 25.133 ;
     RECT  97.92 25.085 100.566 25.133 ;
     RECT  101.34 24.653 102.438 25.133 ;
     RECT  103.428 24.653 104.67 25.133 ;
     RECT  105.66 24.557 109.71 25.133 ;
     RECT  44.1 25.133 44.118 25.181 ;
     RECT  61.236 25.133 61.578 25.181 ;
     RECT  80.208 25.133 83.214 25.181 ;
     RECT  98.028 25.133 98.946 25.181 ;
     RECT  103.428 25.133 103.446 25.181 ;
     RECT  104.652 25.133 104.67 25.181 ;
     RECT  106.128 25.133 108.774 25.181 ;
     RECT  110.916 25.085 111.654 25.181 ;
     RECT  80.208 25.181 82.89 25.229 ;
     RECT  84.168 25.133 84.618 25.229 ;
     RECT  98.316 25.181 98.334 25.229 ;
     RECT  101.34 25.133 101.466 25.229 ;
     RECT  107.712 25.181 108.774 25.229 ;
     RECT  80.604 25.229 82.89 25.373 ;
     RECT  24.876 24.077 24.966 25.565 ;
     RECT  30.528 25.133 30.546 25.579 ;
     RECT  13.932 23.933 14.526 25.661 ;
     RECT  49.392 25.085 50.058 25.661 ;
     RECT  44.856 25.085 46.53 25.675 ;
     RECT  62.892 25.133 63.522 25.675 ;
     RECT  17.856 25.037 17.946 25.709 ;
     RECT  49.5 25.661 50.058 25.709 ;
     RECT  55.98 25.085 57.87 25.709 ;
     RECT  64.548 25.133 64.962 25.709 ;
     RECT  72.072 25.085 73.818 25.709 ;
     RECT  94.428 25.085 95.094 25.709 ;
     RECT  14.004 25.661 14.526 25.757 ;
     RECT  21.924 23.933 22.014 25.757 ;
     RECT  44.856 25.675 46.854 25.757 ;
     RECT  50.868 25.085 50.994 25.757 ;
     RECT  60.192 25.085 60.462 25.757 ;
     RECT  94.428 25.709 94.986 25.757 ;
     RECT  102.204 25.133 102.438 25.757 ;
     RECT  14.004 25.757 14.022 25.805 ;
     RECT  17.1 25.037 17.118 25.805 ;
     RECT  17.856 25.709 17.874 25.805 ;
     RECT  21.996 25.757 22.014 25.805 ;
     RECT  24.876 25.565 24.894 25.805 ;
     RECT  28.008 25.085 28.314 25.805 ;
     RECT  29.16 25.133 29.178 25.805 ;
     RECT  30.528 25.579 31.302 25.805 ;
     RECT  35.604 25.085 35.838 25.805 ;
     RECT  40.896 25.085 42.426 25.805 ;
     RECT  44.964 25.757 46.854 25.805 ;
     RECT  47.844 25.133 48.294 25.805 ;
     RECT  49.5 25.709 50.022 25.805 ;
     RECT  50.868 25.757 50.886 25.805 ;
     RECT  53.388 25.085 55.17 25.805 ;
     RECT  55.98 25.709 56.286 25.805 ;
     RECT  57.492 25.709 57.87 25.805 ;
     RECT  60.3 25.757 60.462 25.805 ;
     RECT  61.236 25.181 61.254 25.805 ;
     RECT  62.568 25.675 63.522 25.805 ;
     RECT  64.548 25.709 64.566 25.805 ;
     RECT  65.772 25.133 65.79 25.805 ;
     RECT  67.104 25.085 67.374 25.805 ;
     RECT  69.3 25.085 70.47 25.805 ;
     RECT  72.18 25.709 73.818 25.805 ;
     RECT  74.772 25.133 74.79 25.805 ;
     RECT  75.708 25.133 75.726 25.805 ;
     RECT  76.824 25.085 77.274 25.805 ;
     RECT  80.604 25.373 80.622 25.805 ;
     RECT  81.468 25.373 82.89 25.805 ;
     RECT  84.168 25.229 84.294 25.805 ;
     RECT  86.148 25.133 86.958 25.805 ;
     RECT  90.468 25.133 90.486 25.805 ;
     RECT  92.016 25.085 92.286 25.805 ;
     RECT  93.132 25.085 93.15 25.805 ;
     RECT  94.428 25.757 94.878 25.805 ;
     RECT  96.192 25.085 96.21 25.805 ;
     RECT  99.936 25.133 99.954 25.805 ;
     RECT  101.34 25.229 101.358 25.805 ;
     RECT  102.204 25.757 102.222 25.805 ;
     RECT  106.344 25.181 106.362 25.805 ;
     RECT  108.252 25.229 108.774 25.805 ;
     RECT  109.692 25.133 109.71 25.805 ;
     RECT  110.916 25.181 110.934 25.805 ;
     RECT  11.196 25.723 11.214 25.853 ;
     RECT  33.408 23.933 33.426 25.853 ;
     RECT  35.604 25.805 35.622 25.901 ;
     RECT  79.38 25.771 79.398 25.901 ;
     RECT  84.276 25.805 84.294 25.901 ;
    LAYER M4 ;
     RECT  0.06 5.424 0.097 5.928 ;
     RECT  0.097 5.424 0.227 6.024 ;
     RECT  0.227 5.52 2.408 6.024 ;
     RECT  0.181 12.288 2.408 12.312 ;
     RECT  2.408 2.148 2.512 23.772 ;
     RECT  2.512 2.418 2.704 23.502 ;
     RECT  2.704 5.664 2.801 6.024 ;
     RECT  2.801 5.664 5.177 5.88 ;
     RECT  5.177 5.664 5.501 5.736 ;
     RECT  5.501 5.712 7.808 5.736 ;
     RECT  2.704 12.288 7.808 12.312 ;
     RECT  7.808 2.148 7.912 23.772 ;
     RECT  7.912 2.418 8.104 23.502 ;
     RECT  8.104 5.808 9.457 5.832 ;
     RECT  9.457 5.808 9.497 6.264 ;
     RECT  8.104 12.288 10.789 12.312 ;
     RECT  9.497 6.24 11.077 6.264 ;
     RECT  10.597 25.776 11.141 25.896 ;
     RECT  10.981 23.904 11.269 23.928 ;
     RECT  11.141 25.728 11.269 25.896 ;
     RECT  11.077 6 11.293 6.264 ;
     RECT  11.461 22.56 11.557 22.584 ;
     RECT  11.557 22.512 11.653 22.584 ;
     RECT  11.269 23.904 11.653 25.896 ;
     RECT  11.293 6 11.693 6.648 ;
     RECT  10.789 12.288 12.229 12.888 ;
     RECT  12.325 7.68 12.613 7.704 ;
     RECT  11.693 6 12.661 6.264 ;
     RECT  12.229 11.952 12.709 12.888 ;
     RECT  12.517 10.656 12.997 10.68 ;
     RECT  12.709 11.712 12.997 12.888 ;
     RECT  12.661 6 13.208 6.36 ;
     RECT  12.613 7.68 13.208 7.752 ;
     RECT  12.997 10.656 13.208 12.888 ;
     RECT  12.421 21.504 13.208 21.528 ;
     RECT  11.653 22.512 13.208 25.896 ;
     RECT  13.208 2.148 13.312 25.896 ;
     RECT  13.312 2.418 13.504 25.896 ;
     RECT  13.504 6 14.537 6.36 ;
     RECT  14.629 17.664 14.725 17.688 ;
     RECT  14.537 6 14.861 6.168 ;
     RECT  14.725 17.664 15.005 17.736 ;
     RECT  15.109 15.984 15.205 16.008 ;
     RECT  15.205 15.984 15.301 16.056 ;
     RECT  15.005 17.712 15.401 17.736 ;
     RECT  15.301 15.984 15.493 16.104 ;
     RECT  15.397 14.784 15.589 14.808 ;
     RECT  15.493 15.984 16.085 16.536 ;
     RECT  15.589 13.872 16.549 14.808 ;
     RECT  14.861 6.096 16.585 6.168 ;
     RECT  16.549 13.872 16.805 15.96 ;
     RECT  13.504 7.344 16.837 7.752 ;
     RECT  16.805 13.872 16.913 13.896 ;
     RECT  16.837 7.344 16.933 7.8 ;
     RECT  16.805 15.408 17.021 15.96 ;
     RECT  13.504 20.208 17.021 20.232 ;
     RECT  13.504 10.656 17.029 12.888 ;
     RECT  17.021 15.408 17.093 15.432 ;
     RECT  17.029 9.936 17.305 12.888 ;
     RECT  16.585 6 17.413 6.168 ;
     RECT  16.933 7.344 17.413 7.944 ;
     RECT  17.413 6 17.509 7.944 ;
     RECT  17.509 6 18.608 8.52 ;
     RECT  17.305 9.648 18.608 12.888 ;
     RECT  13.504 21.504 18.608 21.528 ;
     RECT  13.504 22.512 18.608 25.896 ;
     RECT  18.608 2.148 18.712 25.896 ;
     RECT  18.712 2.418 18.904 25.896 ;
     RECT  18.904 5.904 19.804 6.216 ;
     RECT  19.804 5.904 20.221 6.12 ;
     RECT  20.221 5.856 20.477 6.12 ;
     RECT  20.477 6 20.729 6.12 ;
     RECT  20.677 19.392 20.773 19.416 ;
     RECT  20.965 15.312 21.061 15.336 ;
     RECT  18.904 21.504 21.085 21.528 ;
     RECT  18.904 22.512 21.085 25.896 ;
     RECT  21.061 15.312 21.089 15.624 ;
     RECT  20.773 19.392 21.541 19.944 ;
     RECT  21.541 19.392 21.589 19.992 ;
     RECT  21.089 15.6 21.665 15.624 ;
     RECT  21.157 17.088 21.665 17.112 ;
     RECT  21.589 18.576 22.565 19.992 ;
     RECT  22.525 17.472 22.633 17.496 ;
     RECT  22.565 18.576 22.633 19.416 ;
     RECT  22.633 17.232 22.739 19.416 ;
     RECT  22.597 20.448 22.789 20.472 ;
     RECT  22.739 17.232 22.849 18.84 ;
     RECT  21.445 14.208 22.961 14.232 ;
     RECT  22.789 20.448 22.997 20.52 ;
     RECT  23.029 15.456 23.605 15.48 ;
     RECT  23.605 15.456 23.612 16.056 ;
     RECT  22.849 17.088 23.612 18.84 ;
     RECT  23.612 15.072 23.929 18.84 ;
     RECT  20.729 6 24.008 6.024 ;
     RECT  18.904 7.344 24.008 7.752 ;
     RECT  18.904 10.368 24.008 12.888 ;
     RECT  23.929 15.072 24.008 19.272 ;
     RECT  22.997 20.448 24.008 20.472 ;
     RECT  21.085 21.504 24.008 25.896 ;
     RECT  24.008 2.148 24.112 25.896 ;
     RECT  24.112 2.418 24.304 25.896 ;
     RECT  23.893 0.048 24.757 0.072 ;
     RECT  24.304 14.64 25.121 25.896 ;
     RECT  25.121 14.64 25.265 20.232 ;
     RECT  25.265 14.64 25.697 15 ;
     RECT  25.121 21.264 25.697 25.896 ;
     RECT  24.304 10.656 25.765 12.888 ;
     RECT  25.697 14.64 25.877 14.76 ;
     RECT  24.304 6 25.909 6.024 ;
     RECT  25.765 10.656 26.053 13.464 ;
     RECT  25.513 2.208 26.305 2.232 ;
     RECT  26.053 10.656 26.345 14.088 ;
     RECT  25.909 5.712 26.665 6.024 ;
     RECT  24.304 7.344 26.665 7.752 ;
     RECT  26.305 2.208 26.773 2.28 ;
     RECT  26.665 5.712 26.993 7.752 ;
     RECT  25.265 16.032 27.025 20.232 ;
     RECT  27.025 15.936 27.097 20.232 ;
     RECT  25.697 21.36 27.097 25.896 ;
     RECT  27.097 15.84 27.205 25.896 ;
     RECT  27.205 15.264 27.277 25.896 ;
     RECT  27.277 15.024 27.313 25.896 ;
     RECT  26.993 5.712 27.389 6.168 ;
     RECT  26.345 10.656 28.465 13.464 ;
     RECT  27.313 14.784 28.465 25.896 ;
     RECT  27.389 5.712 28.609 6.024 ;
     RECT  24.757 0.048 29.041 0.12 ;
     RECT  28.609 5.712 29.077 6.12 ;
     RECT  26.993 7.344 29.077 7.752 ;
     RECT  26.773 2.064 29.408 2.28 ;
     RECT  29.077 5.712 29.408 7.752 ;
     RECT  28.465 10.656 29.408 25.896 ;
     RECT  29.408 2.064 29.704 25.896 ;
     RECT  29.704 10.08 30.161 13.608 ;
     RECT  29.704 14.64 30.593 17.448 ;
     RECT  30.805 4.704 30.913 4.728 ;
     RECT  29.704 6 30.913 7.752 ;
     RECT  29.704 2.064 31.129 2.28 ;
     RECT  31.129 2.016 31.277 2.28 ;
     RECT  30.593 15.408 31.285 17.448 ;
     RECT  29.704 18.672 31.285 25.896 ;
     RECT  31.285 15.408 31.493 25.896 ;
     RECT  30.161 10.08 31.525 13.368 ;
     RECT  31.525 10.08 31.532 13.896 ;
     RECT  31.532 9.552 31.619 13.896 ;
     RECT  31.493 15.408 31.717 19.128 ;
     RECT  31.619 10.08 32.137 13.896 ;
     RECT  32.137 10.08 32.281 13.944 ;
     RECT  31.717 15.072 32.281 19.128 ;
     RECT  29.041 0.048 32.461 0.216 ;
     RECT  32.281 10.08 32.857 19.128 ;
     RECT  31.493 20.304 32.857 25.896 ;
     RECT  30.913 4.704 32.933 7.752 ;
     RECT  32.857 10.08 32.965 25.896 ;
     RECT  32.965 9.648 33.005 25.896 ;
     RECT  32.461 0.048 33.037 0.264 ;
     RECT  31.277 2.016 33.037 2.088 ;
     RECT  33.005 9.648 33.325 9.672 ;
     RECT  33.005 10.656 33.437 25.896 ;
     RECT  33.325 9.12 33.509 9.672 ;
     RECT  33.037 2.016 33.577 2.376 ;
     RECT  33.577 1.968 34.117 2.376 ;
     RECT  32.933 4.704 34.441 6.024 ;
     RECT  32.933 7.344 34.441 7.752 ;
     RECT  33.509 9.552 34.693 9.672 ;
     RECT  34.441 4.704 34.801 7.752 ;
     RECT  34.693 8.832 34.801 9.672 ;
     RECT  34.117 1.392 34.808 2.376 ;
     RECT  34.801 4.704 34.808 9.672 ;
     RECT  33.437 10.656 34.808 24.888 ;
     RECT  34.808 1.392 34.885 24.888 ;
     RECT  33.437 25.872 34.885 25.896 ;
     RECT  34.885 1.392 35.104 25.896 ;
     RECT  33.037 0.048 35.365 0.408 ;
     RECT  35.104 1.392 35.365 3.048 ;
     RECT  35.104 4.704 35.633 25.896 ;
     RECT  35.633 4.704 35.849 25.8 ;
     RECT  35.365 0.048 36.493 3.048 ;
     RECT  35.849 4.704 36.493 24.888 ;
     RECT  36.493 0.048 37.427 24.888 ;
     RECT  37.427 4.032 37.541 24.888 ;
     RECT  37.541 4.032 37.619 24.84 ;
     RECT  37.619 4.464 37.901 24.84 ;
     RECT  37.427 0.048 38.099 3.048 ;
     RECT  37.901 4.704 38.297 24.84 ;
     RECT  38.297 4.704 38.477 22.104 ;
     RECT  38.099 0.048 39.157 0.168 ;
     RECT  38.099 1.392 39.157 3.048 ;
     RECT  38.297 23.376 39.233 24.84 ;
     RECT  39.157 0.048 39.347 3.048 ;
     RECT  39.233 23.952 39.877 24.84 ;
     RECT  39.877 23.952 39.96 25.08 ;
     RECT  38.477 7.104 40.021 22.104 ;
     RECT  39.347 1.68 40.208 3.048 ;
     RECT  38.477 4.704 40.208 6.12 ;
     RECT  40.021 7.104 40.208 22.296 ;
     RECT  39.96 23.952 40.208 25.128 ;
     RECT  40.208 1.68 40.504 25.128 ;
     RECT  40.504 4.704 40.549 25.128 ;
     RECT  39.347 0.048 40.921 0.696 ;
     RECT  40.504 1.68 40.921 3.048 ;
     RECT  40.549 4.704 40.979 25.8 ;
     RECT  40.921 0.048 41.357 3.048 ;
     RECT  41.357 0.144 41.401 3.048 ;
     RECT  40.979 4.704 42.133 22.824 ;
     RECT  40.979 23.904 42.437 25.8 ;
     RECT  42.437 23.904 42.641 25.752 ;
     RECT  42.641 23.808 42.755 25.752 ;
     RECT  41.401 0.192 42.761 3.048 ;
     RECT  42.761 0.192 42.973 1.8 ;
     RECT  42.973 0.096 43.09 1.8 ;
     RECT  42.133 4.512 43.429 22.824 ;
     RECT  42.755 23.808 43.429 25.08 ;
     RECT  43.429 4.512 43.667 25.08 ;
     RECT  43.09 0.048 43.909 1.8 ;
     RECT  42.761 2.832 43.909 3.048 ;
     RECT  43.667 23.904 43.909 25.08 ;
     RECT  43.909 23.904 44.05 25.128 ;
     RECT  43.667 4.512 44.051 22.872 ;
     RECT  43.909 0.048 44.147 3.048 ;
     RECT  44.051 4.512 44.161 22.824 ;
     RECT  44.147 2.256 44.233 3.048 ;
     RECT  44.147 0.048 44.339 1.128 ;
     RECT  44.339 0.048 44.435 1.08 ;
     RECT  44.05 23.904 44.485 25.176 ;
     RECT  44.485 23.904 44.581 25.56 ;
     RECT  44.581 23.904 44.773 25.656 ;
     RECT  44.773 23.904 44.869 25.752 ;
     RECT  44.233 2.256 44.965 3.096 ;
     RECT  44.161 4.128 44.965 22.824 ;
     RECT  44.965 2.256 45.349 22.824 ;
     RECT  44.435 0.048 45.421 1.032 ;
     RECT  45.421 0.048 45.457 1.176 ;
     RECT  45.349 2.256 45.457 22.92 ;
     RECT  45.457 0.048 45.608 22.92 ;
     RECT  44.869 23.904 45.608 25.8 ;
     RECT  45.608 0.048 45.904 25.8 ;
     RECT  45.904 0.048 46.937 9.816 ;
     RECT  46.937 4.464 47.437 9.816 ;
     RECT  45.904 10.848 47.437 25.8 ;
     RECT  47.437 4.464 47.837 25.8 ;
     RECT  46.937 0.048 48.161 3.336 ;
     RECT  48.161 0.048 48.269 2.76 ;
     RECT  48.269 0.048 48.485 2.568 ;
     RECT  48.485 0.048 48.563 2.28 ;
     RECT  47.837 4.464 48.701 9.816 ;
     RECT  48.701 4.464 48.805 4.824 ;
     RECT  48.701 5.856 48.953 9.672 ;
     RECT  47.837 10.848 48.953 25.8 ;
     RECT  48.953 6.816 48.989 9.672 ;
     RECT  48.563 0.048 49.025 1.272 ;
     RECT  48.953 10.848 49.025 22.92 ;
     RECT  48.805 4.368 49.205 4.824 ;
     RECT  48.563 2.256 49.427 2.28 ;
     RECT  49.025 0.096 49.597 1.272 ;
     RECT  49.205 4.656 49.601 4.824 ;
     RECT  49.601 4.8 49.817 4.824 ;
     RECT  48.989 6.816 49.993 7.656 ;
     RECT  49.025 10.896 50.173 22.92 ;
     RECT  48.953 24.192 50.173 25.8 ;
     RECT  48.989 9.024 50.209 9.672 ;
     RECT  50.173 10.896 50.209 25.8 ;
     RECT  49.849 5.472 50.444 5.592 ;
     RECT  50.444 5.472 50.485 5.64 ;
     RECT  49.993 6.816 50.485 8.04 ;
     RECT  50.485 5.472 50.677 8.04 ;
     RECT  50.209 9.024 50.677 25.8 ;
     RECT  49.597 0.096 50.713 2.136 ;
     RECT  49.705 3.648 50.713 3.672 ;
     RECT  50.677 5.472 50.897 25.8 ;
     RECT  50.713 0.096 51.008 3.96 ;
     RECT  50.897 5.472 51.008 25.752 ;
     RECT  51.008 0.096 51.304 25.752 ;
     RECT  51.304 5.04 51.329 9.288 ;
     RECT  51.304 0.096 51.443 1.752 ;
     RECT  51.304 10.896 51.587 25.752 ;
     RECT  51.587 10.896 51.635 25.08 ;
     RECT  51.635 10.896 51.683 22.344 ;
     RECT  51.683 10.896 51.905 22.248 ;
     RECT  51.443 0.528 52.019 1.752 ;
     RECT  51.304 3.936 52.355 4.008 ;
     RECT  51.329 5.04 52.355 9.096 ;
     RECT  52.355 5.136 52.373 9.096 ;
     RECT  52.373 7.104 52.481 9.096 ;
     RECT  52.355 3.984 52.499 4.008 ;
     RECT  52.019 1.056 52.508 1.752 ;
     RECT  51.905 11.232 52.517 22.248 ;
     RECT  51.635 23.376 52.589 25.08 ;
     RECT  52.373 5.136 52.661 5.88 ;
     RECT  52.517 15.312 52.741 22.248 ;
     RECT  52.508 1.056 52.883 2.28 ;
     RECT  52.741 15.312 52.985 22.824 ;
     RECT  52.589 23.952 52.985 25.08 ;
     RECT  52.517 11.232 53.485 13.992 ;
     RECT  52.481 7.104 53.629 9.048 ;
     RECT  52.985 15.552 53.653 22.824 ;
     RECT  52.985 23.952 53.653 24.792 ;
     RECT  52.661 5.136 53.917 5.784 ;
     RECT  53.629 6.96 53.917 9.048 ;
     RECT  53.917 5.136 54.025 9.144 ;
     RECT  53.653 15.552 54.025 24.792 ;
     RECT  53.485 10.704 54.101 13.992 ;
     RECT  54.025 5.136 54.131 9.72 ;
     RECT  54.025 15.264 54.277 24.792 ;
     RECT  53.125 25.776 54.277 25.8 ;
     RECT  54.101 11.28 54.317 13.992 ;
     RECT  53.125 0.576 54.361 0.6 ;
     RECT  54.131 5.136 54.745 9.048 ;
     RECT  54.317 11.808 54.745 13.992 ;
     RECT  54.277 15.264 54.745 25.8 ;
     RECT  54.745 4.224 54.821 9.048 ;
     RECT  54.745 11.808 54.829 25.8 ;
     RECT  54.821 8.16 54.893 9.048 ;
     RECT  52.883 1.728 55.321 2.28 ;
     RECT  55.321 1.632 55.475 2.28 ;
     RECT  54.821 4.224 55.609 7.176 ;
     RECT  54.893 8.208 55.789 9.048 ;
     RECT  55.321 10.128 55.789 10.152 ;
     RECT  54.829 11.808 56.005 14.28 ;
     RECT  54.829 15.264 56.005 25.8 ;
     RECT  56.005 11.808 56.257 25.8 ;
     RECT  56.257 11.712 56.297 25.8 ;
     RECT  55.475 1.728 56.408 2.28 ;
     RECT  55.609 4.176 56.408 7.176 ;
     RECT  55.789 8.208 56.408 10.152 ;
     RECT  56.297 11.712 56.408 25.704 ;
     RECT  56.408 1.728 56.704 25.704 ;
     RECT  56.485 0.288 56.773 0.312 ;
     RECT  56.773 0.192 56.819 0.312 ;
     RECT  56.704 15.264 56.945 25.704 ;
     RECT  56.819 0.192 56.963 0.216 ;
     RECT  56.704 3.408 57.017 5.592 ;
     RECT  56.945 15.36 57.059 25.704 ;
     RECT  56.704 6.816 57.347 13.848 ;
     RECT  57.059 21.216 57.437 25.704 ;
     RECT  57.347 10.56 57.557 13.848 ;
     RECT  57.437 21.216 57.58 25.8 ;
     RECT  57.58 23.376 57.587 25.8 ;
     RECT  57.557 10.56 57.629 13.704 ;
     RECT  57.587 23.712 57.881 25.8 ;
     RECT  57.881 23.712 57.889 25.704 ;
     RECT  57.059 15.36 57.913 20.136 ;
     RECT  57.629 11.376 57.923 13.704 ;
     RECT  57.58 21.216 58.025 21.816 ;
     RECT  57.913 15.168 58.061 20.136 ;
     RECT  57.889 23.712 58.133 25.08 ;
     RECT  58.061 18.192 58.201 20.136 ;
     RECT  58.201 18.192 58.213 20.232 ;
     RECT  58.025 21.216 58.213 21.528 ;
     RECT  58.133 23.904 58.385 25.08 ;
     RECT  57.347 6.816 58.421 9.048 ;
     RECT  58.421 8.16 58.493 9.048 ;
     RECT  57.017 4.272 58.633 5.592 ;
     RECT  58.213 18.192 58.673 21.528 ;
     RECT  58.385 23.904 58.673 24.792 ;
     RECT  58.273 0.576 58.777 0.6 ;
     RECT  58.777 0.576 58.78 0.648 ;
     RECT  57.923 13.68 58.853 13.704 ;
     RECT  58.78 0.624 58.861 0.648 ;
     RECT  58.673 20.592 58.889 21.528 ;
     RECT  58.633 3.84 58.957 5.592 ;
     RECT  57.923 11.376 58.957 12.504 ;
     RECT  58.493 8.16 58.997 8.184 ;
     RECT  58.957 10.848 59.033 12.504 ;
     RECT  58.889 20.592 59.069 21.192 ;
     RECT  58.061 15.168 59.101 17.064 ;
     RECT  58.673 18.192 59.101 19.512 ;
     RECT  58.421 6.816 59.105 6.984 ;
     RECT  59.101 15.168 59.177 19.512 ;
     RECT  59.033 12 59.245 12.504 ;
     RECT  59.173 22.176 59.269 22.2 ;
     RECT  58.673 23.904 59.269 23.928 ;
     RECT  59.033 10.848 59.285 10.872 ;
     RECT  58.957 3.84 59.321 5.736 ;
     RECT  59.177 17.616 59.321 19.512 ;
     RECT  56.704 1.728 59.353 2.28 ;
     RECT  59.269 22.176 59.393 23.928 ;
     RECT  59.365 25.008 59.509 25.08 ;
     RECT  59.393 23.328 59.537 23.928 ;
     RECT  59.509 25.008 59.681 25.752 ;
     RECT  59.245 12 59.789 12.6 ;
     RECT  59.681 25.056 59.845 25.752 ;
     RECT  59.321 18.624 59.857 19.512 ;
     RECT  59.069 20.592 59.857 21.144 ;
     RECT  59.353 1.152 59.897 2.28 ;
     RECT  59.177 15.168 59.897 16.44 ;
     RECT  59.897 16.08 60.005 16.44 ;
     RECT  59.105 6.816 60.041 6.888 ;
     RECT  59.857 18.624 60.149 21.144 ;
     RECT  60.149 21.072 60.229 21.144 ;
     RECT  59.321 4.224 60.289 5.736 ;
     RECT  60.041 6.816 60.289 6.84 ;
     RECT  60.289 4.224 60.373 6.84 ;
     RECT  60.229 10.272 60.397 10.296 ;
     RECT  60.373 3.696 60.419 6.84 ;
     RECT  60.229 21.072 60.721 21.48 ;
     RECT  60.149 18.624 60.803 19.992 ;
     RECT  59.897 1.728 60.973 2.28 ;
     RECT  60.419 3.696 60.973 3.72 ;
     RECT  59.537 23.376 60.997 23.928 ;
     RECT  60.397 10.272 61.009 10.92 ;
     RECT  59.845 25.056 61.189 25.8 ;
     RECT  61.189 24.96 61.331 25.8 ;
     RECT  61.331 24.96 61.379 25.704 ;
     RECT  60.721 21.072 61.381 21.672 ;
     RECT  61.381 21.072 61.429 21.72 ;
     RECT  60.997 22.8 61.429 23.928 ;
     RECT  61.429 21.072 61.573 23.928 ;
     RECT  61.379 24.96 61.573 25.176 ;
     RECT  59.321 17.616 61.621 17.64 ;
     RECT  60.803 18.624 61.621 19.656 ;
     RECT  59.789 12 61.669 12.504 ;
     RECT  60.997 14.016 61.669 14.04 ;
     RECT  61.621 17.616 61.669 19.656 ;
     RECT  61.669 12 61.801 14.04 ;
     RECT  60.253 15.024 61.801 15.048 ;
     RECT  60.973 1.728 61.808 3.72 ;
     RECT  60.419 5.184 61.808 6.84 ;
     RECT  61.009 10.128 61.808 10.92 ;
     RECT  61.801 12 61.808 15.048 ;
     RECT  60.005 16.08 61.808 16.392 ;
     RECT  61.669 17.376 61.808 19.656 ;
     RECT  61.573 21.072 61.808 25.176 ;
     RECT  61.808 1.728 62.104 25.176 ;
     RECT  62.104 14.112 62.129 25.176 ;
     RECT  62.104 5.424 62.483 6.12 ;
     RECT  62.129 17.616 62.513 25.176 ;
     RECT  62.104 3.696 62.597 4.44 ;
     RECT  62.513 17.616 62.705 25.8 ;
     RECT  62.129 14.112 62.921 16.536 ;
     RECT  62.705 17.616 62.957 23.976 ;
     RECT  62.921 14.832 63.1 16.536 ;
     RECT  63.1 14.832 63.245 15.24 ;
     RECT  62.104 8.688 63.253 8.712 ;
     RECT  62.104 9.696 63.253 10.92 ;
     RECT  63.253 8.688 63.277 10.92 ;
     RECT  63.245 14.928 63.281 15.24 ;
     RECT  62.957 17.616 63.299 23.4 ;
     RECT  62.483 5.568 63.313 6.12 ;
     RECT  63.277 8.688 63.461 10.968 ;
     RECT  63.1 16.272 63.493 16.536 ;
     RECT  63.299 17.616 63.493 19.368 ;
     RECT  63.461 9.264 63.685 10.968 ;
     RECT  62.104 12.24 63.685 12.504 ;
     RECT  63.685 9.264 63.772 12.504 ;
     RECT  63.313 5.568 63.853 6.216 ;
     RECT  62.104 1.728 63.877 2.28 ;
     RECT  63.493 16.272 63.893 19.368 ;
     RECT  62.705 25.104 63.98 25.8 ;
     RECT  63.98 25.008 64.069 25.8 ;
     RECT  63.299 20.352 64.124 23.4 ;
     RECT  64.069 24.912 64.153 25.8 ;
     RECT  63.281 15.216 64.213 15.24 ;
     RECT  63.772 12.24 64.249 12.504 ;
     RECT  63.781 7.92 64.253 7.944 ;
     RECT  63.772 9.264 64.307 10.968 ;
     RECT  64.249 12.24 64.393 12.744 ;
     RECT  63.893 16.512 64.453 19.368 ;
     RECT  64.124 20.352 64.453 23.496 ;
     RECT  64.153 25.056 64.577 25.8 ;
     RECT  64.453 16.512 64.645 23.496 ;
     RECT  64.393 12.24 64.681 13.128 ;
     RECT  62.597 4.416 64.717 4.44 ;
     RECT  64.213 15.216 64.717 15.528 ;
     RECT  64.717 3.984 64.757 4.44 ;
     RECT  64.717 15.12 64.861 15.528 ;
     RECT  64.645 16.512 64.861 23.928 ;
     RECT  64.681 12.24 64.981 13.992 ;
     RECT  64.981 12 65.041 13.992 ;
     RECT  64.861 15.12 65.041 23.928 ;
     RECT  64.757 3.984 65.185 4.056 ;
     RECT  65.041 12 65.333 23.928 ;
     RECT  63.853 5.568 65.401 6.312 ;
     RECT  65.041 7.488 65.401 7.512 ;
     RECT  64.307 10.32 65.401 10.968 ;
     RECT  65.185 3.888 65.441 4.056 ;
     RECT  65.401 5.568 65.509 7.512 ;
     RECT  65.441 3.984 65.513 4.056 ;
     RECT  65.333 13.104 65.549 23.928 ;
     RECT  64.307 9.264 65.581 9.288 ;
     RECT  65.509 5.568 65.617 7.944 ;
     RECT  65.549 13.104 65.621 14.952 ;
     RECT  64.577 25.056 65.701 25.704 ;
     RECT  65.617 5.136 65.725 7.944 ;
     RECT  65.581 9.12 65.725 9.288 ;
     RECT  65.401 10.32 65.725 11.016 ;
     RECT  65.333 12 65.725 12.024 ;
     RECT  65.701 25.056 65.801 25.8 ;
     RECT  65.725 5.136 65.837 9.288 ;
     RECT  65.837 9.264 65.905 9.288 ;
     RECT  65.725 10.32 65.905 12.024 ;
     RECT  65.837 5.136 65.945 8.184 ;
     RECT  65.945 5.136 65.981 7.512 ;
     RECT  65.801 25.056 66.131 25.752 ;
     RECT  65.549 15.984 66.181 23.928 ;
     RECT  66.181 15.984 66.349 24.552 ;
     RECT  66.349 15.984 66.377 24.504 ;
     RECT  66.377 15.984 66.449 24.456 ;
     RECT  63.877 1.728 66.469 2.328 ;
     RECT  65.513 3.984 66.481 4.008 ;
     RECT  66.469 1.68 66.565 2.328 ;
     RECT  66.565 1.68 66.593 2.568 ;
     RECT  66.593 1.728 66.661 2.568 ;
     RECT  66.131 25.728 67.045 25.752 ;
     RECT  66.661 1.728 67.208 2.904 ;
     RECT  66.481 3.984 67.208 4.152 ;
     RECT  65.981 5.28 67.208 7.512 ;
     RECT  65.905 9.264 67.208 12.024 ;
     RECT  65.621 13.104 67.208 13.128 ;
     RECT  65.621 14.4 67.208 14.952 ;
     RECT  66.449 15.984 67.208 23.928 ;
     RECT  67.045 25.728 67.385 25.8 ;
     RECT  67.385 25.728 67.417 25.752 ;
     RECT  67.208 1.728 67.504 23.928 ;
     RECT  66.997 0.144 67.619 0.168 ;
     RECT  67.504 1.728 67.777 2.904 ;
     RECT  67.504 8.88 67.817 13.128 ;
     RECT  67.777 1.104 67.955 2.904 ;
     RECT  67.504 14.4 68.033 23.928 ;
     RECT  67.417 25.056 68.195 25.752 ;
     RECT  68.033 19.056 68.213 23.928 ;
     RECT  67.504 3.936 68.501 7.752 ;
     RECT  67.817 10.224 68.501 13.128 ;
     RECT  68.317 0.096 68.531 0.12 ;
     RECT  67.955 1.728 68.573 2.904 ;
     RECT  68.213 20.4 68.677 23.928 ;
     RECT  68.195 25.056 68.677 25.08 ;
     RECT  68.501 5.28 68.713 7.752 ;
     RECT  67.817 8.88 68.713 8.904 ;
     RECT  68.713 5.28 68.857 8.904 ;
     RECT  68.501 10.224 68.857 12.936 ;
     RECT  68.501 3.936 68.861 4.248 ;
     RECT  68.033 14.4 68.929 18.024 ;
     RECT  68.929 13.92 69.145 18.024 ;
     RECT  68.213 19.056 69.145 19.416 ;
     RECT  68.677 20.4 69.245 25.08 ;
     RECT  68.861 3.936 69.253 3.96 ;
     RECT  69.145 13.92 69.397 19.416 ;
     RECT  69.245 20.4 69.397 25.8 ;
     RECT  68.573 1.728 69.541 2.328 ;
     RECT  69.397 13.92 69.545 25.8 ;
     RECT  69.545 13.92 69.553 24.024 ;
     RECT  68.857 5.28 69.617 12.936 ;
     RECT  69.541 1.392 69.637 2.328 ;
     RECT  69.253 3.456 69.637 3.96 ;
     RECT  69.553 13.92 69.724 20.04 ;
     RECT  69.545 25.056 69.941 25.8 ;
     RECT  69.617 12 70.076 12.936 ;
     RECT  69.724 13.92 70.076 19.992 ;
     RECT  69.617 5.28 70.189 10.344 ;
     RECT  70.076 12 70.193 19.992 ;
     RECT  69.637 1.392 70.301 3.96 ;
     RECT  69.941 25.776 70.481 25.8 ;
     RECT  70.189 5.04 70.657 10.344 ;
     RECT  69.553 21.456 70.693 24.024 ;
     RECT  70.657 4.704 70.733 10.344 ;
     RECT  70.193 15.456 70.933 19.992 ;
     RECT  70.193 12 71.269 14.136 ;
     RECT  70.693 21.456 71.269 24.504 ;
     RECT  70.301 1.392 71.309 3.72 ;
     RECT  70.933 15.456 71.341 20.04 ;
     RECT  71.269 21.36 71.365 24.504 ;
     RECT  71.341 15.456 71.449 20.28 ;
     RECT  71.365 21.36 71.449 24.552 ;
     RECT  71.269 11.664 71.485 14.136 ;
     RECT  71.449 15.456 71.557 24.552 ;
     RECT  70.981 25.728 71.557 25.752 ;
     RECT  69.925 0.096 71.621 0.12 ;
     RECT  71.485 11.424 71.629 14.136 ;
     RECT  71.557 15.456 71.629 25.752 ;
     RECT  71.629 11.424 71.633 25.752 ;
     RECT  71.621 0.096 71.665 0.168 ;
     RECT  70.733 4.704 71.701 8.952 ;
     RECT  70.733 10.272 71.701 10.344 ;
     RECT  71.633 11.424 71.741 23.976 ;
     RECT  71.633 25.056 71.845 25.752 ;
     RECT  71.701 4.704 71.948 10.344 ;
     RECT  71.741 11.424 71.948 23.928 ;
     RECT  71.309 1.392 72.608 3.144 ;
     RECT  71.948 4.704 72.608 23.928 ;
     RECT  71.665 0.048 72.755 0.168 ;
     RECT  71.845 25.056 72.755 25.8 ;
     RECT  72.608 1.392 72.904 23.928 ;
     RECT  72.904 10.512 73.001 23.928 ;
     RECT  72.904 1.392 73.037 8.856 ;
     RECT  73.001 14.832 73.045 23.928 ;
     RECT  72.755 25.632 73.153 25.8 ;
     RECT  73.045 14.832 73.189 23.976 ;
     RECT  73.189 14.832 73.217 24.504 ;
     RECT  73.153 25.68 73.793 25.8 ;
     RECT  73.001 10.512 74.113 13.848 ;
     RECT  73.217 14.832 74.213 20.568 ;
     RECT  73.217 21.552 74.213 24.504 ;
     RECT  74.113 10.368 74.473 13.848 ;
     RECT  74.213 14.832 74.473 24.504 ;
     RECT  72.755 0.048 74.513 0.12 ;
     RECT  73.037 5.568 74.533 8.856 ;
     RECT  73.037 1.392 74.653 4.296 ;
     RECT  74.533 5.28 74.653 8.856 ;
     RECT  74.653 1.392 74.689 9.336 ;
     RECT  74.473 10.368 74.689 24.504 ;
     RECT  74.689 1.392 74.725 24.504 ;
     RECT  74.725 1.392 74.953 24.552 ;
     RECT  74.953 5.184 74.963 24.552 ;
     RECT  73.793 25.776 75.013 25.8 ;
     RECT  74.963 5.184 75.133 23.928 ;
     RECT  75.133 5.184 75.161 21.672 ;
     RECT  75.161 5.184 75.305 13.944 ;
     RECT  75.133 22.704 75.449 23.928 ;
     RECT  75.161 15.36 75.827 21.672 ;
     RECT  75.449 23.76 75.853 23.928 ;
     RECT  75.449 22.704 76.019 22.776 ;
     RECT  75.827 15.36 76.097 21.096 ;
     RECT  76.097 15.36 76.129 21 ;
     RECT  75.013 25.056 76.165 25.8 ;
     RECT  75.853 23.808 76.229 23.928 ;
     RECT  76.165 24.96 76.229 25.8 ;
     RECT  75.305 10.176 76.453 13.944 ;
     RECT  76.129 15.024 76.453 21 ;
     RECT  74.513 0.048 76.549 0.072 ;
     RECT  75.305 5.184 76.597 9.192 ;
     RECT  76.453 10.176 76.597 21 ;
     RECT  76.229 23.808 76.637 25.8 ;
     RECT  76.549 0.048 76.691 0.312 ;
     RECT  76.597 5.184 76.781 21 ;
     RECT  76.691 0.048 76.787 0.12 ;
     RECT  76.637 23.808 76.837 24.504 ;
     RECT  76.837 23.616 76.889 24.504 ;
     RECT  76.889 23.616 77.029 23.928 ;
     RECT  74.953 1.392 77.177 4.2 ;
     RECT  77.177 1.488 77.209 4.2 ;
     RECT  76.781 5.184 77.209 10.392 ;
     RECT  76.637 25.728 77.285 25.8 ;
     RECT  76.781 11.904 77.461 21 ;
     RECT  76.933 22.032 77.461 22.056 ;
     RECT  77.285 25.728 77.507 25.752 ;
     RECT  77.209 1.488 78.008 10.392 ;
     RECT  77.461 11.904 78.008 22.056 ;
     RECT  77.029 23.376 78.008 23.928 ;
     RECT  78.008 1.488 78.277 23.928 ;
     RECT  78.277 1.488 78.304 24.504 ;
     RECT  78.304 23.04 78.565 24.504 ;
     RECT  78.304 1.488 78.707 21.144 ;
     RECT  76.787 0.048 78.709 0.072 ;
     RECT  78.709 0.048 78.757 0.168 ;
     RECT  78.707 1.488 78.833 20.952 ;
     RECT  78.757 0.048 78.899 0.36 ;
     RECT  78.899 0.048 79.121 0.072 ;
     RECT  78.833 1.488 79.229 4.152 ;
     RECT  78.833 5.136 79.265 20.712 ;
     RECT  78.565 23.04 79.325 25.08 ;
     RECT  79.325 23.04 79.369 25.8 ;
     RECT  79.369 23.04 79.429 25.896 ;
     RECT  79.265 5.76 79.813 20.712 ;
     RECT  79.429 22.224 79.813 25.896 ;
     RECT  79.813 5.76 79.841 25.896 ;
     RECT  79.841 11.136 79.913 25.896 ;
     RECT  79.841 5.76 80.003 10.152 ;
     RECT  79.229 1.728 80.561 4.152 ;
     RECT  80.561 1.728 80.633 4.104 ;
     RECT  80.003 5.808 80.881 10.152 ;
     RECT  79.913 11.28 80.881 25.896 ;
     RECT  80.633 1.728 80.957 3.432 ;
     RECT  80.881 5.808 81.389 25.896 ;
     RECT  81.389 6.24 81.569 25.896 ;
     RECT  80.957 1.728 81.997 3 ;
     RECT  81.569 6.336 82.433 25.896 ;
     RECT  82.433 6.336 82.789 10.968 ;
     RECT  82.885 5.184 82.933 5.208 ;
     RECT  82.933 5.088 83.077 5.208 ;
     RECT  83.221 0.336 83.269 0.36 ;
     RECT  81.997 1.728 83.269 3.336 ;
     RECT  83.269 0.192 83.324 0.456 ;
     RECT  83.269 1.728 83.408 3.96 ;
     RECT  83.077 5.088 83.408 5.256 ;
     RECT  82.789 6.288 83.408 10.968 ;
     RECT  82.433 11.952 83.408 25.896 ;
     RECT  83.324 0.096 83.411 0.456 ;
     RECT  83.411 0.336 83.507 0.456 ;
     RECT  83.408 1.728 83.699 25.896 ;
     RECT  83.699 1.728 83.704 23.592 ;
     RECT  83.507 0.432 83.795 0.456 ;
     RECT  83.699 24.624 83.795 25.896 ;
     RECT  83.704 6.336 83.891 23.592 ;
     RECT  83.704 1.728 83.909 4.008 ;
     RECT  83.909 1.728 83.981 3.96 ;
     RECT  83.704 5.184 84.197 5.256 ;
     RECT  83.981 1.728 84.233 3.72 ;
     RECT  83.795 25.104 84.305 25.896 ;
     RECT  84.373 0.576 84.467 0.6 ;
     RECT  84.197 5.232 84.521 5.256 ;
     RECT  83.891 6.336 84.557 22.632 ;
     RECT  84.557 6.336 84.659 22.248 ;
     RECT  84.233 1.728 84.809 2.904 ;
     RECT  84.659 6.336 84.809 22.104 ;
     RECT  84.305 25.104 84.947 25.752 ;
     RECT  84.913 23.952 84.949 23.976 ;
     RECT  84.947 25.104 84.949 25.224 ;
     RECT  84.949 23.952 85.021 25.224 ;
     RECT  85.021 23.904 85.489 25.224 ;
     RECT  84.809 1.728 85.523 2.856 ;
     RECT  85.489 4.464 85.561 4.488 ;
     RECT  85.489 23.712 85.811 25.224 ;
     RECT  85.561 3.984 85.859 4.488 ;
     RECT  85.811 25.104 86.053 25.224 ;
     RECT  84.809 6.336 86.101 13.032 ;
     RECT  84.809 14.064 86.101 22.104 ;
     RECT  86.021 0.576 86.105 0.6 ;
     RECT  85.859 4.464 86.105 4.488 ;
     RECT  86.101 6.336 86.149 22.104 ;
     RECT  85.811 23.712 86.149 24.024 ;
     RECT  86.149 6.336 86.285 24.024 ;
     RECT  85.523 1.728 86.291 2.28 ;
     RECT  86.291 1.728 86.579 1.848 ;
     RECT  86.285 6.336 86.579 22.104 ;
     RECT  86.629 1.104 86.789 1.128 ;
     RECT  86.579 6.336 86.789 9.816 ;
     RECT  86.579 10.992 86.969 22.104 ;
     RECT  86.053 25.104 86.969 25.8 ;
     RECT  86.929 5.136 87.077 5.16 ;
     RECT  86.969 10.992 87.149 14.184 ;
     RECT  86.285 23.328 87.173 24.024 ;
     RECT  86.969 25.104 87.173 25.752 ;
     RECT  87.173 23.328 87.349 25.752 ;
     RECT  87.149 10.992 87.437 13.032 ;
     RECT  87.437 12.144 87.509 13.032 ;
     RECT  86.789 8.784 87.613 9.816 ;
     RECT  86.969 15.408 87.721 22.104 ;
     RECT  87.349 23.088 87.721 25.752 ;
     RECT  87.509 12.144 87.725 12.888 ;
     RECT  87.613 8.784 87.793 9.864 ;
     RECT  87.437 10.992 87.793 11.016 ;
     RECT  87.149 14.16 88.657 14.184 ;
     RECT  87.721 15.408 88.657 25.752 ;
     RECT  87.793 8.784 88.729 11.016 ;
     RECT  87.725 12.144 88.729 12.792 ;
     RECT  88.657 14.16 88.787 25.752 ;
     RECT  86.789 6.336 88.808 7.752 ;
     RECT  88.729 8.784 88.808 12.792 ;
     RECT  88.787 14.16 88.808 24.984 ;
     RECT  88.808 2.148 88.883 24.984 ;
     RECT  88.883 2.148 88.912 24.936 ;
     RECT  88.912 2.418 89.104 24.936 ;
     RECT  89.104 6.336 89.219 16.632 ;
     RECT  89.104 17.664 90.133 24.936 ;
     RECT  89.219 6.336 90.281 16.584 ;
     RECT  90.133 17.664 90.361 25.128 ;
     RECT  90.373 25.776 90.497 25.8 ;
     RECT  90.281 11.712 90.601 16.584 ;
     RECT  90.361 17.664 90.601 24.6 ;
     RECT  90.281 6.336 90.605 10.584 ;
     RECT  90.601 11.712 90.899 24.6 ;
     RECT  90.899 11.712 91.253 24.552 ;
     RECT  90.605 8.736 91.465 10.584 ;
     RECT  91.465 8.736 92.221 10.776 ;
     RECT  91.253 12.24 92.221 24.552 ;
     RECT  92.005 25.776 92.221 25.8 ;
     RECT  92.221 8.736 92.945 11.256 ;
     RECT  92.221 12.24 92.981 25.8 ;
     RECT  92.981 12.816 93.125 25.8 ;
     RECT  93.125 16.416 93.161 25.8 ;
     RECT  92.945 8.784 93.481 11.256 ;
     RECT  93.161 16.464 93.971 25.08 ;
     RECT  93.971 25.008 94.025 25.08 ;
     RECT  93.125 12.816 94.129 15.432 ;
     RECT  93.971 16.464 94.129 24.024 ;
     RECT  90.605 6.336 94.208 7.752 ;
     RECT  93.481 8.784 94.208 11.448 ;
     RECT  94.129 12.816 94.208 24.024 ;
     RECT  94.025 25.056 94.213 25.08 ;
     RECT  94.208 2.148 94.312 24.024 ;
     RECT  94.213 25.056 94.373 25.128 ;
     RECT  94.312 2.418 94.504 24.024 ;
     RECT  94.504 10.416 94.673 12.36 ;
     RECT  94.373 25.056 94.933 25.8 ;
     RECT  94.673 10.416 95.069 12.024 ;
     RECT  94.504 14.832 95.501 24.024 ;
     RECT  94.933 25.056 95.845 25.752 ;
     RECT  94.504 13.824 95.852 13.848 ;
     RECT  95.852 13.632 95.893 13.848 ;
     RECT  95.501 14.832 95.893 23.496 ;
     RECT  95.893 13.632 95.939 23.496 ;
     RECT  95.845 24.528 95.941 25.752 ;
     RECT  95.069 10.848 95.969 12.024 ;
     RECT  95.969 10.848 96.113 11.88 ;
     RECT  95.941 24.528 96.221 25.8 ;
     RECT  96.113 11.232 96.437 11.88 ;
     RECT  95.939 14.112 96.517 23.496 ;
     RECT  96.221 24.528 96.517 25.08 ;
     RECT  96.437 11.232 96.869 11.256 ;
     RECT  96.517 14.112 96.905 25.08 ;
     RECT  94.504 6.336 97.189 7.752 ;
     RECT  94.504 8.784 97.229 8.856 ;
     RECT  97.189 6.24 97.481 7.752 ;
     RECT  97.481 6.24 97.553 7.224 ;
     RECT  97.553 6.24 97.733 6.264 ;
     RECT  96.905 24.528 97.873 25.08 ;
     RECT  97.229 8.832 97.877 8.856 ;
     RECT  97.873 24.48 97.909 25.08 ;
     RECT  96.905 14.112 97.981 23.4 ;
     RECT  97.909 24.48 97.981 25.128 ;
     RECT  97.981 14.112 98.017 25.128 ;
     RECT  98.017 14.112 98.237 25.176 ;
     RECT  98.053 13.104 98.273 13.128 ;
     RECT  98.237 16.368 98.305 25.176 ;
     RECT  98.305 16.368 98.675 25.224 ;
     RECT  98.237 14.112 98.881 15.24 ;
     RECT  98.881 13.2 99.608 15.24 ;
     RECT  98.675 16.368 99.608 25.176 ;
     RECT  99.608 2.148 99.712 25.176 ;
     RECT  99.712 2.418 99.904 25.176 ;
     RECT  99.904 23.616 99.925 25.176 ;
     RECT  99.904 14.16 100.001 14.712 ;
     RECT  100.001 14.256 100.577 14.712 ;
     RECT  99.925 23.616 101.005 25.8 ;
     RECT  100.577 14.352 101.113 14.712 ;
     RECT  99.904 15.744 101.113 22.104 ;
     RECT  101.113 14.352 101.225 22.104 ;
     RECT  101.225 14.688 101.513 22.104 ;
     RECT  101.513 15.264 102.085 22.104 ;
     RECT  101.005 23.376 102.085 25.8 ;
     RECT  102.085 23.28 102.233 25.8 ;
     RECT  102.233 23.28 102.449 25.752 ;
     RECT  102.085 15.264 102.467 22.2 ;
     RECT  102.467 19.248 102.589 22.2 ;
     RECT  102.449 23.28 102.589 25.176 ;
     RECT  102.589 19.248 102.701 25.176 ;
     RECT  102.467 15.264 102.769 18.072 ;
     RECT  102.701 19.488 102.803 25.176 ;
     RECT  102.769 14.736 102.845 18.072 ;
     RECT  102.845 14.736 102.881 14.76 ;
     RECT  102.803 19.488 103.061 22.296 ;
     RECT  102.803 23.28 103.187 25.176 ;
     RECT  102.845 16.128 103.205 18.072 ;
     RECT  103.205 17.76 103.277 18.072 ;
     RECT  103.205 16.128 103.385 16.344 ;
     RECT  103.385 16.32 103.457 16.344 ;
     RECT  103.277 17.76 103.493 17.976 ;
     RECT  103.493 17.76 103.565 17.928 ;
     RECT  103.061 19.488 103.565 19.512 ;
     RECT  103.061 20.64 103.637 22.296 ;
     RECT  103.637 20.688 103.781 22.296 ;
     RECT  103.781 21.168 104.317 22.296 ;
     RECT  103.187 23.376 104.317 25.176 ;
     RECT  103.565 17.904 105.008 17.928 ;
     RECT  104.317 21.168 105.008 25.176 ;
     RECT  105.008 2.148 105.112 25.176 ;
     RECT  105.112 2.418 105.157 25.176 ;
     RECT  105.157 2.418 105.304 25.752 ;
     RECT  105.304 21.168 106.013 22.248 ;
     RECT  106.013 21.168 106.193 21.24 ;
     RECT  105.304 23.376 106.289 25.752 ;
     RECT  106.289 23.376 106.373 25.8 ;
     RECT  106.013 22.224 106.405 22.248 ;
     RECT  106.373 23.376 106.405 25.752 ;
     RECT  105.304 17.904 106.643 18.84 ;
     RECT  106.405 22.224 106.739 25.752 ;
     RECT  106.477 20.544 106.801 21.144 ;
     RECT  106.643 17.904 107.057 17.928 ;
     RECT  107.221 19.248 107.309 19.272 ;
     RECT  106.801 20.304 107.309 21.144 ;
     RECT  106.739 22.224 107.507 23.496 ;
     RECT  107.309 20.544 107.603 21.144 ;
     RECT  107.603 20.544 107.699 20.568 ;
     RECT  106.739 24.576 107.773 25.752 ;
     RECT  107.507 22.224 107.795 22.824 ;
     RECT  107.795 22.32 107.891 22.824 ;
     RECT  107.773 24.528 108.179 25.752 ;
     RECT  108.179 25.104 108.197 25.752 ;
     RECT  108.565 12.336 108.652 12.36 ;
     RECT  108.313 23.952 108.659 23.976 ;
     RECT  108.673 19.392 108.853 19.416 ;
     RECT  108.853 19.392 108.908 19.944 ;
     RECT  108.908 18.528 108.94 19.944 ;
     RECT  108.94 18.528 108.947 19.416 ;
     RECT  108.947 18.528 108.995 18.552 ;
     RECT  109.429 20.496 109.532 20.52 ;
     RECT  108.197 25.104 109.573 25.8 ;
     RECT  109.573 25.056 109.721 25.8 ;
     RECT  109.465 17.568 110.005 17.592 ;
     RECT  109.964 18.576 110.005 18.6 ;
     RECT  107.891 22.8 110.005 22.824 ;
     RECT  109.645 23.952 110.005 23.976 ;
     RECT  110.005 22.8 110.099 23.976 ;
     RECT  110.005 17.568 110.108 18.6 ;
     RECT  109.532 20.496 110.185 20.76 ;
     RECT  110.099 22.8 110.293 23.928 ;
     RECT  110.108 17.568 110.408 19.416 ;
     RECT  110.185 20.496 110.408 21.144 ;
     RECT  110.293 22.224 110.408 23.928 ;
     RECT  110.408 2.148 110.512 23.928 ;
     RECT  109.721 25.056 110.617 25.752 ;
     RECT  110.512 2.418 110.704 23.928 ;
     RECT  110.704 21.12 110.867 22.824 ;
     RECT  110.704 18.768 110.873 18.792 ;
     RECT  110.617 25.008 110.905 25.752 ;
     RECT  110.704 16.656 110.915 17.496 ;
     RECT  110.915 17.088 110.963 17.496 ;
     RECT  110.905 25.008 110.989 25.8 ;
     RECT  110.963 17.088 111.059 17.112 ;
     RECT  110.867 21.648 111.107 22.824 ;
     RECT  111.085 23.952 111.229 24.024 ;
     RECT  110.989 25.008 111.229 25.752 ;
     RECT  110.704 15.216 111.305 15.384 ;
     RECT  111.229 23.952 111.443 25.752 ;
     RECT  111.305 15.36 111.565 15.384 ;
     RECT  111.443 24 111.635 25.752 ;
     RECT  111.635 24 111.731 25.176 ;
     RECT  111.107 22.752 111.923 22.824 ;
     RECT  111.731 24.528 112.019 25.176 ;
     RECT  111.733 20.544 112.115 20.568 ;
     RECT  112.019 25.008 112.307 25.176 ;
     RECT  112.307 25.056 112.403 25.176 ;
     RECT  112.345 17.088 112.429 17.112 ;
     RECT  111.923 22.8 112.499 22.824 ;
     RECT  111.107 21.648 112.595 21.72 ;
     RECT  112.595 21.696 112.691 21.72 ;
     RECT  112.403 25.056 112.787 25.08 ;
    LAYER M5 ;
     RECT  35.28 0.016 86.664 1.139 ;
     RECT  35.28 1.139 86.568 1.475 ;
     RECT  35.28 1.475 48.264 1.763 ;
     RECT  49.392 1.475 86.568 1.763 ;
     RECT  35.28 1.763 38.28 1.811 ;
     RECT  58.512 1.763 86.568 1.811 ;
     RECT  39.696 1.763 48.168 1.859 ;
     RECT  58.608 1.811 86.568 1.859 ;
     RECT  35.28 1.811 38.184 2.051 ;
     RECT  35.28 2.051 35.304 2.099 ;
     RECT  49.392 1.763 51.312 2.147 ;
     RECT  58.608 1.859 86.28 2.147 ;
     RECT  2.4 2.137 2.52 2.151 ;
     RECT  7.8 2.137 7.92 2.151 ;
     RECT  13.2 2.137 13.32 2.151 ;
     RECT  18.6 2.137 18.72 2.151 ;
     RECT  24 2.137 24.12 2.151 ;
     RECT  29.4 2.137 29.52 2.151 ;
     RECT  88.8 2.137 88.92 2.151 ;
     RECT  94.2 2.137 94.32 2.151 ;
     RECT  99.6 2.137 99.72 2.151 ;
     RECT  105 2.137 105.12 2.151 ;
     RECT  110.4 2.137 110.52 2.151 ;
     RECT  65.424 2.147 86.28 2.195 ;
     RECT  43.344 1.859 48.168 2.243 ;
     RECT  58.608 2.147 64.2 2.243 ;
     RECT  65.424 2.195 80.616 2.243 ;
     RECT  36.816 2.051 38.184 2.291 ;
     RECT  39.696 1.859 41.832 2.291 ;
     RECT  43.344 2.243 47.304 2.291 ;
     RECT  49.392 2.147 49.416 2.291 ;
     RECT  52.464 1.763 57.48 2.291 ;
     RECT  58.608 2.243 59.016 2.291 ;
     RECT  60.048 2.243 63.912 2.291 ;
     RECT  65.424 2.243 67.848 2.291 ;
     RECT  69.264 2.243 80.616 2.291 ;
     RECT  81.936 2.195 86.28 2.291 ;
     RECT  43.344 2.291 47.112 2.339 ;
     RECT  63.888 2.291 63.912 2.339 ;
     RECT  39.888 2.291 41.256 2.387 ;
     RECT  71.376 2.291 80.616 2.531 ;
     RECT  66.576 2.291 67.608 2.579 ;
     RECT  43.344 2.339 46.824 2.867 ;
     RECT  81.936 2.291 85.848 2.867 ;
     RECT  43.344 2.867 43.368 2.915 ;
     RECT  66.672 2.579 67.608 2.915 ;
     RECT  71.376 2.531 76.68 2.915 ;
     RECT  78 2.531 80.616 2.963 ;
     RECT  81.936 2.867 84.552 2.963 ;
     RECT  71.472 2.915 76.584 3.059 ;
     RECT  69.264 2.291 69.864 3.155 ;
     RECT  44.976 2.867 46.824 3.443 ;
     RECT  71.76 3.059 76.584 3.443 ;
     RECT  78 2.963 80.376 3.443 ;
     RECT  69.264 3.155 69.288 3.491 ;
     RECT  71.76 3.443 75.816 3.491 ;
     RECT  52.464 2.291 52.488 3.925 ;
     RECT  67.2 2.915 67.512 3.925 ;
     RECT  52.32 3.925 52.488 4.019 ;
     RECT  71.76 3.491 75 4.019 ;
     RECT  85.824 2.867 85.848 4.019 ;
     RECT  37.2 2.291 37.608 4.067 ;
     RECT  60.384 3.685 60.408 4.259 ;
     RECT  56.304 2.291 57 4.261 ;
     RECT  61.8 2.291 62.112 4.405 ;
     RECT  56.304 4.261 57.624 4.451 ;
     RECT  40.2 2.387 41.256 4.501 ;
     RECT  44.976 3.443 46.44 4.931 ;
     RECT  74.544 4.019 75 5.219 ;
     RECT  67.2 3.925 68.184 5.269 ;
     RECT  74.544 5.219 74.568 5.315 ;
     RECT  67.2 5.269 68.52 5.411 ;
     RECT  43.296 4.501 43.32 5.459 ;
     RECT  61.8 4.405 62.472 5.459 ;
     RECT  56.4 4.451 57.624 5.555 ;
     RECT  51 2.147 51.312 5.605 ;
     RECT  40.2 4.501 42.168 5.747 ;
     RECT  52.32 4.019 52.344 5.747 ;
     RECT  68.496 5.411 68.52 5.747 ;
     RECT  78 3.443 79.368 5.749 ;
     RECT  31.392 5.461 31.416 6.131 ;
     RECT  18.6 2.151 18.912 6.133 ;
     RECT  17.616 6.133 18.912 6.181 ;
     RECT  37.2 4.067 37.224 6.229 ;
     RECT  78 5.749 79.992 6.277 ;
     RECT  44.976 4.931 46.008 6.323 ;
     RECT  82.8 2.963 84.552 6.323 ;
     RECT  45.6 6.323 46.008 6.325 ;
     RECT  82.992 6.323 84.552 6.419 ;
     RECT  17.616 6.181 19.752 6.565 ;
     RECT  78 6.277 80.232 6.709 ;
     RECT  78 6.709 80.424 6.755 ;
     RECT  34.8 2.137 35.112 6.805 ;
     RECT  40.2 5.747 40.512 6.805 ;
     RECT  42.144 5.747 42.168 6.805 ;
     RECT  56.4 5.555 56.712 6.805 ;
     RECT  71.76 4.019 72.912 6.805 ;
     RECT  50.496 5.605 51.312 6.851 ;
     RECT  80.4 6.755 80.424 7.093 ;
     RECT  76.32 6.757 76.344 7.331 ;
     RECT  38.736 7.093 38.76 7.333 ;
     RECT  56.4 6.805 57.624 7.379 ;
     RECT  80.4 7.093 80.952 7.379 ;
     RECT  71.76 6.805 73.608 7.427 ;
     RECT  14.496 6.325 14.52 7.475 ;
     RECT  42.144 6.805 42.936 7.475 ;
     RECT  45.6 6.325 46.104 7.525 ;
     RECT  13.2 2.151 13.512 7.669 ;
     RECT  17.424 6.565 19.752 7.765 ;
     RECT  45.6 7.525 46.296 7.765 ;
     RECT  83.28 6.419 84.552 7.811 ;
     RECT  37.2 6.229 37.56 7.955 ;
     RECT  40.2 6.805 40.728 8.051 ;
     RECT  43.2 8.197 43.224 8.339 ;
     RECT  83.4 7.811 84.552 8.437 ;
     RECT  56.4 7.379 56.712 8.485 ;
     RECT  76.608 7.957 76.632 8.485 ;
     RECT  81.312 7.669 81.336 8.485 ;
     RECT  34.8 6.805 35.88 8.771 ;
     RECT  81.312 8.485 81.528 8.915 ;
     RECT  42.144 7.475 42.168 8.965 ;
     RECT  40.2 8.051 40.632 9.059 ;
     RECT  94.2 2.151 94.512 9.061 ;
     RECT  42 8.965 42.168 9.107 ;
     RECT  38.592 7.333 38.76 9.109 ;
     RECT  40.2 9.059 40.512 9.109 ;
     RECT  75.888 8.485 76.632 9.203 ;
     RECT  83.4 8.437 85.416 9.251 ;
     RECT  63.792 7.909 63.816 9.253 ;
     RECT  63.264 9.253 63.816 9.299 ;
     RECT  87.36 6.805 87.384 9.397 ;
     RECT  44.544 8.293 44.568 9.539 ;
     RECT  45.6 7.765 46.728 9.539 ;
     RECT  38.592 9.109 40.512 9.683 ;
     RECT  54.096 8.581 54.12 9.731 ;
     RECT  63.264 9.299 63.288 9.731 ;
     RECT  93.264 9.061 94.512 9.779 ;
     RECT  42.144 9.107 42.168 9.827 ;
     RECT  83.4 9.251 84.552 9.925 ;
     RECT  86.544 9.397 87.384 10.165 ;
     RECT  88.8 2.151 89.112 10.165 ;
     RECT  60.24 4.789 60.264 10.307 ;
     RECT  64.272 10.165 64.296 10.309 ;
     RECT  71.76 7.427 72.912 10.309 ;
     RECT  65.856 6.805 65.88 10.355 ;
     RECT  16.848 7.765 19.752 10.403 ;
     RECT  56.4 8.485 57.336 10.595 ;
     RECT  83.232 9.925 84.552 10.643 ;
     RECT  34.8 8.771 35.112 10.741 ;
     RECT  31.584 9.541 31.608 10.883 ;
     RECT  69.024 10.741 69.048 10.883 ;
     RECT  38.592 9.683 38.616 10.981 ;
     RECT  39.888 9.683 40.512 10.981 ;
     RECT  86.544 10.165 89.112 10.981 ;
     RECT  90.144 9.013 90.168 10.981 ;
     RECT  86.544 10.981 90.168 11.027 ;
     RECT  69.456 11.173 69.48 11.315 ;
     RECT  64.272 10.309 64.44 11.365 ;
     RECT  76.608 9.203 76.632 11.365 ;
     RECT  94.032 9.779 94.512 11.459 ;
     RECT  37.2 7.955 37.224 11.507 ;
     RECT  81.504 8.915 81.528 11.651 ;
     RECT  12.336 7.669 13.512 11.653 ;
     RECT  38.592 10.981 40.512 11.653 ;
     RECT  44.448 10.741 44.472 11.699 ;
     RECT  38.112 11.653 40.512 11.939 ;
     RECT  12.336 11.653 13.704 11.941 ;
     RECT  63.696 11.365 64.44 11.989 ;
     RECT  78 6.755 79.368 11.989 ;
     RECT  87.36 11.027 87.384 11.989 ;
     RECT  76.32 11.365 76.632 12.035 ;
     RECT  76.608 12.035 76.632 12.085 ;
     RECT  78 11.989 79.8 12.085 ;
     RECT  63.696 11.989 65.016 12.275 ;
     RECT  0.192 5.413 0.216 12.323 ;
     RECT  61.8 5.459 62.112 12.325 ;
     RECT  76.608 12.085 79.8 12.419 ;
     RECT  11.088 5.989 11.112 12.469 ;
     RECT  34.8 10.741 35.784 12.469 ;
     RECT  64.416 12.275 65.016 12.515 ;
     RECT  68.976 12.373 69 12.515 ;
     RECT  33.84 12.469 35.784 12.517 ;
     RECT  43.536 12.181 43.56 12.563 ;
     RECT  10.896 12.469 11.112 12.853 ;
     RECT  37.056 12.517 37.08 12.901 ;
     RECT  38.112 11.939 39.096 12.901 ;
     RECT  76.608 12.419 76.632 12.995 ;
     RECT  51 6.851 51.312 13.045 ;
     RECT  57.792 12.901 57.816 13.045 ;
     RECT  83.4 10.643 84.552 13.045 ;
     RECT  37.056 12.901 39.096 13.091 ;
     RECT  31.824 12.469 31.848 13.093 ;
     RECT  64.416 12.515 64.44 13.139 ;
     RECT  88.8 11.027 90.168 13.139 ;
     RECT  33.84 12.517 35.88 13.189 ;
     RECT  33.84 13.189 36.984 13.523 ;
     RECT  71.664 10.309 72.912 13.573 ;
     RECT  38.112 13.091 39.096 13.621 ;
     RECT  40.2 11.939 40.512 13.621 ;
     RECT  50.688 13.045 51.864 13.715 ;
     RECT  57.792 13.045 57.912 13.715 ;
     RECT  36.96 13.523 36.984 13.763 ;
     RECT  49.392 13.477 49.416 13.813 ;
     RECT  50.688 13.715 51.312 13.813 ;
     RECT  42.48 12.901 42.504 13.907 ;
     RECT  31.824 13.093 32.328 14.003 ;
     RECT  61.68 12.325 62.112 14.005 ;
     RECT  49.392 13.813 51.312 14.051 ;
     RECT  70.128 13.573 70.152 14.147 ;
     RECT  95.904 13.621 95.928 14.147 ;
     RECT  83.4 13.045 84.696 14.197 ;
     RECT  88.8 13.139 89.208 14.197 ;
     RECT  29.4 2.151 29.712 14.245 ;
     RECT  45.6 9.539 45.912 14.245 ;
     RECT  55.296 13.573 55.32 14.291 ;
     RECT  67.2 5.411 67.512 14.389 ;
     RECT  67.2 14.389 68.088 14.485 ;
     RECT  24 2.151 24.312 14.629 ;
     RECT  99.6 2.151 99.912 14.677 ;
     RECT  15.6 13.861 15.624 14.773 ;
     RECT  48.816 14.101 48.84 14.773 ;
     RECT  71.664 13.573 73.896 14.773 ;
     RECT  74.88 12.469 74.904 14.773 ;
     RECT  27.504 13.045 27.528 14.819 ;
     RECT  38.112 13.621 40.512 14.821 ;
     RECT  61.008 14.005 62.112 14.821 ;
     RECT  88.8 14.197 89.832 14.821 ;
     RECT  71.664 14.773 74.904 14.867 ;
     RECT  98.4 14.341 98.424 14.867 ;
     RECT  56.4 10.595 56.712 14.869 ;
     RECT  67.104 14.485 68.088 14.915 ;
     RECT  37.68 14.821 40.512 14.963 ;
     RECT  61.008 14.821 62.376 15.059 ;
     RECT  24 14.629 25.128 15.061 ;
     RECT  28.992 14.245 29.712 15.061 ;
     RECT  31.824 14.003 31.848 15.061 ;
     RECT  48.576 14.773 48.84 15.109 ;
     RECT  44.304 13.621 44.328 15.203 ;
     RECT  110.4 2.151 110.712 15.205 ;
     RECT  21.456 14.197 21.48 15.301 ;
     RECT  78 12.419 79.8 15.301 ;
     RECT  81.36 14.533 81.384 15.347 ;
     RECT  74.688 14.867 74.904 15.349 ;
     RECT  96.864 14.725 96.888 15.349 ;
     RECT  110.4 15.205 111.288 15.349 ;
     RECT  15.408 14.773 15.624 15.397 ;
     RECT  16.848 10.403 18.912 15.397 ;
     RECT  45.6 14.245 46.104 15.397 ;
     RECT  78 15.301 80.184 15.397 ;
     RECT  83.4 14.197 84.744 15.397 ;
     RECT  86.832 11.989 87.384 15.397 ;
     RECT  88.8 14.821 90.072 15.443 ;
     RECT  83.4 15.397 84.84 15.493 ;
     RECT  38.304 14.963 40.512 15.539 ;
     RECT  78 15.397 80.28 15.635 ;
     RECT  48.192 15.109 48.84 15.733 ;
     RECT  15.408 15.397 18.912 15.973 ;
     RECT  52.896 15.925 52.92 15.973 ;
     RECT  54.768 14.773 54.792 15.973 ;
     RECT  38.304 15.539 39 16.019 ;
     RECT  78 15.635 80.184 16.019 ;
     RECT  96.528 15.349 96.888 16.019 ;
     RECT  33.84 13.523 35.88 16.021 ;
     RECT  67.104 14.915 67.656 16.021 ;
     RECT  68.736 15.445 68.76 16.021 ;
     RECT  72.6 14.867 72.912 16.021 ;
     RECT  83.4 15.493 85.128 16.021 ;
     RECT  86.64 15.397 87.384 16.021 ;
     RECT  45.6 15.397 46.536 16.069 ;
     RECT  38.784 16.019 39 16.163 ;
     RECT  61.8 15.059 62.376 16.165 ;
     RECT  83.4 16.021 87.384 16.165 ;
     RECT  71.328 15.685 71.352 16.213 ;
     RECT  99.6 14.677 100.872 16.259 ;
     RECT  67.104 16.021 68.76 16.261 ;
     RECT  61.8 16.165 63.048 16.309 ;
     RECT  72.6 16.021 73.128 16.357 ;
     RECT  56.016 14.869 56.712 16.405 ;
     RECT  57.792 13.715 57.816 16.405 ;
     RECT  54.336 15.973 55.032 16.453 ;
     RECT  65.136 15.349 65.16 16.453 ;
     RECT  66.768 16.261 68.76 16.453 ;
     RECT  71.328 16.213 71.4 16.453 ;
     RECT  43.872 15.685 43.896 16.501 ;
     RECT  45.36 16.069 46.536 16.501 ;
     RECT  49.92 14.051 51.312 16.501 ;
     RECT  52.656 15.973 52.92 16.501 ;
     RECT  94.2 11.459 94.512 16.501 ;
     RECT  48.096 15.733 48.84 16.547 ;
     RECT  31.728 15.061 31.848 16.549 ;
     RECT  43.872 16.501 46.536 16.549 ;
     RECT  74.688 15.349 75 16.549 ;
     RECT  33.456 16.021 35.88 16.595 ;
     RECT  65.136 16.453 68.76 16.741 ;
     RECT  65.136 16.741 69.096 16.789 ;
     RECT  70.512 16.453 71.4 16.789 ;
     RECT  99.6 16.259 100.824 16.883 ;
     RECT  43.872 16.549 47.16 16.931 ;
     RECT  74.688 16.549 75.528 16.933 ;
     RECT  49.92 16.501 52.92 16.981 ;
     RECT  54.048 16.453 55.032 16.981 ;
     RECT  56.016 16.405 57.816 16.981 ;
     RECT  90.96 16.597 90.984 16.981 ;
     RECT  78 16.019 79.368 17.029 ;
     RECT  94.2 16.501 94.92 17.029 ;
     RECT  96.528 16.019 96.552 17.029 ;
     RECT  23.664 15.061 25.128 17.075 ;
     RECT  26.16 16.837 26.184 17.075 ;
     RECT  23.664 17.075 24.312 17.077 ;
     RECT  27.264 15.685 27.288 17.077 ;
     RECT  40.2 15.539 40.512 17.077 ;
     RECT  65.136 16.789 71.4 17.077 ;
     RECT  83.28 16.165 87.384 17.077 ;
     RECT  88.8 15.443 89.832 17.077 ;
     RECT  90.96 16.981 91.032 17.077 ;
     RECT  93.456 17.029 94.92 17.077 ;
     RECT  110.4 15.349 111.528 17.077 ;
     RECT  26.688 17.077 27.288 17.123 ;
     RECT  33.84 16.595 35.88 17.123 ;
     RECT  37.008 16.981 37.032 17.123 ;
     RECT  64.704 17.077 71.4 17.123 ;
     RECT  72.6 16.357 73.368 17.125 ;
     RECT  96.048 17.029 96.552 17.125 ;
     RECT  38.784 16.163 38.856 17.173 ;
     RECT  43.872 16.931 46.68 17.173 ;
     RECT  74.688 16.933 75.912 17.221 ;
     RECT  83.088 17.077 87.384 17.267 ;
     RECT  42.144 15.973 42.168 17.269 ;
     RECT  42.144 17.269 42.312 17.317 ;
     RECT  90.912 17.077 91.032 17.317 ;
     RECT  78 17.029 80.184 17.411 ;
     RECT  71.376 17.123 71.4 17.461 ;
     RECT  72.6 17.125 73.464 17.461 ;
     RECT  79.344 17.411 80.184 17.461 ;
     RECT  96.048 17.125 96.888 17.461 ;
     RECT  98.064 15.733 98.088 17.461 ;
     RECT  90.912 17.317 91.512 17.509 ;
     RECT  92.736 17.077 94.92 17.509 ;
     RECT  42.048 17.317 42.312 17.557 ;
     RECT  108.576 12.325 108.6 17.557 ;
     RECT  110.4 17.077 112.392 17.557 ;
     RECT  31.632 16.549 31.848 17.605 ;
     RECT  71.376 17.461 73.464 17.605 ;
     RECT  74.688 17.221 75.96 17.605 ;
     RECT  88.704 17.077 89.832 17.605 ;
     RECT  90.912 17.509 94.92 17.605 ;
     RECT  12.24 11.941 13.704 17.653 ;
     RECT  15.12 15.973 18.912 17.653 ;
     RECT  61.584 16.309 63.048 17.653 ;
     RECT  64.704 17.123 70.008 17.653 ;
     RECT  88.704 17.605 94.92 17.653 ;
     RECT  96.048 17.461 98.088 17.653 ;
     RECT  88.704 17.653 98.088 17.699 ;
     RECT  42.048 17.557 42.36 17.701 ;
     RECT  43.824 17.173 46.68 17.701 ;
     RECT  102.048 17.077 102.072 17.843 ;
     RECT  39.984 17.077 40.512 17.941 ;
     RECT  38.592 17.173 38.856 18.037 ;
     RECT  23.52 17.077 24.312 18.085 ;
     RECT  78 17.411 78.312 18.085 ;
     RECT  71.376 17.605 75.96 18.181 ;
     RECT  79.344 17.461 80.328 18.227 ;
     RECT  31.632 17.605 32.712 18.229 ;
     RECT  49.92 16.981 57.816 18.275 ;
     RECT  23.376 18.085 24.312 18.277 ;
     RECT  42.048 17.701 46.68 18.373 ;
     RECT  31.296 18.229 32.712 18.419 ;
     RECT  38.592 18.037 38.904 18.419 ;
     RECT  23.376 18.277 25.224 18.421 ;
     RECT  26.688 17.123 26.712 18.467 ;
     RECT  39.984 17.941 40.632 18.467 ;
     RECT  20.976 15.301 21.48 18.565 ;
     RECT  42.048 18.373 46.968 18.613 ;
     RECT  48.192 16.547 48.84 18.613 ;
     RECT  40.032 18.467 40.632 18.661 ;
     RECT  28.992 15.061 30.12 18.709 ;
     RECT  31.296 18.419 31.848 18.709 ;
     RECT  83.4 17.267 87.384 18.709 ;
     RECT  88.704 17.699 97.416 18.709 ;
     RECT  61.584 17.653 70.008 18.757 ;
     RECT  71.184 18.181 75.96 18.757 ;
     RECT  28.992 18.709 30.216 18.805 ;
     RECT  23.376 18.421 25.656 18.851 ;
     RECT  42.048 18.613 48.84 18.949 ;
     RECT  49.92 18.275 56.712 18.949 ;
     RECT  82.224 17.653 82.248 18.949 ;
     RECT  83.4 18.709 97.416 18.949 ;
     RECT  42.048 18.949 56.712 19.045 ;
     RECT  106.608 18.805 106.632 19.237 ;
     RECT  38.88 18.419 38.904 19.283 ;
     RECT  82.224 18.949 97.416 19.331 ;
     RECT  40.032 18.661 40.776 19.333 ;
     RECT  41.76 19.045 56.712 19.333 ;
     RECT  20.976 18.565 21.672 19.381 ;
     RECT  20.688 19.381 21.672 19.427 ;
     RECT  24 18.851 25.656 19.427 ;
     RECT  28.896 18.805 30.216 19.427 ;
     RECT  79.344 18.227 79.368 19.427 ;
     RECT  81.072 18.709 81.096 19.427 ;
     RECT  83.4 19.331 97.416 19.427 ;
     RECT  102.432 18.805 102.456 19.427 ;
     RECT  57.792 18.275 57.816 19.477 ;
     RECT  40.032 19.333 56.712 19.907 ;
     RECT  40.08 19.907 56.712 19.909 ;
     RECT  57.792 19.477 58.248 19.909 ;
     RECT  61.248 18.757 75.96 19.909 ;
     RECT  77.904 18.085 78.312 19.909 ;
     RECT  61.248 19.909 76.104 19.957 ;
     RECT  88.704 19.427 97.416 19.957 ;
     RECT  77.904 19.909 78.696 20.005 ;
     RECT  99.6 16.883 99.912 20.053 ;
     RECT  88.704 19.957 97.512 20.147 ;
     RECT  33.84 17.123 35.784 20.149 ;
     RECT  99.216 20.053 99.912 20.195 ;
     RECT  60.384 19.957 76.104 20.293 ;
     RECT  77.568 20.005 78.696 20.293 ;
     RECT  22.704 19.381 22.728 20.437 ;
     RECT  22.608 20.437 22.728 20.485 ;
     RECT  88.704 20.147 97.416 20.531 ;
     RECT  82.224 19.331 82.248 20.533 ;
     RECT  106.608 19.237 107.256 20.533 ;
     RECT  108.576 17.557 112.392 20.533 ;
     RECT  40.08 19.909 58.248 20.579 ;
     RECT  88.704 20.531 96.936 20.725 ;
     RECT  88.656 20.725 96.936 20.821 ;
     RECT  60.384 20.293 78.696 20.867 ;
     RECT  60.384 20.867 76.008 20.869 ;
     RECT  28.896 19.427 30.12 21.061 ;
     RECT  88.608 20.821 96.936 21.109 ;
     RECT  77.472 20.867 78.696 21.155 ;
     RECT  83.4 19.427 87.384 21.155 ;
     RECT  88.368 21.109 96.936 21.155 ;
     RECT  28.848 21.061 30.12 21.157 ;
     RECT  88.368 21.155 95.544 21.299 ;
     RECT  28.464 21.157 30.12 21.397 ;
     RECT  31.248 18.709 31.848 21.397 ;
     RECT  40.08 20.579 57.816 21.491 ;
     RECT  82.128 20.533 82.248 21.541 ;
     RECT  26.64 21.349 26.664 21.637 ;
     RECT  106.608 20.533 112.392 21.637 ;
     RECT  96.768 21.155 96.936 21.683 ;
     RECT  106.608 21.637 112.584 21.685 ;
     RECT  96.768 21.683 96.792 21.827 ;
     RECT  81.696 21.541 82.248 21.973 ;
     RECT  59.52 20.869 76.008 22.021 ;
     RECT  77.472 21.155 78.312 22.021 ;
     RECT  99.6 20.195 99.912 22.021 ;
     RECT  28.464 21.397 31.848 22.069 ;
     RECT  20.688 19.427 21.576 22.165 ;
     RECT  22.608 20.485 22.824 22.165 ;
     RECT  59.52 22.021 78.312 22.165 ;
     RECT  79.824 21.253 79.848 22.213 ;
     RECT  86.256 21.155 87.384 22.213 ;
     RECT  88.368 21.299 95.304 22.213 ;
     RECT  105 2.151 105.312 22.213 ;
     RECT  40.08 21.491 56.856 22.259 ;
     RECT  26.64 21.637 26.76 22.261 ;
     RECT  28.368 22.069 31.848 22.261 ;
     RECT  103.824 22.213 103.848 22.261 ;
     RECT  105 22.213 105.432 22.261 ;
     RECT  86.256 22.213 95.304 22.453 ;
     RECT  10.8 12.853 11.112 22.501 ;
     RECT  12.24 17.653 18.912 22.501 ;
     RECT  40.2 22.259 56.856 22.549 ;
     RECT  98.832 22.021 99.912 22.693 ;
     RECT  20.688 22.165 22.824 22.741 ;
     RECT  24 19.427 25.224 22.741 ;
     RECT  81.216 21.973 82.248 22.741 ;
     RECT  83.4 21.155 85.128 22.741 ;
     RECT  98.256 22.693 99.912 22.741 ;
     RECT  59.184 22.165 78.312 22.787 ;
     RECT  79.44 22.213 79.848 22.789 ;
     RECT  81.216 22.741 85.128 22.789 ;
     RECT  86.256 22.453 95.784 22.789 ;
     RECT  98.064 22.741 99.912 22.789 ;
     RECT  102.096 22.165 102.12 22.789 ;
     RECT  76.848 22.787 78.312 23.029 ;
     RECT  79.44 22.789 85.128 23.029 ;
     RECT  102.096 22.789 102.792 23.269 ;
     RECT  103.824 22.261 105.432 23.269 ;
     RECT  97.68 22.789 99.912 23.317 ;
     RECT  20.688 22.741 25.224 23.365 ;
     RECT  26.64 22.261 31.848 23.365 ;
     RECT  33.84 20.149 36.264 23.365 ;
     RECT  38.736 22.069 38.76 23.365 ;
     RECT  40.2 22.549 57.528 23.365 ;
     RECT  86.16 22.789 95.784 23.365 ;
     RECT  102.096 23.269 105.432 23.365 ;
     RECT  106.608 21.685 112.68 23.365 ;
     RECT  20.688 23.365 38.856 23.413 ;
     RECT  86.16 23.365 96.456 23.557 ;
     RECT  97.584 23.317 99.912 23.557 ;
     RECT  86.16 23.557 99.912 23.605 ;
     RECT  101.136 23.365 112.68 23.605 ;
     RECT  10.8 22.501 18.912 23.653 ;
     RECT  20.688 23.413 39.048 23.653 ;
     RECT  40.2 23.365 57.576 23.701 ;
     RECT  76.848 23.029 85.128 23.701 ;
     RECT  86.16 23.605 112.68 23.701 ;
     RECT  59.184 22.787 75.24 23.749 ;
     RECT  2.4 2.151 2.712 23.769 ;
     RECT  7.8 2.151 8.112 23.769 ;
     RECT  2.4 23.769 2.52 23.783 ;
     RECT  7.8 23.769 7.92 23.783 ;
     RECT  59.184 23.749 75.816 23.797 ;
     RECT  76.848 23.701 112.68 23.797 ;
     RECT  40.2 23.701 58.056 23.893 ;
     RECT  59.184 23.797 112.68 23.893 ;
     RECT  40.2 23.893 112.68 23.941 ;
     RECT  10.8 23.653 39.048 24.517 ;
     RECT  40.176 23.941 112.68 24.517 ;
     RECT  10.8 24.517 112.68 25.045 ;
     RECT  10.8 25.045 112.776 25.765 ;
     RECT  10.608 25.765 112.776 25.872 ;
     RECT  10.608 25.872 10.632 25.907 ;
     RECT  48.264 1.475 49.392 1.763 ;
     RECT  38.28 1.763 39.696 1.811 ;
     RECT  48.168 1.763 49.392 2.243 ;
     RECT  51.312 1.763 52.464 3.925 ;
     RECT  57.48 1.763 58.512 1.811 ;
     RECT  38.184 1.811 39.696 2.291 ;
     RECT  57.48 1.811 58.608 2.291 ;
     RECT  41.832 1.859 43.344 2.291 ;
     RECT  35.304 2.051 36.816 2.099 ;
     RECT  64.2 2.147 65.424 2.243 ;
     RECT  80.616 2.195 81.936 2.963 ;
     RECT  59.016 2.243 60.048 2.291 ;
     RECT  63.912 2.243 65.424 2.291 ;
     RECT  67.848 2.243 69.264 2.291 ;
     RECT  60.384 2.291 61.8 3.685 ;
     RECT  69.864 2.291 71.376 2.915 ;
     RECT  76.68 2.531 78 2.915 ;
     RECT  84.552 2.867 85.824 4.019 ;
     RECT  67.512 2.915 67.608 3.925 ;
     RECT  76.584 2.915 78 3.443 ;
     RECT  60.408 3.685 61.8 4.259 ;
     RECT  51.312 3.925 52.32 5.747 ;
     RECT  42.168 4.501 43.296 5.459 ;
     RECT  46.008 4.931 46.104 6.325 ;
     RECT  67.512 5.411 68.496 5.747 ;
     RECT  42.168 5.459 42.936 6.805 ;
     RECT  56.712 5.555 57.624 6.805 ;
     RECT  40.512 5.747 42.144 6.805 ;
     RECT  13.512 6.325 14.496 7.475 ;
     RECT  79.368 6.755 80.4 7.379 ;
     RECT  35.88 6.805 37.2 8.771 ;
     RECT  40.728 6.805 42.144 8.051 ;
     RECT  65.88 6.805 67.2 10.355 ;
     RECT  87.384 6.805 88.8 10.165 ;
     RECT  37.56 7.093 38.736 7.333 ;
     RECT  38.76 7.093 40.2 9.109 ;
     RECT  76.32 7.331 76.344 7.957 ;
     RECT  37.56 7.333 38.592 7.955 ;
     RECT  56.712 7.379 57.336 8.485 ;
     RECT  42.168 7.475 42.936 8.197 ;
     RECT  11.112 7.669 12.336 11.941 ;
     RECT  37.224 7.955 38.592 11.507 ;
     RECT  76.32 7.957 76.608 8.485 ;
     RECT  76.632 7.957 78 12.085 ;
     RECT  40.632 8.051 42.144 8.965 ;
     RECT  42.168 8.197 43.2 8.339 ;
     RECT  43.224 8.293 44.544 8.339 ;
     RECT  44.568 8.293 45.6 9.539 ;
     RECT  40.632 8.965 42 9.059 ;
     RECT  89.112 9.013 90.144 10.981 ;
     RECT  40.512 9.059 42 9.107 ;
     RECT  62.112 9.253 63.264 9.731 ;
     RECT  44.544 9.539 45.6 10.741 ;
     RECT  38.616 9.683 39.888 10.981 ;
     RECT  64.44 10.309 65.856 10.355 ;
     RECT  35.784 10.741 37.2 11.507 ;
     RECT  44.472 10.741 45.6 11.699 ;
     RECT  67.512 10.741 69.024 10.883 ;
     RECT  67.512 10.883 69.048 11.173 ;
     RECT  86.832 11.027 87.36 11.989 ;
     RECT  87.384 11.027 88.8 17.077 ;
     RECT  67.512 11.173 69.456 11.315 ;
     RECT  67.512 11.315 69 12.373 ;
     RECT  35.784 11.507 38.592 11.653 ;
     RECT  35.784 11.653 38.112 12.517 ;
     RECT  39.096 11.939 40.2 13.621 ;
     RECT  11.112 11.941 12.24 22.501 ;
     RECT  67.512 12.373 68.976 12.515 ;
     RECT  76.632 12.419 78 12.995 ;
     RECT  35.88 12.517 37.056 13.091 ;
     RECT  37.08 12.517 38.112 12.901 ;
     RECT  56.712 12.901 57.792 16.405 ;
     RECT  35.88 13.091 38.112 13.189 ;
     RECT  32.328 13.093 33.84 14.003 ;
     RECT  89.208 13.139 89.832 14.197 ;
     RECT  36.984 13.189 38.112 13.763 ;
     RECT  49.416 13.477 50.688 13.813 ;
     RECT  35.88 13.523 36.96 13.763 ;
     RECT  55.32 13.573 56.4 14.291 ;
     RECT  70.152 13.573 71.664 14.147 ;
     RECT  73.896 13.573 74.88 14.773 ;
     RECT  44.328 13.621 45.6 15.203 ;
     RECT  94.512 13.621 95.904 14.147 ;
     RECT  37.68 13.763 38.112 14.821 ;
     RECT  15.624 13.861 16.848 15.397 ;
     RECT  49.392 14.051 49.92 14.101 ;
     RECT  48.84 14.101 49.92 18.949 ;
     RECT  27.528 14.245 28.992 14.819 ;
     RECT  55.296 14.291 56.4 14.773 ;
     RECT  98.424 14.341 99.6 14.867 ;
     RECT  96.888 14.725 98.4 14.867 ;
     RECT  54.792 14.773 56.4 14.869 ;
     RECT  71.664 14.867 72.6 15.685 ;
     RECT  72.912 14.867 74.688 16.021 ;
     RECT  96.888 14.867 99.6 15.733 ;
     RECT  54.792 14.869 56.016 15.973 ;
     RECT  67.656 14.915 68.088 15.445 ;
     RECT  61.584 15.059 61.8 16.309 ;
     RECT  44.304 15.203 45.6 15.685 ;
     RECT  80.184 15.301 81.36 15.347 ;
     RECT  80.184 15.347 80.28 15.397 ;
     RECT  89.832 15.443 90.072 16.597 ;
     RECT  67.656 15.445 68.736 16.021 ;
     RECT  85.128 15.493 86.64 16.021 ;
     RECT  39 15.539 40.2 16.163 ;
     RECT  43.896 15.685 45.6 16.069 ;
     RECT  71.352 15.685 72.6 16.213 ;
     RECT  96.888 15.733 98.064 16.019 ;
     RECT  98.088 15.733 99.6 17.699 ;
     RECT  13.704 15.973 15.12 17.653 ;
     RECT  51.312 15.973 52.656 16.501 ;
     RECT  52.92 15.973 54.336 16.453 ;
     RECT  55.032 15.973 56.016 16.981 ;
     RECT  38.592 16.019 38.784 17.173 ;
     RECT  79.368 16.019 80.184 17.029 ;
     RECT  96.552 16.019 98.064 17.125 ;
     RECT  73.128 16.021 74.688 16.357 ;
     RECT  43.896 16.069 45.36 16.501 ;
     RECT  38.856 16.163 40.2 17.077 ;
     RECT  71.4 16.213 72.6 17.461 ;
     RECT  73.368 16.357 74.688 17.125 ;
     RECT  52.92 16.453 54.048 16.981 ;
     RECT  48.096 16.547 48.192 16.549 ;
     RECT  30.12 16.549 31.632 18.229 ;
     RECT  47.16 16.549 48.192 16.931 ;
     RECT  33.456 16.595 33.84 17.605 ;
     RECT  89.832 16.597 90.96 17.077 ;
     RECT  69.096 16.741 70.512 16.789 ;
     RECT  25.128 16.837 26.16 17.075 ;
     RECT  26.184 16.837 27.264 17.075 ;
     RECT  46.68 16.931 48.192 18.373 ;
     RECT  35.88 16.981 37.008 17.123 ;
     RECT  94.92 17.029 96.048 17.653 ;
     RECT  24.312 17.075 27.264 17.077 ;
     RECT  24.312 17.077 26.688 18.277 ;
     RECT  38.856 17.077 39.984 18.037 ;
     RECT  87.384 17.077 88.704 18.709 ;
     RECT  89.832 17.077 90.912 17.605 ;
     RECT  70.008 17.123 71.376 18.181 ;
     RECT  73.464 17.125 74.688 17.605 ;
     RECT  96.888 17.125 98.064 17.461 ;
     RECT  83.088 17.267 83.4 17.653 ;
     RECT  42.312 17.269 43.824 17.557 ;
     RECT  91.512 17.317 92.736 17.509 ;
     RECT  78.312 17.411 79.344 19.427 ;
     RECT  42.36 17.557 43.824 17.701 ;
     RECT  32.712 17.605 33.84 18.419 ;
     RECT  82.248 17.653 83.4 18.949 ;
     RECT  40.632 17.941 42.048 18.661 ;
     RECT  38.904 18.037 39.984 18.467 ;
     RECT  70.008 18.181 71.184 18.757 ;
     RECT  30.12 18.229 31.296 18.709 ;
     RECT  56.712 18.275 57.792 19.909 ;
     RECT  25.224 18.277 26.688 18.421 ;
     RECT  46.968 18.373 48.192 18.613 ;
     RECT  25.656 18.421 26.688 18.467 ;
     RECT  38.904 18.467 40.032 19.283 ;
     RECT  40.776 18.661 42.048 19.045 ;
     RECT  30.216 18.709 31.248 19.427 ;
     RECT  81.096 18.709 82.224 19.427 ;
     RECT  105.312 18.805 106.608 22.213 ;
     RECT  23.376 18.851 24 19.381 ;
     RECT  40.776 19.045 41.76 19.333 ;
     RECT  107.256 19.237 108.576 20.533 ;
     RECT  82.248 19.331 83.4 22.741 ;
     RECT  21.672 19.381 22.704 19.427 ;
     RECT  22.728 19.381 24 20.485 ;
     RECT  21.576 19.427 22.704 20.437 ;
     RECT  30.12 19.427 31.248 21.397 ;
     RECT  78.312 19.427 78.696 19.909 ;
     RECT  82.128 19.427 82.224 20.533 ;
     RECT  87.384 19.427 88.704 20.725 ;
     RECT  76.104 20.005 77.568 20.293 ;
     RECT  21.576 20.437 22.608 22.165 ;
     RECT  22.824 20.485 24 22.741 ;
     RECT  87.384 20.725 88.656 20.821 ;
     RECT  87.384 20.821 88.608 21.109 ;
     RECT  76.008 20.867 77.472 22.021 ;
     RECT  87.384 21.109 88.368 22.213 ;
     RECT  78.312 21.155 78.696 21.253 ;
     RECT  85.128 21.155 86.256 22.789 ;
     RECT  95.544 21.155 96.768 21.299 ;
     RECT  78.312 21.253 79.824 22.213 ;
     RECT  95.304 21.299 96.768 21.827 ;
     RECT  25.224 21.349 26.64 23.365 ;
     RECT  56.856 21.491 57.528 22.549 ;
     RECT  95.304 21.827 95.784 22.453 ;
     RECT  79.848 21.973 81.216 22.789 ;
     RECT  38.76 22.069 40.08 22.259 ;
     RECT  78.312 22.213 79.44 23.029 ;
     RECT  103.848 22.213 105 22.261 ;
     RECT  105.432 22.213 106.608 23.365 ;
     RECT  38.76 22.259 40.2 23.365 ;
     RECT  75.24 22.787 76.848 23.749 ;
     RECT  85.128 22.789 86.16 23.701 ;
     RECT  102.792 22.789 103.824 23.269 ;
     RECT  38.856 23.365 40.2 23.413 ;
     RECT  96.456 23.365 97.584 23.557 ;
     RECT  99.912 23.365 101.136 23.605 ;
     RECT  39.048 23.413 40.2 23.941 ;
     RECT  58.056 23.701 59.184 23.893 ;
     RECT  75.816 23.749 76.848 23.797 ;
     RECT  39.048 23.941 40.176 24.517 ;
  END
END ot_qfd_vm_rr2_nx
END LIBRARY
